VERSION 5.8 ;
BUSBITCHARS "[]" ;
DIVIDERCHAR "/" ;
UNITS
    DATABASE MICRONS 1000 ;
END UNITS

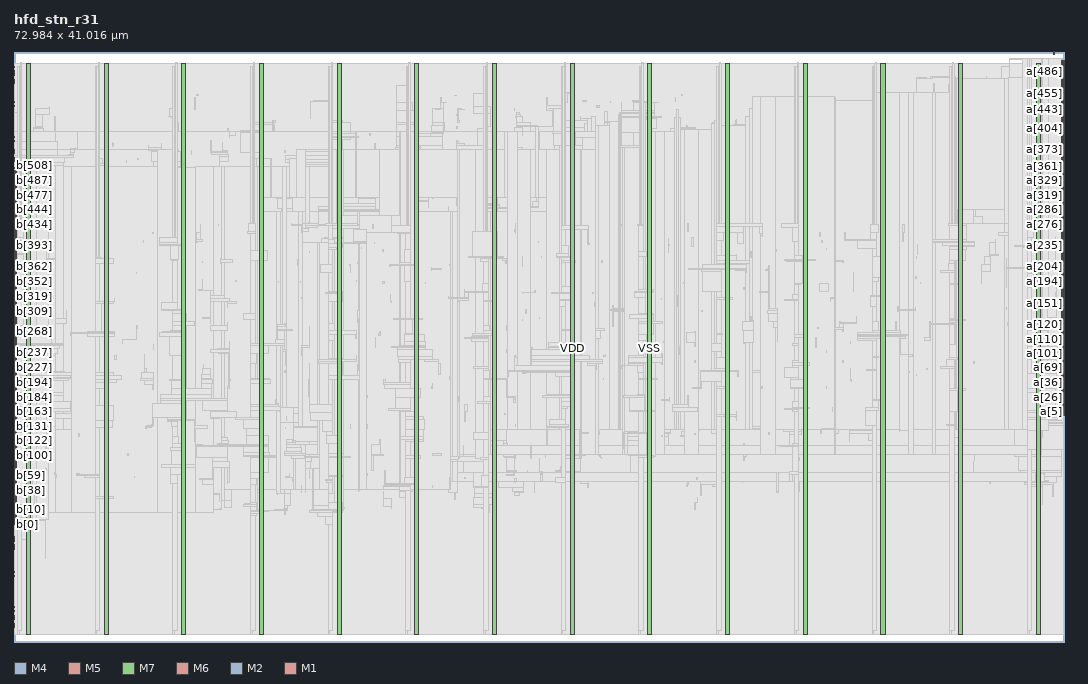
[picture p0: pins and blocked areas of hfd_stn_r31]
MACRO hfd_stn_r31
  FOREIGN hfd_stn_r31 0 0 ;
  CLASS BLOCK ;
  SIZE 72.984 BY 41.016 ;
  PIN a[0]
    DIRECTION INPUT ;
    USE SIGNAL ;
    PORT
      LAYER M4 ;
        RECT  72.792 15.744 72.984 15.768 ;
    END
  END a[0]
  PIN a[100]
    DIRECTION INPUT ;
    USE SIGNAL ;
    PORT
      LAYER M4 ;
        RECT  72.792 20.544 72.984 20.568 ;
    END
  END a[100]
  PIN a[101]
    DIRECTION INPUT ;
    USE SIGNAL ;
    PORT
      LAYER M4 ;
        RECT  72.792 20.592 72.984 20.616 ;
    END
  END a[101]
  PIN a[102]
    DIRECTION INPUT ;
    USE SIGNAL ;
    PORT
      LAYER M4 ;
        RECT  72.792 20.64 72.984 20.664 ;
    END
  END a[102]
  PIN a[103]
    DIRECTION INPUT ;
    USE SIGNAL ;
    PORT
      LAYER M4 ;
        RECT  72.792 20.688 72.984 20.712 ;
    END
  END a[103]
  PIN a[104]
    DIRECTION INPUT ;
    USE SIGNAL ;
    PORT
      LAYER M4 ;
        RECT  72.792 20.736 72.984 20.76 ;
    END
  END a[104]
  PIN a[105]
    DIRECTION INPUT ;
    USE SIGNAL ;
    PORT
      LAYER M4 ;
        RECT  72.792 20.784 72.984 20.808 ;
    END
  END a[105]
  PIN a[106]
    DIRECTION INPUT ;
    USE SIGNAL ;
    PORT
      LAYER M4 ;
        RECT  72.792 20.832 72.984 20.856 ;
    END
  END a[106]
  PIN a[107]
    DIRECTION INPUT ;
    USE SIGNAL ;
    PORT
      LAYER M4 ;
        RECT  72.792 20.88 72.984 20.904 ;
    END
  END a[107]
  PIN a[108]
    DIRECTION INPUT ;
    USE SIGNAL ;
    PORT
      LAYER M4 ;
        RECT  72.792 20.928 72.984 20.952 ;
    END
  END a[108]
  PIN a[109]
    DIRECTION INPUT ;
    USE SIGNAL ;
    PORT
      LAYER M4 ;
        RECT  72.792 20.976 72.984 21 ;
    END
  END a[109]
  PIN a[10]
    DIRECTION INPUT ;
    USE SIGNAL ;
    PORT
      LAYER M4 ;
        RECT  72.792 16.224 72.984 16.248 ;
    END
  END a[10]
  PIN a[110]
    DIRECTION INPUT ;
    USE SIGNAL ;
    PORT
      LAYER M4 ;
        RECT  72.792 21.024 72.984 21.048 ;
    END
  END a[110]
  PIN a[111]
    DIRECTION INPUT ;
    USE SIGNAL ;
    PORT
      LAYER M4 ;
        RECT  72.792 21.072 72.984 21.096 ;
    END
  END a[111]
  PIN a[112]
    DIRECTION INPUT ;
    USE SIGNAL ;
    PORT
      LAYER M4 ;
        RECT  72.792 21.12 72.984 21.144 ;
    END
  END a[112]
  PIN a[113]
    DIRECTION INPUT ;
    USE SIGNAL ;
    PORT
      LAYER M4 ;
        RECT  72.792 21.168 72.984 21.192 ;
    END
  END a[113]
  PIN a[114]
    DIRECTION INPUT ;
    USE SIGNAL ;
    PORT
      LAYER M4 ;
        RECT  72.792 21.216 72.984 21.24 ;
    END
  END a[114]
  PIN a[115]
    DIRECTION INPUT ;
    USE SIGNAL ;
    PORT
      LAYER M4 ;
        RECT  72.792 21.264 72.984 21.288 ;
    END
  END a[115]
  PIN a[116]
    DIRECTION INPUT ;
    USE SIGNAL ;
    PORT
      LAYER M4 ;
        RECT  72.792 21.312 72.984 21.336 ;
    END
  END a[116]
  PIN a[117]
    DIRECTION INPUT ;
    USE SIGNAL ;
    PORT
      LAYER M4 ;
        RECT  72.792 21.36 72.984 21.384 ;
    END
  END a[117]
  PIN a[118]
    DIRECTION INPUT ;
    USE SIGNAL ;
    PORT
      LAYER M4 ;
        RECT  72.792 21.408 72.984 21.432 ;
    END
  END a[118]
  PIN a[119]
    DIRECTION INPUT ;
    USE SIGNAL ;
    PORT
      LAYER M4 ;
        RECT  72.792 21.456 72.984 21.48 ;
    END
  END a[119]
  PIN a[11]
    DIRECTION INPUT ;
    USE SIGNAL ;
    PORT
      LAYER M4 ;
        RECT  72.792 16.272 72.984 16.296 ;
    END
  END a[11]
  PIN a[120]
    DIRECTION INPUT ;
    USE SIGNAL ;
    PORT
      LAYER M4 ;
        RECT  72.792 21.504 72.984 21.528 ;
    END
  END a[120]
  PIN a[121]
    DIRECTION INPUT ;
    USE SIGNAL ;
    PORT
      LAYER M4 ;
        RECT  72.792 21.552 72.984 21.576 ;
    END
  END a[121]
  PIN a[122]
    DIRECTION INPUT ;
    USE SIGNAL ;
    PORT
      LAYER M4 ;
        RECT  72.792 21.6 72.984 21.624 ;
    END
  END a[122]
  PIN a[123]
    DIRECTION INPUT ;
    USE SIGNAL ;
    PORT
      LAYER M4 ;
        RECT  72.792 21.648 72.984 21.672 ;
    END
  END a[123]
  PIN a[124]
    DIRECTION INPUT ;
    USE SIGNAL ;
    PORT
      LAYER M4 ;
        RECT  72.792 21.696 72.984 21.72 ;
    END
  END a[124]
  PIN a[125]
    DIRECTION INPUT ;
    USE SIGNAL ;
    PORT
      LAYER M4 ;
        RECT  72.792 21.744 72.984 21.768 ;
    END
  END a[125]
  PIN a[126]
    DIRECTION INPUT ;
    USE SIGNAL ;
    PORT
      LAYER M4 ;
        RECT  72.792 21.792 72.984 21.816 ;
    END
  END a[126]
  PIN a[127]
    DIRECTION INPUT ;
    USE SIGNAL ;
    PORT
      LAYER M4 ;
        RECT  72.792 21.84 72.984 21.864 ;
    END
  END a[127]
  PIN a[128]
    DIRECTION INPUT ;
    USE SIGNAL ;
    PORT
      LAYER M4 ;
        RECT  72.792 21.888 72.984 21.912 ;
    END
  END a[128]
  PIN a[129]
    DIRECTION INPUT ;
    USE SIGNAL ;
    PORT
      LAYER M4 ;
        RECT  72.792 21.936 72.984 21.96 ;
    END
  END a[129]
  PIN a[12]
    DIRECTION INPUT ;
    USE SIGNAL ;
    PORT
      LAYER M4 ;
        RECT  72.792 16.32 72.984 16.344 ;
    END
  END a[12]
  PIN a[130]
    DIRECTION INPUT ;
    USE SIGNAL ;
    PORT
      LAYER M4 ;
        RECT  72.792 21.984 72.984 22.008 ;
    END
  END a[130]
  PIN a[131]
    DIRECTION INPUT ;
    USE SIGNAL ;
    PORT
      LAYER M4 ;
        RECT  72.792 22.032 72.984 22.056 ;
    END
  END a[131]
  PIN a[132]
    DIRECTION INPUT ;
    USE SIGNAL ;
    PORT
      LAYER M4 ;
        RECT  72.792 22.08 72.984 22.104 ;
    END
  END a[132]
  PIN a[133]
    DIRECTION INPUT ;
    USE SIGNAL ;
    PORT
      LAYER M4 ;
        RECT  72.792 22.128 72.984 22.152 ;
    END
  END a[133]
  PIN a[134]
    DIRECTION INPUT ;
    USE SIGNAL ;
    PORT
      LAYER M4 ;
        RECT  72.792 22.176 72.984 22.2 ;
    END
  END a[134]
  PIN a[135]
    DIRECTION INPUT ;
    USE SIGNAL ;
    PORT
      LAYER M4 ;
        RECT  72.792 22.224 72.984 22.248 ;
    END
  END a[135]
  PIN a[136]
    DIRECTION INPUT ;
    USE SIGNAL ;
    PORT
      LAYER M4 ;
        RECT  72.792 22.272 72.984 22.296 ;
    END
  END a[136]
  PIN a[137]
    DIRECTION INPUT ;
    USE SIGNAL ;
    PORT
      LAYER M4 ;
        RECT  72.792 22.32 72.984 22.344 ;
    END
  END a[137]
  PIN a[138]
    DIRECTION INPUT ;
    USE SIGNAL ;
    PORT
      LAYER M4 ;
        RECT  72.792 22.368 72.984 22.392 ;
    END
  END a[138]
  PIN a[139]
    DIRECTION INPUT ;
    USE SIGNAL ;
    PORT
      LAYER M4 ;
        RECT  72.792 22.416 72.984 22.44 ;
    END
  END a[139]
  PIN a[13]
    DIRECTION INPUT ;
    USE SIGNAL ;
    PORT
      LAYER M4 ;
        RECT  72.792 16.368 72.984 16.392 ;
    END
  END a[13]
  PIN a[140]
    DIRECTION INPUT ;
    USE SIGNAL ;
    PORT
      LAYER M4 ;
        RECT  72.792 22.464 72.984 22.488 ;
    END
  END a[140]
  PIN a[141]
    DIRECTION INPUT ;
    USE SIGNAL ;
    PORT
      LAYER M4 ;
        RECT  72.792 22.512 72.984 22.536 ;
    END
  END a[141]
  PIN a[142]
    DIRECTION INPUT ;
    USE SIGNAL ;
    PORT
      LAYER M4 ;
        RECT  72.792 22.56 72.984 22.584 ;
    END
  END a[142]
  PIN a[143]
    DIRECTION INPUT ;
    USE SIGNAL ;
    PORT
      LAYER M4 ;
        RECT  72.792 22.608 72.984 22.632 ;
    END
  END a[143]
  PIN a[144]
    DIRECTION INPUT ;
    USE SIGNAL ;
    PORT
      LAYER M4 ;
        RECT  72.792 22.656 72.984 22.68 ;
    END
  END a[144]
  PIN a[145]
    DIRECTION INPUT ;
    USE SIGNAL ;
    PORT
      LAYER M4 ;
        RECT  72.792 22.704 72.984 22.728 ;
    END
  END a[145]
  PIN a[146]
    DIRECTION INPUT ;
    USE SIGNAL ;
    PORT
      LAYER M4 ;
        RECT  72.792 22.752 72.984 22.776 ;
    END
  END a[146]
  PIN a[147]
    DIRECTION INPUT ;
    USE SIGNAL ;
    PORT
      LAYER M4 ;
        RECT  72.792 22.8 72.984 22.824 ;
    END
  END a[147]
  PIN a[148]
    DIRECTION INPUT ;
    USE SIGNAL ;
    PORT
      LAYER M4 ;
        RECT  72.792 22.848 72.984 22.872 ;
    END
  END a[148]
  PIN a[149]
    DIRECTION INPUT ;
    USE SIGNAL ;
    PORT
      LAYER M4 ;
        RECT  72.792 22.896 72.984 22.92 ;
    END
  END a[149]
  PIN a[14]
    DIRECTION INPUT ;
    USE SIGNAL ;
    PORT
      LAYER M4 ;
        RECT  72.792 16.416 72.984 16.44 ;
    END
  END a[14]
  PIN a[150]
    DIRECTION INPUT ;
    USE SIGNAL ;
    PORT
      LAYER M4 ;
        RECT  72.792 22.944 72.984 22.968 ;
    END
  END a[150]
  PIN a[151]
    DIRECTION INPUT ;
    USE SIGNAL ;
    PORT
      LAYER M4 ;
        RECT  72.792 22.992 72.984 23.016 ;
    END
  END a[151]
  PIN a[152]
    DIRECTION INPUT ;
    USE SIGNAL ;
    PORT
      LAYER M4 ;
        RECT  72.792 23.04 72.984 23.064 ;
    END
  END a[152]
  PIN a[153]
    DIRECTION INPUT ;
    USE SIGNAL ;
    PORT
      LAYER M4 ;
        RECT  72.792 23.088 72.984 23.112 ;
    END
  END a[153]
  PIN a[154]
    DIRECTION INPUT ;
    USE SIGNAL ;
    PORT
      LAYER M4 ;
        RECT  72.792 23.136 72.984 23.16 ;
    END
  END a[154]
  PIN a[155]
    DIRECTION INPUT ;
    USE SIGNAL ;
    PORT
      LAYER M4 ;
        RECT  72.792 23.184 72.984 23.208 ;
    END
  END a[155]
  PIN a[156]
    DIRECTION INPUT ;
    USE SIGNAL ;
    PORT
      LAYER M4 ;
        RECT  72.792 23.232 72.984 23.256 ;
    END
  END a[156]
  PIN a[157]
    DIRECTION INPUT ;
    USE SIGNAL ;
    PORT
      LAYER M4 ;
        RECT  72.792 23.28 72.984 23.304 ;
    END
  END a[157]
  PIN a[158]
    DIRECTION INPUT ;
    USE SIGNAL ;
    PORT
      LAYER M4 ;
        RECT  72.792 23.328 72.984 23.352 ;
    END
  END a[158]
  PIN a[159]
    DIRECTION INPUT ;
    USE SIGNAL ;
    PORT
      LAYER M4 ;
        RECT  72.792 23.376 72.984 23.4 ;
    END
  END a[159]
  PIN a[15]
    DIRECTION INPUT ;
    USE SIGNAL ;
    PORT
      LAYER M4 ;
        RECT  72.792 16.464 72.984 16.488 ;
    END
  END a[15]
  PIN a[160]
    DIRECTION INPUT ;
    USE SIGNAL ;
    PORT
      LAYER M4 ;
        RECT  72.792 23.424 72.984 23.448 ;
    END
  END a[160]
  PIN a[161]
    DIRECTION INPUT ;
    USE SIGNAL ;
    PORT
      LAYER M4 ;
        RECT  72.792 23.472 72.984 23.496 ;
    END
  END a[161]
  PIN a[162]
    DIRECTION INPUT ;
    USE SIGNAL ;
    PORT
      LAYER M4 ;
        RECT  72.792 23.52 72.984 23.544 ;
    END
  END a[162]
  PIN a[163]
    DIRECTION INPUT ;
    USE SIGNAL ;
    PORT
      LAYER M4 ;
        RECT  72.792 23.568 72.984 23.592 ;
    END
  END a[163]
  PIN a[164]
    DIRECTION INPUT ;
    USE SIGNAL ;
    PORT
      LAYER M4 ;
        RECT  72.792 23.616 72.984 23.64 ;
    END
  END a[164]
  PIN a[165]
    DIRECTION INPUT ;
    USE SIGNAL ;
    PORT
      LAYER M4 ;
        RECT  72.792 23.664 72.984 23.688 ;
    END
  END a[165]
  PIN a[166]
    DIRECTION INPUT ;
    USE SIGNAL ;
    PORT
      LAYER M4 ;
        RECT  72.792 23.712 72.984 23.736 ;
    END
  END a[166]
  PIN a[167]
    DIRECTION INPUT ;
    USE SIGNAL ;
    PORT
      LAYER M4 ;
        RECT  72.792 23.76 72.984 23.784 ;
    END
  END a[167]
  PIN a[168]
    DIRECTION INPUT ;
    USE SIGNAL ;
    PORT
      LAYER M4 ;
        RECT  72.792 23.808 72.984 23.832 ;
    END
  END a[168]
  PIN a[169]
    DIRECTION INPUT ;
    USE SIGNAL ;
    PORT
      LAYER M4 ;
        RECT  72.792 23.856 72.984 23.88 ;
    END
  END a[169]
  PIN a[16]
    DIRECTION INPUT ;
    USE SIGNAL ;
    PORT
      LAYER M4 ;
        RECT  72.792 16.512 72.984 16.536 ;
    END
  END a[16]
  PIN a[170]
    DIRECTION INPUT ;
    USE SIGNAL ;
    PORT
      LAYER M4 ;
        RECT  72.792 23.904 72.984 23.928 ;
    END
  END a[170]
  PIN a[171]
    DIRECTION INPUT ;
    USE SIGNAL ;
    PORT
      LAYER M4 ;
        RECT  72.792 23.952 72.984 23.976 ;
    END
  END a[171]
  PIN a[172]
    DIRECTION INPUT ;
    USE SIGNAL ;
    PORT
      LAYER M4 ;
        RECT  72.792 24 72.984 24.024 ;
    END
  END a[172]
  PIN a[173]
    DIRECTION INPUT ;
    USE SIGNAL ;
    PORT
      LAYER M4 ;
        RECT  72.792 24.048 72.984 24.072 ;
    END
  END a[173]
  PIN a[174]
    DIRECTION INPUT ;
    USE SIGNAL ;
    PORT
      LAYER M4 ;
        RECT  72.792 24.096 72.984 24.12 ;
    END
  END a[174]
  PIN a[175]
    DIRECTION INPUT ;
    USE SIGNAL ;
    PORT
      LAYER M4 ;
        RECT  72.792 24.144 72.984 24.168 ;
    END
  END a[175]
  PIN a[176]
    DIRECTION INPUT ;
    USE SIGNAL ;
    PORT
      LAYER M4 ;
        RECT  72.792 24.192 72.984 24.216 ;
    END
  END a[176]
  PIN a[177]
    DIRECTION INPUT ;
    USE SIGNAL ;
    PORT
      LAYER M4 ;
        RECT  72.792 24.24 72.984 24.264 ;
    END
  END a[177]
  PIN a[178]
    DIRECTION INPUT ;
    USE SIGNAL ;
    PORT
      LAYER M4 ;
        RECT  72.792 24.288 72.984 24.312 ;
    END
  END a[178]
  PIN a[179]
    DIRECTION INPUT ;
    USE SIGNAL ;
    PORT
      LAYER M4 ;
        RECT  72.792 24.336 72.984 24.36 ;
    END
  END a[179]
  PIN a[17]
    DIRECTION INPUT ;
    USE SIGNAL ;
    PORT
      LAYER M4 ;
        RECT  72.792 16.56 72.984 16.584 ;
    END
  END a[17]
  PIN a[180]
    DIRECTION INPUT ;
    USE SIGNAL ;
    PORT
      LAYER M4 ;
        RECT  72.792 24.384 72.984 24.408 ;
    END
  END a[180]
  PIN a[181]
    DIRECTION INPUT ;
    USE SIGNAL ;
    PORT
      LAYER M4 ;
        RECT  72.792 24.432 72.984 24.456 ;
    END
  END a[181]
  PIN a[182]
    DIRECTION INPUT ;
    USE SIGNAL ;
    PORT
      LAYER M4 ;
        RECT  72.792 24.48 72.984 24.504 ;
    END
  END a[182]
  PIN a[183]
    DIRECTION INPUT ;
    USE SIGNAL ;
    PORT
      LAYER M4 ;
        RECT  72.792 24.528 72.984 24.552 ;
    END
  END a[183]
  PIN a[184]
    DIRECTION INPUT ;
    USE SIGNAL ;
    PORT
      LAYER M4 ;
        RECT  72.792 24.576 72.984 24.6 ;
    END
  END a[184]
  PIN a[185]
    DIRECTION INPUT ;
    USE SIGNAL ;
    PORT
      LAYER M4 ;
        RECT  72.792 24.624 72.984 24.648 ;
    END
  END a[185]
  PIN a[186]
    DIRECTION INPUT ;
    USE SIGNAL ;
    PORT
      LAYER M4 ;
        RECT  72.792 24.672 72.984 24.696 ;
    END
  END a[186]
  PIN a[187]
    DIRECTION INPUT ;
    USE SIGNAL ;
    PORT
      LAYER M4 ;
        RECT  72.792 24.72 72.984 24.744 ;
    END
  END a[187]
  PIN a[188]
    DIRECTION INPUT ;
    USE SIGNAL ;
    PORT
      LAYER M4 ;
        RECT  72.792 24.768 72.984 24.792 ;
    END
  END a[188]
  PIN a[189]
    DIRECTION INPUT ;
    USE SIGNAL ;
    PORT
      LAYER M4 ;
        RECT  72.792 24.816 72.984 24.84 ;
    END
  END a[189]
  PIN a[18]
    DIRECTION INPUT ;
    USE SIGNAL ;
    PORT
      LAYER M4 ;
        RECT  72.792 16.608 72.984 16.632 ;
    END
  END a[18]
  PIN a[190]
    DIRECTION INPUT ;
    USE SIGNAL ;
    PORT
      LAYER M4 ;
        RECT  72.792 24.864 72.984 24.888 ;
    END
  END a[190]
  PIN a[191]
    DIRECTION INPUT ;
    USE SIGNAL ;
    PORT
      LAYER M4 ;
        RECT  72.792 24.912 72.984 24.936 ;
    END
  END a[191]
  PIN a[192]
    DIRECTION INPUT ;
    USE SIGNAL ;
    PORT
      LAYER M4 ;
        RECT  72.792 24.96 72.984 24.984 ;
    END
  END a[192]
  PIN a[193]
    DIRECTION INPUT ;
    USE SIGNAL ;
    PORT
      LAYER M4 ;
        RECT  72.792 25.008 72.984 25.032 ;
    END
  END a[193]
  PIN a[194]
    DIRECTION INPUT ;
    USE SIGNAL ;
    PORT
      LAYER M4 ;
        RECT  72.792 25.056 72.984 25.08 ;
    END
  END a[194]
  PIN a[195]
    DIRECTION INPUT ;
    USE SIGNAL ;
    PORT
      LAYER M4 ;
        RECT  72.792 25.104 72.984 25.128 ;
    END
  END a[195]
  PIN a[196]
    DIRECTION INPUT ;
    USE SIGNAL ;
    PORT
      LAYER M4 ;
        RECT  72.792 25.152 72.984 25.176 ;
    END
  END a[196]
  PIN a[197]
    DIRECTION INPUT ;
    USE SIGNAL ;
    PORT
      LAYER M4 ;
        RECT  72.792 25.2 72.984 25.224 ;
    END
  END a[197]
  PIN a[198]
    DIRECTION INPUT ;
    USE SIGNAL ;
    PORT
      LAYER M4 ;
        RECT  72.792 25.248 72.984 25.272 ;
    END
  END a[198]
  PIN a[199]
    DIRECTION INPUT ;
    USE SIGNAL ;
    PORT
      LAYER M4 ;
        RECT  72.792 25.296 72.984 25.32 ;
    END
  END a[199]
  PIN a[19]
    DIRECTION INPUT ;
    USE SIGNAL ;
    PORT
      LAYER M4 ;
        RECT  72.792 16.656 72.984 16.68 ;
    END
  END a[19]
  PIN a[1]
    DIRECTION INPUT ;
    USE SIGNAL ;
    PORT
      LAYER M4 ;
        RECT  72.792 15.792 72.984 15.816 ;
    END
  END a[1]
  PIN a[200]
    DIRECTION INPUT ;
    USE SIGNAL ;
    PORT
      LAYER M4 ;
        RECT  72.792 25.344 72.984 25.368 ;
    END
  END a[200]
  PIN a[201]
    DIRECTION INPUT ;
    USE SIGNAL ;
    PORT
      LAYER M4 ;
        RECT  72.792 25.392 72.984 25.416 ;
    END
  END a[201]
  PIN a[202]
    DIRECTION INPUT ;
    USE SIGNAL ;
    PORT
      LAYER M4 ;
        RECT  72.792 25.44 72.984 25.464 ;
    END
  END a[202]
  PIN a[203]
    DIRECTION INPUT ;
    USE SIGNAL ;
    PORT
      LAYER M4 ;
        RECT  72.792 25.488 72.984 25.512 ;
    END
  END a[203]
  PIN a[204]
    DIRECTION INPUT ;
    USE SIGNAL ;
    PORT
      LAYER M4 ;
        RECT  72.792 25.536 72.984 25.56 ;
    END
  END a[204]
  PIN a[205]
    DIRECTION INPUT ;
    USE SIGNAL ;
    PORT
      LAYER M4 ;
        RECT  72.792 25.584 72.984 25.608 ;
    END
  END a[205]
  PIN a[206]
    DIRECTION INPUT ;
    USE SIGNAL ;
    PORT
      LAYER M4 ;
        RECT  72.792 25.632 72.984 25.656 ;
    END
  END a[206]
  PIN a[207]
    DIRECTION INPUT ;
    USE SIGNAL ;
    PORT
      LAYER M4 ;
        RECT  72.792 25.68 72.984 25.704 ;
    END
  END a[207]
  PIN a[208]
    DIRECTION INPUT ;
    USE SIGNAL ;
    PORT
      LAYER M4 ;
        RECT  72.792 25.728 72.984 25.752 ;
    END
  END a[208]
  PIN a[209]
    DIRECTION INPUT ;
    USE SIGNAL ;
    PORT
      LAYER M4 ;
        RECT  72.792 25.776 72.984 25.8 ;
    END
  END a[209]
  PIN a[20]
    DIRECTION INPUT ;
    USE SIGNAL ;
    PORT
      LAYER M4 ;
        RECT  72.792 16.704 72.984 16.728 ;
    END
  END a[20]
  PIN a[210]
    DIRECTION INPUT ;
    USE SIGNAL ;
    PORT
      LAYER M4 ;
        RECT  72.792 25.824 72.984 25.848 ;
    END
  END a[210]
  PIN a[211]
    DIRECTION INPUT ;
    USE SIGNAL ;
    PORT
      LAYER M4 ;
        RECT  72.792 25.872 72.984 25.896 ;
    END
  END a[211]
  PIN a[212]
    DIRECTION INPUT ;
    USE SIGNAL ;
    PORT
      LAYER M4 ;
        RECT  72.792 25.92 72.984 25.944 ;
    END
  END a[212]
  PIN a[213]
    DIRECTION INPUT ;
    USE SIGNAL ;
    PORT
      LAYER M4 ;
        RECT  72.792 25.968 72.984 25.992 ;
    END
  END a[213]
  PIN a[214]
    DIRECTION INPUT ;
    USE SIGNAL ;
    PORT
      LAYER M4 ;
        RECT  72.792 26.016 72.984 26.04 ;
    END
  END a[214]
  PIN a[215]
    DIRECTION INPUT ;
    USE SIGNAL ;
    PORT
      LAYER M4 ;
        RECT  72.792 26.064 72.984 26.088 ;
    END
  END a[215]
  PIN a[216]
    DIRECTION INPUT ;
    USE SIGNAL ;
    PORT
      LAYER M4 ;
        RECT  72.792 26.112 72.984 26.136 ;
    END
  END a[216]
  PIN a[217]
    DIRECTION INPUT ;
    USE SIGNAL ;
    PORT
      LAYER M4 ;
        RECT  72.792 26.16 72.984 26.184 ;
    END
  END a[217]
  PIN a[218]
    DIRECTION INPUT ;
    USE SIGNAL ;
    PORT
      LAYER M4 ;
        RECT  72.792 26.208 72.984 26.232 ;
    END
  END a[218]
  PIN a[219]
    DIRECTION INPUT ;
    USE SIGNAL ;
    PORT
      LAYER M4 ;
        RECT  72.792 26.256 72.984 26.28 ;
    END
  END a[219]
  PIN a[21]
    DIRECTION INPUT ;
    USE SIGNAL ;
    PORT
      LAYER M4 ;
        RECT  72.792 16.752 72.984 16.776 ;
    END
  END a[21]
  PIN a[220]
    DIRECTION INPUT ;
    USE SIGNAL ;
    PORT
      LAYER M4 ;
        RECT  72.792 26.304 72.984 26.328 ;
    END
  END a[220]
  PIN a[221]
    DIRECTION INPUT ;
    USE SIGNAL ;
    PORT
      LAYER M4 ;
        RECT  72.792 26.352 72.984 26.376 ;
    END
  END a[221]
  PIN a[222]
    DIRECTION INPUT ;
    USE SIGNAL ;
    PORT
      LAYER M4 ;
        RECT  72.792 26.4 72.984 26.424 ;
    END
  END a[222]
  PIN a[223]
    DIRECTION INPUT ;
    USE SIGNAL ;
    PORT
      LAYER M4 ;
        RECT  72.792 26.448 72.984 26.472 ;
    END
  END a[223]
  PIN a[224]
    DIRECTION INPUT ;
    USE SIGNAL ;
    PORT
      LAYER M4 ;
        RECT  72.792 26.496 72.984 26.52 ;
    END
  END a[224]
  PIN a[225]
    DIRECTION INPUT ;
    USE SIGNAL ;
    PORT
      LAYER M4 ;
        RECT  72.792 26.544 72.984 26.568 ;
    END
  END a[225]
  PIN a[226]
    DIRECTION INPUT ;
    USE SIGNAL ;
    PORT
      LAYER M4 ;
        RECT  72.792 26.592 72.984 26.616 ;
    END
  END a[226]
  PIN a[227]
    DIRECTION INPUT ;
    USE SIGNAL ;
    PORT
      LAYER M4 ;
        RECT  72.792 26.64 72.984 26.664 ;
    END
  END a[227]
  PIN a[228]
    DIRECTION INPUT ;
    USE SIGNAL ;
    PORT
      LAYER M4 ;
        RECT  72.792 26.688 72.984 26.712 ;
    END
  END a[228]
  PIN a[229]
    DIRECTION INPUT ;
    USE SIGNAL ;
    PORT
      LAYER M4 ;
        RECT  72.792 26.736 72.984 26.76 ;
    END
  END a[229]
  PIN a[22]
    DIRECTION INPUT ;
    USE SIGNAL ;
    PORT
      LAYER M4 ;
        RECT  72.792 16.8 72.984 16.824 ;
    END
  END a[22]
  PIN a[230]
    DIRECTION INPUT ;
    USE SIGNAL ;
    PORT
      LAYER M4 ;
        RECT  72.792 26.784 72.984 26.808 ;
    END
  END a[230]
  PIN a[231]
    DIRECTION INPUT ;
    USE SIGNAL ;
    PORT
      LAYER M4 ;
        RECT  72.792 26.832 72.984 26.856 ;
    END
  END a[231]
  PIN a[232]
    DIRECTION INPUT ;
    USE SIGNAL ;
    PORT
      LAYER M4 ;
        RECT  72.792 26.88 72.984 26.904 ;
    END
  END a[232]
  PIN a[233]
    DIRECTION INPUT ;
    USE SIGNAL ;
    PORT
      LAYER M4 ;
        RECT  72.792 26.928 72.984 26.952 ;
    END
  END a[233]
  PIN a[234]
    DIRECTION INPUT ;
    USE SIGNAL ;
    PORT
      LAYER M4 ;
        RECT  72.792 26.976 72.984 27 ;
    END
  END a[234]
  PIN a[235]
    DIRECTION INPUT ;
    USE SIGNAL ;
    PORT
      LAYER M4 ;
        RECT  72.792 27.024 72.984 27.048 ;
    END
  END a[235]
  PIN a[236]
    DIRECTION INPUT ;
    USE SIGNAL ;
    PORT
      LAYER M4 ;
        RECT  72.792 27.072 72.984 27.096 ;
    END
  END a[236]
  PIN a[237]
    DIRECTION INPUT ;
    USE SIGNAL ;
    PORT
      LAYER M4 ;
        RECT  72.792 27.12 72.984 27.144 ;
    END
  END a[237]
  PIN a[238]
    DIRECTION INPUT ;
    USE SIGNAL ;
    PORT
      LAYER M4 ;
        RECT  72.792 27.168 72.984 27.192 ;
    END
  END a[238]
  PIN a[239]
    DIRECTION INPUT ;
    USE SIGNAL ;
    PORT
      LAYER M4 ;
        RECT  72.792 27.216 72.984 27.24 ;
    END
  END a[239]
  PIN a[23]
    DIRECTION INPUT ;
    USE SIGNAL ;
    PORT
      LAYER M4 ;
        RECT  72.792 16.848 72.984 16.872 ;
    END
  END a[23]
  PIN a[240]
    DIRECTION INPUT ;
    USE SIGNAL ;
    PORT
      LAYER M4 ;
        RECT  72.792 27.264 72.984 27.288 ;
    END
  END a[240]
  PIN a[241]
    DIRECTION INPUT ;
    USE SIGNAL ;
    PORT
      LAYER M4 ;
        RECT  72.792 27.312 72.984 27.336 ;
    END
  END a[241]
  PIN a[242]
    DIRECTION INPUT ;
    USE SIGNAL ;
    PORT
      LAYER M4 ;
        RECT  72.792 27.36 72.984 27.384 ;
    END
  END a[242]
  PIN a[243]
    DIRECTION INPUT ;
    USE SIGNAL ;
    PORT
      LAYER M4 ;
        RECT  72.792 27.408 72.984 27.432 ;
    END
  END a[243]
  PIN a[244]
    DIRECTION INPUT ;
    USE SIGNAL ;
    PORT
      LAYER M4 ;
        RECT  72.792 27.456 72.984 27.48 ;
    END
  END a[244]
  PIN a[245]
    DIRECTION INPUT ;
    USE SIGNAL ;
    PORT
      LAYER M4 ;
        RECT  72.792 27.504 72.984 27.528 ;
    END
  END a[245]
  PIN a[246]
    DIRECTION INPUT ;
    USE SIGNAL ;
    PORT
      LAYER M4 ;
        RECT  72.792 27.552 72.984 27.576 ;
    END
  END a[246]
  PIN a[247]
    DIRECTION INPUT ;
    USE SIGNAL ;
    PORT
      LAYER M4 ;
        RECT  72.792 27.6 72.984 27.624 ;
    END
  END a[247]
  PIN a[248]
    DIRECTION INPUT ;
    USE SIGNAL ;
    PORT
      LAYER M4 ;
        RECT  72.792 27.648 72.984 27.672 ;
    END
  END a[248]
  PIN a[249]
    DIRECTION INPUT ;
    USE SIGNAL ;
    PORT
      LAYER M4 ;
        RECT  72.792 27.696 72.984 27.72 ;
    END
  END a[249]
  PIN a[24]
    DIRECTION INPUT ;
    USE SIGNAL ;
    PORT
      LAYER M4 ;
        RECT  72.792 16.896 72.984 16.92 ;
    END
  END a[24]
  PIN a[250]
    DIRECTION INPUT ;
    USE SIGNAL ;
    PORT
      LAYER M4 ;
        RECT  72.792 27.744 72.984 27.768 ;
    END
  END a[250]
  PIN a[251]
    DIRECTION INPUT ;
    USE SIGNAL ;
    PORT
      LAYER M4 ;
        RECT  72.792 27.792 72.984 27.816 ;
    END
  END a[251]
  PIN a[252]
    DIRECTION INPUT ;
    USE SIGNAL ;
    PORT
      LAYER M4 ;
        RECT  72.792 27.84 72.984 27.864 ;
    END
  END a[252]
  PIN a[253]
    DIRECTION INPUT ;
    USE SIGNAL ;
    PORT
      LAYER M4 ;
        RECT  72.792 27.888 72.984 27.912 ;
    END
  END a[253]
  PIN a[254]
    DIRECTION INPUT ;
    USE SIGNAL ;
    PORT
      LAYER M4 ;
        RECT  72.792 27.936 72.984 27.96 ;
    END
  END a[254]
  PIN a[255]
    DIRECTION INPUT ;
    USE SIGNAL ;
    PORT
      LAYER M4 ;
        RECT  72.792 27.984 72.984 28.008 ;
    END
  END a[255]
  PIN a[256]
    DIRECTION OUTPUT ;
    USE SIGNAL ;
    PORT
      LAYER M4 ;
        RECT  72.792 28.032 72.984 28.056 ;
    END
  END a[256]
  PIN a[257]
    DIRECTION OUTPUT ;
    USE SIGNAL ;
    PORT
      LAYER M4 ;
        RECT  72.792 28.08 72.984 28.104 ;
    END
  END a[257]
  PIN a[258]
    DIRECTION OUTPUT ;
    USE SIGNAL ;
    PORT
      LAYER M4 ;
        RECT  72.792 28.128 72.984 28.152 ;
    END
  END a[258]
  PIN a[259]
    DIRECTION OUTPUT ;
    USE SIGNAL ;
    PORT
      LAYER M4 ;
        RECT  72.792 28.176 72.984 28.2 ;
    END
  END a[259]
  PIN a[25]
    DIRECTION INPUT ;
    USE SIGNAL ;
    PORT
      LAYER M4 ;
        RECT  72.792 16.944 72.984 16.968 ;
    END
  END a[25]
  PIN a[260]
    DIRECTION OUTPUT ;
    USE SIGNAL ;
    PORT
      LAYER M4 ;
        RECT  72.792 28.224 72.984 28.248 ;
    END
  END a[260]
  PIN a[261]
    DIRECTION OUTPUT ;
    USE SIGNAL ;
    PORT
      LAYER M4 ;
        RECT  72.792 28.272 72.984 28.296 ;
    END
  END a[261]
  PIN a[262]
    DIRECTION OUTPUT ;
    USE SIGNAL ;
    PORT
      LAYER M4 ;
        RECT  72.792 28.32 72.984 28.344 ;
    END
  END a[262]
  PIN a[263]
    DIRECTION OUTPUT ;
    USE SIGNAL ;
    PORT
      LAYER M4 ;
        RECT  72.792 28.368 72.984 28.392 ;
    END
  END a[263]
  PIN a[264]
    DIRECTION OUTPUT ;
    USE SIGNAL ;
    PORT
      LAYER M4 ;
        RECT  72.792 28.416 72.984 28.44 ;
    END
  END a[264]
  PIN a[265]
    DIRECTION OUTPUT ;
    USE SIGNAL ;
    PORT
      LAYER M4 ;
        RECT  72.792 28.464 72.984 28.488 ;
    END
  END a[265]
  PIN a[266]
    DIRECTION OUTPUT ;
    USE SIGNAL ;
    PORT
      LAYER M4 ;
        RECT  72.792 28.512 72.984 28.536 ;
    END
  END a[266]
  PIN a[267]
    DIRECTION OUTPUT ;
    USE SIGNAL ;
    PORT
      LAYER M4 ;
        RECT  72.792 28.56 72.984 28.584 ;
    END
  END a[267]
  PIN a[268]
    DIRECTION OUTPUT ;
    USE SIGNAL ;
    PORT
      LAYER M4 ;
        RECT  72.792 28.608 72.984 28.632 ;
    END
  END a[268]
  PIN a[269]
    DIRECTION OUTPUT ;
    USE SIGNAL ;
    PORT
      LAYER M4 ;
        RECT  72.792 28.656 72.984 28.68 ;
    END
  END a[269]
  PIN a[26]
    DIRECTION INPUT ;
    USE SIGNAL ;
    PORT
      LAYER M4 ;
        RECT  72.792 16.992 72.984 17.016 ;
    END
  END a[26]
  PIN a[270]
    DIRECTION OUTPUT ;
    USE SIGNAL ;
    PORT
      LAYER M4 ;
        RECT  72.792 28.704 72.984 28.728 ;
    END
  END a[270]
  PIN a[271]
    DIRECTION OUTPUT ;
    USE SIGNAL ;
    PORT
      LAYER M4 ;
        RECT  72.792 28.752 72.984 28.776 ;
    END
  END a[271]
  PIN a[272]
    DIRECTION OUTPUT ;
    USE SIGNAL ;
    PORT
      LAYER M4 ;
        RECT  72.792 28.8 72.984 28.824 ;
    END
  END a[272]
  PIN a[273]
    DIRECTION OUTPUT ;
    USE SIGNAL ;
    PORT
      LAYER M4 ;
        RECT  72.792 28.848 72.984 28.872 ;
    END
  END a[273]
  PIN a[274]
    DIRECTION OUTPUT ;
    USE SIGNAL ;
    PORT
      LAYER M4 ;
        RECT  72.792 28.896 72.984 28.92 ;
    END
  END a[274]
  PIN a[275]
    DIRECTION OUTPUT ;
    USE SIGNAL ;
    PORT
      LAYER M4 ;
        RECT  72.792 28.944 72.984 28.968 ;
    END
  END a[275]
  PIN a[276]
    DIRECTION OUTPUT ;
    USE SIGNAL ;
    PORT
      LAYER M4 ;
        RECT  72.792 28.992 72.984 29.016 ;
    END
  END a[276]
  PIN a[277]
    DIRECTION OUTPUT ;
    USE SIGNAL ;
    PORT
      LAYER M4 ;
        RECT  72.792 29.04 72.984 29.064 ;
    END
  END a[277]
  PIN a[278]
    DIRECTION OUTPUT ;
    USE SIGNAL ;
    PORT
      LAYER M4 ;
        RECT  72.792 29.088 72.984 29.112 ;
    END
  END a[278]
  PIN a[279]
    DIRECTION OUTPUT ;
    USE SIGNAL ;
    PORT
      LAYER M4 ;
        RECT  72.792 29.136 72.984 29.16 ;
    END
  END a[279]
  PIN a[27]
    DIRECTION INPUT ;
    USE SIGNAL ;
    PORT
      LAYER M4 ;
        RECT  72.792 17.04 72.984 17.064 ;
    END
  END a[27]
  PIN a[280]
    DIRECTION OUTPUT ;
    USE SIGNAL ;
    PORT
      LAYER M4 ;
        RECT  72.792 29.184 72.984 29.208 ;
    END
  END a[280]
  PIN a[281]
    DIRECTION OUTPUT ;
    USE SIGNAL ;
    PORT
      LAYER M4 ;
        RECT  72.792 29.232 72.984 29.256 ;
    END
  END a[281]
  PIN a[282]
    DIRECTION OUTPUT ;
    USE SIGNAL ;
    PORT
      LAYER M4 ;
        RECT  72.792 29.28 72.984 29.304 ;
    END
  END a[282]
  PIN a[283]
    DIRECTION OUTPUT ;
    USE SIGNAL ;
    PORT
      LAYER M4 ;
        RECT  72.792 29.328 72.984 29.352 ;
    END
  END a[283]
  PIN a[284]
    DIRECTION OUTPUT ;
    USE SIGNAL ;
    PORT
      LAYER M4 ;
        RECT  72.792 29.376 72.984 29.4 ;
    END
  END a[284]
  PIN a[285]
    DIRECTION OUTPUT ;
    USE SIGNAL ;
    PORT
      LAYER M4 ;
        RECT  72.792 29.424 72.984 29.448 ;
    END
  END a[285]
  PIN a[286]
    DIRECTION OUTPUT ;
    USE SIGNAL ;
    PORT
      LAYER M4 ;
        RECT  72.792 29.472 72.984 29.496 ;
    END
  END a[286]
  PIN a[287]
    DIRECTION OUTPUT ;
    USE SIGNAL ;
    PORT
      LAYER M4 ;
        RECT  72.792 29.52 72.984 29.544 ;
    END
  END a[287]
  PIN a[288]
    DIRECTION OUTPUT ;
    USE SIGNAL ;
    PORT
      LAYER M4 ;
        RECT  72.792 29.568 72.984 29.592 ;
    END
  END a[288]
  PIN a[289]
    DIRECTION OUTPUT ;
    USE SIGNAL ;
    PORT
      LAYER M4 ;
        RECT  72.792 29.616 72.984 29.64 ;
    END
  END a[289]
  PIN a[28]
    DIRECTION INPUT ;
    USE SIGNAL ;
    PORT
      LAYER M4 ;
        RECT  72.792 17.088 72.984 17.112 ;
    END
  END a[28]
  PIN a[290]
    DIRECTION OUTPUT ;
    USE SIGNAL ;
    PORT
      LAYER M4 ;
        RECT  72.792 29.664 72.984 29.688 ;
    END
  END a[290]
  PIN a[291]
    DIRECTION OUTPUT ;
    USE SIGNAL ;
    PORT
      LAYER M4 ;
        RECT  72.792 29.712 72.984 29.736 ;
    END
  END a[291]
  PIN a[292]
    DIRECTION OUTPUT ;
    USE SIGNAL ;
    PORT
      LAYER M4 ;
        RECT  72.792 29.76 72.984 29.784 ;
    END
  END a[292]
  PIN a[293]
    DIRECTION OUTPUT ;
    USE SIGNAL ;
    PORT
      LAYER M4 ;
        RECT  72.792 29.808 72.984 29.832 ;
    END
  END a[293]
  PIN a[294]
    DIRECTION OUTPUT ;
    USE SIGNAL ;
    PORT
      LAYER M4 ;
        RECT  72.792 29.856 72.984 29.88 ;
    END
  END a[294]
  PIN a[295]
    DIRECTION OUTPUT ;
    USE SIGNAL ;
    PORT
      LAYER M4 ;
        RECT  72.792 29.904 72.984 29.928 ;
    END
  END a[295]
  PIN a[296]
    DIRECTION OUTPUT ;
    USE SIGNAL ;
    PORT
      LAYER M4 ;
        RECT  72.792 29.952 72.984 29.976 ;
    END
  END a[296]
  PIN a[297]
    DIRECTION OUTPUT ;
    USE SIGNAL ;
    PORT
      LAYER M4 ;
        RECT  72.792 30 72.984 30.024 ;
    END
  END a[297]
  PIN a[298]
    DIRECTION OUTPUT ;
    USE SIGNAL ;
    PORT
      LAYER M4 ;
        RECT  72.792 30.048 72.984 30.072 ;
    END
  END a[298]
  PIN a[299]
    DIRECTION OUTPUT ;
    USE SIGNAL ;
    PORT
      LAYER M4 ;
        RECT  72.792 30.096 72.984 30.12 ;
    END
  END a[299]
  PIN a[29]
    DIRECTION INPUT ;
    USE SIGNAL ;
    PORT
      LAYER M4 ;
        RECT  72.792 17.136 72.984 17.16 ;
    END
  END a[29]
  PIN a[2]
    DIRECTION INPUT ;
    USE SIGNAL ;
    PORT
      LAYER M4 ;
        RECT  72.792 15.84 72.984 15.864 ;
    END
  END a[2]
  PIN a[300]
    DIRECTION OUTPUT ;
    USE SIGNAL ;
    PORT
      LAYER M4 ;
        RECT  72.792 30.144 72.984 30.168 ;
    END
  END a[300]
  PIN a[301]
    DIRECTION OUTPUT ;
    USE SIGNAL ;
    PORT
      LAYER M4 ;
        RECT  72.792 30.192 72.984 30.216 ;
    END
  END a[301]
  PIN a[302]
    DIRECTION OUTPUT ;
    USE SIGNAL ;
    PORT
      LAYER M4 ;
        RECT  72.792 30.24 72.984 30.264 ;
    END
  END a[302]
  PIN a[303]
    DIRECTION OUTPUT ;
    USE SIGNAL ;
    PORT
      LAYER M4 ;
        RECT  72.792 30.288 72.984 30.312 ;
    END
  END a[303]
  PIN a[304]
    DIRECTION OUTPUT ;
    USE SIGNAL ;
    PORT
      LAYER M4 ;
        RECT  72.792 30.336 72.984 30.36 ;
    END
  END a[304]
  PIN a[305]
    DIRECTION OUTPUT ;
    USE SIGNAL ;
    PORT
      LAYER M4 ;
        RECT  72.792 30.384 72.984 30.408 ;
    END
  END a[305]
  PIN a[306]
    DIRECTION OUTPUT ;
    USE SIGNAL ;
    PORT
      LAYER M4 ;
        RECT  72.792 30.432 72.984 30.456 ;
    END
  END a[306]
  PIN a[307]
    DIRECTION OUTPUT ;
    USE SIGNAL ;
    PORT
      LAYER M4 ;
        RECT  72.792 30.48 72.984 30.504 ;
    END
  END a[307]
  PIN a[308]
    DIRECTION OUTPUT ;
    USE SIGNAL ;
    PORT
      LAYER M4 ;
        RECT  72.792 30.528 72.984 30.552 ;
    END
  END a[308]
  PIN a[309]
    DIRECTION OUTPUT ;
    USE SIGNAL ;
    PORT
      LAYER M4 ;
        RECT  72.792 30.576 72.984 30.6 ;
    END
  END a[309]
  PIN a[30]
    DIRECTION INPUT ;
    USE SIGNAL ;
    PORT
      LAYER M4 ;
        RECT  72.792 17.184 72.984 17.208 ;
    END
  END a[30]
  PIN a[310]
    DIRECTION OUTPUT ;
    USE SIGNAL ;
    PORT
      LAYER M4 ;
        RECT  72.792 30.624 72.984 30.648 ;
    END
  END a[310]
  PIN a[311]
    DIRECTION OUTPUT ;
    USE SIGNAL ;
    PORT
      LAYER M4 ;
        RECT  72.792 30.672 72.984 30.696 ;
    END
  END a[311]
  PIN a[312]
    DIRECTION OUTPUT ;
    USE SIGNAL ;
    PORT
      LAYER M4 ;
        RECT  72.792 30.72 72.984 30.744 ;
    END
  END a[312]
  PIN a[313]
    DIRECTION OUTPUT ;
    USE SIGNAL ;
    PORT
      LAYER M4 ;
        RECT  72.792 30.768 72.984 30.792 ;
    END
  END a[313]
  PIN a[314]
    DIRECTION OUTPUT ;
    USE SIGNAL ;
    PORT
      LAYER M4 ;
        RECT  72.792 30.816 72.984 30.84 ;
    END
  END a[314]
  PIN a[315]
    DIRECTION OUTPUT ;
    USE SIGNAL ;
    PORT
      LAYER M4 ;
        RECT  72.792 30.864 72.984 30.888 ;
    END
  END a[315]
  PIN a[316]
    DIRECTION OUTPUT ;
    USE SIGNAL ;
    PORT
      LAYER M4 ;
        RECT  72.792 30.912 72.984 30.936 ;
    END
  END a[316]
  PIN a[317]
    DIRECTION OUTPUT ;
    USE SIGNAL ;
    PORT
      LAYER M4 ;
        RECT  72.792 30.96 72.984 30.984 ;
    END
  END a[317]
  PIN a[318]
    DIRECTION OUTPUT ;
    USE SIGNAL ;
    PORT
      LAYER M4 ;
        RECT  72.792 31.008 72.984 31.032 ;
    END
  END a[318]
  PIN a[319]
    DIRECTION OUTPUT ;
    USE SIGNAL ;
    PORT
      LAYER M4 ;
        RECT  72.792 31.056 72.984 31.08 ;
    END
  END a[319]
  PIN a[31]
    DIRECTION INPUT ;
    USE SIGNAL ;
    PORT
      LAYER M4 ;
        RECT  72.792 17.232 72.984 17.256 ;
    END
  END a[31]
  PIN a[320]
    DIRECTION OUTPUT ;
    USE SIGNAL ;
    PORT
      LAYER M4 ;
        RECT  72.792 31.104 72.984 31.128 ;
    END
  END a[320]
  PIN a[321]
    DIRECTION OUTPUT ;
    USE SIGNAL ;
    PORT
      LAYER M4 ;
        RECT  72.792 31.152 72.984 31.176 ;
    END
  END a[321]
  PIN a[322]
    DIRECTION OUTPUT ;
    USE SIGNAL ;
    PORT
      LAYER M4 ;
        RECT  72.792 31.2 72.984 31.224 ;
    END
  END a[322]
  PIN a[323]
    DIRECTION OUTPUT ;
    USE SIGNAL ;
    PORT
      LAYER M4 ;
        RECT  72.792 31.248 72.984 31.272 ;
    END
  END a[323]
  PIN a[324]
    DIRECTION OUTPUT ;
    USE SIGNAL ;
    PORT
      LAYER M4 ;
        RECT  72.792 31.296 72.984 31.32 ;
    END
  END a[324]
  PIN a[325]
    DIRECTION OUTPUT ;
    USE SIGNAL ;
    PORT
      LAYER M4 ;
        RECT  72.792 31.344 72.984 31.368 ;
    END
  END a[325]
  PIN a[326]
    DIRECTION OUTPUT ;
    USE SIGNAL ;
    PORT
      LAYER M4 ;
        RECT  72.792 31.392 72.984 31.416 ;
    END
  END a[326]
  PIN a[327]
    DIRECTION OUTPUT ;
    USE SIGNAL ;
    PORT
      LAYER M4 ;
        RECT  72.792 31.44 72.984 31.464 ;
    END
  END a[327]
  PIN a[328]
    DIRECTION OUTPUT ;
    USE SIGNAL ;
    PORT
      LAYER M4 ;
        RECT  72.792 31.488 72.984 31.512 ;
    END
  END a[328]
  PIN a[329]
    DIRECTION OUTPUT ;
    USE SIGNAL ;
    PORT
      LAYER M4 ;
        RECT  72.792 31.536 72.984 31.56 ;
    END
  END a[329]
  PIN a[32]
    DIRECTION INPUT ;
    USE SIGNAL ;
    PORT
      LAYER M4 ;
        RECT  72.792 17.28 72.984 17.304 ;
    END
  END a[32]
  PIN a[330]
    DIRECTION OUTPUT ;
    USE SIGNAL ;
    PORT
      LAYER M4 ;
        RECT  72.792 31.584 72.984 31.608 ;
    END
  END a[330]
  PIN a[331]
    DIRECTION OUTPUT ;
    USE SIGNAL ;
    PORT
      LAYER M4 ;
        RECT  72.792 31.632 72.984 31.656 ;
    END
  END a[331]
  PIN a[332]
    DIRECTION OUTPUT ;
    USE SIGNAL ;
    PORT
      LAYER M4 ;
        RECT  72.792 31.68 72.984 31.704 ;
    END
  END a[332]
  PIN a[333]
    DIRECTION OUTPUT ;
    USE SIGNAL ;
    PORT
      LAYER M4 ;
        RECT  72.792 31.728 72.984 31.752 ;
    END
  END a[333]
  PIN a[334]
    DIRECTION OUTPUT ;
    USE SIGNAL ;
    PORT
      LAYER M4 ;
        RECT  72.792 31.776 72.984 31.8 ;
    END
  END a[334]
  PIN a[335]
    DIRECTION OUTPUT ;
    USE SIGNAL ;
    PORT
      LAYER M4 ;
        RECT  72.792 31.824 72.984 31.848 ;
    END
  END a[335]
  PIN a[336]
    DIRECTION OUTPUT ;
    USE SIGNAL ;
    PORT
      LAYER M4 ;
        RECT  72.792 31.872 72.984 31.896 ;
    END
  END a[336]
  PIN a[337]
    DIRECTION OUTPUT ;
    USE SIGNAL ;
    PORT
      LAYER M4 ;
        RECT  72.792 31.92 72.984 31.944 ;
    END
  END a[337]
  PIN a[338]
    DIRECTION OUTPUT ;
    USE SIGNAL ;
    PORT
      LAYER M4 ;
        RECT  72.792 31.968 72.984 31.992 ;
    END
  END a[338]
  PIN a[339]
    DIRECTION OUTPUT ;
    USE SIGNAL ;
    PORT
      LAYER M4 ;
        RECT  72.792 32.016 72.984 32.04 ;
    END
  END a[339]
  PIN a[33]
    DIRECTION INPUT ;
    USE SIGNAL ;
    PORT
      LAYER M4 ;
        RECT  72.792 17.328 72.984 17.352 ;
    END
  END a[33]
  PIN a[340]
    DIRECTION OUTPUT ;
    USE SIGNAL ;
    PORT
      LAYER M4 ;
        RECT  72.792 32.064 72.984 32.088 ;
    END
  END a[340]
  PIN a[341]
    DIRECTION OUTPUT ;
    USE SIGNAL ;
    PORT
      LAYER M4 ;
        RECT  72.792 32.112 72.984 32.136 ;
    END
  END a[341]
  PIN a[342]
    DIRECTION OUTPUT ;
    USE SIGNAL ;
    PORT
      LAYER M4 ;
        RECT  72.792 32.16 72.984 32.184 ;
    END
  END a[342]
  PIN a[343]
    DIRECTION OUTPUT ;
    USE SIGNAL ;
    PORT
      LAYER M4 ;
        RECT  72.792 32.208 72.984 32.232 ;
    END
  END a[343]
  PIN a[344]
    DIRECTION OUTPUT ;
    USE SIGNAL ;
    PORT
      LAYER M4 ;
        RECT  72.792 32.256 72.984 32.28 ;
    END
  END a[344]
  PIN a[345]
    DIRECTION OUTPUT ;
    USE SIGNAL ;
    PORT
      LAYER M4 ;
        RECT  72.792 32.304 72.984 32.328 ;
    END
  END a[345]
  PIN a[346]
    DIRECTION OUTPUT ;
    USE SIGNAL ;
    PORT
      LAYER M4 ;
        RECT  72.792 32.352 72.984 32.376 ;
    END
  END a[346]
  PIN a[347]
    DIRECTION OUTPUT ;
    USE SIGNAL ;
    PORT
      LAYER M4 ;
        RECT  72.792 32.4 72.984 32.424 ;
    END
  END a[347]
  PIN a[348]
    DIRECTION OUTPUT ;
    USE SIGNAL ;
    PORT
      LAYER M4 ;
        RECT  72.792 32.448 72.984 32.472 ;
    END
  END a[348]
  PIN a[349]
    DIRECTION OUTPUT ;
    USE SIGNAL ;
    PORT
      LAYER M4 ;
        RECT  72.792 32.496 72.984 32.52 ;
    END
  END a[349]
  PIN a[34]
    DIRECTION INPUT ;
    USE SIGNAL ;
    PORT
      LAYER M4 ;
        RECT  72.792 17.376 72.984 17.4 ;
    END
  END a[34]
  PIN a[350]
    DIRECTION OUTPUT ;
    USE SIGNAL ;
    PORT
      LAYER M4 ;
        RECT  72.792 32.544 72.984 32.568 ;
    END
  END a[350]
  PIN a[351]
    DIRECTION OUTPUT ;
    USE SIGNAL ;
    PORT
      LAYER M4 ;
        RECT  72.792 32.592 72.984 32.616 ;
    END
  END a[351]
  PIN a[352]
    DIRECTION OUTPUT ;
    USE SIGNAL ;
    PORT
      LAYER M4 ;
        RECT  72.792 32.64 72.984 32.664 ;
    END
  END a[352]
  PIN a[353]
    DIRECTION OUTPUT ;
    USE SIGNAL ;
    PORT
      LAYER M4 ;
        RECT  72.792 32.688 72.984 32.712 ;
    END
  END a[353]
  PIN a[354]
    DIRECTION OUTPUT ;
    USE SIGNAL ;
    PORT
      LAYER M4 ;
        RECT  72.792 32.736 72.984 32.76 ;
    END
  END a[354]
  PIN a[355]
    DIRECTION OUTPUT ;
    USE SIGNAL ;
    PORT
      LAYER M4 ;
        RECT  72.792 32.784 72.984 32.808 ;
    END
  END a[355]
  PIN a[356]
    DIRECTION OUTPUT ;
    USE SIGNAL ;
    PORT
      LAYER M4 ;
        RECT  72.792 32.832 72.984 32.856 ;
    END
  END a[356]
  PIN a[357]
    DIRECTION OUTPUT ;
    USE SIGNAL ;
    PORT
      LAYER M4 ;
        RECT  72.792 32.88 72.984 32.904 ;
    END
  END a[357]
  PIN a[358]
    DIRECTION OUTPUT ;
    USE SIGNAL ;
    PORT
      LAYER M4 ;
        RECT  72.792 32.928 72.984 32.952 ;
    END
  END a[358]
  PIN a[359]
    DIRECTION OUTPUT ;
    USE SIGNAL ;
    PORT
      LAYER M4 ;
        RECT  72.792 32.976 72.984 33 ;
    END
  END a[359]
  PIN a[35]
    DIRECTION INPUT ;
    USE SIGNAL ;
    PORT
      LAYER M4 ;
        RECT  72.792 17.424 72.984 17.448 ;
    END
  END a[35]
  PIN a[360]
    DIRECTION OUTPUT ;
    USE SIGNAL ;
    PORT
      LAYER M4 ;
        RECT  72.792 33.024 72.984 33.048 ;
    END
  END a[360]
  PIN a[361]
    DIRECTION OUTPUT ;
    USE SIGNAL ;
    PORT
      LAYER M4 ;
        RECT  72.792 33.072 72.984 33.096 ;
    END
  END a[361]
  PIN a[362]
    DIRECTION OUTPUT ;
    USE SIGNAL ;
    PORT
      LAYER M4 ;
        RECT  72.792 33.12 72.984 33.144 ;
    END
  END a[362]
  PIN a[363]
    DIRECTION OUTPUT ;
    USE SIGNAL ;
    PORT
      LAYER M4 ;
        RECT  72.792 33.168 72.984 33.192 ;
    END
  END a[363]
  PIN a[364]
    DIRECTION OUTPUT ;
    USE SIGNAL ;
    PORT
      LAYER M4 ;
        RECT  72.792 33.216 72.984 33.24 ;
    END
  END a[364]
  PIN a[365]
    DIRECTION OUTPUT ;
    USE SIGNAL ;
    PORT
      LAYER M4 ;
        RECT  72.792 33.264 72.984 33.288 ;
    END
  END a[365]
  PIN a[366]
    DIRECTION OUTPUT ;
    USE SIGNAL ;
    PORT
      LAYER M4 ;
        RECT  72.792 33.312 72.984 33.336 ;
    END
  END a[366]
  PIN a[367]
    DIRECTION OUTPUT ;
    USE SIGNAL ;
    PORT
      LAYER M4 ;
        RECT  72.792 33.36 72.984 33.384 ;
    END
  END a[367]
  PIN a[368]
    DIRECTION OUTPUT ;
    USE SIGNAL ;
    PORT
      LAYER M4 ;
        RECT  72.792 33.408 72.984 33.432 ;
    END
  END a[368]
  PIN a[369]
    DIRECTION OUTPUT ;
    USE SIGNAL ;
    PORT
      LAYER M4 ;
        RECT  72.792 33.456 72.984 33.48 ;
    END
  END a[369]
  PIN a[36]
    DIRECTION INPUT ;
    USE SIGNAL ;
    PORT
      LAYER M4 ;
        RECT  72.792 17.472 72.984 17.496 ;
    END
  END a[36]
  PIN a[370]
    DIRECTION OUTPUT ;
    USE SIGNAL ;
    PORT
      LAYER M4 ;
        RECT  72.792 33.504 72.984 33.528 ;
    END
  END a[370]
  PIN a[371]
    DIRECTION OUTPUT ;
    USE SIGNAL ;
    PORT
      LAYER M4 ;
        RECT  72.792 33.552 72.984 33.576 ;
    END
  END a[371]
  PIN a[372]
    DIRECTION OUTPUT ;
    USE SIGNAL ;
    PORT
      LAYER M4 ;
        RECT  72.792 33.6 72.984 33.624 ;
    END
  END a[372]
  PIN a[373]
    DIRECTION OUTPUT ;
    USE SIGNAL ;
    PORT
      LAYER M4 ;
        RECT  72.792 33.648 72.984 33.672 ;
    END
  END a[373]
  PIN a[374]
    DIRECTION OUTPUT ;
    USE SIGNAL ;
    PORT
      LAYER M4 ;
        RECT  72.792 33.696 72.984 33.72 ;
    END
  END a[374]
  PIN a[375]
    DIRECTION OUTPUT ;
    USE SIGNAL ;
    PORT
      LAYER M4 ;
        RECT  72.792 33.744 72.984 33.768 ;
    END
  END a[375]
  PIN a[376]
    DIRECTION OUTPUT ;
    USE SIGNAL ;
    PORT
      LAYER M4 ;
        RECT  72.792 33.792 72.984 33.816 ;
    END
  END a[376]
  PIN a[377]
    DIRECTION OUTPUT ;
    USE SIGNAL ;
    PORT
      LAYER M4 ;
        RECT  72.792 33.84 72.984 33.864 ;
    END
  END a[377]
  PIN a[378]
    DIRECTION OUTPUT ;
    USE SIGNAL ;
    PORT
      LAYER M4 ;
        RECT  72.792 33.888 72.984 33.912 ;
    END
  END a[378]
  PIN a[379]
    DIRECTION OUTPUT ;
    USE SIGNAL ;
    PORT
      LAYER M4 ;
        RECT  72.792 33.936 72.984 33.96 ;
    END
  END a[379]
  PIN a[37]
    DIRECTION INPUT ;
    USE SIGNAL ;
    PORT
      LAYER M4 ;
        RECT  72.792 17.52 72.984 17.544 ;
    END
  END a[37]
  PIN a[380]
    DIRECTION OUTPUT ;
    USE SIGNAL ;
    PORT
      LAYER M4 ;
        RECT  72.792 33.984 72.984 34.008 ;
    END
  END a[380]
  PIN a[381]
    DIRECTION OUTPUT ;
    USE SIGNAL ;
    PORT
      LAYER M4 ;
        RECT  72.792 34.032 72.984 34.056 ;
    END
  END a[381]
  PIN a[382]
    DIRECTION OUTPUT ;
    USE SIGNAL ;
    PORT
      LAYER M4 ;
        RECT  72.792 34.08 72.984 34.104 ;
    END
  END a[382]
  PIN a[383]
    DIRECTION OUTPUT ;
    USE SIGNAL ;
    PORT
      LAYER M4 ;
        RECT  72.792 34.128 72.984 34.152 ;
    END
  END a[383]
  PIN a[384]
    DIRECTION OUTPUT ;
    USE SIGNAL ;
    PORT
      LAYER M4 ;
        RECT  72.792 34.176 72.984 34.2 ;
    END
  END a[384]
  PIN a[385]
    DIRECTION OUTPUT ;
    USE SIGNAL ;
    PORT
      LAYER M4 ;
        RECT  72.792 34.224 72.984 34.248 ;
    END
  END a[385]
  PIN a[386]
    DIRECTION OUTPUT ;
    USE SIGNAL ;
    PORT
      LAYER M4 ;
        RECT  72.792 34.272 72.984 34.296 ;
    END
  END a[386]
  PIN a[387]
    DIRECTION OUTPUT ;
    USE SIGNAL ;
    PORT
      LAYER M4 ;
        RECT  72.792 34.32 72.984 34.344 ;
    END
  END a[387]
  PIN a[388]
    DIRECTION OUTPUT ;
    USE SIGNAL ;
    PORT
      LAYER M4 ;
        RECT  72.792 34.368 72.984 34.392 ;
    END
  END a[388]
  PIN a[389]
    DIRECTION OUTPUT ;
    USE SIGNAL ;
    PORT
      LAYER M4 ;
        RECT  72.792 34.416 72.984 34.44 ;
    END
  END a[389]
  PIN a[38]
    DIRECTION INPUT ;
    USE SIGNAL ;
    PORT
      LAYER M4 ;
        RECT  72.792 17.568 72.984 17.592 ;
    END
  END a[38]
  PIN a[390]
    DIRECTION OUTPUT ;
    USE SIGNAL ;
    PORT
      LAYER M4 ;
        RECT  72.792 34.464 72.984 34.488 ;
    END
  END a[390]
  PIN a[391]
    DIRECTION OUTPUT ;
    USE SIGNAL ;
    PORT
      LAYER M4 ;
        RECT  72.792 34.512 72.984 34.536 ;
    END
  END a[391]
  PIN a[392]
    DIRECTION OUTPUT ;
    USE SIGNAL ;
    PORT
      LAYER M4 ;
        RECT  72.792 34.56 72.984 34.584 ;
    END
  END a[392]
  PIN a[393]
    DIRECTION OUTPUT ;
    USE SIGNAL ;
    PORT
      LAYER M4 ;
        RECT  72.792 34.608 72.984 34.632 ;
    END
  END a[393]
  PIN a[394]
    DIRECTION OUTPUT ;
    USE SIGNAL ;
    PORT
      LAYER M4 ;
        RECT  72.792 34.656 72.984 34.68 ;
    END
  END a[394]
  PIN a[395]
    DIRECTION OUTPUT ;
    USE SIGNAL ;
    PORT
      LAYER M4 ;
        RECT  72.792 34.704 72.984 34.728 ;
    END
  END a[395]
  PIN a[396]
    DIRECTION OUTPUT ;
    USE SIGNAL ;
    PORT
      LAYER M4 ;
        RECT  72.792 34.752 72.984 34.776 ;
    END
  END a[396]
  PIN a[397]
    DIRECTION OUTPUT ;
    USE SIGNAL ;
    PORT
      LAYER M4 ;
        RECT  72.792 34.8 72.984 34.824 ;
    END
  END a[397]
  PIN a[398]
    DIRECTION OUTPUT ;
    USE SIGNAL ;
    PORT
      LAYER M4 ;
        RECT  72.792 34.848 72.984 34.872 ;
    END
  END a[398]
  PIN a[399]
    DIRECTION OUTPUT ;
    USE SIGNAL ;
    PORT
      LAYER M4 ;
        RECT  72.792 34.896 72.984 34.92 ;
    END
  END a[399]
  PIN a[39]
    DIRECTION INPUT ;
    USE SIGNAL ;
    PORT
      LAYER M4 ;
        RECT  72.792 17.616 72.984 17.64 ;
    END
  END a[39]
  PIN a[3]
    DIRECTION INPUT ;
    USE SIGNAL ;
    PORT
      LAYER M4 ;
        RECT  72.792 15.888 72.984 15.912 ;
    END
  END a[3]
  PIN a[400]
    DIRECTION OUTPUT ;
    USE SIGNAL ;
    PORT
      LAYER M4 ;
        RECT  72.792 34.944 72.984 34.968 ;
    END
  END a[400]
  PIN a[401]
    DIRECTION OUTPUT ;
    USE SIGNAL ;
    PORT
      LAYER M4 ;
        RECT  72.792 34.992 72.984 35.016 ;
    END
  END a[401]
  PIN a[402]
    DIRECTION OUTPUT ;
    USE SIGNAL ;
    PORT
      LAYER M4 ;
        RECT  72.792 35.04 72.984 35.064 ;
    END
  END a[402]
  PIN a[403]
    DIRECTION OUTPUT ;
    USE SIGNAL ;
    PORT
      LAYER M4 ;
        RECT  72.792 35.088 72.984 35.112 ;
    END
  END a[403]
  PIN a[404]
    DIRECTION OUTPUT ;
    USE SIGNAL ;
    PORT
      LAYER M4 ;
        RECT  72.792 35.136 72.984 35.16 ;
    END
  END a[404]
  PIN a[405]
    DIRECTION OUTPUT ;
    USE SIGNAL ;
    PORT
      LAYER M4 ;
        RECT  72.792 35.184 72.984 35.208 ;
    END
  END a[405]
  PIN a[406]
    DIRECTION OUTPUT ;
    USE SIGNAL ;
    PORT
      LAYER M4 ;
        RECT  72.792 35.232 72.984 35.256 ;
    END
  END a[406]
  PIN a[407]
    DIRECTION OUTPUT ;
    USE SIGNAL ;
    PORT
      LAYER M4 ;
        RECT  72.792 35.28 72.984 35.304 ;
    END
  END a[407]
  PIN a[408]
    DIRECTION OUTPUT ;
    USE SIGNAL ;
    PORT
      LAYER M4 ;
        RECT  72.792 35.328 72.984 35.352 ;
    END
  END a[408]
  PIN a[409]
    DIRECTION OUTPUT ;
    USE SIGNAL ;
    PORT
      LAYER M4 ;
        RECT  72.792 35.376 72.984 35.4 ;
    END
  END a[409]
  PIN a[40]
    DIRECTION INPUT ;
    USE SIGNAL ;
    PORT
      LAYER M4 ;
        RECT  72.792 17.664 72.984 17.688 ;
    END
  END a[40]
  PIN a[410]
    DIRECTION OUTPUT ;
    USE SIGNAL ;
    PORT
      LAYER M4 ;
        RECT  72.792 35.424 72.984 35.448 ;
    END
  END a[410]
  PIN a[411]
    DIRECTION OUTPUT ;
    USE SIGNAL ;
    PORT
      LAYER M4 ;
        RECT  72.792 35.472 72.984 35.496 ;
    END
  END a[411]
  PIN a[412]
    DIRECTION OUTPUT ;
    USE SIGNAL ;
    PORT
      LAYER M4 ;
        RECT  72.792 35.52 72.984 35.544 ;
    END
  END a[412]
  PIN a[413]
    DIRECTION OUTPUT ;
    USE SIGNAL ;
    PORT
      LAYER M4 ;
        RECT  72.792 35.568 72.984 35.592 ;
    END
  END a[413]
  PIN a[414]
    DIRECTION OUTPUT ;
    USE SIGNAL ;
    PORT
      LAYER M4 ;
        RECT  72.792 35.616 72.984 35.64 ;
    END
  END a[414]
  PIN a[415]
    DIRECTION OUTPUT ;
    USE SIGNAL ;
    PORT
      LAYER M4 ;
        RECT  72.792 35.664 72.984 35.688 ;
    END
  END a[415]
  PIN a[416]
    DIRECTION OUTPUT ;
    USE SIGNAL ;
    PORT
      LAYER M4 ;
        RECT  72.792 35.712 72.984 35.736 ;
    END
  END a[416]
  PIN a[417]
    DIRECTION OUTPUT ;
    USE SIGNAL ;
    PORT
      LAYER M4 ;
        RECT  72.792 35.76 72.984 35.784 ;
    END
  END a[417]
  PIN a[418]
    DIRECTION OUTPUT ;
    USE SIGNAL ;
    PORT
      LAYER M4 ;
        RECT  72.792 35.808 72.984 35.832 ;
    END
  END a[418]
  PIN a[419]
    DIRECTION OUTPUT ;
    USE SIGNAL ;
    PORT
      LAYER M4 ;
        RECT  72.792 35.856 72.984 35.88 ;
    END
  END a[419]
  PIN a[41]
    DIRECTION INPUT ;
    USE SIGNAL ;
    PORT
      LAYER M4 ;
        RECT  72.792 17.712 72.984 17.736 ;
    END
  END a[41]
  PIN a[420]
    DIRECTION OUTPUT ;
    USE SIGNAL ;
    PORT
      LAYER M4 ;
        RECT  72.792 35.904 72.984 35.928 ;
    END
  END a[420]
  PIN a[421]
    DIRECTION OUTPUT ;
    USE SIGNAL ;
    PORT
      LAYER M4 ;
        RECT  72.792 35.952 72.984 35.976 ;
    END
  END a[421]
  PIN a[422]
    DIRECTION OUTPUT ;
    USE SIGNAL ;
    PORT
      LAYER M4 ;
        RECT  72.792 36 72.984 36.024 ;
    END
  END a[422]
  PIN a[423]
    DIRECTION OUTPUT ;
    USE SIGNAL ;
    PORT
      LAYER M4 ;
        RECT  72.792 36.048 72.984 36.072 ;
    END
  END a[423]
  PIN a[424]
    DIRECTION OUTPUT ;
    USE SIGNAL ;
    PORT
      LAYER M4 ;
        RECT  72.792 36.096 72.984 36.12 ;
    END
  END a[424]
  PIN a[425]
    DIRECTION OUTPUT ;
    USE SIGNAL ;
    PORT
      LAYER M4 ;
        RECT  72.792 36.144 72.984 36.168 ;
    END
  END a[425]
  PIN a[426]
    DIRECTION OUTPUT ;
    USE SIGNAL ;
    PORT
      LAYER M4 ;
        RECT  72.792 36.192 72.984 36.216 ;
    END
  END a[426]
  PIN a[427]
    DIRECTION OUTPUT ;
    USE SIGNAL ;
    PORT
      LAYER M4 ;
        RECT  72.792 36.24 72.984 36.264 ;
    END
  END a[427]
  PIN a[428]
    DIRECTION OUTPUT ;
    USE SIGNAL ;
    PORT
      LAYER M4 ;
        RECT  72.792 36.288 72.984 36.312 ;
    END
  END a[428]
  PIN a[429]
    DIRECTION OUTPUT ;
    USE SIGNAL ;
    PORT
      LAYER M4 ;
        RECT  72.792 36.336 72.984 36.36 ;
    END
  END a[429]
  PIN a[42]
    DIRECTION INPUT ;
    USE SIGNAL ;
    PORT
      LAYER M4 ;
        RECT  72.792 17.76 72.984 17.784 ;
    END
  END a[42]
  PIN a[430]
    DIRECTION OUTPUT ;
    USE SIGNAL ;
    PORT
      LAYER M4 ;
        RECT  72.792 36.384 72.984 36.408 ;
    END
  END a[430]
  PIN a[431]
    DIRECTION OUTPUT ;
    USE SIGNAL ;
    PORT
      LAYER M4 ;
        RECT  72.792 36.432 72.984 36.456 ;
    END
  END a[431]
  PIN a[432]
    DIRECTION OUTPUT ;
    USE SIGNAL ;
    PORT
      LAYER M4 ;
        RECT  72.792 36.48 72.984 36.504 ;
    END
  END a[432]
  PIN a[433]
    DIRECTION OUTPUT ;
    USE SIGNAL ;
    PORT
      LAYER M4 ;
        RECT  72.792 36.528 72.984 36.552 ;
    END
  END a[433]
  PIN a[434]
    DIRECTION OUTPUT ;
    USE SIGNAL ;
    PORT
      LAYER M4 ;
        RECT  72.792 36.576 72.984 36.6 ;
    END
  END a[434]
  PIN a[435]
    DIRECTION OUTPUT ;
    USE SIGNAL ;
    PORT
      LAYER M4 ;
        RECT  72.792 36.624 72.984 36.648 ;
    END
  END a[435]
  PIN a[436]
    DIRECTION OUTPUT ;
    USE SIGNAL ;
    PORT
      LAYER M4 ;
        RECT  72.792 36.672 72.984 36.696 ;
    END
  END a[436]
  PIN a[437]
    DIRECTION OUTPUT ;
    USE SIGNAL ;
    PORT
      LAYER M4 ;
        RECT  72.792 36.72 72.984 36.744 ;
    END
  END a[437]
  PIN a[438]
    DIRECTION OUTPUT ;
    USE SIGNAL ;
    PORT
      LAYER M4 ;
        RECT  72.792 36.768 72.984 36.792 ;
    END
  END a[438]
  PIN a[439]
    DIRECTION OUTPUT ;
    USE SIGNAL ;
    PORT
      LAYER M4 ;
        RECT  72.792 36.816 72.984 36.84 ;
    END
  END a[439]
  PIN a[43]
    DIRECTION INPUT ;
    USE SIGNAL ;
    PORT
      LAYER M4 ;
        RECT  72.792 17.808 72.984 17.832 ;
    END
  END a[43]
  PIN a[440]
    DIRECTION OUTPUT ;
    USE SIGNAL ;
    PORT
      LAYER M4 ;
        RECT  72.792 36.864 72.984 36.888 ;
    END
  END a[440]
  PIN a[441]
    DIRECTION OUTPUT ;
    USE SIGNAL ;
    PORT
      LAYER M4 ;
        RECT  72.792 36.912 72.984 36.936 ;
    END
  END a[441]
  PIN a[442]
    DIRECTION OUTPUT ;
    USE SIGNAL ;
    PORT
      LAYER M4 ;
        RECT  72.792 36.96 72.984 36.984 ;
    END
  END a[442]
  PIN a[443]
    DIRECTION OUTPUT ;
    USE SIGNAL ;
    PORT
      LAYER M4 ;
        RECT  72.792 37.008 72.984 37.032 ;
    END
  END a[443]
  PIN a[444]
    DIRECTION OUTPUT ;
    USE SIGNAL ;
    PORT
      LAYER M4 ;
        RECT  72.792 37.056 72.984 37.08 ;
    END
  END a[444]
  PIN a[445]
    DIRECTION OUTPUT ;
    USE SIGNAL ;
    PORT
      LAYER M4 ;
        RECT  72.792 37.104 72.984 37.128 ;
    END
  END a[445]
  PIN a[446]
    DIRECTION OUTPUT ;
    USE SIGNAL ;
    PORT
      LAYER M4 ;
        RECT  72.792 37.152 72.984 37.176 ;
    END
  END a[446]
  PIN a[447]
    DIRECTION OUTPUT ;
    USE SIGNAL ;
    PORT
      LAYER M4 ;
        RECT  72.792 37.2 72.984 37.224 ;
    END
  END a[447]
  PIN a[448]
    DIRECTION OUTPUT ;
    USE SIGNAL ;
    PORT
      LAYER M4 ;
        RECT  72.792 37.248 72.984 37.272 ;
    END
  END a[448]
  PIN a[449]
    DIRECTION OUTPUT ;
    USE SIGNAL ;
    PORT
      LAYER M4 ;
        RECT  72.792 37.296 72.984 37.32 ;
    END
  END a[449]
  PIN a[44]
    DIRECTION INPUT ;
    USE SIGNAL ;
    PORT
      LAYER M4 ;
        RECT  72.792 17.856 72.984 17.88 ;
    END
  END a[44]
  PIN a[450]
    DIRECTION OUTPUT ;
    USE SIGNAL ;
    PORT
      LAYER M4 ;
        RECT  72.792 37.344 72.984 37.368 ;
    END
  END a[450]
  PIN a[451]
    DIRECTION OUTPUT ;
    USE SIGNAL ;
    PORT
      LAYER M4 ;
        RECT  72.792 37.392 72.984 37.416 ;
    END
  END a[451]
  PIN a[452]
    DIRECTION OUTPUT ;
    USE SIGNAL ;
    PORT
      LAYER M4 ;
        RECT  72.792 37.44 72.984 37.464 ;
    END
  END a[452]
  PIN a[453]
    DIRECTION OUTPUT ;
    USE SIGNAL ;
    PORT
      LAYER M4 ;
        RECT  72.792 37.488 72.984 37.512 ;
    END
  END a[453]
  PIN a[454]
    DIRECTION OUTPUT ;
    USE SIGNAL ;
    PORT
      LAYER M4 ;
        RECT  72.792 37.536 72.984 37.56 ;
    END
  END a[454]
  PIN a[455]
    DIRECTION OUTPUT ;
    USE SIGNAL ;
    PORT
      LAYER M4 ;
        RECT  72.792 37.584 72.984 37.608 ;
    END
  END a[455]
  PIN a[456]
    DIRECTION OUTPUT ;
    USE SIGNAL ;
    PORT
      LAYER M4 ;
        RECT  72.792 37.632 72.984 37.656 ;
    END
  END a[456]
  PIN a[457]
    DIRECTION OUTPUT ;
    USE SIGNAL ;
    PORT
      LAYER M4 ;
        RECT  72.792 37.68 72.984 37.704 ;
    END
  END a[457]
  PIN a[458]
    DIRECTION OUTPUT ;
    USE SIGNAL ;
    PORT
      LAYER M4 ;
        RECT  72.792 37.728 72.984 37.752 ;
    END
  END a[458]
  PIN a[459]
    DIRECTION OUTPUT ;
    USE SIGNAL ;
    PORT
      LAYER M4 ;
        RECT  72.792 37.776 72.984 37.8 ;
    END
  END a[459]
  PIN a[45]
    DIRECTION INPUT ;
    USE SIGNAL ;
    PORT
      LAYER M4 ;
        RECT  72.792 17.904 72.984 17.928 ;
    END
  END a[45]
  PIN a[460]
    DIRECTION OUTPUT ;
    USE SIGNAL ;
    PORT
      LAYER M4 ;
        RECT  72.792 37.824 72.984 37.848 ;
    END
  END a[460]
  PIN a[461]
    DIRECTION OUTPUT ;
    USE SIGNAL ;
    PORT
      LAYER M4 ;
        RECT  72.792 37.872 72.984 37.896 ;
    END
  END a[461]
  PIN a[462]
    DIRECTION OUTPUT ;
    USE SIGNAL ;
    PORT
      LAYER M4 ;
        RECT  72.792 37.92 72.984 37.944 ;
    END
  END a[462]
  PIN a[463]
    DIRECTION OUTPUT ;
    USE SIGNAL ;
    PORT
      LAYER M4 ;
        RECT  72.792 37.968 72.984 37.992 ;
    END
  END a[463]
  PIN a[464]
    DIRECTION OUTPUT ;
    USE SIGNAL ;
    PORT
      LAYER M4 ;
        RECT  72.792 38.016 72.984 38.04 ;
    END
  END a[464]
  PIN a[465]
    DIRECTION OUTPUT ;
    USE SIGNAL ;
    PORT
      LAYER M4 ;
        RECT  72.792 38.064 72.984 38.088 ;
    END
  END a[465]
  PIN a[466]
    DIRECTION OUTPUT ;
    USE SIGNAL ;
    PORT
      LAYER M4 ;
        RECT  72.792 38.112 72.984 38.136 ;
    END
  END a[466]
  PIN a[467]
    DIRECTION OUTPUT ;
    USE SIGNAL ;
    PORT
      LAYER M4 ;
        RECT  72.792 38.16 72.984 38.184 ;
    END
  END a[467]
  PIN a[468]
    DIRECTION OUTPUT ;
    USE SIGNAL ;
    PORT
      LAYER M4 ;
        RECT  72.792 38.208 72.984 38.232 ;
    END
  END a[468]
  PIN a[469]
    DIRECTION OUTPUT ;
    USE SIGNAL ;
    PORT
      LAYER M4 ;
        RECT  72.792 38.256 72.984 38.28 ;
    END
  END a[469]
  PIN a[46]
    DIRECTION INPUT ;
    USE SIGNAL ;
    PORT
      LAYER M4 ;
        RECT  72.792 17.952 72.984 17.976 ;
    END
  END a[46]
  PIN a[470]
    DIRECTION OUTPUT ;
    USE SIGNAL ;
    PORT
      LAYER M4 ;
        RECT  72.792 38.304 72.984 38.328 ;
    END
  END a[470]
  PIN a[471]
    DIRECTION OUTPUT ;
    USE SIGNAL ;
    PORT
      LAYER M4 ;
        RECT  72.792 38.352 72.984 38.376 ;
    END
  END a[471]
  PIN a[472]
    DIRECTION OUTPUT ;
    USE SIGNAL ;
    PORT
      LAYER M4 ;
        RECT  72.792 38.4 72.984 38.424 ;
    END
  END a[472]
  PIN a[473]
    DIRECTION OUTPUT ;
    USE SIGNAL ;
    PORT
      LAYER M4 ;
        RECT  72.792 38.448 72.984 38.472 ;
    END
  END a[473]
  PIN a[474]
    DIRECTION OUTPUT ;
    USE SIGNAL ;
    PORT
      LAYER M4 ;
        RECT  72.792 38.496 72.984 38.52 ;
    END
  END a[474]
  PIN a[475]
    DIRECTION OUTPUT ;
    USE SIGNAL ;
    PORT
      LAYER M4 ;
        RECT  72.792 38.544 72.984 38.568 ;
    END
  END a[475]
  PIN a[476]
    DIRECTION OUTPUT ;
    USE SIGNAL ;
    PORT
      LAYER M4 ;
        RECT  72.792 38.592 72.984 38.616 ;
    END
  END a[476]
  PIN a[477]
    DIRECTION OUTPUT ;
    USE SIGNAL ;
    PORT
      LAYER M4 ;
        RECT  72.792 38.64 72.984 38.664 ;
    END
  END a[477]
  PIN a[478]
    DIRECTION OUTPUT ;
    USE SIGNAL ;
    PORT
      LAYER M4 ;
        RECT  72.792 38.688 72.984 38.712 ;
    END
  END a[478]
  PIN a[479]
    DIRECTION OUTPUT ;
    USE SIGNAL ;
    PORT
      LAYER M4 ;
        RECT  72.792 38.736 72.984 38.76 ;
    END
  END a[479]
  PIN a[47]
    DIRECTION INPUT ;
    USE SIGNAL ;
    PORT
      LAYER M4 ;
        RECT  72.792 18 72.984 18.024 ;
    END
  END a[47]
  PIN a[480]
    DIRECTION OUTPUT ;
    USE SIGNAL ;
    PORT
      LAYER M4 ;
        RECT  72.792 38.784 72.984 38.808 ;
    END
  END a[480]
  PIN a[481]
    DIRECTION OUTPUT ;
    USE SIGNAL ;
    PORT
      LAYER M4 ;
        RECT  72.792 38.832 72.984 38.856 ;
    END
  END a[481]
  PIN a[482]
    DIRECTION OUTPUT ;
    USE SIGNAL ;
    PORT
      LAYER M4 ;
        RECT  72.792 38.88 72.984 38.904 ;
    END
  END a[482]
  PIN a[483]
    DIRECTION OUTPUT ;
    USE SIGNAL ;
    PORT
      LAYER M4 ;
        RECT  72.792 38.928 72.984 38.952 ;
    END
  END a[483]
  PIN a[484]
    DIRECTION OUTPUT ;
    USE SIGNAL ;
    PORT
      LAYER M4 ;
        RECT  72.792 38.976 72.984 39 ;
    END
  END a[484]
  PIN a[485]
    DIRECTION OUTPUT ;
    USE SIGNAL ;
    PORT
      LAYER M4 ;
        RECT  72.792 39.024 72.984 39.048 ;
    END
  END a[485]
  PIN a[486]
    DIRECTION OUTPUT ;
    USE SIGNAL ;
    PORT
      LAYER M4 ;
        RECT  72.792 39.072 72.984 39.096 ;
    END
  END a[486]
  PIN a[487]
    DIRECTION OUTPUT ;
    USE SIGNAL ;
    PORT
      LAYER M4 ;
        RECT  72.792 39.12 72.984 39.144 ;
    END
  END a[487]
  PIN a[488]
    DIRECTION OUTPUT ;
    USE SIGNAL ;
    PORT
      LAYER M4 ;
        RECT  72.792 39.168 72.984 39.192 ;
    END
  END a[488]
  PIN a[489]
    DIRECTION OUTPUT ;
    USE SIGNAL ;
    PORT
      LAYER M4 ;
        RECT  72.792 39.216 72.984 39.24 ;
    END
  END a[489]
  PIN a[48]
    DIRECTION INPUT ;
    USE SIGNAL ;
    PORT
      LAYER M4 ;
        RECT  72.792 18.048 72.984 18.072 ;
    END
  END a[48]
  PIN a[490]
    DIRECTION OUTPUT ;
    USE SIGNAL ;
    PORT
      LAYER M4 ;
        RECT  72.792 39.264 72.984 39.288 ;
    END
  END a[490]
  PIN a[491]
    DIRECTION OUTPUT ;
    USE SIGNAL ;
    PORT
      LAYER M4 ;
        RECT  72.792 39.312 72.984 39.336 ;
    END
  END a[491]
  PIN a[492]
    DIRECTION OUTPUT ;
    USE SIGNAL ;
    PORT
      LAYER M4 ;
        RECT  72.792 39.36 72.984 39.384 ;
    END
  END a[492]
  PIN a[493]
    DIRECTION OUTPUT ;
    USE SIGNAL ;
    PORT
      LAYER M4 ;
        RECT  72.792 39.408 72.984 39.432 ;
    END
  END a[493]
  PIN a[494]
    DIRECTION OUTPUT ;
    USE SIGNAL ;
    PORT
      LAYER M4 ;
        RECT  72.792 39.456 72.984 39.48 ;
    END
  END a[494]
  PIN a[495]
    DIRECTION OUTPUT ;
    USE SIGNAL ;
    PORT
      LAYER M4 ;
        RECT  72.792 39.504 72.984 39.528 ;
    END
  END a[495]
  PIN a[496]
    DIRECTION OUTPUT ;
    USE SIGNAL ;
    PORT
      LAYER M4 ;
        RECT  72.792 39.552 72.984 39.576 ;
    END
  END a[496]
  PIN a[497]
    DIRECTION OUTPUT ;
    USE SIGNAL ;
    PORT
      LAYER M4 ;
        RECT  72.792 39.6 72.984 39.624 ;
    END
  END a[497]
  PIN a[498]
    DIRECTION OUTPUT ;
    USE SIGNAL ;
    PORT
      LAYER M4 ;
        RECT  72.792 39.648 72.984 39.672 ;
    END
  END a[498]
  PIN a[499]
    DIRECTION OUTPUT ;
    USE SIGNAL ;
    PORT
      LAYER M4 ;
        RECT  72.792 39.696 72.984 39.72 ;
    END
  END a[499]
  PIN a[49]
    DIRECTION INPUT ;
    USE SIGNAL ;
    PORT
      LAYER M4 ;
        RECT  72.792 18.096 72.984 18.12 ;
    END
  END a[49]
  PIN a[4]
    DIRECTION INPUT ;
    USE SIGNAL ;
    PORT
      LAYER M4 ;
        RECT  72.792 15.936 72.984 15.96 ;
    END
  END a[4]
  PIN a[500]
    DIRECTION OUTPUT ;
    USE SIGNAL ;
    PORT
      LAYER M4 ;
        RECT  72.792 39.744 72.984 39.768 ;
    END
  END a[500]
  PIN a[501]
    DIRECTION OUTPUT ;
    USE SIGNAL ;
    PORT
      LAYER M4 ;
        RECT  72.792 39.792 72.984 39.816 ;
    END
  END a[501]
  PIN a[502]
    DIRECTION OUTPUT ;
    USE SIGNAL ;
    PORT
      LAYER M4 ;
        RECT  72.792 39.84 72.984 39.864 ;
    END
  END a[502]
  PIN a[503]
    DIRECTION OUTPUT ;
    USE SIGNAL ;
    PORT
      LAYER M4 ;
        RECT  72.792 39.888 72.984 39.912 ;
    END
  END a[503]
  PIN a[504]
    DIRECTION OUTPUT ;
    USE SIGNAL ;
    PORT
      LAYER M4 ;
        RECT  72.792 39.936 72.984 39.96 ;
    END
  END a[504]
  PIN a[505]
    DIRECTION OUTPUT ;
    USE SIGNAL ;
    PORT
      LAYER M4 ;
        RECT  72.792 39.984 72.984 40.008 ;
    END
  END a[505]
  PIN a[506]
    DIRECTION OUTPUT ;
    USE SIGNAL ;
    PORT
      LAYER M4 ;
        RECT  72.792 40.032 72.984 40.056 ;
    END
  END a[506]
  PIN a[507]
    DIRECTION OUTPUT ;
    USE SIGNAL ;
    PORT
      LAYER M4 ;
        RECT  72.792 40.08 72.984 40.104 ;
    END
  END a[507]
  PIN a[508]
    DIRECTION OUTPUT ;
    USE SIGNAL ;
    PORT
      LAYER M4 ;
        RECT  72.792 40.128 72.984 40.152 ;
    END
  END a[508]
  PIN a[509]
    DIRECTION OUTPUT ;
    USE SIGNAL ;
    PORT
      LAYER M4 ;
        RECT  72.792 40.176 72.984 40.2 ;
    END
  END a[509]
  PIN a[50]
    DIRECTION INPUT ;
    USE SIGNAL ;
    PORT
      LAYER M4 ;
        RECT  72.792 18.144 72.984 18.168 ;
    END
  END a[50]
  PIN a[510]
    DIRECTION OUTPUT ;
    USE SIGNAL ;
    PORT
      LAYER M4 ;
        RECT  72.792 40.224 72.984 40.248 ;
    END
  END a[510]
  PIN a[511]
    DIRECTION OUTPUT ;
    USE SIGNAL ;
    PORT
      LAYER M4 ;
        RECT  72.792 40.272 72.984 40.296 ;
    END
  END a[511]
  PIN a[512]
    DIRECTION INPUT ;
    USE SIGNAL ;
    PORT
      LAYER M4 ;
        RECT  72.792 40.32 72.984 40.344 ;
    END
  END a[512]
  PIN a[513]
    DIRECTION OUTPUT ;
    USE SIGNAL ;
    PORT
      LAYER M4 ;
        RECT  72.792 40.368 72.984 40.392 ;
    END
  END a[513]
  PIN a[51]
    DIRECTION INPUT ;
    USE SIGNAL ;
    PORT
      LAYER M4 ;
        RECT  72.792 18.192 72.984 18.216 ;
    END
  END a[51]
  PIN a[52]
    DIRECTION INPUT ;
    USE SIGNAL ;
    PORT
      LAYER M4 ;
        RECT  72.792 18.24 72.984 18.264 ;
    END
  END a[52]
  PIN a[53]
    DIRECTION INPUT ;
    USE SIGNAL ;
    PORT
      LAYER M4 ;
        RECT  72.792 18.288 72.984 18.312 ;
    END
  END a[53]
  PIN a[54]
    DIRECTION INPUT ;
    USE SIGNAL ;
    PORT
      LAYER M4 ;
        RECT  72.792 18.336 72.984 18.36 ;
    END
  END a[54]
  PIN a[55]
    DIRECTION INPUT ;
    USE SIGNAL ;
    PORT
      LAYER M4 ;
        RECT  72.792 18.384 72.984 18.408 ;
    END
  END a[55]
  PIN a[56]
    DIRECTION INPUT ;
    USE SIGNAL ;
    PORT
      LAYER M4 ;
        RECT  72.792 18.432 72.984 18.456 ;
    END
  END a[56]
  PIN a[57]
    DIRECTION INPUT ;
    USE SIGNAL ;
    PORT
      LAYER M4 ;
        RECT  72.792 18.48 72.984 18.504 ;
    END
  END a[57]
  PIN a[58]
    DIRECTION INPUT ;
    USE SIGNAL ;
    PORT
      LAYER M4 ;
        RECT  72.792 18.528 72.984 18.552 ;
    END
  END a[58]
  PIN a[59]
    DIRECTION INPUT ;
    USE SIGNAL ;
    PORT
      LAYER M4 ;
        RECT  72.792 18.576 72.984 18.6 ;
    END
  END a[59]
  PIN a[5]
    DIRECTION INPUT ;
    USE SIGNAL ;
    PORT
      LAYER M4 ;
        RECT  72.792 15.984 72.984 16.008 ;
    END
  END a[5]
  PIN a[60]
    DIRECTION INPUT ;
    USE SIGNAL ;
    PORT
      LAYER M4 ;
        RECT  72.792 18.624 72.984 18.648 ;
    END
  END a[60]
  PIN a[61]
    DIRECTION INPUT ;
    USE SIGNAL ;
    PORT
      LAYER M4 ;
        RECT  72.792 18.672 72.984 18.696 ;
    END
  END a[61]
  PIN a[62]
    DIRECTION INPUT ;
    USE SIGNAL ;
    PORT
      LAYER M4 ;
        RECT  72.792 18.72 72.984 18.744 ;
    END
  END a[62]
  PIN a[63]
    DIRECTION INPUT ;
    USE SIGNAL ;
    PORT
      LAYER M4 ;
        RECT  72.792 18.768 72.984 18.792 ;
    END
  END a[63]
  PIN a[64]
    DIRECTION INPUT ;
    USE SIGNAL ;
    PORT
      LAYER M4 ;
        RECT  72.792 18.816 72.984 18.84 ;
    END
  END a[64]
  PIN a[65]
    DIRECTION INPUT ;
    USE SIGNAL ;
    PORT
      LAYER M4 ;
        RECT  72.792 18.864 72.984 18.888 ;
    END
  END a[65]
  PIN a[66]
    DIRECTION INPUT ;
    USE SIGNAL ;
    PORT
      LAYER M4 ;
        RECT  72.792 18.912 72.984 18.936 ;
    END
  END a[66]
  PIN a[67]
    DIRECTION INPUT ;
    USE SIGNAL ;
    PORT
      LAYER M4 ;
        RECT  72.792 18.96 72.984 18.984 ;
    END
  END a[67]
  PIN a[68]
    DIRECTION INPUT ;
    USE SIGNAL ;
    PORT
      LAYER M4 ;
        RECT  72.792 19.008 72.984 19.032 ;
    END
  END a[68]
  PIN a[69]
    DIRECTION INPUT ;
    USE SIGNAL ;
    PORT
      LAYER M4 ;
        RECT  72.792 19.056 72.984 19.08 ;
    END
  END a[69]
  PIN a[6]
    DIRECTION INPUT ;
    USE SIGNAL ;
    PORT
      LAYER M4 ;
        RECT  72.792 16.032 72.984 16.056 ;
    END
  END a[6]
  PIN a[70]
    DIRECTION INPUT ;
    USE SIGNAL ;
    PORT
      LAYER M4 ;
        RECT  72.792 19.104 72.984 19.128 ;
    END
  END a[70]
  PIN a[71]
    DIRECTION INPUT ;
    USE SIGNAL ;
    PORT
      LAYER M4 ;
        RECT  72.792 19.152 72.984 19.176 ;
    END
  END a[71]
  PIN a[72]
    DIRECTION INPUT ;
    USE SIGNAL ;
    PORT
      LAYER M4 ;
        RECT  72.792 19.2 72.984 19.224 ;
    END
  END a[72]
  PIN a[73]
    DIRECTION INPUT ;
    USE SIGNAL ;
    PORT
      LAYER M4 ;
        RECT  72.792 19.248 72.984 19.272 ;
    END
  END a[73]
  PIN a[74]
    DIRECTION INPUT ;
    USE SIGNAL ;
    PORT
      LAYER M4 ;
        RECT  72.792 19.296 72.984 19.32 ;
    END
  END a[74]
  PIN a[75]
    DIRECTION INPUT ;
    USE SIGNAL ;
    PORT
      LAYER M4 ;
        RECT  72.792 19.344 72.984 19.368 ;
    END
  END a[75]
  PIN a[76]
    DIRECTION INPUT ;
    USE SIGNAL ;
    PORT
      LAYER M4 ;
        RECT  72.792 19.392 72.984 19.416 ;
    END
  END a[76]
  PIN a[77]
    DIRECTION INPUT ;
    USE SIGNAL ;
    PORT
      LAYER M4 ;
        RECT  72.792 19.44 72.984 19.464 ;
    END
  END a[77]
  PIN a[78]
    DIRECTION INPUT ;
    USE SIGNAL ;
    PORT
      LAYER M4 ;
        RECT  72.792 19.488 72.984 19.512 ;
    END
  END a[78]
  PIN a[79]
    DIRECTION INPUT ;
    USE SIGNAL ;
    PORT
      LAYER M4 ;
        RECT  72.792 19.536 72.984 19.56 ;
    END
  END a[79]
  PIN a[7]
    DIRECTION INPUT ;
    USE SIGNAL ;
    PORT
      LAYER M4 ;
        RECT  72.792 16.08 72.984 16.104 ;
    END
  END a[7]
  PIN a[80]
    DIRECTION INPUT ;
    USE SIGNAL ;
    PORT
      LAYER M4 ;
        RECT  72.792 19.584 72.984 19.608 ;
    END
  END a[80]
  PIN a[81]
    DIRECTION INPUT ;
    USE SIGNAL ;
    PORT
      LAYER M4 ;
        RECT  72.792 19.632 72.984 19.656 ;
    END
  END a[81]
  PIN a[82]
    DIRECTION INPUT ;
    USE SIGNAL ;
    PORT
      LAYER M4 ;
        RECT  72.792 19.68 72.984 19.704 ;
    END
  END a[82]
  PIN a[83]
    DIRECTION INPUT ;
    USE SIGNAL ;
    PORT
      LAYER M4 ;
        RECT  72.792 19.728 72.984 19.752 ;
    END
  END a[83]
  PIN a[84]
    DIRECTION INPUT ;
    USE SIGNAL ;
    PORT
      LAYER M4 ;
        RECT  72.792 19.776 72.984 19.8 ;
    END
  END a[84]
  PIN a[85]
    DIRECTION INPUT ;
    USE SIGNAL ;
    PORT
      LAYER M4 ;
        RECT  72.792 19.824 72.984 19.848 ;
    END
  END a[85]
  PIN a[86]
    DIRECTION INPUT ;
    USE SIGNAL ;
    PORT
      LAYER M4 ;
        RECT  72.792 19.872 72.984 19.896 ;
    END
  END a[86]
  PIN a[87]
    DIRECTION INPUT ;
    USE SIGNAL ;
    PORT
      LAYER M4 ;
        RECT  72.792 19.92 72.984 19.944 ;
    END
  END a[87]
  PIN a[88]
    DIRECTION INPUT ;
    USE SIGNAL ;
    PORT
      LAYER M4 ;
        RECT  72.792 19.968 72.984 19.992 ;
    END
  END a[88]
  PIN a[89]
    DIRECTION INPUT ;
    USE SIGNAL ;
    PORT
      LAYER M4 ;
        RECT  72.792 20.016 72.984 20.04 ;
    END
  END a[89]
  PIN a[8]
    DIRECTION INPUT ;
    USE SIGNAL ;
    PORT
      LAYER M4 ;
        RECT  72.792 16.128 72.984 16.152 ;
    END
  END a[8]
  PIN a[90]
    DIRECTION INPUT ;
    USE SIGNAL ;
    PORT
      LAYER M4 ;
        RECT  72.792 20.064 72.984 20.088 ;
    END
  END a[90]
  PIN a[91]
    DIRECTION INPUT ;
    USE SIGNAL ;
    PORT
      LAYER M4 ;
        RECT  72.792 20.112 72.984 20.136 ;
    END
  END a[91]
  PIN a[92]
    DIRECTION INPUT ;
    USE SIGNAL ;
    PORT
      LAYER M4 ;
        RECT  72.792 20.16 72.984 20.184 ;
    END
  END a[92]
  PIN a[93]
    DIRECTION INPUT ;
    USE SIGNAL ;
    PORT
      LAYER M4 ;
        RECT  72.792 20.208 72.984 20.232 ;
    END
  END a[93]
  PIN a[94]
    DIRECTION INPUT ;
    USE SIGNAL ;
    PORT
      LAYER M4 ;
        RECT  72.792 20.256 72.984 20.28 ;
    END
  END a[94]
  PIN a[95]
    DIRECTION INPUT ;
    USE SIGNAL ;
    PORT
      LAYER M4 ;
        RECT  72.792 20.304 72.984 20.328 ;
    END
  END a[95]
  PIN a[96]
    DIRECTION INPUT ;
    USE SIGNAL ;
    PORT
      LAYER M4 ;
        RECT  72.792 20.352 72.984 20.376 ;
    END
  END a[96]
  PIN a[97]
    DIRECTION INPUT ;
    USE SIGNAL ;
    PORT
      LAYER M4 ;
        RECT  72.792 20.4 72.984 20.424 ;
    END
  END a[97]
  PIN a[98]
    DIRECTION INPUT ;
    USE SIGNAL ;
    PORT
      LAYER M4 ;
        RECT  72.792 20.448 72.984 20.472 ;
    END
  END a[98]
  PIN a[99]
    DIRECTION INPUT ;
    USE SIGNAL ;
    PORT
      LAYER M4 ;
        RECT  72.792 20.496 72.984 20.52 ;
    END
  END a[99]
  PIN a[9]
    DIRECTION INPUT ;
    USE SIGNAL ;
    PORT
      LAYER M4 ;
        RECT  72.792 16.176 72.984 16.2 ;
    END
  END a[9]
  PIN b[0]
    DIRECTION OUTPUT ;
    USE SIGNAL ;
    PORT
      LAYER M4 ;
        RECT  0 8.16 0.192 8.184 ;
    END
  END b[0]
  PIN b[100]
    DIRECTION OUTPUT ;
    USE SIGNAL ;
    PORT
      LAYER M4 ;
        RECT  0 12.96 0.192 12.984 ;
    END
  END b[100]
  PIN b[101]
    DIRECTION OUTPUT ;
    USE SIGNAL ;
    PORT
      LAYER M4 ;
        RECT  0 13.008 0.192 13.032 ;
    END
  END b[101]
  PIN b[102]
    DIRECTION OUTPUT ;
    USE SIGNAL ;
    PORT
      LAYER M4 ;
        RECT  0 13.056 0.192 13.08 ;
    END
  END b[102]
  PIN b[103]
    DIRECTION OUTPUT ;
    USE SIGNAL ;
    PORT
      LAYER M4 ;
        RECT  0 13.104 0.192 13.128 ;
    END
  END b[103]
  PIN b[104]
    DIRECTION OUTPUT ;
    USE SIGNAL ;
    PORT
      LAYER M4 ;
        RECT  0 13.152 0.192 13.176 ;
    END
  END b[104]
  PIN b[105]
    DIRECTION OUTPUT ;
    USE SIGNAL ;
    PORT
      LAYER M4 ;
        RECT  0 13.2 0.192 13.224 ;
    END
  END b[105]
  PIN b[106]
    DIRECTION OUTPUT ;
    USE SIGNAL ;
    PORT
      LAYER M4 ;
        RECT  0 13.248 0.192 13.272 ;
    END
  END b[106]
  PIN b[107]
    DIRECTION OUTPUT ;
    USE SIGNAL ;
    PORT
      LAYER M4 ;
        RECT  0 13.296 0.192 13.32 ;
    END
  END b[107]
  PIN b[108]
    DIRECTION OUTPUT ;
    USE SIGNAL ;
    PORT
      LAYER M4 ;
        RECT  0 13.344 0.192 13.368 ;
    END
  END b[108]
  PIN b[109]
    DIRECTION OUTPUT ;
    USE SIGNAL ;
    PORT
      LAYER M4 ;
        RECT  0 13.392 0.192 13.416 ;
    END
  END b[109]
  PIN b[10]
    DIRECTION OUTPUT ;
    USE SIGNAL ;
    PORT
      LAYER M4 ;
        RECT  0 8.64 0.192 8.664 ;
    END
  END b[10]
  PIN b[110]
    DIRECTION OUTPUT ;
    USE SIGNAL ;
    PORT
      LAYER M4 ;
        RECT  0 13.44 0.192 13.464 ;
    END
  END b[110]
  PIN b[111]
    DIRECTION OUTPUT ;
    USE SIGNAL ;
    PORT
      LAYER M4 ;
        RECT  0 13.488 0.192 13.512 ;
    END
  END b[111]
  PIN b[112]
    DIRECTION OUTPUT ;
    USE SIGNAL ;
    PORT
      LAYER M4 ;
        RECT  0 13.536 0.192 13.56 ;
    END
  END b[112]
  PIN b[113]
    DIRECTION OUTPUT ;
    USE SIGNAL ;
    PORT
      LAYER M4 ;
        RECT  0 13.584 0.192 13.608 ;
    END
  END b[113]
  PIN b[114]
    DIRECTION OUTPUT ;
    USE SIGNAL ;
    PORT
      LAYER M4 ;
        RECT  0 13.632 0.192 13.656 ;
    END
  END b[114]
  PIN b[115]
    DIRECTION OUTPUT ;
    USE SIGNAL ;
    PORT
      LAYER M4 ;
        RECT  0 13.68 0.192 13.704 ;
    END
  END b[115]
  PIN b[116]
    DIRECTION OUTPUT ;
    USE SIGNAL ;
    PORT
      LAYER M4 ;
        RECT  0 13.728 0.192 13.752 ;
    END
  END b[116]
  PIN b[117]
    DIRECTION OUTPUT ;
    USE SIGNAL ;
    PORT
      LAYER M4 ;
        RECT  0 13.776 0.192 13.8 ;
    END
  END b[117]
  PIN b[118]
    DIRECTION OUTPUT ;
    USE SIGNAL ;
    PORT
      LAYER M4 ;
        RECT  0 13.824 0.192 13.848 ;
    END
  END b[118]
  PIN b[119]
    DIRECTION OUTPUT ;
    USE SIGNAL ;
    PORT
      LAYER M4 ;
        RECT  0 13.872 0.192 13.896 ;
    END
  END b[119]
  PIN b[11]
    DIRECTION OUTPUT ;
    USE SIGNAL ;
    PORT
      LAYER M4 ;
        RECT  0 8.688 0.192 8.712 ;
    END
  END b[11]
  PIN b[120]
    DIRECTION OUTPUT ;
    USE SIGNAL ;
    PORT
      LAYER M4 ;
        RECT  0 13.92 0.192 13.944 ;
    END
  END b[120]
  PIN b[121]
    DIRECTION OUTPUT ;
    USE SIGNAL ;
    PORT
      LAYER M4 ;
        RECT  0 13.968 0.192 13.992 ;
    END
  END b[121]
  PIN b[122]
    DIRECTION OUTPUT ;
    USE SIGNAL ;
    PORT
      LAYER M4 ;
        RECT  0 14.016 0.192 14.04 ;
    END
  END b[122]
  PIN b[123]
    DIRECTION OUTPUT ;
    USE SIGNAL ;
    PORT
      LAYER M4 ;
        RECT  0 14.064 0.192 14.088 ;
    END
  END b[123]
  PIN b[124]
    DIRECTION OUTPUT ;
    USE SIGNAL ;
    PORT
      LAYER M4 ;
        RECT  0 14.112 0.192 14.136 ;
    END
  END b[124]
  PIN b[125]
    DIRECTION OUTPUT ;
    USE SIGNAL ;
    PORT
      LAYER M4 ;
        RECT  0 14.16 0.192 14.184 ;
    END
  END b[125]
  PIN b[126]
    DIRECTION OUTPUT ;
    USE SIGNAL ;
    PORT
      LAYER M4 ;
        RECT  0 14.208 0.192 14.232 ;
    END
  END b[126]
  PIN b[127]
    DIRECTION OUTPUT ;
    USE SIGNAL ;
    PORT
      LAYER M4 ;
        RECT  0 14.256 0.192 14.28 ;
    END
  END b[127]
  PIN b[128]
    DIRECTION OUTPUT ;
    USE SIGNAL ;
    PORT
      LAYER M4 ;
        RECT  0 14.304 0.192 14.328 ;
    END
  END b[128]
  PIN b[129]
    DIRECTION OUTPUT ;
    USE SIGNAL ;
    PORT
      LAYER M4 ;
        RECT  0 14.352 0.192 14.376 ;
    END
  END b[129]
  PIN b[12]
    DIRECTION OUTPUT ;
    USE SIGNAL ;
    PORT
      LAYER M4 ;
        RECT  0 8.736 0.192 8.76 ;
    END
  END b[12]
  PIN b[130]
    DIRECTION OUTPUT ;
    USE SIGNAL ;
    PORT
      LAYER M4 ;
        RECT  0 14.4 0.192 14.424 ;
    END
  END b[130]
  PIN b[131]
    DIRECTION OUTPUT ;
    USE SIGNAL ;
    PORT
      LAYER M4 ;
        RECT  0 14.448 0.192 14.472 ;
    END
  END b[131]
  PIN b[132]
    DIRECTION OUTPUT ;
    USE SIGNAL ;
    PORT
      LAYER M4 ;
        RECT  0 14.496 0.192 14.52 ;
    END
  END b[132]
  PIN b[133]
    DIRECTION OUTPUT ;
    USE SIGNAL ;
    PORT
      LAYER M4 ;
        RECT  0 14.544 0.192 14.568 ;
    END
  END b[133]
  PIN b[134]
    DIRECTION OUTPUT ;
    USE SIGNAL ;
    PORT
      LAYER M4 ;
        RECT  0 14.592 0.192 14.616 ;
    END
  END b[134]
  PIN b[135]
    DIRECTION OUTPUT ;
    USE SIGNAL ;
    PORT
      LAYER M4 ;
        RECT  0 14.64 0.192 14.664 ;
    END
  END b[135]
  PIN b[136]
    DIRECTION OUTPUT ;
    USE SIGNAL ;
    PORT
      LAYER M4 ;
        RECT  0 14.688 0.192 14.712 ;
    END
  END b[136]
  PIN b[137]
    DIRECTION OUTPUT ;
    USE SIGNAL ;
    PORT
      LAYER M4 ;
        RECT  0 14.736 0.192 14.76 ;
    END
  END b[137]
  PIN b[138]
    DIRECTION OUTPUT ;
    USE SIGNAL ;
    PORT
      LAYER M4 ;
        RECT  0 14.784 0.192 14.808 ;
    END
  END b[138]
  PIN b[139]
    DIRECTION OUTPUT ;
    USE SIGNAL ;
    PORT
      LAYER M4 ;
        RECT  0 14.832 0.192 14.856 ;
    END
  END b[139]
  PIN b[13]
    DIRECTION OUTPUT ;
    USE SIGNAL ;
    PORT
      LAYER M4 ;
        RECT  0 8.784 0.192 8.808 ;
    END
  END b[13]
  PIN b[140]
    DIRECTION OUTPUT ;
    USE SIGNAL ;
    PORT
      LAYER M4 ;
        RECT  0 14.88 0.192 14.904 ;
    END
  END b[140]
  PIN b[141]
    DIRECTION OUTPUT ;
    USE SIGNAL ;
    PORT
      LAYER M4 ;
        RECT  0 14.928 0.192 14.952 ;
    END
  END b[141]
  PIN b[142]
    DIRECTION OUTPUT ;
    USE SIGNAL ;
    PORT
      LAYER M4 ;
        RECT  0 14.976 0.192 15 ;
    END
  END b[142]
  PIN b[143]
    DIRECTION OUTPUT ;
    USE SIGNAL ;
    PORT
      LAYER M4 ;
        RECT  0 15.024 0.192 15.048 ;
    END
  END b[143]
  PIN b[144]
    DIRECTION OUTPUT ;
    USE SIGNAL ;
    PORT
      LAYER M4 ;
        RECT  0 15.072 0.192 15.096 ;
    END
  END b[144]
  PIN b[145]
    DIRECTION OUTPUT ;
    USE SIGNAL ;
    PORT
      LAYER M4 ;
        RECT  0 15.12 0.192 15.144 ;
    END
  END b[145]
  PIN b[146]
    DIRECTION OUTPUT ;
    USE SIGNAL ;
    PORT
      LAYER M4 ;
        RECT  0 15.168 0.192 15.192 ;
    END
  END b[146]
  PIN b[147]
    DIRECTION OUTPUT ;
    USE SIGNAL ;
    PORT
      LAYER M4 ;
        RECT  0 15.216 0.192 15.24 ;
    END
  END b[147]
  PIN b[148]
    DIRECTION OUTPUT ;
    USE SIGNAL ;
    PORT
      LAYER M4 ;
        RECT  0 15.264 0.192 15.288 ;
    END
  END b[148]
  PIN b[149]
    DIRECTION OUTPUT ;
    USE SIGNAL ;
    PORT
      LAYER M4 ;
        RECT  0 15.312 0.192 15.336 ;
    END
  END b[149]
  PIN b[14]
    DIRECTION OUTPUT ;
    USE SIGNAL ;
    PORT
      LAYER M4 ;
        RECT  0 8.832 0.192 8.856 ;
    END
  END b[14]
  PIN b[150]
    DIRECTION OUTPUT ;
    USE SIGNAL ;
    PORT
      LAYER M4 ;
        RECT  0 15.36 0.192 15.384 ;
    END
  END b[150]
  PIN b[151]
    DIRECTION OUTPUT ;
    USE SIGNAL ;
    PORT
      LAYER M4 ;
        RECT  0 15.408 0.192 15.432 ;
    END
  END b[151]
  PIN b[152]
    DIRECTION OUTPUT ;
    USE SIGNAL ;
    PORT
      LAYER M4 ;
        RECT  0 15.456 0.192 15.48 ;
    END
  END b[152]
  PIN b[153]
    DIRECTION OUTPUT ;
    USE SIGNAL ;
    PORT
      LAYER M4 ;
        RECT  0 15.504 0.192 15.528 ;
    END
  END b[153]
  PIN b[154]
    DIRECTION OUTPUT ;
    USE SIGNAL ;
    PORT
      LAYER M4 ;
        RECT  0 15.552 0.192 15.576 ;
    END
  END b[154]
  PIN b[155]
    DIRECTION OUTPUT ;
    USE SIGNAL ;
    PORT
      LAYER M4 ;
        RECT  0 15.6 0.192 15.624 ;
    END
  END b[155]
  PIN b[156]
    DIRECTION OUTPUT ;
    USE SIGNAL ;
    PORT
      LAYER M4 ;
        RECT  0 15.648 0.192 15.672 ;
    END
  END b[156]
  PIN b[157]
    DIRECTION OUTPUT ;
    USE SIGNAL ;
    PORT
      LAYER M4 ;
        RECT  0 15.696 0.192 15.72 ;
    END
  END b[157]
  PIN b[158]
    DIRECTION OUTPUT ;
    USE SIGNAL ;
    PORT
      LAYER M4 ;
        RECT  0 15.744 0.192 15.768 ;
    END
  END b[158]
  PIN b[159]
    DIRECTION OUTPUT ;
    USE SIGNAL ;
    PORT
      LAYER M4 ;
        RECT  0 15.792 0.192 15.816 ;
    END
  END b[159]
  PIN b[15]
    DIRECTION OUTPUT ;
    USE SIGNAL ;
    PORT
      LAYER M4 ;
        RECT  0 8.88 0.192 8.904 ;
    END
  END b[15]
  PIN b[160]
    DIRECTION OUTPUT ;
    USE SIGNAL ;
    PORT
      LAYER M4 ;
        RECT  0 15.84 0.192 15.864 ;
    END
  END b[160]
  PIN b[161]
    DIRECTION OUTPUT ;
    USE SIGNAL ;
    PORT
      LAYER M4 ;
        RECT  0 15.888 0.192 15.912 ;
    END
  END b[161]
  PIN b[162]
    DIRECTION OUTPUT ;
    USE SIGNAL ;
    PORT
      LAYER M4 ;
        RECT  0 15.936 0.192 15.96 ;
    END
  END b[162]
  PIN b[163]
    DIRECTION OUTPUT ;
    USE SIGNAL ;
    PORT
      LAYER M4 ;
        RECT  0 15.984 0.192 16.008 ;
    END
  END b[163]
  PIN b[164]
    DIRECTION OUTPUT ;
    USE SIGNAL ;
    PORT
      LAYER M4 ;
        RECT  0 16.032 0.192 16.056 ;
    END
  END b[164]
  PIN b[165]
    DIRECTION OUTPUT ;
    USE SIGNAL ;
    PORT
      LAYER M4 ;
        RECT  0 16.08 0.192 16.104 ;
    END
  END b[165]
  PIN b[166]
    DIRECTION OUTPUT ;
    USE SIGNAL ;
    PORT
      LAYER M4 ;
        RECT  0 16.128 0.192 16.152 ;
    END
  END b[166]
  PIN b[167]
    DIRECTION OUTPUT ;
    USE SIGNAL ;
    PORT
      LAYER M4 ;
        RECT  0 16.176 0.192 16.2 ;
    END
  END b[167]
  PIN b[168]
    DIRECTION OUTPUT ;
    USE SIGNAL ;
    PORT
      LAYER M4 ;
        RECT  0 16.224 0.192 16.248 ;
    END
  END b[168]
  PIN b[169]
    DIRECTION OUTPUT ;
    USE SIGNAL ;
    PORT
      LAYER M4 ;
        RECT  0 16.272 0.192 16.296 ;
    END
  END b[169]
  PIN b[16]
    DIRECTION OUTPUT ;
    USE SIGNAL ;
    PORT
      LAYER M4 ;
        RECT  0 8.928 0.192 8.952 ;
    END
  END b[16]
  PIN b[170]
    DIRECTION OUTPUT ;
    USE SIGNAL ;
    PORT
      LAYER M4 ;
        RECT  0 16.32 0.192 16.344 ;
    END
  END b[170]
  PIN b[171]
    DIRECTION OUTPUT ;
    USE SIGNAL ;
    PORT
      LAYER M4 ;
        RECT  0 16.368 0.192 16.392 ;
    END
  END b[171]
  PIN b[172]
    DIRECTION OUTPUT ;
    USE SIGNAL ;
    PORT
      LAYER M4 ;
        RECT  0 16.416 0.192 16.44 ;
    END
  END b[172]
  PIN b[173]
    DIRECTION OUTPUT ;
    USE SIGNAL ;
    PORT
      LAYER M4 ;
        RECT  0 16.464 0.192 16.488 ;
    END
  END b[173]
  PIN b[174]
    DIRECTION OUTPUT ;
    USE SIGNAL ;
    PORT
      LAYER M4 ;
        RECT  0 16.512 0.192 16.536 ;
    END
  END b[174]
  PIN b[175]
    DIRECTION OUTPUT ;
    USE SIGNAL ;
    PORT
      LAYER M4 ;
        RECT  0 16.56 0.192 16.584 ;
    END
  END b[175]
  PIN b[176]
    DIRECTION OUTPUT ;
    USE SIGNAL ;
    PORT
      LAYER M4 ;
        RECT  0 16.608 0.192 16.632 ;
    END
  END b[176]
  PIN b[177]
    DIRECTION OUTPUT ;
    USE SIGNAL ;
    PORT
      LAYER M4 ;
        RECT  0 16.656 0.192 16.68 ;
    END
  END b[177]
  PIN b[178]
    DIRECTION OUTPUT ;
    USE SIGNAL ;
    PORT
      LAYER M4 ;
        RECT  0 16.704 0.192 16.728 ;
    END
  END b[178]
  PIN b[179]
    DIRECTION OUTPUT ;
    USE SIGNAL ;
    PORT
      LAYER M4 ;
        RECT  0 16.752 0.192 16.776 ;
    END
  END b[179]
  PIN b[17]
    DIRECTION OUTPUT ;
    USE SIGNAL ;
    PORT
      LAYER M4 ;
        RECT  0 8.976 0.192 9 ;
    END
  END b[17]
  PIN b[180]
    DIRECTION OUTPUT ;
    USE SIGNAL ;
    PORT
      LAYER M4 ;
        RECT  0 16.8 0.192 16.824 ;
    END
  END b[180]
  PIN b[181]
    DIRECTION OUTPUT ;
    USE SIGNAL ;
    PORT
      LAYER M4 ;
        RECT  0 16.848 0.192 16.872 ;
    END
  END b[181]
  PIN b[182]
    DIRECTION OUTPUT ;
    USE SIGNAL ;
    PORT
      LAYER M4 ;
        RECT  0 16.896 0.192 16.92 ;
    END
  END b[182]
  PIN b[183]
    DIRECTION OUTPUT ;
    USE SIGNAL ;
    PORT
      LAYER M4 ;
        RECT  0 16.944 0.192 16.968 ;
    END
  END b[183]
  PIN b[184]
    DIRECTION OUTPUT ;
    USE SIGNAL ;
    PORT
      LAYER M4 ;
        RECT  0 16.992 0.192 17.016 ;
    END
  END b[184]
  PIN b[185]
    DIRECTION OUTPUT ;
    USE SIGNAL ;
    PORT
      LAYER M4 ;
        RECT  0 17.04 0.192 17.064 ;
    END
  END b[185]
  PIN b[186]
    DIRECTION OUTPUT ;
    USE SIGNAL ;
    PORT
      LAYER M4 ;
        RECT  0 17.088 0.192 17.112 ;
    END
  END b[186]
  PIN b[187]
    DIRECTION OUTPUT ;
    USE SIGNAL ;
    PORT
      LAYER M4 ;
        RECT  0 17.136 0.192 17.16 ;
    END
  END b[187]
  PIN b[188]
    DIRECTION OUTPUT ;
    USE SIGNAL ;
    PORT
      LAYER M4 ;
        RECT  0 17.184 0.192 17.208 ;
    END
  END b[188]
  PIN b[189]
    DIRECTION OUTPUT ;
    USE SIGNAL ;
    PORT
      LAYER M4 ;
        RECT  0 17.232 0.192 17.256 ;
    END
  END b[189]
  PIN b[18]
    DIRECTION OUTPUT ;
    USE SIGNAL ;
    PORT
      LAYER M4 ;
        RECT  0 9.024 0.192 9.048 ;
    END
  END b[18]
  PIN b[190]
    DIRECTION OUTPUT ;
    USE SIGNAL ;
    PORT
      LAYER M4 ;
        RECT  0 17.28 0.192 17.304 ;
    END
  END b[190]
  PIN b[191]
    DIRECTION OUTPUT ;
    USE SIGNAL ;
    PORT
      LAYER M4 ;
        RECT  0 17.328 0.192 17.352 ;
    END
  END b[191]
  PIN b[192]
    DIRECTION OUTPUT ;
    USE SIGNAL ;
    PORT
      LAYER M4 ;
        RECT  0 17.376 0.192 17.4 ;
    END
  END b[192]
  PIN b[193]
    DIRECTION OUTPUT ;
    USE SIGNAL ;
    PORT
      LAYER M4 ;
        RECT  0 17.424 0.192 17.448 ;
    END
  END b[193]
  PIN b[194]
    DIRECTION OUTPUT ;
    USE SIGNAL ;
    PORT
      LAYER M4 ;
        RECT  0 17.472 0.192 17.496 ;
    END
  END b[194]
  PIN b[195]
    DIRECTION OUTPUT ;
    USE SIGNAL ;
    PORT
      LAYER M4 ;
        RECT  0 17.52 0.192 17.544 ;
    END
  END b[195]
  PIN b[196]
    DIRECTION OUTPUT ;
    USE SIGNAL ;
    PORT
      LAYER M4 ;
        RECT  0 17.568 0.192 17.592 ;
    END
  END b[196]
  PIN b[197]
    DIRECTION OUTPUT ;
    USE SIGNAL ;
    PORT
      LAYER M4 ;
        RECT  0 17.616 0.192 17.64 ;
    END
  END b[197]
  PIN b[198]
    DIRECTION OUTPUT ;
    USE SIGNAL ;
    PORT
      LAYER M4 ;
        RECT  0 17.664 0.192 17.688 ;
    END
  END b[198]
  PIN b[199]
    DIRECTION OUTPUT ;
    USE SIGNAL ;
    PORT
      LAYER M4 ;
        RECT  0 17.712 0.192 17.736 ;
    END
  END b[199]
  PIN b[19]
    DIRECTION OUTPUT ;
    USE SIGNAL ;
    PORT
      LAYER M4 ;
        RECT  0 9.072 0.192 9.096 ;
    END
  END b[19]
  PIN b[1]
    DIRECTION OUTPUT ;
    USE SIGNAL ;
    PORT
      LAYER M4 ;
        RECT  0 8.208 0.192 8.232 ;
    END
  END b[1]
  PIN b[200]
    DIRECTION OUTPUT ;
    USE SIGNAL ;
    PORT
      LAYER M4 ;
        RECT  0 17.76 0.192 17.784 ;
    END
  END b[200]
  PIN b[201]
    DIRECTION OUTPUT ;
    USE SIGNAL ;
    PORT
      LAYER M4 ;
        RECT  0 17.808 0.192 17.832 ;
    END
  END b[201]
  PIN b[202]
    DIRECTION OUTPUT ;
    USE SIGNAL ;
    PORT
      LAYER M4 ;
        RECT  0 17.856 0.192 17.88 ;
    END
  END b[202]
  PIN b[203]
    DIRECTION OUTPUT ;
    USE SIGNAL ;
    PORT
      LAYER M4 ;
        RECT  0 17.904 0.192 17.928 ;
    END
  END b[203]
  PIN b[204]
    DIRECTION OUTPUT ;
    USE SIGNAL ;
    PORT
      LAYER M4 ;
        RECT  0 17.952 0.192 17.976 ;
    END
  END b[204]
  PIN b[205]
    DIRECTION OUTPUT ;
    USE SIGNAL ;
    PORT
      LAYER M4 ;
        RECT  0 18 0.192 18.024 ;
    END
  END b[205]
  PIN b[206]
    DIRECTION OUTPUT ;
    USE SIGNAL ;
    PORT
      LAYER M4 ;
        RECT  0 18.048 0.192 18.072 ;
    END
  END b[206]
  PIN b[207]
    DIRECTION OUTPUT ;
    USE SIGNAL ;
    PORT
      LAYER M4 ;
        RECT  0 18.096 0.192 18.12 ;
    END
  END b[207]
  PIN b[208]
    DIRECTION OUTPUT ;
    USE SIGNAL ;
    PORT
      LAYER M4 ;
        RECT  0 18.144 0.192 18.168 ;
    END
  END b[208]
  PIN b[209]
    DIRECTION OUTPUT ;
    USE SIGNAL ;
    PORT
      LAYER M4 ;
        RECT  0 18.192 0.192 18.216 ;
    END
  END b[209]
  PIN b[20]
    DIRECTION OUTPUT ;
    USE SIGNAL ;
    PORT
      LAYER M4 ;
        RECT  0 9.12 0.192 9.144 ;
    END
  END b[20]
  PIN b[210]
    DIRECTION OUTPUT ;
    USE SIGNAL ;
    PORT
      LAYER M4 ;
        RECT  0 18.24 0.192 18.264 ;
    END
  END b[210]
  PIN b[211]
    DIRECTION OUTPUT ;
    USE SIGNAL ;
    PORT
      LAYER M4 ;
        RECT  0 18.288 0.192 18.312 ;
    END
  END b[211]
  PIN b[212]
    DIRECTION OUTPUT ;
    USE SIGNAL ;
    PORT
      LAYER M4 ;
        RECT  0 18.336 0.192 18.36 ;
    END
  END b[212]
  PIN b[213]
    DIRECTION OUTPUT ;
    USE SIGNAL ;
    PORT
      LAYER M4 ;
        RECT  0 18.384 0.192 18.408 ;
    END
  END b[213]
  PIN b[214]
    DIRECTION OUTPUT ;
    USE SIGNAL ;
    PORT
      LAYER M4 ;
        RECT  0 18.432 0.192 18.456 ;
    END
  END b[214]
  PIN b[215]
    DIRECTION OUTPUT ;
    USE SIGNAL ;
    PORT
      LAYER M4 ;
        RECT  0 18.48 0.192 18.504 ;
    END
  END b[215]
  PIN b[216]
    DIRECTION OUTPUT ;
    USE SIGNAL ;
    PORT
      LAYER M4 ;
        RECT  0 18.528 0.192 18.552 ;
    END
  END b[216]
  PIN b[217]
    DIRECTION OUTPUT ;
    USE SIGNAL ;
    PORT
      LAYER M4 ;
        RECT  0 18.576 0.192 18.6 ;
    END
  END b[217]
  PIN b[218]
    DIRECTION OUTPUT ;
    USE SIGNAL ;
    PORT
      LAYER M4 ;
        RECT  0 18.624 0.192 18.648 ;
    END
  END b[218]
  PIN b[219]
    DIRECTION OUTPUT ;
    USE SIGNAL ;
    PORT
      LAYER M4 ;
        RECT  0 18.672 0.192 18.696 ;
    END
  END b[219]
  PIN b[21]
    DIRECTION OUTPUT ;
    USE SIGNAL ;
    PORT
      LAYER M4 ;
        RECT  0 9.168 0.192 9.192 ;
    END
  END b[21]
  PIN b[220]
    DIRECTION OUTPUT ;
    USE SIGNAL ;
    PORT
      LAYER M4 ;
        RECT  0 18.72 0.192 18.744 ;
    END
  END b[220]
  PIN b[221]
    DIRECTION OUTPUT ;
    USE SIGNAL ;
    PORT
      LAYER M4 ;
        RECT  0 18.768 0.192 18.792 ;
    END
  END b[221]
  PIN b[222]
    DIRECTION OUTPUT ;
    USE SIGNAL ;
    PORT
      LAYER M4 ;
        RECT  0 18.816 0.192 18.84 ;
    END
  END b[222]
  PIN b[223]
    DIRECTION OUTPUT ;
    USE SIGNAL ;
    PORT
      LAYER M4 ;
        RECT  0 18.864 0.192 18.888 ;
    END
  END b[223]
  PIN b[224]
    DIRECTION OUTPUT ;
    USE SIGNAL ;
    PORT
      LAYER M4 ;
        RECT  0 18.912 0.192 18.936 ;
    END
  END b[224]
  PIN b[225]
    DIRECTION OUTPUT ;
    USE SIGNAL ;
    PORT
      LAYER M4 ;
        RECT  0 18.96 0.192 18.984 ;
    END
  END b[225]
  PIN b[226]
    DIRECTION OUTPUT ;
    USE SIGNAL ;
    PORT
      LAYER M4 ;
        RECT  0 19.008 0.192 19.032 ;
    END
  END b[226]
  PIN b[227]
    DIRECTION OUTPUT ;
    USE SIGNAL ;
    PORT
      LAYER M4 ;
        RECT  0 19.056 0.192 19.08 ;
    END
  END b[227]
  PIN b[228]
    DIRECTION OUTPUT ;
    USE SIGNAL ;
    PORT
      LAYER M4 ;
        RECT  0 19.104 0.192 19.128 ;
    END
  END b[228]
  PIN b[229]
    DIRECTION OUTPUT ;
    USE SIGNAL ;
    PORT
      LAYER M4 ;
        RECT  0 19.152 0.192 19.176 ;
    END
  END b[229]
  PIN b[22]
    DIRECTION OUTPUT ;
    USE SIGNAL ;
    PORT
      LAYER M4 ;
        RECT  0 9.216 0.192 9.24 ;
    END
  END b[22]
  PIN b[230]
    DIRECTION OUTPUT ;
    USE SIGNAL ;
    PORT
      LAYER M4 ;
        RECT  0 19.2 0.192 19.224 ;
    END
  END b[230]
  PIN b[231]
    DIRECTION OUTPUT ;
    USE SIGNAL ;
    PORT
      LAYER M4 ;
        RECT  0 19.248 0.192 19.272 ;
    END
  END b[231]
  PIN b[232]
    DIRECTION OUTPUT ;
    USE SIGNAL ;
    PORT
      LAYER M4 ;
        RECT  0 19.296 0.192 19.32 ;
    END
  END b[232]
  PIN b[233]
    DIRECTION OUTPUT ;
    USE SIGNAL ;
    PORT
      LAYER M4 ;
        RECT  0 19.344 0.192 19.368 ;
    END
  END b[233]
  PIN b[234]
    DIRECTION OUTPUT ;
    USE SIGNAL ;
    PORT
      LAYER M4 ;
        RECT  0 19.392 0.192 19.416 ;
    END
  END b[234]
  PIN b[235]
    DIRECTION OUTPUT ;
    USE SIGNAL ;
    PORT
      LAYER M4 ;
        RECT  0 19.44 0.192 19.464 ;
    END
  END b[235]
  PIN b[236]
    DIRECTION OUTPUT ;
    USE SIGNAL ;
    PORT
      LAYER M4 ;
        RECT  0 19.488 0.192 19.512 ;
    END
  END b[236]
  PIN b[237]
    DIRECTION OUTPUT ;
    USE SIGNAL ;
    PORT
      LAYER M4 ;
        RECT  0 19.536 0.192 19.56 ;
    END
  END b[237]
  PIN b[238]
    DIRECTION OUTPUT ;
    USE SIGNAL ;
    PORT
      LAYER M4 ;
        RECT  0 19.584 0.192 19.608 ;
    END
  END b[238]
  PIN b[239]
    DIRECTION OUTPUT ;
    USE SIGNAL ;
    PORT
      LAYER M4 ;
        RECT  0 19.632 0.192 19.656 ;
    END
  END b[239]
  PIN b[23]
    DIRECTION OUTPUT ;
    USE SIGNAL ;
    PORT
      LAYER M4 ;
        RECT  0 9.264 0.192 9.288 ;
    END
  END b[23]
  PIN b[240]
    DIRECTION OUTPUT ;
    USE SIGNAL ;
    PORT
      LAYER M4 ;
        RECT  0 19.68 0.192 19.704 ;
    END
  END b[240]
  PIN b[241]
    DIRECTION OUTPUT ;
    USE SIGNAL ;
    PORT
      LAYER M4 ;
        RECT  0 19.728 0.192 19.752 ;
    END
  END b[241]
  PIN b[242]
    DIRECTION OUTPUT ;
    USE SIGNAL ;
    PORT
      LAYER M4 ;
        RECT  0 19.776 0.192 19.8 ;
    END
  END b[242]
  PIN b[243]
    DIRECTION OUTPUT ;
    USE SIGNAL ;
    PORT
      LAYER M4 ;
        RECT  0 19.824 0.192 19.848 ;
    END
  END b[243]
  PIN b[244]
    DIRECTION OUTPUT ;
    USE SIGNAL ;
    PORT
      LAYER M4 ;
        RECT  0 19.872 0.192 19.896 ;
    END
  END b[244]
  PIN b[245]
    DIRECTION OUTPUT ;
    USE SIGNAL ;
    PORT
      LAYER M4 ;
        RECT  0 19.92 0.192 19.944 ;
    END
  END b[245]
  PIN b[246]
    DIRECTION OUTPUT ;
    USE SIGNAL ;
    PORT
      LAYER M4 ;
        RECT  0 19.968 0.192 19.992 ;
    END
  END b[246]
  PIN b[247]
    DIRECTION OUTPUT ;
    USE SIGNAL ;
    PORT
      LAYER M4 ;
        RECT  0 20.016 0.192 20.04 ;
    END
  END b[247]
  PIN b[248]
    DIRECTION OUTPUT ;
    USE SIGNAL ;
    PORT
      LAYER M4 ;
        RECT  0 20.064 0.192 20.088 ;
    END
  END b[248]
  PIN b[249]
    DIRECTION OUTPUT ;
    USE SIGNAL ;
    PORT
      LAYER M4 ;
        RECT  0 20.112 0.192 20.136 ;
    END
  END b[249]
  PIN b[24]
    DIRECTION OUTPUT ;
    USE SIGNAL ;
    PORT
      LAYER M4 ;
        RECT  0 9.312 0.192 9.336 ;
    END
  END b[24]
  PIN b[250]
    DIRECTION OUTPUT ;
    USE SIGNAL ;
    PORT
      LAYER M4 ;
        RECT  0 20.16 0.192 20.184 ;
    END
  END b[250]
  PIN b[251]
    DIRECTION OUTPUT ;
    USE SIGNAL ;
    PORT
      LAYER M4 ;
        RECT  0 20.208 0.192 20.232 ;
    END
  END b[251]
  PIN b[252]
    DIRECTION OUTPUT ;
    USE SIGNAL ;
    PORT
      LAYER M4 ;
        RECT  0 20.256 0.192 20.28 ;
    END
  END b[252]
  PIN b[253]
    DIRECTION OUTPUT ;
    USE SIGNAL ;
    PORT
      LAYER M4 ;
        RECT  0 20.304 0.192 20.328 ;
    END
  END b[253]
  PIN b[254]
    DIRECTION OUTPUT ;
    USE SIGNAL ;
    PORT
      LAYER M4 ;
        RECT  0 20.352 0.192 20.376 ;
    END
  END b[254]
  PIN b[255]
    DIRECTION OUTPUT ;
    USE SIGNAL ;
    PORT
      LAYER M4 ;
        RECT  0 20.4 0.192 20.424 ;
    END
  END b[255]
  PIN b[256]
    DIRECTION INPUT ;
    USE SIGNAL ;
    PORT
      LAYER M4 ;
        RECT  0 20.448 0.192 20.472 ;
    END
  END b[256]
  PIN b[257]
    DIRECTION INPUT ;
    USE SIGNAL ;
    PORT
      LAYER M4 ;
        RECT  0 20.496 0.192 20.52 ;
    END
  END b[257]
  PIN b[258]
    DIRECTION INPUT ;
    USE SIGNAL ;
    PORT
      LAYER M4 ;
        RECT  0 20.544 0.192 20.568 ;
    END
  END b[258]
  PIN b[259]
    DIRECTION INPUT ;
    USE SIGNAL ;
    PORT
      LAYER M4 ;
        RECT  0 20.592 0.192 20.616 ;
    END
  END b[259]
  PIN b[25]
    DIRECTION OUTPUT ;
    USE SIGNAL ;
    PORT
      LAYER M4 ;
        RECT  0 9.36 0.192 9.384 ;
    END
  END b[25]
  PIN b[260]
    DIRECTION INPUT ;
    USE SIGNAL ;
    PORT
      LAYER M4 ;
        RECT  0 20.64 0.192 20.664 ;
    END
  END b[260]
  PIN b[261]
    DIRECTION INPUT ;
    USE SIGNAL ;
    PORT
      LAYER M4 ;
        RECT  0 20.688 0.192 20.712 ;
    END
  END b[261]
  PIN b[262]
    DIRECTION INPUT ;
    USE SIGNAL ;
    PORT
      LAYER M4 ;
        RECT  0 20.736 0.192 20.76 ;
    END
  END b[262]
  PIN b[263]
    DIRECTION INPUT ;
    USE SIGNAL ;
    PORT
      LAYER M4 ;
        RECT  0 20.784 0.192 20.808 ;
    END
  END b[263]
  PIN b[264]
    DIRECTION INPUT ;
    USE SIGNAL ;
    PORT
      LAYER M4 ;
        RECT  0 20.832 0.192 20.856 ;
    END
  END b[264]
  PIN b[265]
    DIRECTION INPUT ;
    USE SIGNAL ;
    PORT
      LAYER M4 ;
        RECT  0 20.88 0.192 20.904 ;
    END
  END b[265]
  PIN b[266]
    DIRECTION INPUT ;
    USE SIGNAL ;
    PORT
      LAYER M4 ;
        RECT  0 20.928 0.192 20.952 ;
    END
  END b[266]
  PIN b[267]
    DIRECTION INPUT ;
    USE SIGNAL ;
    PORT
      LAYER M4 ;
        RECT  0 20.976 0.192 21 ;
    END
  END b[267]
  PIN b[268]
    DIRECTION INPUT ;
    USE SIGNAL ;
    PORT
      LAYER M4 ;
        RECT  0 21.024 0.192 21.048 ;
    END
  END b[268]
  PIN b[269]
    DIRECTION INPUT ;
    USE SIGNAL ;
    PORT
      LAYER M4 ;
        RECT  0 21.072 0.192 21.096 ;
    END
  END b[269]
  PIN b[26]
    DIRECTION OUTPUT ;
    USE SIGNAL ;
    PORT
      LAYER M4 ;
        RECT  0 9.408 0.192 9.432 ;
    END
  END b[26]
  PIN b[270]
    DIRECTION INPUT ;
    USE SIGNAL ;
    PORT
      LAYER M4 ;
        RECT  0 21.12 0.192 21.144 ;
    END
  END b[270]
  PIN b[271]
    DIRECTION INPUT ;
    USE SIGNAL ;
    PORT
      LAYER M4 ;
        RECT  0 21.168 0.192 21.192 ;
    END
  END b[271]
  PIN b[272]
    DIRECTION INPUT ;
    USE SIGNAL ;
    PORT
      LAYER M4 ;
        RECT  0 21.216 0.192 21.24 ;
    END
  END b[272]
  PIN b[273]
    DIRECTION INPUT ;
    USE SIGNAL ;
    PORT
      LAYER M4 ;
        RECT  0 21.264 0.192 21.288 ;
    END
  END b[273]
  PIN b[274]
    DIRECTION INPUT ;
    USE SIGNAL ;
    PORT
      LAYER M4 ;
        RECT  0 21.312 0.192 21.336 ;
    END
  END b[274]
  PIN b[275]
    DIRECTION INPUT ;
    USE SIGNAL ;
    PORT
      LAYER M4 ;
        RECT  0 21.36 0.192 21.384 ;
    END
  END b[275]
  PIN b[276]
    DIRECTION INPUT ;
    USE SIGNAL ;
    PORT
      LAYER M4 ;
        RECT  0 21.408 0.192 21.432 ;
    END
  END b[276]
  PIN b[277]
    DIRECTION INPUT ;
    USE SIGNAL ;
    PORT
      LAYER M4 ;
        RECT  0 21.456 0.192 21.48 ;
    END
  END b[277]
  PIN b[278]
    DIRECTION INPUT ;
    USE SIGNAL ;
    PORT
      LAYER M4 ;
        RECT  0 21.504 0.192 21.528 ;
    END
  END b[278]
  PIN b[279]
    DIRECTION INPUT ;
    USE SIGNAL ;
    PORT
      LAYER M4 ;
        RECT  0 21.552 0.192 21.576 ;
    END
  END b[279]
  PIN b[27]
    DIRECTION OUTPUT ;
    USE SIGNAL ;
    PORT
      LAYER M4 ;
        RECT  0 9.456 0.192 9.48 ;
    END
  END b[27]
  PIN b[280]
    DIRECTION INPUT ;
    USE SIGNAL ;
    PORT
      LAYER M4 ;
        RECT  0 21.6 0.192 21.624 ;
    END
  END b[280]
  PIN b[281]
    DIRECTION INPUT ;
    USE SIGNAL ;
    PORT
      LAYER M4 ;
        RECT  0 21.648 0.192 21.672 ;
    END
  END b[281]
  PIN b[282]
    DIRECTION INPUT ;
    USE SIGNAL ;
    PORT
      LAYER M4 ;
        RECT  0 21.696 0.192 21.72 ;
    END
  END b[282]
  PIN b[283]
    DIRECTION INPUT ;
    USE SIGNAL ;
    PORT
      LAYER M4 ;
        RECT  0 21.744 0.192 21.768 ;
    END
  END b[283]
  PIN b[284]
    DIRECTION INPUT ;
    USE SIGNAL ;
    PORT
      LAYER M4 ;
        RECT  0 21.792 0.192 21.816 ;
    END
  END b[284]
  PIN b[285]
    DIRECTION INPUT ;
    USE SIGNAL ;
    PORT
      LAYER M4 ;
        RECT  0 21.84 0.192 21.864 ;
    END
  END b[285]
  PIN b[286]
    DIRECTION INPUT ;
    USE SIGNAL ;
    PORT
      LAYER M4 ;
        RECT  0 21.888 0.192 21.912 ;
    END
  END b[286]
  PIN b[287]
    DIRECTION INPUT ;
    USE SIGNAL ;
    PORT
      LAYER M4 ;
        RECT  0 21.936 0.192 21.96 ;
    END
  END b[287]
  PIN b[288]
    DIRECTION INPUT ;
    USE SIGNAL ;
    PORT
      LAYER M4 ;
        RECT  0 21.984 0.192 22.008 ;
    END
  END b[288]
  PIN b[289]
    DIRECTION INPUT ;
    USE SIGNAL ;
    PORT
      LAYER M4 ;
        RECT  0 22.032 0.192 22.056 ;
    END
  END b[289]
  PIN b[28]
    DIRECTION OUTPUT ;
    USE SIGNAL ;
    PORT
      LAYER M4 ;
        RECT  0 9.504 0.192 9.528 ;
    END
  END b[28]
  PIN b[290]
    DIRECTION INPUT ;
    USE SIGNAL ;
    PORT
      LAYER M4 ;
        RECT  0 22.08 0.192 22.104 ;
    END
  END b[290]
  PIN b[291]
    DIRECTION INPUT ;
    USE SIGNAL ;
    PORT
      LAYER M4 ;
        RECT  0 22.128 0.192 22.152 ;
    END
  END b[291]
  PIN b[292]
    DIRECTION INPUT ;
    USE SIGNAL ;
    PORT
      LAYER M4 ;
        RECT  0 22.176 0.192 22.2 ;
    END
  END b[292]
  PIN b[293]
    DIRECTION INPUT ;
    USE SIGNAL ;
    PORT
      LAYER M4 ;
        RECT  0 22.224 0.192 22.248 ;
    END
  END b[293]
  PIN b[294]
    DIRECTION INPUT ;
    USE SIGNAL ;
    PORT
      LAYER M4 ;
        RECT  0 22.272 0.192 22.296 ;
    END
  END b[294]
  PIN b[295]
    DIRECTION INPUT ;
    USE SIGNAL ;
    PORT
      LAYER M4 ;
        RECT  0 22.32 0.192 22.344 ;
    END
  END b[295]
  PIN b[296]
    DIRECTION INPUT ;
    USE SIGNAL ;
    PORT
      LAYER M4 ;
        RECT  0 22.368 0.192 22.392 ;
    END
  END b[296]
  PIN b[297]
    DIRECTION INPUT ;
    USE SIGNAL ;
    PORT
      LAYER M4 ;
        RECT  0 22.416 0.192 22.44 ;
    END
  END b[297]
  PIN b[298]
    DIRECTION INPUT ;
    USE SIGNAL ;
    PORT
      LAYER M4 ;
        RECT  0 22.464 0.192 22.488 ;
    END
  END b[298]
  PIN b[299]
    DIRECTION INPUT ;
    USE SIGNAL ;
    PORT
      LAYER M4 ;
        RECT  0 22.512 0.192 22.536 ;
    END
  END b[299]
  PIN b[29]
    DIRECTION OUTPUT ;
    USE SIGNAL ;
    PORT
      LAYER M4 ;
        RECT  0 9.552 0.192 9.576 ;
    END
  END b[29]
  PIN b[2]
    DIRECTION OUTPUT ;
    USE SIGNAL ;
    PORT
      LAYER M4 ;
        RECT  0 8.256 0.192 8.28 ;
    END
  END b[2]
  PIN b[300]
    DIRECTION INPUT ;
    USE SIGNAL ;
    PORT
      LAYER M4 ;
        RECT  0 22.56 0.192 22.584 ;
    END
  END b[300]
  PIN b[301]
    DIRECTION INPUT ;
    USE SIGNAL ;
    PORT
      LAYER M4 ;
        RECT  0 22.608 0.192 22.632 ;
    END
  END b[301]
  PIN b[302]
    DIRECTION INPUT ;
    USE SIGNAL ;
    PORT
      LAYER M4 ;
        RECT  0 22.656 0.192 22.68 ;
    END
  END b[302]
  PIN b[303]
    DIRECTION INPUT ;
    USE SIGNAL ;
    PORT
      LAYER M4 ;
        RECT  0 22.704 0.192 22.728 ;
    END
  END b[303]
  PIN b[304]
    DIRECTION INPUT ;
    USE SIGNAL ;
    PORT
      LAYER M4 ;
        RECT  0 22.752 0.192 22.776 ;
    END
  END b[304]
  PIN b[305]
    DIRECTION INPUT ;
    USE SIGNAL ;
    PORT
      LAYER M4 ;
        RECT  0 22.8 0.192 22.824 ;
    END
  END b[305]
  PIN b[306]
    DIRECTION INPUT ;
    USE SIGNAL ;
    PORT
      LAYER M4 ;
        RECT  0 22.848 0.192 22.872 ;
    END
  END b[306]
  PIN b[307]
    DIRECTION INPUT ;
    USE SIGNAL ;
    PORT
      LAYER M4 ;
        RECT  0 22.896 0.192 22.92 ;
    END
  END b[307]
  PIN b[308]
    DIRECTION INPUT ;
    USE SIGNAL ;
    PORT
      LAYER M4 ;
        RECT  0 22.944 0.192 22.968 ;
    END
  END b[308]
  PIN b[309]
    DIRECTION INPUT ;
    USE SIGNAL ;
    PORT
      LAYER M4 ;
        RECT  0 22.992 0.192 23.016 ;
    END
  END b[309]
  PIN b[30]
    DIRECTION OUTPUT ;
    USE SIGNAL ;
    PORT
      LAYER M4 ;
        RECT  0 9.6 0.192 9.624 ;
    END
  END b[30]
  PIN b[310]
    DIRECTION INPUT ;
    USE SIGNAL ;
    PORT
      LAYER M4 ;
        RECT  0 23.04 0.192 23.064 ;
    END
  END b[310]
  PIN b[311]
    DIRECTION INPUT ;
    USE SIGNAL ;
    PORT
      LAYER M4 ;
        RECT  0 23.088 0.192 23.112 ;
    END
  END b[311]
  PIN b[312]
    DIRECTION INPUT ;
    USE SIGNAL ;
    PORT
      LAYER M4 ;
        RECT  0 23.136 0.192 23.16 ;
    END
  END b[312]
  PIN b[313]
    DIRECTION INPUT ;
    USE SIGNAL ;
    PORT
      LAYER M4 ;
        RECT  0 23.184 0.192 23.208 ;
    END
  END b[313]
  PIN b[314]
    DIRECTION INPUT ;
    USE SIGNAL ;
    PORT
      LAYER M4 ;
        RECT  0 23.232 0.192 23.256 ;
    END
  END b[314]
  PIN b[315]
    DIRECTION INPUT ;
    USE SIGNAL ;
    PORT
      LAYER M4 ;
        RECT  0 23.28 0.192 23.304 ;
    END
  END b[315]
  PIN b[316]
    DIRECTION INPUT ;
    USE SIGNAL ;
    PORT
      LAYER M4 ;
        RECT  0 23.328 0.192 23.352 ;
    END
  END b[316]
  PIN b[317]
    DIRECTION INPUT ;
    USE SIGNAL ;
    PORT
      LAYER M4 ;
        RECT  0 23.376 0.192 23.4 ;
    END
  END b[317]
  PIN b[318]
    DIRECTION INPUT ;
    USE SIGNAL ;
    PORT
      LAYER M4 ;
        RECT  0 23.424 0.192 23.448 ;
    END
  END b[318]
  PIN b[319]
    DIRECTION INPUT ;
    USE SIGNAL ;
    PORT
      LAYER M4 ;
        RECT  0 23.472 0.192 23.496 ;
    END
  END b[319]
  PIN b[31]
    DIRECTION OUTPUT ;
    USE SIGNAL ;
    PORT
      LAYER M4 ;
        RECT  0 9.648 0.192 9.672 ;
    END
  END b[31]
  PIN b[320]
    DIRECTION INPUT ;
    USE SIGNAL ;
    PORT
      LAYER M4 ;
        RECT  0 23.52 0.192 23.544 ;
    END
  END b[320]
  PIN b[321]
    DIRECTION INPUT ;
    USE SIGNAL ;
    PORT
      LAYER M4 ;
        RECT  0 23.568 0.192 23.592 ;
    END
  END b[321]
  PIN b[322]
    DIRECTION INPUT ;
    USE SIGNAL ;
    PORT
      LAYER M4 ;
        RECT  0 23.616 0.192 23.64 ;
    END
  END b[322]
  PIN b[323]
    DIRECTION INPUT ;
    USE SIGNAL ;
    PORT
      LAYER M4 ;
        RECT  0 23.664 0.192 23.688 ;
    END
  END b[323]
  PIN b[324]
    DIRECTION INPUT ;
    USE SIGNAL ;
    PORT
      LAYER M4 ;
        RECT  0 23.712 0.192 23.736 ;
    END
  END b[324]
  PIN b[325]
    DIRECTION INPUT ;
    USE SIGNAL ;
    PORT
      LAYER M4 ;
        RECT  0 23.76 0.192 23.784 ;
    END
  END b[325]
  PIN b[326]
    DIRECTION INPUT ;
    USE SIGNAL ;
    PORT
      LAYER M4 ;
        RECT  0 23.808 0.192 23.832 ;
    END
  END b[326]
  PIN b[327]
    DIRECTION INPUT ;
    USE SIGNAL ;
    PORT
      LAYER M4 ;
        RECT  0 23.856 0.192 23.88 ;
    END
  END b[327]
  PIN b[328]
    DIRECTION INPUT ;
    USE SIGNAL ;
    PORT
      LAYER M4 ;
        RECT  0 23.904 0.192 23.928 ;
    END
  END b[328]
  PIN b[329]
    DIRECTION INPUT ;
    USE SIGNAL ;
    PORT
      LAYER M4 ;
        RECT  0 23.952 0.192 23.976 ;
    END
  END b[329]
  PIN b[32]
    DIRECTION OUTPUT ;
    USE SIGNAL ;
    PORT
      LAYER M4 ;
        RECT  0 9.696 0.192 9.72 ;
    END
  END b[32]
  PIN b[330]
    DIRECTION INPUT ;
    USE SIGNAL ;
    PORT
      LAYER M4 ;
        RECT  0 24 0.192 24.024 ;
    END
  END b[330]
  PIN b[331]
    DIRECTION INPUT ;
    USE SIGNAL ;
    PORT
      LAYER M4 ;
        RECT  0 24.048 0.192 24.072 ;
    END
  END b[331]
  PIN b[332]
    DIRECTION INPUT ;
    USE SIGNAL ;
    PORT
      LAYER M4 ;
        RECT  0 24.096 0.192 24.12 ;
    END
  END b[332]
  PIN b[333]
    DIRECTION INPUT ;
    USE SIGNAL ;
    PORT
      LAYER M4 ;
        RECT  0 24.144 0.192 24.168 ;
    END
  END b[333]
  PIN b[334]
    DIRECTION INPUT ;
    USE SIGNAL ;
    PORT
      LAYER M4 ;
        RECT  0 24.192 0.192 24.216 ;
    END
  END b[334]
  PIN b[335]
    DIRECTION INPUT ;
    USE SIGNAL ;
    PORT
      LAYER M4 ;
        RECT  0 24.24 0.192 24.264 ;
    END
  END b[335]
  PIN b[336]
    DIRECTION INPUT ;
    USE SIGNAL ;
    PORT
      LAYER M4 ;
        RECT  0 24.288 0.192 24.312 ;
    END
  END b[336]
  PIN b[337]
    DIRECTION INPUT ;
    USE SIGNAL ;
    PORT
      LAYER M4 ;
        RECT  0 24.336 0.192 24.36 ;
    END
  END b[337]
  PIN b[338]
    DIRECTION INPUT ;
    USE SIGNAL ;
    PORT
      LAYER M4 ;
        RECT  0 24.384 0.192 24.408 ;
    END
  END b[338]
  PIN b[339]
    DIRECTION INPUT ;
    USE SIGNAL ;
    PORT
      LAYER M4 ;
        RECT  0 24.432 0.192 24.456 ;
    END
  END b[339]
  PIN b[33]
    DIRECTION OUTPUT ;
    USE SIGNAL ;
    PORT
      LAYER M4 ;
        RECT  0 9.744 0.192 9.768 ;
    END
  END b[33]
  PIN b[340]
    DIRECTION INPUT ;
    USE SIGNAL ;
    PORT
      LAYER M4 ;
        RECT  0 24.48 0.192 24.504 ;
    END
  END b[340]
  PIN b[341]
    DIRECTION INPUT ;
    USE SIGNAL ;
    PORT
      LAYER M4 ;
        RECT  0 24.528 0.192 24.552 ;
    END
  END b[341]
  PIN b[342]
    DIRECTION INPUT ;
    USE SIGNAL ;
    PORT
      LAYER M4 ;
        RECT  0 24.576 0.192 24.6 ;
    END
  END b[342]
  PIN b[343]
    DIRECTION INPUT ;
    USE SIGNAL ;
    PORT
      LAYER M4 ;
        RECT  0 24.624 0.192 24.648 ;
    END
  END b[343]
  PIN b[344]
    DIRECTION INPUT ;
    USE SIGNAL ;
    PORT
      LAYER M4 ;
        RECT  0 24.672 0.192 24.696 ;
    END
  END b[344]
  PIN b[345]
    DIRECTION INPUT ;
    USE SIGNAL ;
    PORT
      LAYER M4 ;
        RECT  0 24.72 0.192 24.744 ;
    END
  END b[345]
  PIN b[346]
    DIRECTION INPUT ;
    USE SIGNAL ;
    PORT
      LAYER M4 ;
        RECT  0 24.768 0.192 24.792 ;
    END
  END b[346]
  PIN b[347]
    DIRECTION INPUT ;
    USE SIGNAL ;
    PORT
      LAYER M4 ;
        RECT  0 24.816 0.192 24.84 ;
    END
  END b[347]
  PIN b[348]
    DIRECTION INPUT ;
    USE SIGNAL ;
    PORT
      LAYER M4 ;
        RECT  0 24.864 0.192 24.888 ;
    END
  END b[348]
  PIN b[349]
    DIRECTION INPUT ;
    USE SIGNAL ;
    PORT
      LAYER M4 ;
        RECT  0 24.912 0.192 24.936 ;
    END
  END b[349]
  PIN b[34]
    DIRECTION OUTPUT ;
    USE SIGNAL ;
    PORT
      LAYER M4 ;
        RECT  0 9.792 0.192 9.816 ;
    END
  END b[34]
  PIN b[350]
    DIRECTION INPUT ;
    USE SIGNAL ;
    PORT
      LAYER M4 ;
        RECT  0 24.96 0.192 24.984 ;
    END
  END b[350]
  PIN b[351]
    DIRECTION INPUT ;
    USE SIGNAL ;
    PORT
      LAYER M4 ;
        RECT  0 25.008 0.192 25.032 ;
    END
  END b[351]
  PIN b[352]
    DIRECTION INPUT ;
    USE SIGNAL ;
    PORT
      LAYER M4 ;
        RECT  0 25.056 0.192 25.08 ;
    END
  END b[352]
  PIN b[353]
    DIRECTION INPUT ;
    USE SIGNAL ;
    PORT
      LAYER M4 ;
        RECT  0 25.104 0.192 25.128 ;
    END
  END b[353]
  PIN b[354]
    DIRECTION INPUT ;
    USE SIGNAL ;
    PORT
      LAYER M4 ;
        RECT  0 25.152 0.192 25.176 ;
    END
  END b[354]
  PIN b[355]
    DIRECTION INPUT ;
    USE SIGNAL ;
    PORT
      LAYER M4 ;
        RECT  0 25.2 0.192 25.224 ;
    END
  END b[355]
  PIN b[356]
    DIRECTION INPUT ;
    USE SIGNAL ;
    PORT
      LAYER M4 ;
        RECT  0 25.248 0.192 25.272 ;
    END
  END b[356]
  PIN b[357]
    DIRECTION INPUT ;
    USE SIGNAL ;
    PORT
      LAYER M4 ;
        RECT  0 25.296 0.192 25.32 ;
    END
  END b[357]
  PIN b[358]
    DIRECTION INPUT ;
    USE SIGNAL ;
    PORT
      LAYER M4 ;
        RECT  0 25.344 0.192 25.368 ;
    END
  END b[358]
  PIN b[359]
    DIRECTION INPUT ;
    USE SIGNAL ;
    PORT
      LAYER M4 ;
        RECT  0 25.392 0.192 25.416 ;
    END
  END b[359]
  PIN b[35]
    DIRECTION OUTPUT ;
    USE SIGNAL ;
    PORT
      LAYER M4 ;
        RECT  0 9.84 0.192 9.864 ;
    END
  END b[35]
  PIN b[360]
    DIRECTION INPUT ;
    USE SIGNAL ;
    PORT
      LAYER M4 ;
        RECT  0 25.44 0.192 25.464 ;
    END
  END b[360]
  PIN b[361]
    DIRECTION INPUT ;
    USE SIGNAL ;
    PORT
      LAYER M4 ;
        RECT  0 25.488 0.192 25.512 ;
    END
  END b[361]
  PIN b[362]
    DIRECTION INPUT ;
    USE SIGNAL ;
    PORT
      LAYER M4 ;
        RECT  0 25.536 0.192 25.56 ;
    END
  END b[362]
  PIN b[363]
    DIRECTION INPUT ;
    USE SIGNAL ;
    PORT
      LAYER M4 ;
        RECT  0 25.584 0.192 25.608 ;
    END
  END b[363]
  PIN b[364]
    DIRECTION INPUT ;
    USE SIGNAL ;
    PORT
      LAYER M4 ;
        RECT  0 25.632 0.192 25.656 ;
    END
  END b[364]
  PIN b[365]
    DIRECTION INPUT ;
    USE SIGNAL ;
    PORT
      LAYER M4 ;
        RECT  0 25.68 0.192 25.704 ;
    END
  END b[365]
  PIN b[366]
    DIRECTION INPUT ;
    USE SIGNAL ;
    PORT
      LAYER M4 ;
        RECT  0 25.728 0.192 25.752 ;
    END
  END b[366]
  PIN b[367]
    DIRECTION INPUT ;
    USE SIGNAL ;
    PORT
      LAYER M4 ;
        RECT  0 25.776 0.192 25.8 ;
    END
  END b[367]
  PIN b[368]
    DIRECTION INPUT ;
    USE SIGNAL ;
    PORT
      LAYER M4 ;
        RECT  0 25.824 0.192 25.848 ;
    END
  END b[368]
  PIN b[369]
    DIRECTION INPUT ;
    USE SIGNAL ;
    PORT
      LAYER M4 ;
        RECT  0 25.872 0.192 25.896 ;
    END
  END b[369]
  PIN b[36]
    DIRECTION OUTPUT ;
    USE SIGNAL ;
    PORT
      LAYER M4 ;
        RECT  0 9.888 0.192 9.912 ;
    END
  END b[36]
  PIN b[370]
    DIRECTION INPUT ;
    USE SIGNAL ;
    PORT
      LAYER M4 ;
        RECT  0 25.92 0.192 25.944 ;
    END
  END b[370]
  PIN b[371]
    DIRECTION INPUT ;
    USE SIGNAL ;
    PORT
      LAYER M4 ;
        RECT  0 25.968 0.192 25.992 ;
    END
  END b[371]
  PIN b[372]
    DIRECTION INPUT ;
    USE SIGNAL ;
    PORT
      LAYER M4 ;
        RECT  0 26.016 0.192 26.04 ;
    END
  END b[372]
  PIN b[373]
    DIRECTION INPUT ;
    USE SIGNAL ;
    PORT
      LAYER M4 ;
        RECT  0 26.064 0.192 26.088 ;
    END
  END b[373]
  PIN b[374]
    DIRECTION INPUT ;
    USE SIGNAL ;
    PORT
      LAYER M4 ;
        RECT  0 26.112 0.192 26.136 ;
    END
  END b[374]
  PIN b[375]
    DIRECTION INPUT ;
    USE SIGNAL ;
    PORT
      LAYER M4 ;
        RECT  0 26.16 0.192 26.184 ;
    END
  END b[375]
  PIN b[376]
    DIRECTION INPUT ;
    USE SIGNAL ;
    PORT
      LAYER M4 ;
        RECT  0 26.208 0.192 26.232 ;
    END
  END b[376]
  PIN b[377]
    DIRECTION INPUT ;
    USE SIGNAL ;
    PORT
      LAYER M4 ;
        RECT  0 26.256 0.192 26.28 ;
    END
  END b[377]
  PIN b[378]
    DIRECTION INPUT ;
    USE SIGNAL ;
    PORT
      LAYER M4 ;
        RECT  0 26.304 0.192 26.328 ;
    END
  END b[378]
  PIN b[379]
    DIRECTION INPUT ;
    USE SIGNAL ;
    PORT
      LAYER M4 ;
        RECT  0 26.352 0.192 26.376 ;
    END
  END b[379]
  PIN b[37]
    DIRECTION OUTPUT ;
    USE SIGNAL ;
    PORT
      LAYER M4 ;
        RECT  0 9.936 0.192 9.96 ;
    END
  END b[37]
  PIN b[380]
    DIRECTION INPUT ;
    USE SIGNAL ;
    PORT
      LAYER M4 ;
        RECT  0 26.4 0.192 26.424 ;
    END
  END b[380]
  PIN b[381]
    DIRECTION INPUT ;
    USE SIGNAL ;
    PORT
      LAYER M4 ;
        RECT  0 26.448 0.192 26.472 ;
    END
  END b[381]
  PIN b[382]
    DIRECTION INPUT ;
    USE SIGNAL ;
    PORT
      LAYER M4 ;
        RECT  0 26.496 0.192 26.52 ;
    END
  END b[382]
  PIN b[383]
    DIRECTION INPUT ;
    USE SIGNAL ;
    PORT
      LAYER M4 ;
        RECT  0 26.544 0.192 26.568 ;
    END
  END b[383]
  PIN b[384]
    DIRECTION INPUT ;
    USE SIGNAL ;
    PORT
      LAYER M4 ;
        RECT  0 26.592 0.192 26.616 ;
    END
  END b[384]
  PIN b[385]
    DIRECTION INPUT ;
    USE SIGNAL ;
    PORT
      LAYER M4 ;
        RECT  0 26.64 0.192 26.664 ;
    END
  END b[385]
  PIN b[386]
    DIRECTION INPUT ;
    USE SIGNAL ;
    PORT
      LAYER M4 ;
        RECT  0 26.688 0.192 26.712 ;
    END
  END b[386]
  PIN b[387]
    DIRECTION INPUT ;
    USE SIGNAL ;
    PORT
      LAYER M4 ;
        RECT  0 26.736 0.192 26.76 ;
    END
  END b[387]
  PIN b[388]
    DIRECTION INPUT ;
    USE SIGNAL ;
    PORT
      LAYER M4 ;
        RECT  0 26.784 0.192 26.808 ;
    END
  END b[388]
  PIN b[389]
    DIRECTION INPUT ;
    USE SIGNAL ;
    PORT
      LAYER M4 ;
        RECT  0 26.832 0.192 26.856 ;
    END
  END b[389]
  PIN b[38]
    DIRECTION OUTPUT ;
    USE SIGNAL ;
    PORT
      LAYER M4 ;
        RECT  0 9.984 0.192 10.008 ;
    END
  END b[38]
  PIN b[390]
    DIRECTION INPUT ;
    USE SIGNAL ;
    PORT
      LAYER M4 ;
        RECT  0 26.88 0.192 26.904 ;
    END
  END b[390]
  PIN b[391]
    DIRECTION INPUT ;
    USE SIGNAL ;
    PORT
      LAYER M4 ;
        RECT  0 26.928 0.192 26.952 ;
    END
  END b[391]
  PIN b[392]
    DIRECTION INPUT ;
    USE SIGNAL ;
    PORT
      LAYER M4 ;
        RECT  0 26.976 0.192 27 ;
    END
  END b[392]
  PIN b[393]
    DIRECTION INPUT ;
    USE SIGNAL ;
    PORT
      LAYER M4 ;
        RECT  0 27.024 0.192 27.048 ;
    END
  END b[393]
  PIN b[394]
    DIRECTION INPUT ;
    USE SIGNAL ;
    PORT
      LAYER M4 ;
        RECT  0 27.072 0.192 27.096 ;
    END
  END b[394]
  PIN b[395]
    DIRECTION INPUT ;
    USE SIGNAL ;
    PORT
      LAYER M4 ;
        RECT  0 27.12 0.192 27.144 ;
    END
  END b[395]
  PIN b[396]
    DIRECTION INPUT ;
    USE SIGNAL ;
    PORT
      LAYER M4 ;
        RECT  0 27.168 0.192 27.192 ;
    END
  END b[396]
  PIN b[397]
    DIRECTION INPUT ;
    USE SIGNAL ;
    PORT
      LAYER M4 ;
        RECT  0 27.216 0.192 27.24 ;
    END
  END b[397]
  PIN b[398]
    DIRECTION INPUT ;
    USE SIGNAL ;
    PORT
      LAYER M4 ;
        RECT  0 27.264 0.192 27.288 ;
    END
  END b[398]
  PIN b[399]
    DIRECTION INPUT ;
    USE SIGNAL ;
    PORT
      LAYER M4 ;
        RECT  0 27.312 0.192 27.336 ;
    END
  END b[399]
  PIN b[39]
    DIRECTION OUTPUT ;
    USE SIGNAL ;
    PORT
      LAYER M4 ;
        RECT  0 10.032 0.192 10.056 ;
    END
  END b[39]
  PIN b[3]
    DIRECTION OUTPUT ;
    USE SIGNAL ;
    PORT
      LAYER M4 ;
        RECT  0 8.304 0.192 8.328 ;
    END
  END b[3]
  PIN b[400]
    DIRECTION INPUT ;
    USE SIGNAL ;
    PORT
      LAYER M4 ;
        RECT  0 27.36 0.192 27.384 ;
    END
  END b[400]
  PIN b[401]
    DIRECTION INPUT ;
    USE SIGNAL ;
    PORT
      LAYER M4 ;
        RECT  0 27.408 0.192 27.432 ;
    END
  END b[401]
  PIN b[402]
    DIRECTION INPUT ;
    USE SIGNAL ;
    PORT
      LAYER M4 ;
        RECT  0 27.456 0.192 27.48 ;
    END
  END b[402]
  PIN b[403]
    DIRECTION INPUT ;
    USE SIGNAL ;
    PORT
      LAYER M4 ;
        RECT  0 27.504 0.192 27.528 ;
    END
  END b[403]
  PIN b[404]
    DIRECTION INPUT ;
    USE SIGNAL ;
    PORT
      LAYER M4 ;
        RECT  0 27.552 0.192 27.576 ;
    END
  END b[404]
  PIN b[405]
    DIRECTION INPUT ;
    USE SIGNAL ;
    PORT
      LAYER M4 ;
        RECT  0 27.6 0.192 27.624 ;
    END
  END b[405]
  PIN b[406]
    DIRECTION INPUT ;
    USE SIGNAL ;
    PORT
      LAYER M4 ;
        RECT  0 27.648 0.192 27.672 ;
    END
  END b[406]
  PIN b[407]
    DIRECTION INPUT ;
    USE SIGNAL ;
    PORT
      LAYER M4 ;
        RECT  0 27.696 0.192 27.72 ;
    END
  END b[407]
  PIN b[408]
    DIRECTION INPUT ;
    USE SIGNAL ;
    PORT
      LAYER M4 ;
        RECT  0 27.744 0.192 27.768 ;
    END
  END b[408]
  PIN b[409]
    DIRECTION INPUT ;
    USE SIGNAL ;
    PORT
      LAYER M4 ;
        RECT  0 27.792 0.192 27.816 ;
    END
  END b[409]
  PIN b[40]
    DIRECTION OUTPUT ;
    USE SIGNAL ;
    PORT
      LAYER M4 ;
        RECT  0 10.08 0.192 10.104 ;
    END
  END b[40]
  PIN b[410]
    DIRECTION INPUT ;
    USE SIGNAL ;
    PORT
      LAYER M4 ;
        RECT  0 27.84 0.192 27.864 ;
    END
  END b[410]
  PIN b[411]
    DIRECTION INPUT ;
    USE SIGNAL ;
    PORT
      LAYER M4 ;
        RECT  0 27.888 0.192 27.912 ;
    END
  END b[411]
  PIN b[412]
    DIRECTION INPUT ;
    USE SIGNAL ;
    PORT
      LAYER M4 ;
        RECT  0 27.936 0.192 27.96 ;
    END
  END b[412]
  PIN b[413]
    DIRECTION INPUT ;
    USE SIGNAL ;
    PORT
      LAYER M4 ;
        RECT  0 27.984 0.192 28.008 ;
    END
  END b[413]
  PIN b[414]
    DIRECTION INPUT ;
    USE SIGNAL ;
    PORT
      LAYER M4 ;
        RECT  0 28.032 0.192 28.056 ;
    END
  END b[414]
  PIN b[415]
    DIRECTION INPUT ;
    USE SIGNAL ;
    PORT
      LAYER M4 ;
        RECT  0 28.08 0.192 28.104 ;
    END
  END b[415]
  PIN b[416]
    DIRECTION INPUT ;
    USE SIGNAL ;
    PORT
      LAYER M4 ;
        RECT  0 28.128 0.192 28.152 ;
    END
  END b[416]
  PIN b[417]
    DIRECTION INPUT ;
    USE SIGNAL ;
    PORT
      LAYER M4 ;
        RECT  0 28.176 0.192 28.2 ;
    END
  END b[417]
  PIN b[418]
    DIRECTION INPUT ;
    USE SIGNAL ;
    PORT
      LAYER M4 ;
        RECT  0 28.224 0.192 28.248 ;
    END
  END b[418]
  PIN b[419]
    DIRECTION INPUT ;
    USE SIGNAL ;
    PORT
      LAYER M4 ;
        RECT  0 28.272 0.192 28.296 ;
    END
  END b[419]
  PIN b[41]
    DIRECTION OUTPUT ;
    USE SIGNAL ;
    PORT
      LAYER M4 ;
        RECT  0 10.128 0.192 10.152 ;
    END
  END b[41]
  PIN b[420]
    DIRECTION INPUT ;
    USE SIGNAL ;
    PORT
      LAYER M4 ;
        RECT  0 28.32 0.192 28.344 ;
    END
  END b[420]
  PIN b[421]
    DIRECTION INPUT ;
    USE SIGNAL ;
    PORT
      LAYER M4 ;
        RECT  0 28.368 0.192 28.392 ;
    END
  END b[421]
  PIN b[422]
    DIRECTION INPUT ;
    USE SIGNAL ;
    PORT
      LAYER M4 ;
        RECT  0 28.416 0.192 28.44 ;
    END
  END b[422]
  PIN b[423]
    DIRECTION INPUT ;
    USE SIGNAL ;
    PORT
      LAYER M4 ;
        RECT  0 28.464 0.192 28.488 ;
    END
  END b[423]
  PIN b[424]
    DIRECTION INPUT ;
    USE SIGNAL ;
    PORT
      LAYER M4 ;
        RECT  0 28.512 0.192 28.536 ;
    END
  END b[424]
  PIN b[425]
    DIRECTION INPUT ;
    USE SIGNAL ;
    PORT
      LAYER M4 ;
        RECT  0 28.56 0.192 28.584 ;
    END
  END b[425]
  PIN b[426]
    DIRECTION INPUT ;
    USE SIGNAL ;
    PORT
      LAYER M4 ;
        RECT  0 28.608 0.192 28.632 ;
    END
  END b[426]
  PIN b[427]
    DIRECTION INPUT ;
    USE SIGNAL ;
    PORT
      LAYER M4 ;
        RECT  0 28.656 0.192 28.68 ;
    END
  END b[427]
  PIN b[428]
    DIRECTION INPUT ;
    USE SIGNAL ;
    PORT
      LAYER M4 ;
        RECT  0 28.704 0.192 28.728 ;
    END
  END b[428]
  PIN b[429]
    DIRECTION INPUT ;
    USE SIGNAL ;
    PORT
      LAYER M4 ;
        RECT  0 28.752 0.192 28.776 ;
    END
  END b[429]
  PIN b[42]
    DIRECTION OUTPUT ;
    USE SIGNAL ;
    PORT
      LAYER M4 ;
        RECT  0 10.176 0.192 10.2 ;
    END
  END b[42]
  PIN b[430]
    DIRECTION INPUT ;
    USE SIGNAL ;
    PORT
      LAYER M4 ;
        RECT  0 28.8 0.192 28.824 ;
    END
  END b[430]
  PIN b[431]
    DIRECTION INPUT ;
    USE SIGNAL ;
    PORT
      LAYER M4 ;
        RECT  0 28.848 0.192 28.872 ;
    END
  END b[431]
  PIN b[432]
    DIRECTION INPUT ;
    USE SIGNAL ;
    PORT
      LAYER M4 ;
        RECT  0 28.896 0.192 28.92 ;
    END
  END b[432]
  PIN b[433]
    DIRECTION INPUT ;
    USE SIGNAL ;
    PORT
      LAYER M4 ;
        RECT  0 28.944 0.192 28.968 ;
    END
  END b[433]
  PIN b[434]
    DIRECTION INPUT ;
    USE SIGNAL ;
    PORT
      LAYER M4 ;
        RECT  0 28.992 0.192 29.016 ;
    END
  END b[434]
  PIN b[435]
    DIRECTION INPUT ;
    USE SIGNAL ;
    PORT
      LAYER M4 ;
        RECT  0 29.04 0.192 29.064 ;
    END
  END b[435]
  PIN b[436]
    DIRECTION INPUT ;
    USE SIGNAL ;
    PORT
      LAYER M4 ;
        RECT  0 29.088 0.192 29.112 ;
    END
  END b[436]
  PIN b[437]
    DIRECTION INPUT ;
    USE SIGNAL ;
    PORT
      LAYER M4 ;
        RECT  0 29.136 0.192 29.16 ;
    END
  END b[437]
  PIN b[438]
    DIRECTION INPUT ;
    USE SIGNAL ;
    PORT
      LAYER M4 ;
        RECT  0 29.184 0.192 29.208 ;
    END
  END b[438]
  PIN b[439]
    DIRECTION INPUT ;
    USE SIGNAL ;
    PORT
      LAYER M4 ;
        RECT  0 29.232 0.192 29.256 ;
    END
  END b[439]
  PIN b[43]
    DIRECTION OUTPUT ;
    USE SIGNAL ;
    PORT
      LAYER M4 ;
        RECT  0 10.224 0.192 10.248 ;
    END
  END b[43]
  PIN b[440]
    DIRECTION INPUT ;
    USE SIGNAL ;
    PORT
      LAYER M4 ;
        RECT  0 29.28 0.192 29.304 ;
    END
  END b[440]
  PIN b[441]
    DIRECTION INPUT ;
    USE SIGNAL ;
    PORT
      LAYER M4 ;
        RECT  0 29.328 0.192 29.352 ;
    END
  END b[441]
  PIN b[442]
    DIRECTION INPUT ;
    USE SIGNAL ;
    PORT
      LAYER M4 ;
        RECT  0 29.376 0.192 29.4 ;
    END
  END b[442]
  PIN b[443]
    DIRECTION INPUT ;
    USE SIGNAL ;
    PORT
      LAYER M4 ;
        RECT  0 29.424 0.192 29.448 ;
    END
  END b[443]
  PIN b[444]
    DIRECTION INPUT ;
    USE SIGNAL ;
    PORT
      LAYER M4 ;
        RECT  0 29.472 0.192 29.496 ;
    END
  END b[444]
  PIN b[445]
    DIRECTION INPUT ;
    USE SIGNAL ;
    PORT
      LAYER M4 ;
        RECT  0 29.52 0.192 29.544 ;
    END
  END b[445]
  PIN b[446]
    DIRECTION INPUT ;
    USE SIGNAL ;
    PORT
      LAYER M4 ;
        RECT  0 29.568 0.192 29.592 ;
    END
  END b[446]
  PIN b[447]
    DIRECTION INPUT ;
    USE SIGNAL ;
    PORT
      LAYER M4 ;
        RECT  0 29.616 0.192 29.64 ;
    END
  END b[447]
  PIN b[448]
    DIRECTION INPUT ;
    USE SIGNAL ;
    PORT
      LAYER M4 ;
        RECT  0 29.664 0.192 29.688 ;
    END
  END b[448]
  PIN b[449]
    DIRECTION INPUT ;
    USE SIGNAL ;
    PORT
      LAYER M4 ;
        RECT  0 29.712 0.192 29.736 ;
    END
  END b[449]
  PIN b[44]
    DIRECTION OUTPUT ;
    USE SIGNAL ;
    PORT
      LAYER M4 ;
        RECT  0 10.272 0.192 10.296 ;
    END
  END b[44]
  PIN b[450]
    DIRECTION INPUT ;
    USE SIGNAL ;
    PORT
      LAYER M4 ;
        RECT  0 29.76 0.192 29.784 ;
    END
  END b[450]
  PIN b[451]
    DIRECTION INPUT ;
    USE SIGNAL ;
    PORT
      LAYER M4 ;
        RECT  0 29.808 0.192 29.832 ;
    END
  END b[451]
  PIN b[452]
    DIRECTION INPUT ;
    USE SIGNAL ;
    PORT
      LAYER M4 ;
        RECT  0 29.856 0.192 29.88 ;
    END
  END b[452]
  PIN b[453]
    DIRECTION INPUT ;
    USE SIGNAL ;
    PORT
      LAYER M4 ;
        RECT  0 29.904 0.192 29.928 ;
    END
  END b[453]
  PIN b[454]
    DIRECTION INPUT ;
    USE SIGNAL ;
    PORT
      LAYER M4 ;
        RECT  0 29.952 0.192 29.976 ;
    END
  END b[454]
  PIN b[455]
    DIRECTION INPUT ;
    USE SIGNAL ;
    PORT
      LAYER M4 ;
        RECT  0 30 0.192 30.024 ;
    END
  END b[455]
  PIN b[456]
    DIRECTION INPUT ;
    USE SIGNAL ;
    PORT
      LAYER M4 ;
        RECT  0 30.048 0.192 30.072 ;
    END
  END b[456]
  PIN b[457]
    DIRECTION INPUT ;
    USE SIGNAL ;
    PORT
      LAYER M4 ;
        RECT  0 30.096 0.192 30.12 ;
    END
  END b[457]
  PIN b[458]
    DIRECTION INPUT ;
    USE SIGNAL ;
    PORT
      LAYER M4 ;
        RECT  0 30.144 0.192 30.168 ;
    END
  END b[458]
  PIN b[459]
    DIRECTION INPUT ;
    USE SIGNAL ;
    PORT
      LAYER M4 ;
        RECT  0 30.192 0.192 30.216 ;
    END
  END b[459]
  PIN b[45]
    DIRECTION OUTPUT ;
    USE SIGNAL ;
    PORT
      LAYER M4 ;
        RECT  0 10.32 0.192 10.344 ;
    END
  END b[45]
  PIN b[460]
    DIRECTION INPUT ;
    USE SIGNAL ;
    PORT
      LAYER M4 ;
        RECT  0 30.24 0.192 30.264 ;
    END
  END b[460]
  PIN b[461]
    DIRECTION INPUT ;
    USE SIGNAL ;
    PORT
      LAYER M4 ;
        RECT  0 30.288 0.192 30.312 ;
    END
  END b[461]
  PIN b[462]
    DIRECTION INPUT ;
    USE SIGNAL ;
    PORT
      LAYER M4 ;
        RECT  0 30.336 0.192 30.36 ;
    END
  END b[462]
  PIN b[463]
    DIRECTION INPUT ;
    USE SIGNAL ;
    PORT
      LAYER M4 ;
        RECT  0 30.384 0.192 30.408 ;
    END
  END b[463]
  PIN b[464]
    DIRECTION INPUT ;
    USE SIGNAL ;
    PORT
      LAYER M4 ;
        RECT  0 30.432 0.192 30.456 ;
    END
  END b[464]
  PIN b[465]
    DIRECTION INPUT ;
    USE SIGNAL ;
    PORT
      LAYER M4 ;
        RECT  0 30.48 0.192 30.504 ;
    END
  END b[465]
  PIN b[466]
    DIRECTION INPUT ;
    USE SIGNAL ;
    PORT
      LAYER M4 ;
        RECT  0 30.528 0.192 30.552 ;
    END
  END b[466]
  PIN b[467]
    DIRECTION INPUT ;
    USE SIGNAL ;
    PORT
      LAYER M4 ;
        RECT  0 30.576 0.192 30.6 ;
    END
  END b[467]
  PIN b[468]
    DIRECTION INPUT ;
    USE SIGNAL ;
    PORT
      LAYER M4 ;
        RECT  0 30.624 0.192 30.648 ;
    END
  END b[468]
  PIN b[469]
    DIRECTION INPUT ;
    USE SIGNAL ;
    PORT
      LAYER M4 ;
        RECT  0 30.672 0.192 30.696 ;
    END
  END b[469]
  PIN b[46]
    DIRECTION OUTPUT ;
    USE SIGNAL ;
    PORT
      LAYER M4 ;
        RECT  0 10.368 0.192 10.392 ;
    END
  END b[46]
  PIN b[470]
    DIRECTION INPUT ;
    USE SIGNAL ;
    PORT
      LAYER M4 ;
        RECT  0 30.72 0.192 30.744 ;
    END
  END b[470]
  PIN b[471]
    DIRECTION INPUT ;
    USE SIGNAL ;
    PORT
      LAYER M4 ;
        RECT  0 30.768 0.192 30.792 ;
    END
  END b[471]
  PIN b[472]
    DIRECTION INPUT ;
    USE SIGNAL ;
    PORT
      LAYER M4 ;
        RECT  0 30.816 0.192 30.84 ;
    END
  END b[472]
  PIN b[473]
    DIRECTION INPUT ;
    USE SIGNAL ;
    PORT
      LAYER M4 ;
        RECT  0 30.864 0.192 30.888 ;
    END
  END b[473]
  PIN b[474]
    DIRECTION INPUT ;
    USE SIGNAL ;
    PORT
      LAYER M4 ;
        RECT  0 30.912 0.192 30.936 ;
    END
  END b[474]
  PIN b[475]
    DIRECTION INPUT ;
    USE SIGNAL ;
    PORT
      LAYER M4 ;
        RECT  0 30.96 0.192 30.984 ;
    END
  END b[475]
  PIN b[476]
    DIRECTION INPUT ;
    USE SIGNAL ;
    PORT
      LAYER M4 ;
        RECT  0 31.008 0.192 31.032 ;
    END
  END b[476]
  PIN b[477]
    DIRECTION INPUT ;
    USE SIGNAL ;
    PORT
      LAYER M4 ;
        RECT  0 31.056 0.192 31.08 ;
    END
  END b[477]
  PIN b[478]
    DIRECTION INPUT ;
    USE SIGNAL ;
    PORT
      LAYER M4 ;
        RECT  0 31.104 0.192 31.128 ;
    END
  END b[478]
  PIN b[479]
    DIRECTION INPUT ;
    USE SIGNAL ;
    PORT
      LAYER M4 ;
        RECT  0 31.152 0.192 31.176 ;
    END
  END b[479]
  PIN b[47]
    DIRECTION OUTPUT ;
    USE SIGNAL ;
    PORT
      LAYER M4 ;
        RECT  0 10.416 0.192 10.44 ;
    END
  END b[47]
  PIN b[480]
    DIRECTION INPUT ;
    USE SIGNAL ;
    PORT
      LAYER M4 ;
        RECT  0 31.2 0.192 31.224 ;
    END
  END b[480]
  PIN b[481]
    DIRECTION INPUT ;
    USE SIGNAL ;
    PORT
      LAYER M4 ;
        RECT  0 31.248 0.192 31.272 ;
    END
  END b[481]
  PIN b[482]
    DIRECTION INPUT ;
    USE SIGNAL ;
    PORT
      LAYER M4 ;
        RECT  0 31.296 0.192 31.32 ;
    END
  END b[482]
  PIN b[483]
    DIRECTION INPUT ;
    USE SIGNAL ;
    PORT
      LAYER M4 ;
        RECT  0 31.344 0.192 31.368 ;
    END
  END b[483]
  PIN b[484]
    DIRECTION INPUT ;
    USE SIGNAL ;
    PORT
      LAYER M4 ;
        RECT  0 31.392 0.192 31.416 ;
    END
  END b[484]
  PIN b[485]
    DIRECTION INPUT ;
    USE SIGNAL ;
    PORT
      LAYER M4 ;
        RECT  0 31.44 0.192 31.464 ;
    END
  END b[485]
  PIN b[486]
    DIRECTION INPUT ;
    USE SIGNAL ;
    PORT
      LAYER M4 ;
        RECT  0 31.488 0.192 31.512 ;
    END
  END b[486]
  PIN b[487]
    DIRECTION INPUT ;
    USE SIGNAL ;
    PORT
      LAYER M4 ;
        RECT  0 31.536 0.192 31.56 ;
    END
  END b[487]
  PIN b[488]
    DIRECTION INPUT ;
    USE SIGNAL ;
    PORT
      LAYER M4 ;
        RECT  0 31.584 0.192 31.608 ;
    END
  END b[488]
  PIN b[489]
    DIRECTION INPUT ;
    USE SIGNAL ;
    PORT
      LAYER M4 ;
        RECT  0 31.632 0.192 31.656 ;
    END
  END b[489]
  PIN b[48]
    DIRECTION OUTPUT ;
    USE SIGNAL ;
    PORT
      LAYER M4 ;
        RECT  0 10.464 0.192 10.488 ;
    END
  END b[48]
  PIN b[490]
    DIRECTION INPUT ;
    USE SIGNAL ;
    PORT
      LAYER M4 ;
        RECT  0 31.68 0.192 31.704 ;
    END
  END b[490]
  PIN b[491]
    DIRECTION INPUT ;
    USE SIGNAL ;
    PORT
      LAYER M4 ;
        RECT  0 31.728 0.192 31.752 ;
    END
  END b[491]
  PIN b[492]
    DIRECTION INPUT ;
    USE SIGNAL ;
    PORT
      LAYER M4 ;
        RECT  0 31.776 0.192 31.8 ;
    END
  END b[492]
  PIN b[493]
    DIRECTION INPUT ;
    USE SIGNAL ;
    PORT
      LAYER M4 ;
        RECT  0 31.824 0.192 31.848 ;
    END
  END b[493]
  PIN b[494]
    DIRECTION INPUT ;
    USE SIGNAL ;
    PORT
      LAYER M4 ;
        RECT  0 31.872 0.192 31.896 ;
    END
  END b[494]
  PIN b[495]
    DIRECTION INPUT ;
    USE SIGNAL ;
    PORT
      LAYER M4 ;
        RECT  0 31.92 0.192 31.944 ;
    END
  END b[495]
  PIN b[496]
    DIRECTION INPUT ;
    USE SIGNAL ;
    PORT
      LAYER M4 ;
        RECT  0 31.968 0.192 31.992 ;
    END
  END b[496]
  PIN b[497]
    DIRECTION INPUT ;
    USE SIGNAL ;
    PORT
      LAYER M4 ;
        RECT  0 32.016 0.192 32.04 ;
    END
  END b[497]
  PIN b[498]
    DIRECTION INPUT ;
    USE SIGNAL ;
    PORT
      LAYER M4 ;
        RECT  0 32.064 0.192 32.088 ;
    END
  END b[498]
  PIN b[499]
    DIRECTION INPUT ;
    USE SIGNAL ;
    PORT
      LAYER M4 ;
        RECT  0 32.112 0.192 32.136 ;
    END
  END b[499]
  PIN b[49]
    DIRECTION OUTPUT ;
    USE SIGNAL ;
    PORT
      LAYER M4 ;
        RECT  0 10.512 0.192 10.536 ;
    END
  END b[49]
  PIN b[4]
    DIRECTION OUTPUT ;
    USE SIGNAL ;
    PORT
      LAYER M4 ;
        RECT  0 8.352 0.192 8.376 ;
    END
  END b[4]
  PIN b[500]
    DIRECTION INPUT ;
    USE SIGNAL ;
    PORT
      LAYER M4 ;
        RECT  0 32.16 0.192 32.184 ;
    END
  END b[500]
  PIN b[501]
    DIRECTION INPUT ;
    USE SIGNAL ;
    PORT
      LAYER M4 ;
        RECT  0 32.208 0.192 32.232 ;
    END
  END b[501]
  PIN b[502]
    DIRECTION INPUT ;
    USE SIGNAL ;
    PORT
      LAYER M4 ;
        RECT  0 32.256 0.192 32.28 ;
    END
  END b[502]
  PIN b[503]
    DIRECTION INPUT ;
    USE SIGNAL ;
    PORT
      LAYER M4 ;
        RECT  0 32.304 0.192 32.328 ;
    END
  END b[503]
  PIN b[504]
    DIRECTION INPUT ;
    USE SIGNAL ;
    PORT
      LAYER M4 ;
        RECT  0 32.352 0.192 32.376 ;
    END
  END b[504]
  PIN b[505]
    DIRECTION INPUT ;
    USE SIGNAL ;
    PORT
      LAYER M4 ;
        RECT  0 32.4 0.192 32.424 ;
    END
  END b[505]
  PIN b[506]
    DIRECTION INPUT ;
    USE SIGNAL ;
    PORT
      LAYER M4 ;
        RECT  0 32.448 0.192 32.472 ;
    END
  END b[506]
  PIN b[507]
    DIRECTION INPUT ;
    USE SIGNAL ;
    PORT
      LAYER M4 ;
        RECT  0 32.496 0.192 32.52 ;
    END
  END b[507]
  PIN b[508]
    DIRECTION INPUT ;
    USE SIGNAL ;
    PORT
      LAYER M4 ;
        RECT  0 32.544 0.192 32.568 ;
    END
  END b[508]
  PIN b[509]
    DIRECTION INPUT ;
    USE SIGNAL ;
    PORT
      LAYER M4 ;
        RECT  0 32.592 0.192 32.616 ;
    END
  END b[509]
  PIN b[50]
    DIRECTION OUTPUT ;
    USE SIGNAL ;
    PORT
      LAYER M4 ;
        RECT  0 10.56 0.192 10.584 ;
    END
  END b[50]
  PIN b[510]
    DIRECTION INPUT ;
    USE SIGNAL ;
    PORT
      LAYER M4 ;
        RECT  0 32.64 0.192 32.664 ;
    END
  END b[510]
  PIN b[511]
    DIRECTION INPUT ;
    USE SIGNAL ;
    PORT
      LAYER M4 ;
        RECT  0 32.688 0.192 32.712 ;
    END
  END b[511]
  PIN b[512]
    DIRECTION OUTPUT ;
    USE SIGNAL ;
    PORT
      LAYER M4 ;
        RECT  0 32.736 0.192 32.76 ;
    END
  END b[512]
  PIN b[513]
    DIRECTION INPUT ;
    USE SIGNAL ;
    PORT
      LAYER M4 ;
        RECT  0 32.784 0.192 32.808 ;
    END
  END b[513]
  PIN b[51]
    DIRECTION OUTPUT ;
    USE SIGNAL ;
    PORT
      LAYER M4 ;
        RECT  0 10.608 0.192 10.632 ;
    END
  END b[51]
  PIN b[52]
    DIRECTION OUTPUT ;
    USE SIGNAL ;
    PORT
      LAYER M4 ;
        RECT  0 10.656 0.192 10.68 ;
    END
  END b[52]
  PIN b[53]
    DIRECTION OUTPUT ;
    USE SIGNAL ;
    PORT
      LAYER M4 ;
        RECT  0 10.704 0.192 10.728 ;
    END
  END b[53]
  PIN b[54]
    DIRECTION OUTPUT ;
    USE SIGNAL ;
    PORT
      LAYER M4 ;
        RECT  0 10.752 0.192 10.776 ;
    END
  END b[54]
  PIN b[55]
    DIRECTION OUTPUT ;
    USE SIGNAL ;
    PORT
      LAYER M4 ;
        RECT  0 10.8 0.192 10.824 ;
    END
  END b[55]
  PIN b[56]
    DIRECTION OUTPUT ;
    USE SIGNAL ;
    PORT
      LAYER M4 ;
        RECT  0 10.848 0.192 10.872 ;
    END
  END b[56]
  PIN b[57]
    DIRECTION OUTPUT ;
    USE SIGNAL ;
    PORT
      LAYER M4 ;
        RECT  0 10.896 0.192 10.92 ;
    END
  END b[57]
  PIN b[58]
    DIRECTION OUTPUT ;
    USE SIGNAL ;
    PORT
      LAYER M4 ;
        RECT  0 10.944 0.192 10.968 ;
    END
  END b[58]
  PIN b[59]
    DIRECTION OUTPUT ;
    USE SIGNAL ;
    PORT
      LAYER M4 ;
        RECT  0 10.992 0.192 11.016 ;
    END
  END b[59]
  PIN b[5]
    DIRECTION OUTPUT ;
    USE SIGNAL ;
    PORT
      LAYER M4 ;
        RECT  0 8.4 0.192 8.424 ;
    END
  END b[5]
  PIN b[60]
    DIRECTION OUTPUT ;
    USE SIGNAL ;
    PORT
      LAYER M4 ;
        RECT  0 11.04 0.192 11.064 ;
    END
  END b[60]
  PIN b[61]
    DIRECTION OUTPUT ;
    USE SIGNAL ;
    PORT
      LAYER M4 ;
        RECT  0 11.088 0.192 11.112 ;
    END
  END b[61]
  PIN b[62]
    DIRECTION OUTPUT ;
    USE SIGNAL ;
    PORT
      LAYER M4 ;
        RECT  0 11.136 0.192 11.16 ;
    END
  END b[62]
  PIN b[63]
    DIRECTION OUTPUT ;
    USE SIGNAL ;
    PORT
      LAYER M4 ;
        RECT  0 11.184 0.192 11.208 ;
    END
  END b[63]
  PIN b[64]
    DIRECTION OUTPUT ;
    USE SIGNAL ;
    PORT
      LAYER M4 ;
        RECT  0 11.232 0.192 11.256 ;
    END
  END b[64]
  PIN b[65]
    DIRECTION OUTPUT ;
    USE SIGNAL ;
    PORT
      LAYER M4 ;
        RECT  0 11.28 0.192 11.304 ;
    END
  END b[65]
  PIN b[66]
    DIRECTION OUTPUT ;
    USE SIGNAL ;
    PORT
      LAYER M4 ;
        RECT  0 11.328 0.192 11.352 ;
    END
  END b[66]
  PIN b[67]
    DIRECTION OUTPUT ;
    USE SIGNAL ;
    PORT
      LAYER M4 ;
        RECT  0 11.376 0.192 11.4 ;
    END
  END b[67]
  PIN b[68]
    DIRECTION OUTPUT ;
    USE SIGNAL ;
    PORT
      LAYER M4 ;
        RECT  0 11.424 0.192 11.448 ;
    END
  END b[68]
  PIN b[69]
    DIRECTION OUTPUT ;
    USE SIGNAL ;
    PORT
      LAYER M4 ;
        RECT  0 11.472 0.192 11.496 ;
    END
  END b[69]
  PIN b[6]
    DIRECTION OUTPUT ;
    USE SIGNAL ;
    PORT
      LAYER M4 ;
        RECT  0 8.448 0.192 8.472 ;
    END
  END b[6]
  PIN b[70]
    DIRECTION OUTPUT ;
    USE SIGNAL ;
    PORT
      LAYER M4 ;
        RECT  0 11.52 0.192 11.544 ;
    END
  END b[70]
  PIN b[71]
    DIRECTION OUTPUT ;
    USE SIGNAL ;
    PORT
      LAYER M4 ;
        RECT  0 11.568 0.192 11.592 ;
    END
  END b[71]
  PIN b[72]
    DIRECTION OUTPUT ;
    USE SIGNAL ;
    PORT
      LAYER M4 ;
        RECT  0 11.616 0.192 11.64 ;
    END
  END b[72]
  PIN b[73]
    DIRECTION OUTPUT ;
    USE SIGNAL ;
    PORT
      LAYER M4 ;
        RECT  0 11.664 0.192 11.688 ;
    END
  END b[73]
  PIN b[74]
    DIRECTION OUTPUT ;
    USE SIGNAL ;
    PORT
      LAYER M4 ;
        RECT  0 11.712 0.192 11.736 ;
    END
  END b[74]
  PIN b[75]
    DIRECTION OUTPUT ;
    USE SIGNAL ;
    PORT
      LAYER M4 ;
        RECT  0 11.76 0.192 11.784 ;
    END
  END b[75]
  PIN b[76]
    DIRECTION OUTPUT ;
    USE SIGNAL ;
    PORT
      LAYER M4 ;
        RECT  0 11.808 0.192 11.832 ;
    END
  END b[76]
  PIN b[77]
    DIRECTION OUTPUT ;
    USE SIGNAL ;
    PORT
      LAYER M4 ;
        RECT  0 11.856 0.192 11.88 ;
    END
  END b[77]
  PIN b[78]
    DIRECTION OUTPUT ;
    USE SIGNAL ;
    PORT
      LAYER M4 ;
        RECT  0 11.904 0.192 11.928 ;
    END
  END b[78]
  PIN b[79]
    DIRECTION OUTPUT ;
    USE SIGNAL ;
    PORT
      LAYER M4 ;
        RECT  0 11.952 0.192 11.976 ;
    END
  END b[79]
  PIN b[7]
    DIRECTION OUTPUT ;
    USE SIGNAL ;
    PORT
      LAYER M4 ;
        RECT  0 8.496 0.192 8.52 ;
    END
  END b[7]
  PIN b[80]
    DIRECTION OUTPUT ;
    USE SIGNAL ;
    PORT
      LAYER M4 ;
        RECT  0 12 0.192 12.024 ;
    END
  END b[80]
  PIN b[81]
    DIRECTION OUTPUT ;
    USE SIGNAL ;
    PORT
      LAYER M4 ;
        RECT  0 12.048 0.192 12.072 ;
    END
  END b[81]
  PIN b[82]
    DIRECTION OUTPUT ;
    USE SIGNAL ;
    PORT
      LAYER M4 ;
        RECT  0 12.096 0.192 12.12 ;
    END
  END b[82]
  PIN b[83]
    DIRECTION OUTPUT ;
    USE SIGNAL ;
    PORT
      LAYER M4 ;
        RECT  0 12.144 0.192 12.168 ;
    END
  END b[83]
  PIN b[84]
    DIRECTION OUTPUT ;
    USE SIGNAL ;
    PORT
      LAYER M4 ;
        RECT  0 12.192 0.192 12.216 ;
    END
  END b[84]
  PIN b[85]
    DIRECTION OUTPUT ;
    USE SIGNAL ;
    PORT
      LAYER M4 ;
        RECT  0 12.24 0.192 12.264 ;
    END
  END b[85]
  PIN b[86]
    DIRECTION OUTPUT ;
    USE SIGNAL ;
    PORT
      LAYER M4 ;
        RECT  0 12.288 0.192 12.312 ;
    END
  END b[86]
  PIN b[87]
    DIRECTION OUTPUT ;
    USE SIGNAL ;
    PORT
      LAYER M4 ;
        RECT  0 12.336 0.192 12.36 ;
    END
  END b[87]
  PIN b[88]
    DIRECTION OUTPUT ;
    USE SIGNAL ;
    PORT
      LAYER M4 ;
        RECT  0 12.384 0.192 12.408 ;
    END
  END b[88]
  PIN b[89]
    DIRECTION OUTPUT ;
    USE SIGNAL ;
    PORT
      LAYER M4 ;
        RECT  0 12.432 0.192 12.456 ;
    END
  END b[89]
  PIN b[8]
    DIRECTION OUTPUT ;
    USE SIGNAL ;
    PORT
      LAYER M4 ;
        RECT  0 8.544 0.192 8.568 ;
    END
  END b[8]
  PIN b[90]
    DIRECTION OUTPUT ;
    USE SIGNAL ;
    PORT
      LAYER M4 ;
        RECT  0 12.48 0.192 12.504 ;
    END
  END b[90]
  PIN b[91]
    DIRECTION OUTPUT ;
    USE SIGNAL ;
    PORT
      LAYER M4 ;
        RECT  0 12.528 0.192 12.552 ;
    END
  END b[91]
  PIN b[92]
    DIRECTION OUTPUT ;
    USE SIGNAL ;
    PORT
      LAYER M4 ;
        RECT  0 12.576 0.192 12.6 ;
    END
  END b[92]
  PIN b[93]
    DIRECTION OUTPUT ;
    USE SIGNAL ;
    PORT
      LAYER M4 ;
        RECT  0 12.624 0.192 12.648 ;
    END
  END b[93]
  PIN b[94]
    DIRECTION OUTPUT ;
    USE SIGNAL ;
    PORT
      LAYER M4 ;
        RECT  0 12.672 0.192 12.696 ;
    END
  END b[94]
  PIN b[95]
    DIRECTION OUTPUT ;
    USE SIGNAL ;
    PORT
      LAYER M4 ;
        RECT  0 12.72 0.192 12.744 ;
    END
  END b[95]
  PIN b[96]
    DIRECTION OUTPUT ;
    USE SIGNAL ;
    PORT
      LAYER M4 ;
        RECT  0 12.768 0.192 12.792 ;
    END
  END b[96]
  PIN b[97]
    DIRECTION OUTPUT ;
    USE SIGNAL ;
    PORT
      LAYER M4 ;
        RECT  0 12.816 0.192 12.84 ;
    END
  END b[97]
  PIN b[98]
    DIRECTION OUTPUT ;
    USE SIGNAL ;
    PORT
      LAYER M4 ;
        RECT  0 12.864 0.192 12.888 ;
    END
  END b[98]
  PIN b[99]
    DIRECTION OUTPUT ;
    USE SIGNAL ;
    PORT
      LAYER M4 ;
        RECT  0 12.912 0.192 12.936 ;
    END
  END b[99]
  PIN b[9]
    DIRECTION OUTPUT ;
    USE SIGNAL ;
    PORT
      LAYER M4 ;
        RECT  0 8.592 0.192 8.616 ;
    END
  END b[9]
  PIN rst[0]
    DIRECTION INPUT ;
    USE SIGNAL ;
    PORT
      LAYER M5 ;
        RECT  72.288 40.824 72.312 41.016 ;
    END
  END rst[0]
  PIN VDD
    DIRECTION INOUT ;
    USE POWER ;
    PORT
      LAYER M7 ;
        RECT  71.056 0.531 71.344 40.239 ;
        RECT  60.256 0.531 60.544 40.239 ;
        RECT  49.456 0.531 49.744 40.239 ;
        RECT  38.656 0.531 38.944 40.239 ;
        RECT  27.856 0.531 28.144 40.239 ;
        RECT  17.056 0.531 17.344 40.239 ;
        RECT  6.256 0.531 6.544 40.239 ;
      LAYER M6 ;
        RECT  0 39.372 0.032 39.66 ;
        RECT  0 33.972 0.032 34.26 ;
        RECT  0 28.572 0.032 28.86 ;
        RECT  0 23.172 0.032 23.46 ;
        RECT  0 17.772 0.032 18.06 ;
        RECT  0 12.372 0.032 12.66 ;
        RECT  0 6.972 0.032 7.26 ;
        RECT  0 1.572 0.032 1.86 ;
      LAYER M2 ;
        RECT  0 40.221 0.018 40.239 ;
        RECT  0 39.681 0.018 39.699 ;
        RECT  0 39.141 0.018 39.159 ;
        RECT  0 38.601 0.018 38.619 ;
        RECT  0 38.061 0.018 38.079 ;
        RECT  0 37.521 0.018 37.539 ;
        RECT  0 36.981 0.018 36.999 ;
        RECT  0 36.441 0.018 36.459 ;
        RECT  0 35.901 0.018 35.919 ;
        RECT  0 35.361 0.018 35.379 ;
        RECT  0 34.821 0.018 34.839 ;
        RECT  0 34.281 0.018 34.299 ;
        RECT  0 33.741 0.018 33.759 ;
        RECT  0 33.201 0.018 33.219 ;
        RECT  0 32.661 0.018 32.679 ;
        RECT  0 32.121 0.018 32.139 ;
        RECT  0 31.581 0.018 31.599 ;
        RECT  0 31.041 0.018 31.059 ;
        RECT  0 30.501 0.018 30.519 ;
        RECT  0 29.961 0.018 29.979 ;
        RECT  0 29.421 0.018 29.439 ;
        RECT  0 28.881 0.018 28.899 ;
        RECT  0 28.341 0.018 28.359 ;
        RECT  0 27.801 0.018 27.819 ;
        RECT  0 27.261 0.018 27.279 ;
        RECT  0 26.721 0.018 26.739 ;
        RECT  0 26.181 0.018 26.199 ;
        RECT  0 25.641 0.018 25.659 ;
        RECT  0 25.101 0.018 25.119 ;
        RECT  0 24.561 0.018 24.579 ;
        RECT  0 24.021 0.018 24.039 ;
        RECT  0 23.481 0.018 23.499 ;
        RECT  0 22.941 0.018 22.959 ;
        RECT  0 22.401 0.018 22.419 ;
        RECT  0 21.861 0.018 21.879 ;
        RECT  0 21.321 0.018 21.339 ;
        RECT  0 20.781 0.018 20.799 ;
        RECT  0 20.241 0.018 20.259 ;
        RECT  0 19.701 0.018 19.719 ;
        RECT  0 19.161 0.018 19.179 ;
        RECT  0 18.621 0.018 18.639 ;
        RECT  0 18.081 0.018 18.099 ;
        RECT  0 17.541 0.018 17.559 ;
        RECT  0 17.001 0.018 17.019 ;
        RECT  0 16.461 0.018 16.479 ;
        RECT  0 15.921 0.018 15.939 ;
        RECT  0 15.381 0.018 15.399 ;
        RECT  0 14.841 0.018 14.859 ;
        RECT  0 14.301 0.018 14.319 ;
        RECT  0 13.761 0.018 13.779 ;
        RECT  0 13.221 0.018 13.239 ;
        RECT  0 12.681 0.018 12.699 ;
        RECT  0 12.141 0.018 12.159 ;
        RECT  0 11.601 0.018 11.619 ;
        RECT  0 11.061 0.018 11.079 ;
        RECT  0 10.521 0.018 10.539 ;
        RECT  0 9.981 0.018 9.999 ;
        RECT  0 9.441 0.018 9.459 ;
        RECT  0 8.901 0.018 8.919 ;
        RECT  0 8.361 0.018 8.379 ;
        RECT  0 7.821 0.018 7.839 ;
        RECT  0 7.281 0.018 7.299 ;
        RECT  0 6.741 0.018 6.759 ;
        RECT  0 6.201 0.018 6.219 ;
        RECT  0 5.661 0.018 5.679 ;
        RECT  0 5.121 0.018 5.139 ;
        RECT  0 4.581 0.018 4.599 ;
        RECT  0 4.041 0.018 4.059 ;
        RECT  0 3.501 0.018 3.519 ;
        RECT  0 2.961 0.018 2.979 ;
        RECT  0 2.421 0.018 2.439 ;
        RECT  0 1.881 0.018 1.899 ;
        RECT  0 1.341 0.018 1.359 ;
        RECT  0 0.801 0.018 0.819 ;
      LAYER M1 ;
        RECT  0 40.221 0.018 40.239 ;
        RECT  0 39.681 0.018 39.699 ;
        RECT  0 39.141 0.018 39.159 ;
        RECT  0 38.601 0.018 38.619 ;
        RECT  0 38.061 0.018 38.079 ;
        RECT  0 37.521 0.018 37.539 ;
        RECT  0 36.981 0.018 36.999 ;
        RECT  0 36.441 0.018 36.459 ;
        RECT  0 35.901 0.018 35.919 ;
        RECT  0 35.361 0.018 35.379 ;
        RECT  0 34.821 0.018 34.839 ;
        RECT  0 34.281 0.018 34.299 ;
        RECT  0 33.741 0.018 33.759 ;
        RECT  0 33.201 0.018 33.219 ;
        RECT  0 32.661 0.018 32.679 ;
        RECT  0 32.121 0.018 32.139 ;
        RECT  0 31.581 0.018 31.599 ;
        RECT  0 31.041 0.018 31.059 ;
        RECT  0 30.501 0.018 30.519 ;
        RECT  0 29.961 0.018 29.979 ;
        RECT  0 29.421 0.018 29.439 ;
        RECT  0 28.881 0.018 28.899 ;
        RECT  0 28.341 0.018 28.359 ;
        RECT  0 27.801 0.018 27.819 ;
        RECT  0 27.261 0.018 27.279 ;
        RECT  0 26.721 0.018 26.739 ;
        RECT  0 26.181 0.018 26.199 ;
        RECT  0 25.641 0.018 25.659 ;
        RECT  0 25.101 0.018 25.119 ;
        RECT  0 24.561 0.018 24.579 ;
        RECT  0 24.021 0.018 24.039 ;
        RECT  0 23.481 0.018 23.499 ;
        RECT  0 22.941 0.018 22.959 ;
        RECT  0 22.401 0.018 22.419 ;
        RECT  0 21.861 0.018 21.879 ;
        RECT  0 21.321 0.018 21.339 ;
        RECT  0 20.781 0.018 20.799 ;
        RECT  0 20.241 0.018 20.259 ;
        RECT  0 19.701 0.018 19.719 ;
        RECT  0 19.161 0.018 19.179 ;
        RECT  0 18.621 0.018 18.639 ;
        RECT  0 18.081 0.018 18.099 ;
        RECT  0 17.541 0.018 17.559 ;
        RECT  0 17.001 0.018 17.019 ;
        RECT  0 16.461 0.018 16.479 ;
        RECT  0 15.921 0.018 15.939 ;
        RECT  0 15.381 0.018 15.399 ;
        RECT  0 14.841 0.018 14.859 ;
        RECT  0 14.301 0.018 14.319 ;
        RECT  0 13.761 0.018 13.779 ;
        RECT  0 13.221 0.018 13.239 ;
        RECT  0 12.681 0.018 12.699 ;
        RECT  0 12.141 0.018 12.159 ;
        RECT  0 11.601 0.018 11.619 ;
        RECT  0 11.061 0.018 11.079 ;
        RECT  0 10.521 0.018 10.539 ;
        RECT  0 9.981 0.018 9.999 ;
        RECT  0 9.441 0.018 9.459 ;
        RECT  0 8.901 0.018 8.919 ;
        RECT  0 8.361 0.018 8.379 ;
        RECT  0 7.821 0.018 7.839 ;
        RECT  0 7.281 0.018 7.299 ;
        RECT  0 6.741 0.018 6.759 ;
        RECT  0 6.201 0.018 6.219 ;
        RECT  0 5.661 0.018 5.679 ;
        RECT  0 5.121 0.018 5.139 ;
        RECT  0 4.581 0.018 4.599 ;
        RECT  0 4.041 0.018 4.059 ;
        RECT  0 3.501 0.018 3.519 ;
        RECT  0 2.961 0.018 2.979 ;
        RECT  0 2.421 0.018 2.439 ;
        RECT  0 1.881 0.018 1.899 ;
        RECT  0 1.341 0.018 1.359 ;
        RECT  0 0.801 0.018 0.819 ;
    END
  END VDD
  PIN VSS
    DIRECTION INOUT ;
    USE GROUND ;
    PORT
      LAYER M7 ;
        RECT  65.656 0.531 65.944 40.239 ;
        RECT  54.856 0.531 55.144 40.239 ;
        RECT  44.056 0.531 44.344 40.239 ;
        RECT  33.256 0.531 33.544 40.239 ;
        RECT  22.456 0.531 22.744 40.239 ;
        RECT  11.656 0.531 11.944 40.239 ;
        RECT  0.856 0.531 1.144 40.239 ;
      LAYER M6 ;
        RECT  0 38.796 0.032 39.084 ;
        RECT  0 33.396 0.032 33.684 ;
        RECT  0 27.996 0.032 28.284 ;
        RECT  0 22.596 0.032 22.884 ;
        RECT  0 17.196 0.032 17.484 ;
        RECT  0 11.796 0.032 12.084 ;
        RECT  0 6.396 0.032 6.684 ;
        RECT  0 0.996 0.032 1.284 ;
      LAYER M2 ;
        RECT  0 39.951 0.018 39.969 ;
        RECT  0 39.411 0.018 39.429 ;
        RECT  0 38.871 0.018 38.889 ;
        RECT  0 38.331 0.018 38.349 ;
        RECT  0 37.791 0.018 37.809 ;
        RECT  0 37.251 0.018 37.269 ;
        RECT  0 36.711 0.018 36.729 ;
        RECT  0 36.171 0.018 36.189 ;
        RECT  0 35.631 0.018 35.649 ;
        RECT  0 35.091 0.018 35.109 ;
        RECT  0 34.551 0.018 34.569 ;
        RECT  0 34.011 0.018 34.029 ;
        RECT  0 33.471 0.018 33.489 ;
        RECT  0 32.931 0.018 32.949 ;
        RECT  0 32.391 0.018 32.409 ;
        RECT  0 31.851 0.018 31.869 ;
        RECT  0 31.311 0.018 31.329 ;
        RECT  0 30.771 0.018 30.789 ;
        RECT  0 30.231 0.018 30.249 ;
        RECT  0 29.691 0.018 29.709 ;
        RECT  0 29.151 0.018 29.169 ;
        RECT  0 28.611 0.018 28.629 ;
        RECT  0 28.071 0.018 28.089 ;
        RECT  0 27.531 0.018 27.549 ;
        RECT  0 26.991 0.018 27.009 ;
        RECT  0 26.451 0.018 26.469 ;
        RECT  0 25.911 0.018 25.929 ;
        RECT  0 25.371 0.018 25.389 ;
        RECT  0 24.831 0.018 24.849 ;
        RECT  0 24.291 0.018 24.309 ;
        RECT  0 23.751 0.018 23.769 ;
        RECT  0 23.211 0.018 23.229 ;
        RECT  0 22.671 0.018 22.689 ;
        RECT  0 22.131 0.018 22.149 ;
        RECT  0 21.591 0.018 21.609 ;
        RECT  0 21.051 0.018 21.069 ;
        RECT  0 20.511 0.018 20.529 ;
        RECT  0 19.971 0.018 19.989 ;
        RECT  0 19.431 0.018 19.449 ;
        RECT  0 18.891 0.018 18.909 ;
        RECT  0 18.351 0.018 18.369 ;
        RECT  0 17.811 0.018 17.829 ;
        RECT  0 17.271 0.018 17.289 ;
        RECT  0 16.731 0.018 16.749 ;
        RECT  0 16.191 0.018 16.209 ;
        RECT  0 15.651 0.018 15.669 ;
        RECT  0 15.111 0.018 15.129 ;
        RECT  0 14.571 0.018 14.589 ;
        RECT  0 14.031 0.018 14.049 ;
        RECT  0 13.491 0.018 13.509 ;
        RECT  0 12.951 0.018 12.969 ;
        RECT  0 12.411 0.018 12.429 ;
        RECT  0 11.871 0.018 11.889 ;
        RECT  0 11.331 0.018 11.349 ;
        RECT  0 10.791 0.018 10.809 ;
        RECT  0 10.251 0.018 10.269 ;
        RECT  0 9.711 0.018 9.729 ;
        RECT  0 9.171 0.018 9.189 ;
        RECT  0 8.631 0.018 8.649 ;
        RECT  0 8.091 0.018 8.109 ;
        RECT  0 7.551 0.018 7.569 ;
        RECT  0 7.011 0.018 7.029 ;
        RECT  0 6.471 0.018 6.489 ;
        RECT  0 5.931 0.018 5.949 ;
        RECT  0 5.391 0.018 5.409 ;
        RECT  0 4.851 0.018 4.869 ;
        RECT  0 4.311 0.018 4.329 ;
        RECT  0 3.771 0.018 3.789 ;
        RECT  0 3.231 0.018 3.249 ;
        RECT  0 2.691 0.018 2.709 ;
        RECT  0 2.151 0.018 2.169 ;
        RECT  0 1.611 0.018 1.629 ;
        RECT  0 1.071 0.018 1.089 ;
        RECT  0 0.531 0.018 0.549 ;
      LAYER M1 ;
        RECT  0 39.951 0.018 39.969 ;
        RECT  0 39.411 0.018 39.429 ;
        RECT  0 38.871 0.018 38.889 ;
        RECT  0 38.331 0.018 38.349 ;
        RECT  0 37.791 0.018 37.809 ;
        RECT  0 37.251 0.018 37.269 ;
        RECT  0 36.711 0.018 36.729 ;
        RECT  0 36.171 0.018 36.189 ;
        RECT  0 35.631 0.018 35.649 ;
        RECT  0 35.091 0.018 35.109 ;
        RECT  0 34.551 0.018 34.569 ;
        RECT  0 34.011 0.018 34.029 ;
        RECT  0 33.471 0.018 33.489 ;
        RECT  0 32.931 0.018 32.949 ;
        RECT  0 32.391 0.018 32.409 ;
        RECT  0 31.851 0.018 31.869 ;
        RECT  0 31.311 0.018 31.329 ;
        RECT  0 30.771 0.018 30.789 ;
        RECT  0 30.231 0.018 30.249 ;
        RECT  0 29.691 0.018 29.709 ;
        RECT  0 29.151 0.018 29.169 ;
        RECT  0 28.611 0.018 28.629 ;
        RECT  0 28.071 0.018 28.089 ;
        RECT  0 27.531 0.018 27.549 ;
        RECT  0 26.991 0.018 27.009 ;
        RECT  0 26.451 0.018 26.469 ;
        RECT  0 25.911 0.018 25.929 ;
        RECT  0 25.371 0.018 25.389 ;
        RECT  0 24.831 0.018 24.849 ;
        RECT  0 24.291 0.018 24.309 ;
        RECT  0 23.751 0.018 23.769 ;
        RECT  0 23.211 0.018 23.229 ;
        RECT  0 22.671 0.018 22.689 ;
        RECT  0 22.131 0.018 22.149 ;
        RECT  0 21.591 0.018 21.609 ;
        RECT  0 21.051 0.018 21.069 ;
        RECT  0 20.511 0.018 20.529 ;
        RECT  0 19.971 0.018 19.989 ;
        RECT  0 19.431 0.018 19.449 ;
        RECT  0 18.891 0.018 18.909 ;
        RECT  0 18.351 0.018 18.369 ;
        RECT  0 17.811 0.018 17.829 ;
        RECT  0 17.271 0.018 17.289 ;
        RECT  0 16.731 0.018 16.749 ;
        RECT  0 16.191 0.018 16.209 ;
        RECT  0 15.651 0.018 15.669 ;
        RECT  0 15.111 0.018 15.129 ;
        RECT  0 14.571 0.018 14.589 ;
        RECT  0 14.031 0.018 14.049 ;
        RECT  0 13.491 0.018 13.509 ;
        RECT  0 12.951 0.018 12.969 ;
        RECT  0 12.411 0.018 12.429 ;
        RECT  0 11.871 0.018 11.889 ;
        RECT  0 11.331 0.018 11.349 ;
        RECT  0 10.791 0.018 10.809 ;
        RECT  0 10.251 0.018 10.269 ;
        RECT  0 9.711 0.018 9.729 ;
        RECT  0 9.171 0.018 9.189 ;
        RECT  0 8.631 0.018 8.649 ;
        RECT  0 8.091 0.018 8.109 ;
        RECT  0 7.551 0.018 7.569 ;
        RECT  0 7.011 0.018 7.029 ;
        RECT  0 6.471 0.018 6.489 ;
        RECT  0 5.931 0.018 5.949 ;
        RECT  0 5.391 0.018 5.409 ;
        RECT  0 4.851 0.018 4.869 ;
        RECT  0 4.311 0.018 4.329 ;
        RECT  0 3.771 0.018 3.789 ;
        RECT  0 3.231 0.018 3.249 ;
        RECT  0 2.691 0.018 2.709 ;
        RECT  0 2.151 0.018 2.169 ;
        RECT  0 1.611 0.018 1.629 ;
        RECT  0 1.071 0.018 1.089 ;
        RECT  0 0.531 0.018 0.549 ;
    END
  END VSS
  OBS
    LAYER RVTN ;
     RECT  0 0.54 72.954 0.675 ;
     RECT  0 0.945 72.954 1.215 ;
     RECT  0 1.485 72.954 1.755 ;
     RECT  0 2.025 72.954 2.295 ;
     RECT  0 2.565 72.954 2.835 ;
     RECT  0 3.105 72.954 3.375 ;
     RECT  0 3.645 72.954 3.915 ;
     RECT  0 4.185 72.954 4.455 ;
     RECT  0 4.725 72.954 4.995 ;
     RECT  0 5.265 72.954 5.535 ;
     RECT  0 5.805 72.954 6.075 ;
     RECT  0 6.345 72.954 6.615 ;
     RECT  0 6.885 72.954 7.155 ;
     RECT  0 7.425 72.954 7.695 ;
     RECT  0 7.965 72.954 8.235 ;
     RECT  0 8.505 72.954 8.775 ;
     RECT  0 9.045 72.954 9.315 ;
     RECT  0 9.585 72.954 9.855 ;
     RECT  0 10.125 72.954 10.395 ;
     RECT  0 10.665 72.954 10.935 ;
     RECT  0 11.205 72.954 11.475 ;
     RECT  0 11.745 72.954 12.015 ;
     RECT  0 12.285 72.954 12.555 ;
     RECT  0 12.825 72.954 13.095 ;
     RECT  0 13.365 72.954 13.635 ;
     RECT  0 13.905 72.954 14.175 ;
     RECT  0 14.445 72.954 14.715 ;
     RECT  0 14.985 72.954 15.255 ;
     RECT  0 15.525 72.954 15.795 ;
     RECT  0 16.065 72.954 16.335 ;
     RECT  0 16.605 72.954 16.875 ;
     RECT  0 17.145 72.954 17.415 ;
     RECT  0 17.685 72.954 17.955 ;
     RECT  0 18.225 72.954 18.495 ;
     RECT  0 18.765 72.954 19.035 ;
     RECT  0 19.305 72.954 19.575 ;
     RECT  0 19.845 72.954 20.115 ;
     RECT  0 20.385 72.954 20.655 ;
     RECT  0 20.925 72.954 21.195 ;
     RECT  0 21.465 72.954 21.735 ;
     RECT  0 22.005 72.954 22.275 ;
     RECT  0 22.545 72.954 22.815 ;
     RECT  0 23.085 72.954 23.355 ;
     RECT  0 23.625 72.954 23.895 ;
     RECT  0 24.165 72.954 24.435 ;
     RECT  0 24.705 72.954 24.975 ;
     RECT  0 25.245 72.954 25.515 ;
     RECT  0 25.785 72.954 26.055 ;
     RECT  0 26.325 72.954 26.595 ;
     RECT  0 26.865 72.954 27.135 ;
     RECT  0 27.405 72.954 27.675 ;
     RECT  0 27.945 72.954 28.215 ;
     RECT  0 28.485 72.954 28.755 ;
     RECT  0 29.025 72.954 29.295 ;
     RECT  0 29.565 72.954 29.835 ;
     RECT  0 30.105 72.954 30.375 ;
     RECT  0 30.645 72.954 30.915 ;
     RECT  0 31.185 72.954 31.455 ;
     RECT  0 31.725 72.954 31.995 ;
     RECT  0 32.265 72.954 32.535 ;
     RECT  0 32.805 72.954 33.075 ;
     RECT  0 33.345 72.954 33.615 ;
     RECT  0 33.885 72.954 34.155 ;
     RECT  0 34.425 72.954 34.695 ;
     RECT  0 34.965 72.954 35.235 ;
     RECT  0 35.505 72.954 35.775 ;
     RECT  0 36.045 72.954 36.315 ;
     RECT  0 36.585 72.954 36.855 ;
     RECT  0 37.125 72.954 37.395 ;
     RECT  0 37.665 72.954 37.935 ;
     RECT  0 38.205 72.954 38.475 ;
     RECT  0 38.745 72.954 39.015 ;
     RECT  0 39.285 72.954 39.555 ;
     RECT  0 39.825 72.954 40.095 ;
    LAYER RVTP ;
     RECT  0 0.675 72.954 0.945 ;
     RECT  0 1.215 72.954 1.485 ;
     RECT  0 1.755 72.954 2.025 ;
     RECT  0 2.295 72.954 2.565 ;
     RECT  0 2.835 72.954 3.105 ;
     RECT  0 3.375 72.954 3.645 ;
     RECT  0 3.915 72.954 4.185 ;
     RECT  0 4.455 72.954 4.725 ;
     RECT  0 4.995 72.954 5.265 ;
     RECT  0 5.535 72.954 5.805 ;
     RECT  0 6.075 72.954 6.345 ;
     RECT  0 6.615 72.954 6.885 ;
     RECT  0 7.155 72.954 7.425 ;
     RECT  0 7.695 72.954 7.965 ;
     RECT  0 8.235 72.954 8.505 ;
     RECT  0 8.775 72.954 9.045 ;
     RECT  0 9.315 72.954 9.585 ;
     RECT  0 9.855 72.954 10.125 ;
     RECT  0 10.395 72.954 10.665 ;
     RECT  0 10.935 72.954 11.205 ;
     RECT  0 11.475 72.954 11.745 ;
     RECT  0 12.015 72.954 12.285 ;
     RECT  0 12.555 72.954 12.825 ;
     RECT  0 13.095 72.954 13.365 ;
     RECT  0 13.635 72.954 13.905 ;
     RECT  0 14.175 72.954 14.445 ;
     RECT  0 14.715 72.954 14.985 ;
     RECT  0 15.255 72.954 15.525 ;
     RECT  0 15.795 72.954 16.065 ;
     RECT  0 16.335 72.954 16.605 ;
     RECT  0 16.875 72.954 17.145 ;
     RECT  0 17.415 72.954 17.685 ;
     RECT  0 17.955 72.954 18.225 ;
     RECT  0 18.495 72.954 18.765 ;
     RECT  0 19.035 72.954 19.305 ;
     RECT  0 19.575 72.954 19.845 ;
     RECT  0 20.115 72.954 20.385 ;
     RECT  0 20.655 72.954 20.925 ;
     RECT  0 21.195 72.954 21.465 ;
     RECT  0 21.735 72.954 22.005 ;
     RECT  0 22.275 72.954 22.545 ;
     RECT  0 22.815 72.954 23.085 ;
     RECT  0 23.355 72.954 23.625 ;
     RECT  0 23.895 72.954 24.165 ;
     RECT  0 24.435 72.954 24.705 ;
     RECT  0 24.975 72.954 25.245 ;
     RECT  0 25.515 72.954 25.785 ;
     RECT  0 26.055 72.954 26.325 ;
     RECT  0 26.595 72.954 26.865 ;
     RECT  0 27.135 72.954 27.405 ;
     RECT  0 27.675 72.954 27.945 ;
     RECT  0 28.215 72.954 28.485 ;
     RECT  0 28.755 72.954 29.025 ;
     RECT  0 29.295 72.954 29.565 ;
     RECT  0 29.835 72.954 30.105 ;
     RECT  0 30.375 72.954 30.645 ;
     RECT  0 30.915 72.954 31.185 ;
     RECT  0 31.455 72.954 31.725 ;
     RECT  0 31.995 72.954 32.265 ;
     RECT  0 32.535 72.954 32.805 ;
     RECT  0 33.075 72.954 33.345 ;
     RECT  0 33.615 72.954 33.885 ;
     RECT  0 34.155 72.954 34.425 ;
     RECT  0 34.695 72.954 34.965 ;
     RECT  0 35.235 72.954 35.505 ;
     RECT  0 35.775 72.954 36.045 ;
     RECT  0 36.315 72.954 36.585 ;
     RECT  0 36.855 72.954 37.125 ;
     RECT  0 37.395 72.954 37.665 ;
     RECT  0 37.935 72.954 38.205 ;
     RECT  0 38.475 72.954 38.745 ;
     RECT  0 39.015 72.954 39.285 ;
     RECT  0 39.555 72.954 39.825 ;
     RECT  0 40.095 72.954 40.23 ;
    LAYER M1 ;
     RECT  0 0.531 72.954 40.239 ;
    LAYER M2 ;
     RECT  0 0.531 72.954 40.239 ;
     RECT  72.954 13.41 72.959 13.428 ;
     RECT  72.954 15.84 72.959 16.128 ;
     RECT  72.954 18.738 72.959 18.756 ;
     RECT  72.954 22.518 72.959 22.536 ;
     RECT  72.954 26.226 72.959 26.244 ;
    LAYER M3 ;
     RECT  0.255 0.523 0.345 0.793 ;
     RECT  5.655 0.523 5.745 0.793 ;
     RECT  11.055 0.523 11.145 0.793 ;
     RECT  16.455 0.523 16.545 0.793 ;
     RECT  21.855 0.523 21.945 0.793 ;
     RECT  27.255 0.523 27.345 0.793 ;
     RECT  32.655 0.523 32.745 0.793 ;
     RECT  38.055 0.523 38.145 0.793 ;
     RECT  43.455 0.523 43.545 0.793 ;
     RECT  48.855 0.523 48.945 0.793 ;
     RECT  54.255 0.523 54.345 0.793 ;
     RECT  59.655 0.523 59.745 0.793 ;
     RECT  65.055 0.523 65.145 0.793 ;
     RECT  70.455 0.523 70.545 0.793 ;
     RECT  0.255 0.793 0.537 5.881 ;
     RECT  0.216 5.881 0.537 7.159 ;
     RECT  0.216 7.159 1.17 8.311 ;
     RECT  0.216 8.311 1.422 8.443 ;
     RECT  2.16 5.809 2.178 8.443 ;
     RECT  0.216 8.443 2.178 8.473 ;
     RECT  0.036 8.473 2.178 8.491 ;
     RECT  21.855 0.793 22.137 8.977 ;
     RECT  32.655 0.793 32.937 8.977 ;
     RECT  21.855 8.977 22.842 9.077 ;
     RECT  16.455 0.793 16.737 9.115 ;
     RECT  21.855 9.077 22.137 9.115 ;
     RECT  13.824 8.971 13.842 9.211 ;
     RECT  18.108 9.115 18.126 9.211 ;
     RECT  18.972 9.115 18.99 9.211 ;
     RECT  16.455 9.115 17.118 9.239 ;
     RECT  18.108 9.211 18.99 9.239 ;
     RECT  20.7 9.115 22.137 9.239 ;
     RECT  5.655 0.793 5.937 9.247 ;
     RECT  22.86 9.163 22.878 9.247 ;
     RECT  32.655 8.977 33.03 9.247 ;
     RECT  13.824 9.211 14.418 9.248 ;
     RECT  18.756 9.239 18.99 9.248 ;
     RECT  0.036 8.491 2.394 9.319 ;
     RECT  22.86 9.247 22.95 9.347 ;
     RECT  32.508 9.247 33.03 9.355 ;
     RECT  26.244 9.283 26.262 9.391 ;
     RECT  27.255 0.793 27.537 9.391 ;
     RECT  16.455 9.239 16.866 9.451 ;
     RECT  0.036 9.319 2.718 9.481 ;
     RECT  13.824 9.248 13.842 9.509 ;
     RECT  15.984 9.451 16.866 9.509 ;
     RECT  20.772 9.239 22.137 9.509 ;
     RECT  5.04 9.247 5.937 9.517 ;
     RECT  18.792 9.248 18.99 9.517 ;
     RECT  31.932 9.355 33.03 9.589 ;
     RECT  16.056 9.509 16.866 9.617 ;
     RECT  20.772 9.509 20.79 9.689 ;
     RECT  14.616 9.355 15.102 9.869 ;
     RECT  25.668 9.391 26.262 9.959 ;
     RECT  11.055 0.793 11.337 10.021 ;
     RECT  22.86 9.347 22.878 10.049 ;
     RECT  31.932 9.589 33.498 10.049 ;
     RECT  47.484 9.691 47.502 10.049 ;
     RECT  4.572 9.517 5.937 10.057 ;
     RECT  21.855 9.509 22.137 10.057 ;
     RECT  27.216 9.391 27.537 10.057 ;
     RECT  6.912 10.021 6.93 10.061 ;
     RECT  10.8 10.021 11.337 10.123 ;
     RECT  10.8 10.123 11.79 10.157 ;
     RECT  0.036 9.481 2.934 10.165 ;
     RECT  34.776 10.165 34.794 10.201 ;
     RECT  4.572 10.057 6.174 10.291 ;
     RECT  14.328 10.267 14.346 10.291 ;
     RECT  18.792 9.517 19.206 10.291 ;
     RECT  4.572 10.291 6.858 10.319 ;
     RECT  32.004 10.049 33.498 10.319 ;
     RECT  18.504 10.291 19.206 10.349 ;
     RECT  16.416 9.617 16.866 10.399 ;
     RECT  30.636 9.931 30.654 10.399 ;
     RECT  34.776 10.201 35.118 10.399 ;
     RECT  13.932 10.291 14.346 10.411 ;
     RECT  6.804 10.319 6.858 10.427 ;
     RECT  25.668 9.959 25.686 10.427 ;
     RECT  53.1 10.399 53.118 10.445 ;
     RECT  8.604 10.075 8.622 10.471 ;
     RECT  9.36 10.399 9.378 10.471 ;
     RECT  11.055 10.157 11.79 10.471 ;
     RECT  26.784 10.057 27.537 10.471 ;
     RECT  34.776 10.399 35.406 10.471 ;
     RECT  54.255 0.793 54.537 10.471 ;
     RECT  8.604 10.471 9.378 10.499 ;
     RECT  11.055 10.471 12.186 10.589 ;
     RECT  13.68 10.411 14.346 10.589 ;
     RECT  26.784 10.471 27.666 10.589 ;
     RECT  15.084 9.869 15.102 10.597 ;
     RECT  27.144 10.589 27.666 10.597 ;
     RECT  20.232 10.363 20.25 10.633 ;
     RECT  14.868 10.597 15.102 10.733 ;
     RECT  29.232 10.705 29.25 10.741 ;
     RECT  34.632 10.471 35.406 10.741 ;
     RECT  7.848 10.201 7.866 10.769 ;
     RECT  29.232 10.741 29.466 10.781 ;
     RECT  32.004 10.319 32.937 10.781 ;
     RECT  48.855 0.793 49.137 10.831 ;
     RECT  70.455 0.793 70.737 10.831 ;
     RECT  71.46 9.553 71.478 10.831 ;
     RECT  8.604 10.499 9.306 10.843 ;
     RECT  11.055 10.589 11.79 10.859 ;
     RECT  15.084 10.733 15.102 10.859 ;
     RECT  21.855 10.057 22.77 10.867 ;
     RECT  20.232 10.633 20.538 10.903 ;
     RECT  21.855 10.867 22.842 10.903 ;
     RECT  27.144 10.597 28.062 10.903 ;
     RECT  23.94 10.507 23.958 10.939 ;
     RECT  46.764 10.831 46.782 10.939 ;
     RECT  47.736 10.201 47.754 10.939 ;
     RECT  48.528 10.831 49.137 10.939 ;
     RECT  70.455 10.831 71.478 10.939 ;
     RECT  29.448 10.781 29.466 10.967 ;
     RECT  46.764 10.939 46.854 10.967 ;
     RECT  70.236 10.939 71.478 10.975 ;
     RECT  72.216 10.129 72.234 10.975 ;
     RECT  13.68 10.589 13.698 10.987 ;
     RECT  20.16 10.903 22.878 11.011 ;
     RECT  39.888 10.741 39.906 11.011 ;
     RECT  70.236 10.975 72.234 11.101 ;
     RECT  13.104 10.987 13.698 11.129 ;
     RECT  39.384 11.011 39.906 11.129 ;
     RECT  36.18 10.363 36.198 11.137 ;
     RECT  38.055 0.793 38.337 11.137 ;
     RECT  39.384 11.129 39.474 11.137 ;
     RECT  30.204 10.399 30.798 11.173 ;
     RECT  20.088 11.011 22.914 11.201 ;
     RECT  0.036 10.165 3.114 11.245 ;
     RECT  4.572 10.319 5.937 11.245 ;
     RECT  6.804 10.427 6.822 11.245 ;
     RECT  16.416 10.399 17.118 11.245 ;
     RECT  46.8 10.967 46.854 11.245 ;
     RECT  47.736 10.939 49.137 11.245 ;
     RECT  33.696 10.741 35.406 11.273 ;
     RECT  13.104 11.129 13.59 11.281 ;
     RECT  16.416 11.245 17.586 11.281 ;
     RECT  18.828 10.349 19.206 11.281 ;
     RECT  30.096 11.173 30.798 11.281 ;
     RECT  34.164 11.273 35.406 11.309 ;
     RECT  46.8 11.245 49.137 11.309 ;
     RECT  12.888 11.281 13.59 11.357 ;
     RECT  30.096 11.281 31.23 11.357 ;
     RECT  46.8 11.309 47.466 11.357 ;
     RECT  6.804 11.245 7.434 11.399 ;
     RECT  8.352 10.843 9.306 11.399 ;
     RECT  16.344 11.281 19.206 11.399 ;
     RECT  38.055 11.137 39.474 11.399 ;
     RECT  46.8 11.357 46.818 11.399 ;
     RECT  48.42 11.309 49.137 11.399 ;
     RECT  50.652 11.101 50.67 11.399 ;
     RECT  38.055 11.399 39.402 11.407 ;
     RECT  18.72 11.399 19.206 11.419 ;
     RECT  20.088 11.201 22.842 11.419 ;
     RECT  31.212 11.357 31.23 11.419 ;
     RECT  18.72 11.419 22.842 11.453 ;
     RECT  11.055 10.859 11.61 11.467 ;
     RECT  25.92 10.831 26.37 11.479 ;
     RECT  27.144 10.903 28.314 11.479 ;
     RECT  37.692 11.407 39.402 11.479 ;
     RECT  30.096 11.357 30.474 11.507 ;
     RECT  34.2 11.309 35.406 11.515 ;
     RECT  36.18 11.137 36.27 11.515 ;
     RECT  70.236 11.101 72.45 11.515 ;
     RECT  34.2 11.515 36.27 11.543 ;
     RECT  10.872 11.467 11.61 11.551 ;
     RECT  37.656 11.479 39.402 11.551 ;
     RECT  67.824 11.011 67.842 11.551 ;
     RECT  8.352 11.399 9.162 11.579 ;
     RECT  25.92 11.479 28.602 11.579 ;
     RECT  23.94 10.939 24.03 11.611 ;
     RECT  25.092 10.741 25.11 11.611 ;
     RECT  6.804 11.399 7.362 11.669 ;
     RECT  21.492 11.453 22.842 11.669 ;
     RECT  23.94 11.611 25.11 11.669 ;
     RECT  35.676 11.543 36.27 11.669 ;
     RECT  37.584 11.551 39.402 11.669 ;
     RECT  67.824 11.551 67.878 11.669 ;
     RECT  54.255 10.471 54.594 11.677 ;
     RECT  4.464 11.245 5.937 11.693 ;
     RECT  67.86 11.669 67.878 11.705 ;
     RECT  27.255 11.579 28.602 11.713 ;
     RECT  31.212 11.419 31.374 11.713 ;
     RECT  32.22 10.781 32.937 11.713 ;
     RECT  24.768 11.669 25.11 11.749 ;
     RECT  25.92 11.579 26.262 11.749 ;
     RECT  43.455 0.793 43.737 11.749 ;
     RECT  70.164 11.515 72.81 11.749 ;
     RECT  0.036 11.245 3.438 11.785 ;
     RECT  54.255 11.677 54.954 11.785 ;
     RECT  53.928 11.785 54.954 11.813 ;
     RECT  5.655 11.693 5.937 11.821 ;
     RECT  8.352 11.579 8.694 11.821 ;
     RECT  10.8 11.551 11.61 11.821 ;
     RECT  27.255 11.713 29.286 11.821 ;
     RECT  30.096 11.507 30.402 11.821 ;
     RECT  36.504 11.785 36.666 11.837 ;
     RECT  53.928 11.813 54.537 11.837 ;
     RECT  34.2 11.543 34.938 11.849 ;
     RECT  37.62 11.669 39.402 11.849 ;
     RECT  5.655 11.821 6.066 11.911 ;
     RECT  10.728 11.821 11.61 11.911 ;
     RECT  4.464 11.693 4.914 11.939 ;
     RECT  18.72 11.453 20.61 11.939 ;
     RECT  21.564 11.669 22.842 11.939 ;
     RECT  27.255 11.821 30.402 11.939 ;
     RECT  34.236 11.849 34.938 11.939 ;
     RECT  35.676 11.669 35.694 11.939 ;
     RECT  37.62 11.849 38.337 11.939 ;
     RECT  69.984 11.749 72.81 11.947 ;
     RECT  37.908 11.939 38.337 11.975 ;
     RECT  24.768 11.749 26.262 11.981 ;
     RECT  13.572 11.357 13.59 11.983 ;
     RECT  21.6 11.939 22.842 12.055 ;
     RECT  13.572 11.983 14.814 12.091 ;
     RECT  18.72 11.939 19.386 12.119 ;
     RECT  6.84 11.669 7.362 12.209 ;
     RECT  37.98 11.975 38.337 12.209 ;
     RECT  16.455 11.399 17.586 12.217 ;
     RECT  10.728 11.911 12.474 12.235 ;
     RECT  13.392 12.091 14.814 12.235 ;
     RECT  8.208 11.821 8.694 12.281 ;
     RECT  18.72 12.119 18.99 12.283 ;
     RECT  6.84 12.209 6.858 12.317 ;
     RECT  16.455 12.217 17.73 12.331 ;
     RECT  18.576 12.283 18.99 12.331 ;
     RECT  10.728 12.235 14.814 12.361 ;
     RECT  8.208 12.281 8.586 12.389 ;
     RECT  16.455 12.331 18.99 12.389 ;
     RECT  21.6 12.055 23.022 12.389 ;
     RECT  21.6 12.389 22.842 12.479 ;
     RECT  28.512 11.939 29.286 12.479 ;
     RECT  0.036 11.785 3.546 12.487 ;
     RECT  4.464 11.939 4.626 12.487 ;
     RECT  30.204 11.939 30.402 12.517 ;
     RECT  31.212 11.713 32.937 12.517 ;
     RECT  10.728 12.361 14.886 12.523 ;
     RECT  16.455 12.389 18.954 12.551 ;
     RECT  66.708 11.677 66.726 12.551 ;
     RECT  20.16 11.939 20.61 12.559 ;
     RECT  10.728 12.523 15.354 12.571 ;
     RECT  54.255 11.837 54.537 12.631 ;
     RECT  25.344 11.981 26.262 12.659 ;
     RECT  36.504 11.837 36.522 12.749 ;
     RECT  38.055 12.209 38.337 12.757 ;
     RECT  39.348 11.849 39.402 12.757 ;
     RECT  27.255 11.939 27.63 12.793 ;
     RECT  50.724 12.631 50.742 12.793 ;
     RECT  20.16 12.559 20.682 12.811 ;
     RECT  10.296 12.571 15.354 12.829 ;
     RECT  16.455 12.551 18.882 12.829 ;
     RECT  34.236 11.939 34.758 12.829 ;
     RECT  40.824 12.757 40.842 12.829 ;
     RECT  19.872 12.811 20.682 12.856 ;
     RECT  21.6 12.479 22.77 12.856 ;
     RECT  35.928 12.811 35.946 12.857 ;
     RECT  40.752 12.829 40.842 12.857 ;
     RECT  54.255 12.631 54.594 12.857 ;
     RECT  5.655 11.911 6.102 12.859 ;
     RECT  50.724 12.793 50.814 12.865 ;
     RECT  69.84 11.947 72.81 12.865 ;
     RECT  19.872 12.856 22.77 12.893 ;
     RECT  30.204 12.517 32.937 12.893 ;
     RECT  34.128 12.829 34.794 12.901 ;
     RECT  40.752 12.857 40.77 12.901 ;
     RECT  54.255 12.857 54.537 12.901 ;
     RECT  40.68 12.901 40.77 12.929 ;
     RECT  66.744 12.631 66.762 12.929 ;
     RECT  26.784 12.793 27.63 12.955 ;
     RECT  28.512 12.479 29.25 12.955 ;
     RECT  8.208 12.389 8.226 12.991 ;
     RECT  25.344 12.659 25.686 12.991 ;
     RECT  38.055 12.757 39.402 12.991 ;
     RECT  40.68 12.929 40.698 12.991 ;
     RECT  42.84 11.749 43.737 12.991 ;
     RECT  8.136 12.991 8.226 13.019 ;
     RECT  10.296 12.829 18.882 13.019 ;
     RECT  25.236 12.991 25.686 13.019 ;
     RECT  26.784 12.955 29.25 13.019 ;
     RECT  34.056 12.901 34.794 13.019 ;
     RECT  36.936 12.829 36.954 13.019 ;
     RECT  40.608 12.991 40.698 13.019 ;
     RECT  44.568 12.907 44.586 13.019 ;
     RECT  50.724 12.865 50.886 13.019 ;
     RECT  8.136 13.019 8.154 13.027 ;
     RECT  25.236 13.019 25.29 13.037 ;
     RECT  7.92 13.027 8.154 13.051 ;
     RECT  31.248 12.893 32.937 13.055 ;
     RECT  42.696 12.991 43.737 13.063 ;
     RECT  7.272 13.051 8.154 13.085 ;
     RECT  26.784 13.019 28.35 13.085 ;
     RECT  29.088 13.019 29.25 13.085 ;
     RECT  12.78 13.019 12.798 13.091 ;
     RECT  40.608 13.019 40.626 13.091 ;
     RECT  42.696 13.063 44.55 13.163 ;
     RECT  0.036 12.487 4.626 13.289 ;
     RECT  16.416 13.019 18.882 13.289 ;
     RECT  18.756 13.289 18.882 13.387 ;
     RECT  21.348 12.893 22.77 13.387 ;
     RECT  69.552 12.865 72.81 13.405 ;
     RECT  21.348 13.387 22.842 13.441 ;
     RECT  38.055 12.991 39.69 13.469 ;
     RECT  9.144 13.369 9.234 13.531 ;
     RECT  10.296 13.019 11.97 13.531 ;
     RECT  54.216 12.901 54.537 13.531 ;
     RECT  65.055 0.793 65.337 13.531 ;
     RECT  16.416 13.289 17.874 13.559 ;
     RECT  30.204 12.893 30.222 13.559 ;
     RECT  66.708 13.387 66.726 13.565 ;
     RECT  53.892 13.531 54.537 13.567 ;
     RECT  64.944 13.531 65.337 13.568 ;
     RECT  5.655 12.859 6.282 13.579 ;
     RECT  7.272 13.085 7.614 13.579 ;
     RECT  53.28 13.567 54.537 13.613 ;
     RECT  26.784 13.085 28.314 13.627 ;
     RECT  18.756 13.387 19.098 13.639 ;
     RECT  19.872 12.893 20.538 13.639 ;
     RECT  42.696 13.163 44.478 13.639 ;
     RECT  13.68 13.019 15.498 13.661 ;
     RECT  21.348 13.441 22.878 13.661 ;
     RECT  31.248 13.055 31.266 13.675 ;
     RECT  30.78 13.675 31.266 13.703 ;
     RECT  18.756 13.639 20.538 13.739 ;
     RECT  13.68 13.661 15.282 13.801 ;
     RECT  30.78 13.703 31.086 13.829 ;
     RECT  34.056 13.019 34.29 13.829 ;
     RECT  50.724 13.019 50.742 13.829 ;
     RECT  32.004 13.055 32.937 13.873 ;
     RECT  23.94 11.669 23.958 13.901 ;
     RECT  16.416 13.559 17.838 13.909 ;
     RECT  22.896 13.711 23.058 13.91 ;
     RECT  22.896 13.91 23.022 13.937 ;
     RECT  19.152 13.739 20.538 13.945 ;
     RECT  21.348 13.661 22.137 13.945 ;
     RECT  25.272 13.037 25.29 13.945 ;
     RECT  26.388 13.627 28.314 13.945 ;
     RECT  9.144 13.531 11.97 13.981 ;
     RECT  25.272 13.945 25.47 13.981 ;
     RECT  31.968 13.873 32.937 13.981 ;
     RECT  34.056 13.829 34.218 13.981 ;
     RECT  42.624 13.639 44.478 13.981 ;
     RECT  59.655 0.793 59.937 13.981 ;
     RECT  23.004 13.937 23.022 14.009 ;
     RECT  26.388 13.945 28.386 14.071 ;
     RECT  64.008 14.059 64.026 14.099 ;
     RECT  25.2 13.981 25.47 14.143 ;
     RECT  26.352 14.071 28.386 14.143 ;
     RECT  8.892 13.981 11.97 14.171 ;
     RECT  13.356 13.801 15.282 14.171 ;
     RECT  14.436 14.171 15.282 14.207 ;
     RECT  5.655 13.579 7.614 14.215 ;
     RECT  65.055 13.568 65.337 14.215 ;
     RECT  13.356 14.171 13.662 14.243 ;
     RECT  16.02 13.909 17.838 14.243 ;
     RECT  26.352 14.143 28.458 14.243 ;
     RECT  17.82 14.243 17.838 14.299 ;
     RECT  42.624 13.981 44.514 14.299 ;
     RECT  45.468 13.297 45.486 14.299 ;
     RECT  46.332 14.251 46.422 14.299 ;
     RECT  46.332 14.299 46.602 14.369 ;
     RECT  57.024 14.341 57.042 14.381 ;
     RECT  5.655 14.215 8.01 14.395 ;
     RECT  47.52 14.341 47.538 14.429 ;
     RECT  53.892 13.613 54.537 14.449 ;
     RECT  17.82 14.299 17.946 14.485 ;
     RECT  42.624 14.299 45.486 14.485 ;
     RECT  0.036 13.289 3.978 14.513 ;
     RECT  42.372 14.485 45.486 14.521 ;
     RECT  48.855 11.399 49.137 14.521 ;
     RECT  57.06 14.449 57.078 14.521 ;
     RECT  58.068 13.909 58.086 14.521 ;
     RECT  59.4 13.981 59.937 14.521 ;
     RECT  42.372 14.521 45.63 14.525 ;
     RECT  40.68 14.449 40.698 14.539 ;
     RECT  42.624 14.525 45.63 14.549 ;
     RECT  52.884 14.491 52.902 14.549 ;
     RECT  62.532 14.521 62.55 14.587 ;
     RECT  17.82 14.485 18.018 14.611 ;
     RECT  40.608 14.539 40.698 14.611 ;
     RECT  53.892 14.449 54.738 14.611 ;
     RECT  0.036 14.513 3.51 14.639 ;
     RECT  14.58 14.207 15.282 14.639 ;
     RECT  27.255 14.243 28.458 14.639 ;
     RECT  29.232 13.085 29.25 14.639 ;
     RECT  40.536 14.611 40.698 14.639 ;
     RECT  46.404 14.369 46.602 14.639 ;
     RECT  51.948 14.521 52.146 14.639 ;
     RECT  62.496 14.587 62.55 14.639 ;
     RECT  39.312 13.469 39.69 14.675 ;
     RECT  47.556 14.449 47.574 14.683 ;
     RECT  40.536 14.639 40.554 14.711 ;
     RECT  47.556 14.683 47.646 14.711 ;
     RECT  58.068 14.521 59.937 14.711 ;
     RECT  62.532 14.639 62.55 14.711 ;
     RECT  61.56 14.647 61.578 14.717 ;
     RECT  13.14 14.413 13.194 14.731 ;
     RECT  16.02 14.243 17.046 14.755 ;
     RECT  28.476 14.683 28.494 14.765 ;
     RECT  47.628 14.711 47.646 14.783 ;
     RECT  31.068 13.829 31.086 14.791 ;
     RECT  31.968 13.981 34.218 14.791 ;
     RECT  56.088 14.485 56.106 14.813 ;
     RECT  42.804 14.549 45.63 14.819 ;
     RECT  51.948 14.639 52.038 14.872 ;
     RECT  9.576 14.171 11.97 14.881 ;
     RECT  12.888 14.731 13.194 14.881 ;
     RECT  19.152 13.945 22.137 14.881 ;
     RECT  25.056 14.143 25.47 14.881 ;
     RECT  4.896 14.791 4.914 14.909 ;
     RECT  58.896 14.711 59.937 14.909 ;
     RECT  37.044 13.063 37.062 14.923 ;
     RECT  38.055 13.469 38.337 14.923 ;
     RECT  51.732 14.872 52.038 14.923 ;
     RECT  23.724 14.875 23.742 14.945 ;
     RECT  19.152 14.881 22.842 14.989 ;
     RECT  23.58 14.953 23.598 14.989 ;
     RECT  25.056 14.881 25.938 14.989 ;
     RECT  27.255 14.639 27.537 14.989 ;
     RECT  46.764 14.923 46.782 14.989 ;
     RECT  57.06 14.521 57.294 14.989 ;
     RECT  58.068 14.711 58.086 14.989 ;
     RECT  65.055 14.215 65.754 14.989 ;
     RECT  15.624 14.755 17.046 15.016 ;
     RECT  17.82 14.611 18.162 15.016 ;
     RECT  31.068 14.791 34.218 15.025 ;
     RECT  37.044 14.923 38.337 15.025 ;
     RECT  39.312 14.675 39.366 15.025 ;
     RECT  69.552 13.405 72.954 15.025 ;
     RECT  50.724 14.923 52.038 15.053 ;
     RECT  66.744 14.953 66.762 15.053 ;
     RECT  9.576 14.881 13.194 15.061 ;
     RECT  14.58 14.639 14.85 15.061 ;
     RECT  24.588 14.989 25.938 15.061 ;
     RECT  31.032 15.025 34.218 15.061 ;
     RECT  58.896 14.909 58.914 15.101 ;
     RECT  64.764 14.989 65.754 15.101 ;
     RECT  9.576 15.061 14.85 15.115 ;
     RECT  24.552 15.061 25.974 15.151 ;
     RECT  26.784 14.989 27.537 15.151 ;
     RECT  31.032 15.061 34.902 15.179 ;
     RECT  37.044 15.025 39.366 15.179 ;
     RECT  50.724 15.053 50.814 15.179 ;
     RECT  51.768 15.053 52.038 15.179 ;
     RECT  53.46 14.611 54.738 15.179 ;
     RECT  62.712 14.989 62.73 15.179 ;
     RECT  69.516 15.025 72.954 15.179 ;
     RECT  15.624 15.016 18.162 15.187 ;
     RECT  19.152 14.989 23.598 15.187 ;
     RECT  15.624 15.187 23.598 15.215 ;
     RECT  54.255 15.179 54.738 15.223 ;
     RECT  65.055 15.101 65.754 15.223 ;
     RECT  4.428 14.989 4.626 15.251 ;
     RECT  69.552 15.179 72.954 15.251 ;
     RECT  15.624 15.215 23.382 15.287 ;
     RECT  24.408 15.151 27.537 15.287 ;
     RECT  37.044 15.179 37.242 15.323 ;
     RECT  40.248 15.061 40.338 15.323 ;
     RECT  5.655 14.395 8.55 15.421 ;
     RECT  9.468 15.115 14.85 15.421 ;
     RECT  42.804 14.819 43.737 15.421 ;
     RECT  46.764 14.989 46.818 15.421 ;
     RECT  50.724 15.179 50.742 15.421 ;
     RECT  37.044 15.323 37.206 15.449 ;
     RECT  31.032 15.179 31.662 15.493 ;
     RECT  32.616 15.179 34.902 15.493 ;
     RECT  38.055 15.179 39.366 15.493 ;
     RECT  46.548 15.421 46.818 15.529 ;
     RECT  5.655 15.421 14.85 15.557 ;
     RECT  0.036 14.639 3.438 15.565 ;
     RECT  15.624 15.287 18.342 15.581 ;
     RECT  29.664 15.451 29.682 15.601 ;
     RECT  30.816 15.493 31.662 15.601 ;
     RECT  46.476 15.529 46.818 15.601 ;
     RECT  50.508 15.421 50.742 15.601 ;
     RECT  5.655 15.557 8.622 15.629 ;
     RECT  24.768 15.287 27.537 15.629 ;
     RECT  29.592 15.601 29.682 15.629 ;
     RECT  42.768 15.421 43.737 15.629 ;
     RECT  50.436 15.601 50.742 15.643 ;
     RECT  9.432 15.557 14.85 15.719 ;
     RECT  37.044 15.449 37.098 15.719 ;
     RECT  48.456 14.521 49.137 15.719 ;
     RECT  50.4 15.643 50.742 15.719 ;
     RECT  53.46 15.179 53.478 15.719 ;
     RECT  48.855 15.719 49.137 15.727 ;
     RECT  37.08 15.719 37.098 15.755 ;
     RECT  48.855 15.727 49.482 15.763 ;
     RECT  50.436 15.719 50.742 15.791 ;
     RECT  38.055 15.493 40.014 15.827 ;
     RECT  19.404 15.287 23.382 15.863 ;
     RECT  32.616 15.493 35.154 15.899 ;
     RECT  46.476 15.601 46.854 15.961 ;
     RECT  50.616 15.791 50.742 15.961 ;
     RECT  51.768 15.179 51.966 15.961 ;
     RECT  54.255 15.223 54.81 15.961 ;
     RECT  59.655 14.909 59.937 15.961 ;
     RECT  44.46 14.819 45.63 15.979 ;
     RECT  57.06 14.989 58.086 15.979 ;
     RECT  59.655 15.961 60.318 15.979 ;
     RECT  24.768 15.629 26.478 15.989 ;
     RECT  46.476 15.961 47.43 15.997 ;
     RECT  54.255 15.961 55.134 15.997 ;
     RECT  65.055 15.223 66.15 15.997 ;
     RECT  50.616 15.961 51.966 16.013 ;
     RECT  44.46 15.979 45.738 16.033 ;
     RECT  46.476 15.997 47.502 16.033 ;
     RECT  54.255 15.997 55.638 16.033 ;
     RECT  65.055 15.997 66.186 16.033 ;
     RECT  68.544 14.989 68.562 16.069 ;
     RECT  44.46 16.033 47.502 16.075 ;
     RECT  24.768 15.989 25.11 16.105 ;
     RECT  28.512 15.403 28.53 16.105 ;
     RECT  29.592 15.629 29.61 16.105 ;
     RECT  30.78 15.601 31.662 16.105 ;
     RECT  32.616 15.899 33.354 16.105 ;
     RECT  54.255 16.033 55.71 16.105 ;
     RECT  5.655 15.629 7.686 16.133 ;
     RECT  42.804 15.629 43.737 16.141 ;
     RECT  44.46 16.075 47.538 16.141 ;
     RECT  50.724 16.013 51.966 16.141 ;
     RECT  69.624 15.251 72.954 16.141 ;
     RECT  54.255 16.105 55.746 16.219 ;
     RECT  59.655 15.979 60.426 16.231 ;
     RECT  68.472 16.069 68.562 16.231 ;
     RECT  19.404 15.863 19.422 16.259 ;
     RECT  20.376 15.863 23.382 16.259 ;
     RECT  28.512 16.105 29.61 16.259 ;
     RECT  41.292 14.881 41.31 16.259 ;
     RECT  42.804 16.141 47.538 16.259 ;
     RECT  56.7 15.979 58.086 16.259 ;
     RECT  59.256 16.231 60.426 16.261 ;
     RECT  59.184 16.261 60.426 16.295 ;
     RECT  56.7 16.259 56.862 16.301 ;
     RECT  59.184 16.295 59.994 16.301 ;
     RECT  38.055 15.827 39.978 16.303 ;
     RECT  9.504 15.719 14.85 16.315 ;
     RECT  15.624 15.581 15.642 16.315 ;
     RECT  44.568 16.259 47.538 16.331 ;
     RECT  59.256 16.301 59.994 16.331 ;
     RECT  68.364 16.231 68.562 16.331 ;
     RECT  53.748 16.219 55.746 16.339 ;
     RECT  16.455 15.581 18.342 16.363 ;
     RECT  29.448 16.259 29.61 16.363 ;
     RECT  50.724 16.141 52.326 16.375 ;
     RECT  20.376 16.259 20.718 16.403 ;
     RECT  56.7 16.301 56.718 16.403 ;
     RECT  25.848 15.989 26.478 16.411 ;
     RECT  27.255 15.629 27.537 16.411 ;
     RECT  59.256 16.331 59.937 16.439 ;
     RECT  16.455 16.363 18.846 16.493 ;
     RECT  68.4 16.331 68.562 16.501 ;
     RECT  21.564 16.259 23.382 16.529 ;
     RECT  24.552 16.105 25.11 16.529 ;
     RECT  29.448 16.363 29.898 16.529 ;
     RECT  44.748 16.331 47.538 16.529 ;
     RECT  46.26 16.529 47.538 16.537 ;
     RECT  53.748 16.339 55.782 16.537 ;
     RECT  65.055 16.033 66.762 16.537 ;
     RECT  5.655 16.133 6.03 16.541 ;
     RECT  9.504 16.315 15.642 16.541 ;
     RECT  50.724 16.375 53.01 16.541 ;
     RECT  29.664 16.529 29.898 16.573 ;
     RECT  30.78 16.105 33.354 16.573 ;
     RECT  65.055 16.537 66.798 16.573 ;
     RECT  37.404 16.303 39.978 16.6 ;
     RECT  8.424 15.629 8.622 16.609 ;
     RECT  9.504 16.541 14.85 16.609 ;
     RECT  42.804 16.259 43.737 16.609 ;
     RECT  53.748 16.537 55.854 16.609 ;
     RECT  6.84 16.133 7.686 16.651 ;
     RECT  8.424 16.609 14.85 16.651 ;
     RECT  34.416 15.899 34.578 16.681 ;
     RECT  34.416 16.681 34.866 16.699 ;
     RECT  46.26 16.537 48.042 16.709 ;
     RECT  62.748 16.681 62.766 16.747 ;
     RECT  29.664 16.573 33.354 16.771 ;
     RECT  34.416 16.699 34.974 16.771 ;
     RECT  6.84 16.651 14.85 16.799 ;
     RECT  16.455 16.493 18.342 16.799 ;
     RECT  29.664 16.771 34.974 16.807 ;
     RECT  60.84 16.681 61.002 16.829 ;
     RECT  6.84 16.799 7.506 16.835 ;
     RECT  24.912 16.529 25.11 16.835 ;
     RECT  29.664 16.807 35.37 16.835 ;
     RECT  68.4 16.501 68.706 16.843 ;
     RECT  69.552 16.141 72.954 16.843 ;
     RECT  53.352 16.609 55.854 16.877 ;
     RECT  65.055 16.573 66.87 16.877 ;
     RECT  66.096 16.877 66.87 16.879 ;
     RECT  16.455 16.799 18.234 16.88 ;
     RECT  46.26 16.709 46.782 16.907 ;
     RECT  15.624 16.541 15.642 16.915 ;
     RECT  16.455 16.88 18.198 16.915 ;
     RECT  31.788 16.835 35.37 16.915 ;
     RECT  44.748 16.529 45.522 16.925 ;
     RECT  31.788 16.915 35.406 16.943 ;
     RECT  33.876 16.943 35.406 16.951 ;
     RECT  37.332 16.6 39.978 16.951 ;
     RECT  53.532 16.877 55.854 16.973 ;
     RECT  57.852 16.259 57.87 16.973 ;
     RECT  8.568 16.799 14.85 16.979 ;
     RECT  36.936 16.951 39.978 16.979 ;
     RECT  53.604 16.973 55.854 16.979 ;
     RECT  25.848 16.411 27.537 17.021 ;
     RECT  42.768 16.609 43.737 17.035 ;
     RECT  6.84 16.835 7.47 17.069 ;
     RECT  8.568 16.979 11.79 17.069 ;
     RECT  31.788 16.943 33.138 17.069 ;
     RECT  36.936 16.979 39.906 17.069 ;
     RECT  44.748 16.925 44.766 17.069 ;
     RECT  0.036 15.565 3.978 17.083 ;
     RECT  42.768 17.035 43.83 17.083 ;
     RECT  62.172 16.747 62.766 17.083 ;
     RECT  25.848 17.021 26.082 17.105 ;
     RECT  33.876 16.951 35.658 17.105 ;
     RECT  36.936 17.069 39.798 17.105 ;
     RECT  50.724 16.541 52.614 17.105 ;
     RECT  42.552 17.083 43.83 17.113 ;
     RECT  62.1 17.083 62.766 17.113 ;
     RECT  45.504 16.925 45.522 17.117 ;
     RECT  66.096 16.879 67.158 17.131 ;
     RECT  47.88 16.709 48.042 17.149 ;
     RECT  48.855 15.763 49.662 17.149 ;
     RECT  66.096 17.131 67.194 17.177 ;
     RECT  0.036 17.083 4.59 17.179 ;
     RECT  5.655 16.541 5.937 17.179 ;
     RECT  42.552 17.113 43.902 17.185 ;
     RECT  62.1 17.113 62.802 17.221 ;
     RECT  0.036 17.179 5.937 17.249 ;
     RECT  21.6 16.529 23.382 17.249 ;
     RECT  24.912 16.835 25.002 17.249 ;
     RECT  58.716 17.149 58.806 17.249 ;
     RECT  15.624 16.915 18.198 17.339 ;
     RECT  21.6 17.249 22.137 17.339 ;
     RECT  24.912 17.249 24.93 17.339 ;
     RECT  36.936 17.105 38.862 17.339 ;
     RECT  58.716 17.249 58.734 17.339 ;
     RECT  66.132 17.177 67.194 17.339 ;
     RECT  38.055 17.339 38.862 17.348 ;
     RECT  18.108 17.339 18.198 17.375 ;
     RECT  62.1 17.221 62.91 17.375 ;
     RECT  12.564 16.979 14.85 17.383 ;
     RECT  29.664 16.835 30.978 17.383 ;
     RECT  41.832 17.185 44.55 17.411 ;
     RECT  20.376 16.403 20.682 17.419 ;
     RECT  57.096 17.083 57.114 17.419 ;
     RECT  57.024 17.419 57.114 17.455 ;
     RECT  23.292 17.249 23.382 17.491 ;
     RECT  46.584 16.907 46.782 17.491 ;
     RECT  50.724 17.105 52.506 17.491 ;
     RECT  20.376 17.419 20.898 17.519 ;
     RECT  67.104 17.339 67.194 17.519 ;
     RECT  12.564 17.383 14.886 17.609 ;
     RECT  18.18 17.375 18.198 17.609 ;
     RECT  23.292 17.491 23.994 17.609 ;
     RECT  34.38 17.105 35.658 17.609 ;
     RECT  41.832 17.411 44.478 17.609 ;
     RECT  62.1 17.375 62.838 17.609 ;
     RECT  8.568 17.069 11.337 17.645 ;
     RECT  59.58 16.439 59.937 17.645 ;
     RECT  60.984 16.829 61.002 17.653 ;
     RECT  62.1 17.609 62.766 17.653 ;
     RECT  41.832 17.609 41.922 17.659 ;
     RECT  60.984 17.653 62.766 17.681 ;
     RECT  31.788 17.069 31.806 17.689 ;
     RECT  12.564 17.609 14.85 17.693 ;
     RECT  42.732 17.609 44.478 17.693 ;
     RECT  28.512 16.259 28.674 17.707 ;
     RECT  29.556 17.383 30.978 17.707 ;
     RECT  47.88 17.149 49.662 17.707 ;
     RECT  56.988 17.455 57.114 17.707 ;
     RECT  31.752 17.689 31.806 17.725 ;
     RECT  26.064 17.105 26.082 17.753 ;
     RECT  46.584 17.491 46.818 17.761 ;
     RECT  50.58 17.491 52.506 17.761 ;
     RECT  4.572 17.249 5.937 17.789 ;
     RECT  18.828 17.659 18.846 17.837 ;
     RECT  26.856 17.021 27.537 17.851 ;
     RECT  56.7 17.707 57.114 17.851 ;
     RECT  38.055 17.348 38.826 17.879 ;
     RECT  67.284 17.653 67.302 17.879 ;
     RECT  8.568 17.645 9.306 17.887 ;
     RECT  46.584 17.761 46.926 17.887 ;
     RECT  47.88 17.707 49.806 17.887 ;
     RECT  56.7 17.851 57.762 17.887 ;
     RECT  58.536 17.689 58.59 17.887 ;
     RECT  21.744 17.339 22.137 17.888 ;
     RECT  28.512 17.707 30.978 17.947 ;
     RECT  42.804 17.693 44.478 17.951 ;
     RECT  31.716 17.725 31.806 17.959 ;
     RECT  46.584 17.887 49.806 17.959 ;
     RECT  50.544 17.761 52.506 17.959 ;
     RECT  28.368 17.947 30.978 17.987 ;
     RECT  5.148 17.789 5.937 17.995 ;
     RECT  6.912 17.069 7.47 17.995 ;
     RECT  6.84 17.995 7.47 18.031 ;
     RECT  31.716 17.959 31.878 18.031 ;
     RECT  32.655 17.069 32.937 18.031 ;
     RECT  41.616 17.659 41.922 18.031 ;
     RECT  28.368 17.987 30.402 18.059 ;
     RECT  46.584 17.959 52.506 18.059 ;
     RECT  38.055 17.879 38.337 18.091 ;
     RECT  5.148 17.995 6.03 18.121 ;
     RECT  6.84 18.031 7.506 18.121 ;
     RECT  31.5 18.031 31.878 18.121 ;
     RECT  32.655 18.031 33.282 18.121 ;
     RECT  47.232 18.059 52.506 18.121 ;
     RECT  12.564 17.693 12.906 18.149 ;
     RECT  31.5 18.121 33.282 18.149 ;
     RECT  36.936 17.339 37.134 18.149 ;
     RECT  37.872 18.091 38.337 18.149 ;
     RECT  41.184 18.031 41.922 18.149 ;
     RECT  23.364 17.609 23.994 18.157 ;
     RECT  31.608 18.149 33.282 18.185 ;
     RECT  53.604 16.979 55.782 18.185 ;
     RECT  56.628 17.887 58.59 18.185 ;
     RECT  0.036 17.249 3.546 18.187 ;
     RECT  20.376 17.519 20.538 18.193 ;
     RECT  55.764 18.185 55.782 18.193 ;
     RECT  56.628 18.185 58.158 18.193 ;
     RECT  5.148 18.121 7.506 18.221 ;
     RECT  10.404 17.645 11.337 18.221 ;
     RECT  31.788 18.185 33.282 18.221 ;
     RECT  47.232 18.121 52.83 18.221 ;
     RECT  68.4 16.843 72.954 18.229 ;
     RECT  7.416 18.221 7.506 18.265 ;
     RECT  41.184 18.149 41.634 18.265 ;
     RECT  66.132 17.339 66.366 18.265 ;
     RECT  15.624 17.339 17.226 18.283 ;
     RECT  43.455 17.951 44.478 18.283 ;
     RECT  40.968 18.265 41.634 18.293 ;
     RECT  68.148 18.229 72.954 18.293 ;
     RECT  40.968 18.293 40.986 18.317 ;
     RECT  8.532 17.887 9.306 18.391 ;
     RECT  55.764 18.193 58.158 18.419 ;
     RECT  32.508 18.221 33.282 18.461 ;
     RECT  34.38 17.609 35.406 18.461 ;
     RECT  68.148 18.293 69.066 18.463 ;
     RECT  8.424 18.391 9.306 18.499 ;
     RECT  21.855 17.888 22.137 18.499 ;
     RECT  29.088 18.059 30.402 18.509 ;
     RECT  20.268 18.193 20.538 18.527 ;
     RECT  66.132 18.265 66.798 18.527 ;
     RECT  60.984 17.681 62.262 18.535 ;
     RECT  10.836 18.221 11.337 18.565 ;
     RECT  34.884 18.461 35.406 18.571 ;
     RECT  29.088 18.509 29.79 18.599 ;
     RECT  34.884 18.571 36.09 18.599 ;
     RECT  10.836 18.565 11.718 18.605 ;
     RECT  29.088 18.599 29.466 18.605 ;
     RECT  38.055 18.149 38.337 18.619 ;
     RECT  0.036 18.187 3.762 18.661 ;
     RECT  21.855 18.499 22.23 18.661 ;
     RECT  23.364 18.157 24.102 18.661 ;
     RECT  15.624 18.283 17.73 18.689 ;
     RECT  43.455 18.283 44.694 18.689 ;
     RECT  7.416 18.265 7.578 18.697 ;
     RECT  8.424 18.499 9.594 18.697 ;
     RECT  0.036 18.661 3.798 18.701 ;
     RECT  47.232 18.221 49.194 18.701 ;
     RECT  38.055 18.619 38.79 18.749 ;
     RECT  69.804 18.293 72.954 18.761 ;
     RECT  13.68 17.693 14.85 18.769 ;
     RECT  5.148 18.221 6.03 18.797 ;
     RECT  50.292 18.221 52.83 18.797 ;
     RECT  60.984 18.535 62.406 18.797 ;
     RECT  46.188 18.193 46.206 18.805 ;
     RECT  47.232 18.701 47.43 18.805 ;
     RECT  16.164 18.689 17.73 18.811 ;
     RECT  12.636 18.149 12.906 18.841 ;
     RECT  13.68 18.769 15.318 18.841 ;
     RECT  20.268 18.527 20.358 18.841 ;
     RECT  21.855 18.661 24.102 18.841 ;
     RECT  59.655 17.645 59.937 18.841 ;
     RECT  35.424 18.599 36.09 18.907 ;
     RECT  59.472 18.841 59.937 18.907 ;
     RECT  52.812 18.797 52.83 18.931 ;
     RECT  53.604 18.185 54.81 18.931 ;
     RECT  59.4 18.907 59.937 18.931 ;
     RECT  65.055 16.877 65.337 18.931 ;
     RECT  43.455 18.689 44.478 18.955 ;
     RECT  55.872 18.419 58.158 18.955 ;
     RECT  58.968 18.931 59.937 18.955 ;
     RECT  63.144 18.571 63.162 18.955 ;
     RECT  0.036 18.701 3.33 18.959 ;
     RECT  32.655 18.461 33.282 18.959 ;
     RECT  34.128 18.571 34.146 18.959 ;
     RECT  7.416 18.697 9.594 18.967 ;
     RECT  63.144 18.955 63.45 18.967 ;
     RECT  48.384 18.701 49.194 18.989 ;
     RECT  62.712 18.967 63.45 18.995 ;
     RECT  21.855 18.841 24.354 19.031 ;
     RECT  68.076 18.463 69.066 19.031 ;
     RECT  6.876 18.967 9.594 19.039 ;
     RECT  43.272 18.955 44.478 19.051 ;
     RECT  69.804 18.761 72.918 19.075 ;
     RECT  12.636 18.841 15.318 19.111 ;
     RECT  16.164 18.811 18.162 19.111 ;
     RECT  26.784 17.851 27.537 19.111 ;
     RECT  45.216 18.811 45.234 19.111 ;
     RECT  12.168 19.111 15.318 19.139 ;
     RECT  33.984 19.003 34.074 19.139 ;
     RECT  52.812 18.931 54.81 19.139 ;
     RECT  60.984 18.797 61.578 19.139 ;
     RECT  16.164 19.111 18.846 19.195 ;
     RECT  19.584 18.841 20.358 19.195 ;
     RECT  42.768 19.051 44.478 19.195 ;
     RECT  26.64 19.111 27.537 19.201 ;
     RECT  16.164 19.195 20.358 19.229 ;
     RECT  24.912 19.051 24.93 19.229 ;
     RECT  35.424 18.907 36.45 19.229 ;
     RECT  45.216 19.111 45.27 19.229 ;
     RECT  42.336 19.195 44.478 19.235 ;
     RECT  52.992 19.139 54.81 19.237 ;
     RECT  55.872 18.955 59.937 19.265 ;
     RECT  66.708 18.527 66.798 19.273 ;
     RECT  55.872 19.265 57.798 19.277 ;
     RECT  5.655 18.797 6.03 19.291 ;
     RECT  6.876 19.039 9.702 19.291 ;
     RECT  68.076 19.031 68.418 19.309 ;
     RECT  16.164 19.229 19.494 19.325 ;
     RECT  29.088 18.605 29.106 19.336 ;
     RECT  16.164 19.325 19.458 19.337 ;
     RECT  20.34 19.229 20.358 19.337 ;
     RECT  45.252 19.229 45.27 19.337 ;
     RECT  36.144 19.229 36.45 19.345 ;
     RECT  40.356 19.201 40.374 19.345 ;
     RECT  19.368 19.337 19.458 19.373 ;
     RECT  26.46 19.201 27.537 19.373 ;
     RECT  34.056 19.139 34.074 19.373 ;
     RECT  55.872 19.277 56.466 19.373 ;
     RECT  66.708 19.273 67.086 19.373 ;
     RECT  55.872 19.373 55.89 19.381 ;
     RECT  55.764 19.381 55.89 19.387 ;
     RECT  13.14 19.139 15.318 19.409 ;
     RECT  16.164 19.337 18.414 19.409 ;
     RECT  46.188 18.805 47.43 19.409 ;
     RECT  40.356 19.345 40.446 19.421 ;
     RECT  21.855 19.031 24.102 19.435 ;
     RECT  40.356 19.421 40.41 19.435 ;
     RECT  29.088 19.336 29.25 19.471 ;
     RECT  66.708 19.373 67.014 19.471 ;
     RECT  5.655 19.291 9.702 19.499 ;
     RECT  21.744 19.435 24.102 19.499 ;
     RECT  31.536 19.435 31.554 19.499 ;
     RECT  42.768 19.235 44.478 19.499 ;
     RECT  55.728 19.387 55.89 19.499 ;
     RECT  52.992 19.237 54.846 19.507 ;
     RECT  58.644 19.265 59.937 19.507 ;
     RECT  28.62 19.471 29.25 19.517 ;
     RECT  30.6 19.483 30.618 19.535 ;
     RECT  46.764 19.409 47.43 19.535 ;
     RECT  52.992 19.507 54.882 19.535 ;
     RECT  26.496 19.373 27.537 19.543 ;
     RECT  13.14 19.409 14.022 19.565 ;
     RECT  53.352 19.535 54.882 19.565 ;
     RECT  14.832 19.409 15.318 19.571 ;
     RECT  50.616 18.797 51.606 19.571 ;
     RECT  55.764 19.499 55.89 19.571 ;
     RECT  66.528 19.471 67.014 19.571 ;
     RECT  29.088 19.517 29.25 19.579 ;
     RECT  64.332 18.931 65.337 19.579 ;
     RECT  66.528 19.571 66.798 19.579 ;
     RECT  16.164 19.409 16.794 19.615 ;
     RECT  39.924 19.435 40.41 19.627 ;
     RECT  14.832 19.571 15.066 19.643 ;
     RECT  58.644 19.507 60.246 19.643 ;
     RECT  31.572 19.543 31.59 19.651 ;
     RECT  32.655 18.959 33.102 19.651 ;
     RECT  38.055 18.749 38.43 19.651 ;
     RECT  43.344 19.499 44.478 19.651 ;
     RECT  29.088 19.579 29.574 19.679 ;
     RECT  39.492 19.627 40.41 19.679 ;
     RECT  57.528 19.277 57.798 19.679 ;
     RECT  58.644 19.643 60.174 19.679 ;
     RECT  62.712 18.995 62.838 19.679 ;
     RECT  14.832 19.643 14.994 19.709 ;
     RECT  37.944 19.651 38.574 19.741 ;
     RECT  39.492 19.679 40.338 19.741 ;
     RECT  53.388 19.565 54.882 19.741 ;
     RECT  26.496 19.543 27.594 19.768 ;
     RECT  5.655 19.499 8.586 19.769 ;
     RECT  14.832 19.709 14.85 19.769 ;
     RECT  31.572 19.651 33.102 19.769 ;
     RECT  36.144 19.345 36.522 19.769 ;
     RECT  43.344 19.651 44.514 19.769 ;
     RECT  46.764 19.535 46.854 19.769 ;
     RECT  51.408 19.571 51.606 19.769 ;
     RECT  57.6 19.679 57.798 19.769 ;
     RECT  5.655 19.769 7.506 19.805 ;
     RECT  53.388 19.741 54.954 19.805 ;
     RECT  58.644 19.679 60.138 19.805 ;
     RECT  57.6 19.769 57.726 19.841 ;
     RECT  67.824 19.309 68.418 19.849 ;
     RECT  37.944 19.741 40.338 19.853 ;
     RECT  51.444 19.769 51.606 19.877 ;
     RECT  58.644 19.805 60.102 19.877 ;
     RECT  10.836 18.605 11.337 19.912 ;
     RECT  36.36 19.769 36.522 19.913 ;
     RECT  50.616 19.571 50.634 19.913 ;
     RECT  53.388 19.805 54.882 19.913 ;
     RECT  10.728 19.912 11.337 19.915 ;
     RECT  12.168 19.139 12.186 19.915 ;
     RECT  9.468 19.499 9.702 19.921 ;
     RECT  10.728 19.915 12.186 19.921 ;
     RECT  26.496 19.768 27.63 19.949 ;
     RECT  37.944 19.853 39.942 19.949 ;
     RECT  67.824 19.849 68.526 19.949 ;
     RECT  61.56 19.139 61.578 19.963 ;
     RECT  62.712 19.679 62.802 19.963 ;
     RECT  37.944 19.949 38.394 20.011 ;
     RECT  61.56 19.963 62.802 20.011 ;
     RECT  61.344 20.011 62.802 20.039 ;
     RECT  37.44 20.011 38.394 20.048 ;
     RECT  61.344 20.039 61.578 20.048 ;
     RECT  36.432 19.913 36.522 20.093 ;
     RECT  19.404 19.373 19.458 20.119 ;
     RECT  0.036 18.959 3.114 20.191 ;
     RECT  17.748 19.409 18.414 20.191 ;
     RECT  25.236 19.345 25.254 20.191 ;
     RECT  41.112 20.155 41.13 20.191 ;
     RECT  17.748 20.191 18.666 20.203 ;
     RECT  37.764 20.048 38.394 20.219 ;
     RECT  48.384 18.989 49.137 20.281 ;
     RECT  0.036 20.191 3.33 20.309 ;
     RECT  9.468 19.921 12.186 20.309 ;
     RECT  17.568 20.203 18.666 20.309 ;
     RECT  36.504 20.093 36.522 20.309 ;
     RECT  56.664 20.203 56.682 20.309 ;
     RECT  69.552 19.075 72.918 20.309 ;
     RECT  64.332 19.579 66.798 20.317 ;
     RECT  13.5 19.565 14.022 20.347 ;
     RECT  13.5 20.347 14.13 20.381 ;
     RECT  67.824 19.949 68.49 20.381 ;
     RECT  15.912 19.615 16.794 20.389 ;
     RECT  17.856 20.309 18.666 20.389 ;
     RECT  19.404 20.119 19.494 20.389 ;
     RECT  4.752 19.615 4.77 20.417 ;
     RECT  0.036 20.309 3.114 20.429 ;
     RECT  55.872 19.571 55.89 20.429 ;
     RECT  21.855 19.499 24.102 20.443 ;
     RECT  8.316 19.769 8.586 20.461 ;
     RECT  9.468 20.309 11.646 20.461 ;
     RECT  28.26 20.389 28.35 20.489 ;
     RECT  55.728 20.461 55.746 20.525 ;
     RECT  46.764 19.769 46.818 20.539 ;
     RECT  47.88 20.281 49.137 20.539 ;
     RECT  53.388 19.913 54.81 20.551 ;
     RECT  62.568 20.039 62.802 20.551 ;
     RECT  13.68 20.381 14.13 20.579 ;
     RECT  64.044 20.317 66.798 20.579 ;
     RECT  8.316 20.461 11.646 20.587 ;
     RECT  53.28 20.551 54.81 20.587 ;
     RECT  66.564 20.579 66.798 20.587 ;
     RECT  14.58 20.587 14.85 20.623 ;
     RECT  43.344 19.769 43.938 20.623 ;
     RECT  5.655 19.805 6.894 20.635 ;
     RECT  7.632 20.587 11.646 20.635 ;
     RECT  14.58 20.623 14.886 20.659 ;
     RECT  34.812 20.623 34.83 20.659 ;
     RECT  43.344 20.623 43.974 20.659 ;
     RECT  32.112 19.769 33.102 20.683 ;
     RECT  53.244 20.587 54.81 20.687 ;
     RECT  38.055 20.219 38.394 20.695 ;
     RECT  39.276 19.949 39.942 20.695 ;
     RECT  46.188 20.539 47.034 20.695 ;
     RECT  47.808 20.539 49.137 20.695 ;
     RECT  14.58 20.659 15.174 20.731 ;
     RECT  15.912 20.389 16.902 20.731 ;
     RECT  41.112 20.191 41.166 20.731 ;
     RECT  46.188 20.695 49.137 20.731 ;
     RECT  51.948 20.539 51.966 20.731 ;
     RECT  62.568 20.551 62.838 20.731 ;
     RECT  20.88 20.587 20.898 20.821 ;
     RECT  21.744 20.443 24.102 20.821 ;
     RECT  43.344 20.659 44.01 20.821 ;
     RECT  51.804 20.731 51.966 20.821 ;
     RECT  58.644 19.877 59.937 20.821 ;
     RECT  67.824 20.381 68.454 20.821 ;
     RECT  45.396 20.821 45.414 20.827 ;
     RECT  51.66 20.821 52.038 20.827 ;
     RECT  14.58 20.731 16.902 20.849 ;
     RECT  37.152 20.779 37.17 20.849 ;
     RECT  46.152 20.731 49.137 20.857 ;
     RECT  58.392 20.821 59.937 20.861 ;
     RECT  46.152 20.857 49.59 20.885 ;
     RECT  4.608 20.587 4.626 20.893 ;
     RECT  50.76 20.551 50.922 20.893 ;
     RECT  57.6 19.841 57.618 20.909 ;
     RECT  5.655 20.635 11.646 20.921 ;
     RECT  51.66 20.827 52.11 20.921 ;
     RECT  26.64 19.949 27.537 20.923 ;
     RECT  34.776 20.659 34.83 20.929 ;
     RECT  62.568 20.731 63.306 20.929 ;
     RECT  64.044 20.579 65.61 20.929 ;
     RECT  46.152 20.885 46.998 20.957 ;
     RECT  45.18 20.827 45.414 20.965 ;
     RECT  66.564 20.587 66.906 20.993 ;
     RECT  38.055 20.695 39.942 21.001 ;
     RECT  40.716 20.731 41.166 21.001 ;
     RECT  53.28 20.687 54.81 21.001 ;
     RECT  55.548 20.731 55.638 21.001 ;
     RECT  58.572 20.861 59.937 21.005 ;
     RECT  17.856 20.389 19.494 21.029 ;
     RECT  4.284 20.893 4.626 21.091 ;
     RECT  26.244 20.923 27.537 21.091 ;
     RECT  28.26 20.489 28.278 21.091 ;
     RECT  34.776 20.929 34.902 21.091 ;
     RECT  38.055 21.001 41.166 21.091 ;
     RECT  42.804 20.821 44.01 21.091 ;
     RECT  44.928 20.965 45.414 21.091 ;
     RECT  69.552 20.309 72.846 21.091 ;
     RECT  10.08 20.921 11.646 21.115 ;
     RECT  61.56 20.048 61.578 21.115 ;
     RECT  62.568 20.929 65.61 21.115 ;
     RECT  29.088 19.679 29.106 21.119 ;
     RECT  47.736 20.885 49.59 21.119 ;
     RECT  51.66 20.921 51.894 21.119 ;
     RECT  61.56 21.115 65.61 21.119 ;
     RECT  30.816 21.091 30.834 21.127 ;
     RECT  32.004 20.683 33.102 21.127 ;
     RECT  38.055 21.091 41.562 21.127 ;
     RECT  42.804 21.091 45.414 21.127 ;
     RECT  50.724 20.893 50.922 21.127 ;
     RECT  10.08 21.115 11.718 21.163 ;
     RECT  12.564 20.587 12.582 21.163 ;
     RECT  14.652 20.849 16.902 21.163 ;
     RECT  18.324 21.029 19.494 21.163 ;
     RECT  29.988 21.091 30.006 21.163 ;
     RECT  30.816 21.127 30.906 21.163 ;
     RECT  32.004 21.127 33.21 21.163 ;
     RECT  34.308 21.091 34.902 21.163 ;
     RECT  67.68 20.821 68.454 21.163 ;
     RECT  29.34 21.163 30.006 21.197 ;
     RECT  61.56 21.119 63.342 21.197 ;
     RECT  5.655 20.921 9.27 21.199 ;
     RECT  38.055 21.127 41.742 21.199 ;
     RECT  47.808 21.119 49.59 21.199 ;
     RECT  50.724 21.127 51.21 21.199 ;
     RECT  20.88 20.821 24.102 21.235 ;
     RECT  24.984 20.191 25.254 21.235 ;
     RECT  26.244 21.091 28.278 21.235 ;
     RECT  37.332 21.199 41.742 21.235 ;
     RECT  61.56 21.197 62.442 21.235 ;
     RECT  69.444 21.091 72.846 21.235 ;
     RECT  61.524 21.235 62.442 21.259 ;
     RECT  34.308 21.163 35.334 21.263 ;
     RECT  4.104 21.091 4.626 21.271 ;
     RECT  5.364 21.199 9.27 21.271 ;
     RECT  31.824 21.163 33.21 21.271 ;
     RECT  53.28 21.001 55.638 21.271 ;
     RECT  66.708 20.993 66.906 21.271 ;
     RECT  67.68 21.163 68.49 21.271 ;
     RECT  69.372 21.235 72.846 21.271 ;
     RECT  29.34 21.197 29.43 21.299 ;
     RECT  20.556 21.235 25.254 21.355 ;
     RECT  58.716 21.005 59.937 21.355 ;
     RECT  20.556 21.355 25.362 21.361 ;
     RECT  31.824 21.271 33.75 21.361 ;
     RECT  34.74 21.263 35.334 21.361 ;
     RECT  3.816 21.271 9.27 21.389 ;
     RECT  18.324 21.163 19.638 21.389 ;
     RECT  37.332 21.235 41.778 21.389 ;
     RECT  63.288 21.197 63.342 21.389 ;
     RECT  37.332 21.389 41.49 21.395 ;
     RECT  34.74 21.361 35.514 21.397 ;
     RECT  66.708 21.271 66.942 21.451 ;
     RECT  67.68 21.271 72.846 21.451 ;
     RECT  20.556 21.361 25.434 21.461 ;
     RECT  26.244 21.235 28.314 21.461 ;
     RECT  66.708 21.451 72.846 21.461 ;
     RECT  20.556 21.461 25.038 21.469 ;
     RECT  53.28 21.271 56.106 21.47 ;
     RECT  5.655 21.389 9.27 21.497 ;
     RECT  10.08 21.163 12.582 21.497 ;
     RECT  10.08 21.497 11.79 21.533 ;
     RECT  47.808 21.199 51.21 21.533 ;
     RECT  10.08 21.533 11.43 21.539 ;
     RECT  20.484 21.469 25.038 21.541 ;
     RECT  58.716 21.355 60.21 21.541 ;
     RECT  61.128 21.259 62.442 21.541 ;
     RECT  10.152 21.539 11.43 21.569 ;
     RECT  42.804 21.127 45.918 21.569 ;
     RECT  46.764 20.957 46.998 21.629 ;
     RECT  13.68 20.579 13.806 21.631 ;
     RECT  14.652 21.163 16.938 21.631 ;
     RECT  26.244 21.461 27.63 21.631 ;
     RECT  56.988 21.001 57.006 21.631 ;
     RECT  53.28 21.47 56.07 21.643 ;
     RECT  56.988 21.631 57.114 21.643 ;
     RECT  53.208 21.643 56.07 21.659 ;
     RECT  34.74 21.397 35.586 21.667 ;
     RECT  34.74 21.667 36.126 21.677 ;
     RECT  13.68 21.631 16.938 21.691 ;
     RECT  42.804 21.569 45.558 21.691 ;
     RECT  56.844 21.643 57.114 21.691 ;
     RECT  57.852 21.595 57.942 21.691 ;
     RECT  56.844 21.691 57.942 21.695 ;
     RECT  47.916 21.533 49.374 21.725 ;
     RECT  57.024 21.695 57.942 21.739 ;
     RECT  58.716 21.541 62.442 21.739 ;
     RECT  20.412 21.541 25.038 21.776 ;
     RECT  3.816 21.389 4.626 21.803 ;
     RECT  31.716 21.361 33.75 21.803 ;
     RECT  35.244 21.677 36.126 21.803 ;
     RECT  67.644 21.461 72.846 21.811 ;
     RECT  50.112 21.533 51.21 21.883 ;
     RECT  53.208 21.659 55.926 21.883 ;
     RECT  42.768 21.691 45.558 21.917 ;
     RECT  30.78 21.163 30.906 21.928 ;
     RECT  31.716 21.803 33.714 21.928 ;
     RECT  3.816 21.803 4.302 21.929 ;
     RECT  6.84 21.497 9.27 21.929 ;
     RECT  12.564 21.497 12.582 21.929 ;
     RECT  47.916 21.725 49.302 21.929 ;
     RECT  52.884 21.883 55.926 21.929 ;
     RECT  57.024 21.739 62.442 21.929 ;
     RECT  18.324 21.389 19.494 21.931 ;
     RECT  29.34 21.299 29.358 21.931 ;
     RECT  37.332 21.395 41.202 21.937 ;
     RECT  59.655 21.929 62.442 21.937 ;
     RECT  0.036 20.429 3.042 21.973 ;
     RECT  64.188 21.119 65.61 21.973 ;
     RECT  13.68 21.691 17.118 22.001 ;
     RECT  59.655 21.937 62.838 22.001 ;
     RECT  66.708 21.461 66.906 22.001 ;
     RECT  64.188 21.973 65.862 22.009 ;
     RECT  64.188 22.009 65.934 22.027 ;
     RECT  66.708 22.001 66.834 22.027 ;
     RECT  57.024 21.929 58.914 22.037 ;
     RECT  10.26 21.569 11.43 22.061 ;
     RECT  12.636 21.979 12.654 22.081 ;
     RECT  13.68 22.001 13.698 22.081 ;
     RECT  6.84 21.929 8.838 22.109 ;
     RECT  57.024 22.037 58.806 22.109 ;
     RECT  50.112 21.883 51.246 22.123 ;
     RECT  18.216 21.931 19.494 22.171 ;
     RECT  20.412 21.776 23.418 22.171 ;
     RECT  64.188 22.027 66.834 22.171 ;
     RECT  6.84 22.109 8.766 22.199 ;
     RECT  10.26 22.061 11.394 22.199 ;
     RECT  36.972 21.937 41.202 22.199 ;
     RECT  50.112 22.123 51.426 22.199 ;
     RECT  12.636 22.081 13.698 22.205 ;
     RECT  14.832 22.001 17.118 22.219 ;
     RECT  18.216 22.171 23.418 22.219 ;
     RECT  14.832 22.219 23.418 22.235 ;
     RECT  50.184 22.199 51.426 22.235 ;
     RECT  59.655 22.001 60.102 22.235 ;
     RECT  60.948 22.001 62.838 22.235 ;
     RECT  63.648 22.171 66.834 22.235 ;
     RECT  26.172 21.631 27.63 22.243 ;
     RECT  29.088 21.931 29.358 22.243 ;
     RECT  30.78 21.928 33.714 22.243 ;
     RECT  50.688 22.235 51.426 22.243 ;
     RECT  61.812 22.235 62.838 22.243 ;
     RECT  29.088 22.243 33.714 22.315 ;
     RECT  50.688 22.243 51.534 22.316 ;
     RECT  67.644 21.811 72.918 22.343 ;
     RECT  5.655 21.497 6.102 22.351 ;
     RECT  6.84 22.199 8.55 22.351 ;
     RECT  10.26 22.199 10.278 22.351 ;
     RECT  67.644 22.343 67.698 22.351 ;
     RECT  67.608 22.351 67.698 22.379 ;
     RECT  52.884 21.929 55.566 22.411 ;
     RECT  36.972 22.199 40.554 22.441 ;
     RECT  46.764 21.629 46.962 22.441 ;
     RECT  26.172 22.243 27.702 22.459 ;
     RECT  28.656 22.315 33.714 22.459 ;
     RECT  26.172 22.459 33.714 22.505 ;
     RECT  36.828 22.441 40.554 22.505 ;
     RECT  57.096 22.109 58.806 22.505 ;
     RECT  60.948 22.235 61.074 22.505 ;
     RECT  24.156 21.776 25.038 22.513 ;
     RECT  26.172 22.505 31.734 22.513 ;
     RECT  68.94 22.343 72.918 22.513 ;
     RECT  24.156 22.513 31.734 22.541 ;
     RECT  58.356 22.505 58.806 22.547 ;
     RECT  35.244 21.803 36.054 22.549 ;
     RECT  52.776 22.411 55.566 22.549 ;
     RECT  58.428 22.547 58.806 22.577 ;
     RECT  5.655 22.351 8.55 22.613 ;
     RECT  52.74 22.549 55.566 22.621 ;
     RECT  34.488 22.045 34.506 22.637 ;
     RECT  5.655 22.613 5.994 22.649 ;
     RECT  20.7 22.235 23.418 22.699 ;
     RECT  24.156 22.541 27.774 22.699 ;
     RECT  6.804 22.613 8.55 22.739 ;
     RECT  14.832 22.235 19.566 22.739 ;
     RECT  20.7 22.699 27.774 22.739 ;
     RECT  37.62 22.505 40.554 22.739 ;
     RECT  42.804 21.917 45.558 22.747 ;
     RECT  12.744 22.205 13.698 22.775 ;
     RECT  20.7 22.739 23.31 22.775 ;
     RECT  28.584 22.541 31.734 22.775 ;
     RECT  37.62 22.739 40.446 22.775 ;
     RECT  63.9 22.235 66.834 22.775 ;
     RECT  9.756 22.351 10.278 22.783 ;
     RECT  35.244 22.549 36.81 22.783 ;
     RECT  11.055 22.199 11.394 22.795 ;
     RECT  32.508 22.505 33.714 22.819 ;
     RECT  42.696 22.747 45.558 22.819 ;
     RECT  47.916 21.929 49.194 22.819 ;
     RECT  52.416 22.621 55.566 22.919 ;
     RECT  5.655 22.649 5.937 22.981 ;
     RECT  11.055 22.795 11.934 22.981 ;
     RECT  12.744 22.775 13.374 22.981 ;
     RECT  46.656 22.441 46.962 22.981 ;
     RECT  47.916 22.819 49.23 22.981 ;
     RECT  58.5 22.577 58.806 22.981 ;
     RECT  59.655 22.235 59.937 22.981 ;
     RECT  0.036 21.973 3.762 23.009 ;
     RECT  32.508 22.819 33.822 23.009 ;
     RECT  37.62 22.775 40.338 23.009 ;
     RECT  42.48 22.819 45.558 23.017 ;
     RECT  54.144 22.919 55.566 23.035 ;
     RECT  29.448 22.775 30.006 23.045 ;
     RECT  37.62 23.009 40.302 23.045 ;
     RECT  41.832 23.017 45.774 23.08 ;
     RECT  46.656 22.981 49.23 23.08 ;
     RECT  0.036 23.009 3.69 23.117 ;
     RECT  29.52 23.045 30.006 23.117 ;
     RECT  50.688 22.316 51.498 23.125 ;
     RECT  52.416 22.919 53.298 23.125 ;
     RECT  58.5 22.981 59.937 23.125 ;
     RECT  60.876 22.819 60.894 23.125 ;
     RECT  0.036 23.117 3.618 23.153 ;
     RECT  50.688 23.125 53.298 23.165 ;
     RECT  0.036 23.153 3.546 23.189 ;
     RECT  54.144 23.035 55.926 23.251 ;
     RECT  58.5 23.125 60.894 23.275 ;
     RECT  61.812 22.243 62.946 23.275 ;
     RECT  11.055 22.981 13.374 23.279 ;
     RECT  20.7 22.775 20.934 23.279 ;
     RECT  41.832 23.08 49.23 23.279 ;
     RECT  50.688 23.165 51.462 23.279 ;
     RECT  58.5 23.275 62.946 23.279 ;
     RECT  63.9 22.775 66.798 23.279 ;
     RECT  20.7 23.279 20.754 23.315 ;
     RECT  60.876 23.279 62.946 23.323 ;
     RECT  42.588 23.279 49.23 23.351 ;
     RECT  50.688 23.279 51.246 23.351 ;
     RECT  41.616 23.287 41.634 23.357 ;
     RECT  46.044 23.351 49.23 23.357 ;
     RECT  32.655 23.009 33.822 23.359 ;
     RECT  57.096 22.505 57.582 23.359 ;
     RECT  58.5 23.279 60.03 23.359 ;
     RECT  35.136 22.783 36.81 23.395 ;
     RECT  37.62 23.045 39.366 23.395 ;
     RECT  5.148 22.981 5.937 23.405 ;
     RECT  11.055 23.279 11.574 23.405 ;
     RECT  57.096 23.359 60.03 23.419 ;
     RECT  63.972 23.279 66.798 23.423 ;
     RECT  9.684 22.783 10.278 23.431 ;
     RECT  11.055 23.405 11.466 23.431 ;
     RECT  9.684 23.431 11.466 23.459 ;
     RECT  21.672 22.775 23.31 23.521 ;
     RECT  14.832 22.739 19.494 23.549 ;
     RECT  42.588 23.351 45.162 23.549 ;
     RECT  64.044 23.423 66.798 23.549 ;
     RECT  10.296 23.459 11.466 23.555 ;
     RECT  56.988 23.419 60.03 23.585 ;
     RECT  64.116 23.549 66.798 23.585 ;
     RECT  5.655 23.405 5.937 23.611 ;
     RECT  64.188 23.585 66.798 23.621 ;
     RECT  54.144 23.251 56.25 23.629 ;
     RECT  56.988 23.585 58.878 23.629 ;
     RECT  10.512 23.555 11.466 23.645 ;
     RECT  35.136 23.395 39.366 23.659 ;
     RECT  10.584 23.645 11.466 23.693 ;
     RECT  66.132 23.621 66.798 23.693 ;
     RECT  17.928 23.549 19.494 23.701 ;
     RECT  20.304 23.593 20.322 23.701 ;
     RECT  24.516 22.739 27.63 23.701 ;
     RECT  28.584 22.775 28.638 23.701 ;
     RECT  50.688 23.351 51.174 23.701 ;
     RECT  66.708 23.693 66.798 23.701 ;
     RECT  21.672 23.521 23.382 23.755 ;
     RECT  24.516 23.701 28.638 23.755 ;
     RECT  52.524 23.165 53.298 23.755 ;
     RECT  54.144 23.629 58.878 23.755 ;
     RECT  21.672 23.755 28.638 23.791 ;
     RECT  10.584 23.693 11.43 23.819 ;
     RECT  17.928 23.701 20.322 23.819 ;
     RECT  29.664 23.117 30.006 23.827 ;
     RECT  30.744 22.775 31.734 23.827 ;
     RECT  67.608 22.379 67.662 23.827 ;
     RECT  21.672 23.791 28.89 23.851 ;
     RECT  29.664 23.827 31.734 23.851 ;
     RECT  46.116 23.357 49.23 23.851 ;
     RECT  5.655 23.611 5.958 23.885 ;
     RECT  17.928 23.819 20.178 23.885 ;
     RECT  52.524 23.755 58.878 23.885 ;
     RECT  46.116 23.851 49.914 23.891 ;
     RECT  50.652 23.701 51.174 23.891 ;
     RECT  34.884 23.659 39.366 23.899 ;
     RECT  32.655 23.359 33.93 23.935 ;
     RECT  34.776 23.899 39.366 23.935 ;
     RECT  40.104 23.045 40.302 23.935 ;
     RECT  21.672 23.851 31.734 23.971 ;
     RECT  32.655 23.935 40.734 23.971 ;
     RECT  6.84 22.739 8.478 23.981 ;
     RECT  14.832 23.549 17.046 24.043 ;
     RECT  59.616 23.585 60.03 24.043 ;
     RECT  60.876 23.323 63.198 24.043 ;
     RECT  67.608 23.827 67.842 24.061 ;
     RECT  68.94 22.513 72.954 24.061 ;
     RECT  7.74 23.981 8.478 24.089 ;
     RECT  12.744 23.279 13.374 24.089 ;
     RECT  21.672 23.971 40.734 24.089 ;
     RECT  46.116 23.891 49.41 24.089 ;
     RECT  59.616 24.043 63.198 24.089 ;
     RECT  21.672 24.089 40.302 24.125 ;
     RECT  14.256 24.043 17.046 24.133 ;
     RECT  46.116 24.089 49.137 24.133 ;
     RECT  0.036 23.189 3.474 24.169 ;
     RECT  14.184 24.133 17.046 24.169 ;
     RECT  9.036 24.097 9.198 24.197 ;
     RECT  14.112 24.169 17.046 24.205 ;
     RECT  7.74 24.089 7.758 24.221 ;
     RECT  34.776 24.125 40.302 24.233 ;
     RECT  50.724 23.891 51.174 24.241 ;
     RECT  6.84 23.981 6.93 24.269 ;
     RECT  9.036 24.197 9.126 24.269 ;
     RECT  34.776 24.233 40.23 24.269 ;
     RECT  21.672 24.125 33.678 24.317 ;
     RECT  34.776 24.269 40.122 24.317 ;
     RECT  50.724 24.241 51.822 24.317 ;
     RECT  13.824 24.205 17.046 24.331 ;
     RECT  17.928 23.885 20.106 24.331 ;
     RECT  42.624 23.549 45.162 24.331 ;
     RECT  10.584 23.819 11.394 24.359 ;
     RECT  36.504 24.317 40.122 24.359 ;
     RECT  13.824 24.331 20.106 24.365 ;
     RECT  0.036 24.169 3.51 24.367 ;
     RECT  21.672 24.317 31.734 24.395 ;
     RECT  36.504 24.359 39.366 24.413 ;
     RECT  42.192 24.331 45.162 24.413 ;
     RECT  52.668 23.885 58.878 24.413 ;
     RECT  43.416 24.413 45.162 24.431 ;
     RECT  12.744 24.089 12.834 24.467 ;
     RECT  25.308 24.395 31.734 24.467 ;
     RECT  34.776 24.317 35.586 24.467 ;
     RECT  12.744 24.467 12.798 24.475 ;
     RECT  43.455 24.431 45.162 24.475 ;
     RECT  45.972 24.133 49.137 24.475 ;
     RECT  0.036 24.367 3.654 24.503 ;
     RECT  6.84 24.269 6.858 24.503 ;
     RECT  64.188 23.621 65.337 24.511 ;
     RECT  66.708 23.701 66.87 24.511 ;
     RECT  67.608 24.061 72.954 24.511 ;
     RECT  43.455 24.475 49.137 24.629 ;
     RECT  21.672 24.395 24.534 24.673 ;
     RECT  37.404 24.413 39.366 24.737 ;
     RECT  64.188 24.511 65.646 24.745 ;
     RECT  50.724 24.317 51.786 24.749 ;
     RECT  50.724 24.749 50.994 24.773 ;
     RECT  20.988 24.673 24.534 24.781 ;
     RECT  47.592 24.629 49.137 24.797 ;
     RECT  56.628 24.413 58.878 24.797 ;
     RECT  36.504 24.413 36.522 24.809 ;
     RECT  63.972 24.745 65.754 24.871 ;
     RECT  20.916 24.781 24.534 24.899 ;
     RECT  32.544 24.317 33.678 24.935 ;
     RECT  52.668 24.413 55.638 24.935 ;
     RECT  63.972 24.871 65.79 24.935 ;
     RECT  26.784 24.467 31.734 24.941 ;
     RECT  37.836 24.737 39.366 24.971 ;
     RECT  54.255 24.935 55.638 25.043 ;
     RECT  0.036 24.503 3.51 25.079 ;
     RECT  60.876 24.089 63.198 25.079 ;
     RECT  13.86 24.365 20.106 25.088 ;
     RECT  13.86 25.088 18.99 25.141 ;
     RECT  32.655 24.935 33.678 25.141 ;
     RECT  34.776 24.467 34.794 25.141 ;
     RECT  13.608 25.141 18.99 25.169 ;
     RECT  62.208 25.079 63.198 25.169 ;
     RECT  65.016 24.935 65.79 25.169 ;
     RECT  59.655 24.089 60.066 25.177 ;
     RECT  60.876 25.079 60.894 25.177 ;
     RECT  62.604 25.169 63.198 25.177 ;
     RECT  13.608 25.169 16.938 25.181 ;
     RECT  43.455 24.629 46.818 25.205 ;
     RECT  19.872 25.088 20.106 25.249 ;
     RECT  20.916 24.899 24.174 25.249 ;
     RECT  25.308 24.467 25.722 25.321 ;
     RECT  26.784 24.941 28.134 25.321 ;
     RECT  43.455 25.205 45.702 25.321 ;
     RECT  48.132 24.797 49.137 25.321 ;
     RECT  14.04 25.181 16.938 25.349 ;
     RECT  32.655 25.141 34.794 25.349 ;
     RECT  62.604 25.177 63.234 25.373 ;
     RECT  29.088 24.941 31.734 25.411 ;
     RECT  46.656 25.205 46.818 25.411 ;
     RECT  17.784 25.169 18.99 25.439 ;
     RECT  19.872 25.249 24.174 25.439 ;
     RECT  20.196 25.439 24.174 25.475 ;
     RECT  25.308 25.321 28.134 25.475 ;
     RECT  25.308 25.475 27.846 25.483 ;
     RECT  59.655 25.177 60.894 25.511 ;
     RECT  29.088 25.411 31.77 25.547 ;
     RECT  14.04 25.349 16.866 25.565 ;
     RECT  12.24 24.475 12.798 25.583 ;
     RECT  59.655 25.511 60.066 25.661 ;
     RECT  21.132 25.475 24.174 25.675 ;
     RECT  25.092 25.483 27.846 25.675 ;
     RECT  52.668 24.935 53.406 25.681 ;
     RECT  54.255 25.043 55.566 25.681 ;
     RECT  62.748 25.373 63.234 25.681 ;
     RECT  63.972 24.935 64.242 25.681 ;
     RECT  8.1 25.672 8.118 25.709 ;
     RECT  9.036 24.269 9.054 25.709 ;
     RECT  52.668 25.681 55.566 25.709 ;
     RECT  42.192 24.413 42.21 25.717 ;
     RECT  48.132 25.321 49.302 25.717 ;
     RECT  6.804 25.717 6.822 25.789 ;
     RECT  36.036 25.411 36.054 25.789 ;
     RECT  37.08 25.141 37.098 25.789 ;
     RECT  41.184 24.097 41.202 25.789 ;
     RECT  48.132 25.717 49.482 25.789 ;
     RECT  8.28 25.771 8.298 25.817 ;
     RECT  42.192 25.717 42.426 25.825 ;
     RECT  43.272 25.321 45.702 25.825 ;
     RECT  36.036 25.789 37.098 25.861 ;
     RECT  48.132 25.789 49.59 25.861 ;
     RECT  57.204 24.797 58.878 25.861 ;
     RECT  59.655 25.661 59.994 25.861 ;
     RECT  51.768 24.749 51.786 25.915 ;
     RECT  52.668 25.709 55.278 25.915 ;
     RECT  62.748 25.681 64.242 25.951 ;
     RECT  29.088 25.547 31.698 25.963 ;
     RECT  9.072 25.789 9.09 25.979 ;
     RECT  21.132 25.675 27.846 25.979 ;
     RECT  51.768 25.915 55.278 25.979 ;
     RECT  34.164 25.349 34.794 25.987 ;
     RECT  35.568 25.861 37.098 25.987 ;
     RECT  29.016 25.963 31.698 26.015 ;
     RECT  6.732 25.789 6.858 26.051 ;
     RECT  21.132 25.979 27.774 26.093 ;
     RECT  47.808 25.861 49.59 26.123 ;
     RECT  62.748 25.951 64.278 26.123 ;
     RECT  32.655 25.349 33.102 26.131 ;
     RECT  47.808 26.123 49.482 26.159 ;
     RECT  51.768 25.979 51.858 26.159 ;
     RECT  26.136 26.093 27.774 26.189 ;
     RECT  17.928 25.439 18.99 26.203 ;
     RECT  20.196 25.475 20.286 26.203 ;
     RECT  57.204 25.861 59.994 26.203 ;
     RECT  64.08 26.123 64.278 26.203 ;
     RECT  65.016 25.169 65.718 26.203 ;
     RECT  42.192 25.825 45.702 26.221 ;
     RECT  32.655 26.131 33.138 26.248 ;
     RECT  14.04 25.565 16.737 26.249 ;
     RECT  17.928 26.203 20.286 26.249 ;
     RECT  29.664 26.015 31.698 26.249 ;
     RECT  34.164 25.987 37.098 26.249 ;
     RECT  66.708 24.511 72.954 26.249 ;
     RECT  0.036 25.079 3.438 26.251 ;
     RECT  4.248 25.681 4.266 26.251 ;
     RECT  17.928 26.249 19.71 26.251 ;
     RECT  50.904 24.773 50.994 26.251 ;
     RECT  10.584 24.359 11.337 26.257 ;
     RECT  37.872 24.971 39.366 26.257 ;
     RECT  57.024 26.203 59.994 26.257 ;
     RECT  21.132 26.093 25.11 26.285 ;
     RECT  32.655 26.248 33.174 26.293 ;
     RECT  42.048 26.221 45.702 26.293 ;
     RECT  21.132 26.285 24.21 26.329 ;
     RECT  30.78 26.249 31.698 26.329 ;
     RECT  32.544 26.293 33.174 26.329 ;
     RECT  50.832 26.251 50.994 26.329 ;
     RECT  51.768 26.159 51.786 26.329 ;
     RECT  28.764 26.203 28.782 26.347 ;
     RECT  29.664 26.249 29.682 26.357 ;
     RECT  12.78 25.583 12.798 26.365 ;
     RECT  37.836 26.257 39.366 26.365 ;
     RECT  28.656 26.347 28.782 26.381 ;
     RECT  12.78 26.365 13.122 26.392 ;
     RECT  17.856 26.251 19.71 26.393 ;
     RECT  34.164 26.249 36.954 26.393 ;
     RECT  40.968 25.789 41.202 26.401 ;
     RECT  41.94 26.293 45.702 26.401 ;
     RECT  62.748 26.123 63.162 26.401 ;
     RECT  12.78 26.392 13.338 26.429 ;
     RECT  30.78 26.329 33.174 26.429 ;
     RECT  5.655 23.885 5.937 26.443 ;
     RECT  37.692 26.365 39.366 26.491 ;
     RECT  40.968 26.401 45.918 26.491 ;
     RECT  66.708 26.249 72.738 26.491 ;
     RECT  17.856 26.393 19.098 26.519 ;
     RECT  34.164 26.393 36.918 26.519 ;
     RECT  40.896 26.491 45.918 26.519 ;
     RECT  46.656 25.411 47.07 26.519 ;
     RECT  50.832 26.329 51.786 26.519 ;
     RECT  52.956 25.979 55.278 26.527 ;
     RECT  37.692 26.491 39.978 26.539 ;
     RECT  40.896 26.519 40.986 26.539 ;
     RECT  33.948 26.527 33.966 26.573 ;
     RECT  37.692 26.539 40.986 26.573 ;
     RECT  6.84 26.051 6.858 26.587 ;
     RECT  10.584 26.257 11.502 26.587 ;
     RECT  28.656 26.381 28.674 26.587 ;
     RECT  14.076 26.249 16.737 26.591 ;
     RECT  32.436 26.429 33.174 26.591 ;
     RECT  41.724 26.519 45.918 26.591 ;
     RECT  41.94 26.591 45.918 26.599 ;
     RECT  46.656 26.519 46.962 26.599 ;
     RECT  28.548 26.587 28.674 26.621 ;
     RECT  16.128 26.591 16.737 26.627 ;
     RECT  18.576 26.519 19.098 26.627 ;
     RECT  41.94 26.599 46.962 26.627 ;
     RECT  56.7 26.257 59.994 26.627 ;
     RECT  16.2 26.627 16.737 26.635 ;
     RECT  52.956 26.527 55.71 26.635 ;
     RECT  56.7 26.627 59.937 26.635 ;
     RECT  62.712 26.401 63.162 26.635 ;
     RECT  18.576 26.627 18.99 26.636 ;
     RECT  40.536 26.573 40.986 26.669 ;
     RECT  47.808 26.159 49.374 26.671 ;
     RECT  18.612 26.636 18.99 26.699 ;
     RECT  52.956 26.635 59.937 26.699 ;
     RECT  10.584 26.587 11.538 26.717 ;
     RECT  14.076 26.591 14.958 26.717 ;
     RECT  5.148 26.443 5.937 26.731 ;
     RECT  60.876 25.511 60.894 26.731 ;
     RECT  10.584 26.717 11.502 26.761 ;
     RECT  40.644 26.669 40.986 26.765 ;
     RECT  9.972 26.761 11.502 26.789 ;
     RECT  16.2 26.635 16.902 26.789 ;
     RECT  30.78 26.429 31.698 26.789 ;
     RECT  34.776 26.519 36.918 26.789 ;
     RECT  37.692 26.573 39.474 26.789 ;
     RECT  42.192 26.627 46.962 26.789 ;
     RECT  47.772 26.671 49.374 26.789 ;
     RECT  60.696 26.731 60.894 26.789 ;
     RECT  64.08 26.203 65.718 26.789 ;
     RECT  66.672 26.491 72.738 26.861 ;
     RECT  64.296 26.789 65.718 26.905 ;
     RECT  34.776 26.789 36.306 26.933 ;
     RECT  47.772 26.789 49.302 26.933 ;
     RECT  26.136 26.189 27.63 26.941 ;
     RECT  28.548 26.621 28.566 26.941 ;
     RECT  42.192 26.789 46.71 26.969 ;
     RECT  62.424 26.635 63.162 26.971 ;
     RECT  5.148 26.731 6.102 27.031 ;
     RECT  6.84 26.587 7.002 27.031 ;
     RECT  26.136 26.941 28.566 27.059 ;
     RECT  31.536 26.789 31.698 27.059 ;
     RECT  34.776 26.933 34.794 27.059 ;
     RECT  52.956 26.699 55.026 27.059 ;
     RECT  62.424 26.971 63.27 27.059 ;
     RECT  20.556 26.329 24.21 27.067 ;
     RECT  25.092 26.285 25.11 27.067 ;
     RECT  5.148 27.031 7.002 27.095 ;
     RECT  14.076 26.717 14.922 27.095 ;
     RECT  31.536 27.059 31.554 27.095 ;
     RECT  9.972 26.789 11.337 27.103 ;
     RECT  16.455 26.789 16.902 27.103 ;
     RECT  17.64 26.527 17.73 27.103 ;
     RECT  62.424 27.059 62.73 27.103 ;
     RECT  5.655 27.095 7.002 27.131 ;
     RECT  55.764 26.699 59.937 27.131 ;
     RECT  51.3 26.519 51.786 27.163 ;
     RECT  6.732 27.131 7.002 27.175 ;
     RECT  16.455 27.103 17.73 27.197 ;
     RECT  62.064 27.103 62.73 27.203 ;
     RECT  20.556 27.067 25.11 27.211 ;
     RECT  51.3 27.163 52.218 27.211 ;
     RECT  52.956 27.059 54.954 27.211 ;
     RECT  64.296 26.905 65.898 27.211 ;
     RECT  66.672 26.861 72.702 27.211 ;
     RECT  20.556 27.211 25.146 27.239 ;
     RECT  26.244 27.059 28.566 27.239 ;
     RECT  27.108 27.239 28.566 27.245 ;
     RECT  21.06 27.239 25.146 27.329 ;
     RECT  32.436 26.591 33.102 27.329 ;
     RECT  51.3 27.211 54.954 27.329 ;
     RECT  64.296 27.211 72.702 27.329 ;
     RECT  55.8 27.131 59.937 27.365 ;
     RECT  18.612 26.699 18.918 27.373 ;
     RECT  37.692 26.789 39.402 27.409 ;
     RECT  32.616 27.329 33.102 27.499 ;
     RECT  18.504 27.373 18.918 27.509 ;
     RECT  21.348 27.329 25.11 27.509 ;
     RECT  9.324 27.103 11.337 27.595 ;
     RECT  18.504 27.509 18.846 27.599 ;
     RECT  56.016 27.365 59.937 27.599 ;
     RECT  6.732 27.175 7.65 27.607 ;
     RECT  37.296 27.409 39.402 27.635 ;
     RECT  37.476 27.635 39.402 27.643 ;
     RECT  9.324 27.595 11.754 27.679 ;
     RECT  37.476 27.643 39.834 27.68 ;
     RECT  42.408 26.969 46.71 27.739 ;
     RECT  6.732 27.607 8.298 27.751 ;
     RECT  9.252 27.679 11.754 27.751 ;
     RECT  12.78 26.429 12.798 27.751 ;
     RECT  21.348 27.509 25.038 27.773 ;
     RECT  0.036 26.251 4.266 27.779 ;
     RECT  56.016 27.599 56.178 27.821 ;
     RECT  6.732 27.751 11.754 27.841 ;
     RECT  12.708 27.751 12.798 27.841 ;
     RECT  27.144 27.245 28.566 27.841 ;
     RECT  29.664 27.139 29.682 27.841 ;
     RECT  23.616 27.773 25.038 27.869 ;
     RECT  37.476 27.68 39.402 27.869 ;
     RECT  57.024 27.599 59.937 27.869 ;
     RECT  32.616 27.499 33.606 27.875 ;
     RECT  67.824 27.329 72.702 27.877 ;
     RECT  27.144 27.841 29.682 27.905 ;
     RECT  6.732 27.841 12.798 27.931 ;
     RECT  42.408 27.739 46.818 27.979 ;
     RECT  47.772 26.933 47.79 27.979 ;
     RECT  16.455 27.197 17.55 27.985 ;
     RECT  62.064 27.203 62.442 27.985 ;
     RECT  21.348 27.773 22.878 28.013 ;
     RECT  26.244 27.239 26.262 28.021 ;
     RECT  64.296 27.329 67.086 28.021 ;
     RECT  14.328 27.095 14.922 28.111 ;
     RECT  42.408 27.979 47.79 28.111 ;
     RECT  48.6 26.933 49.302 28.111 ;
     RECT  62.028 27.985 62.442 28.111 ;
     RECT  63.9 28.021 67.086 28.111 ;
     RECT  21.564 28.013 22.878 28.139 ;
     RECT  63.576 28.111 67.086 28.139 ;
     RECT  65.055 28.139 67.086 28.211 ;
     RECT  16.455 27.985 17.766 28.219 ;
     RECT  66.672 28.211 67.086 28.219 ;
     RECT  67.824 27.877 72.774 28.219 ;
     RECT  51.696 27.329 54.954 28.255 ;
     RECT  51.372 28.255 54.954 28.291 ;
     RECT  56.016 27.821 56.142 28.291 ;
     RECT  62.028 28.111 62.766 28.291 ;
     RECT  25.992 28.021 26.262 28.381 ;
     RECT  27.144 27.905 28.062 28.381 ;
     RECT  62.028 28.291 62.838 28.408 ;
     RECT  63.576 28.139 64.314 28.408 ;
     RECT  0.036 27.779 3.402 28.409 ;
     RECT  42.408 28.111 49.302 28.409 ;
     RECT  0.036 28.409 3.114 28.445 ;
     RECT  6.732 27.931 13.086 28.445 ;
     RECT  25.992 28.381 28.062 28.453 ;
     RECT  62.028 28.408 64.314 28.453 ;
     RECT  46.152 28.409 46.854 28.481 ;
     RECT  61.848 28.453 64.314 28.481 ;
     RECT  66.672 28.219 72.774 28.481 ;
     RECT  5.655 27.131 5.937 28.489 ;
     RECT  6.732 28.445 8.658 28.489 ;
     RECT  10.224 28.445 13.086 28.489 ;
     RECT  19.944 27.913 19.962 28.489 ;
     RECT  32.655 27.875 33.606 28.489 ;
     RECT  34.812 28.459 34.83 28.489 ;
     RECT  35.712 26.933 36.306 28.489 ;
     RECT  25.776 28.453 28.062 28.493 ;
     RECT  14.328 28.111 15.174 28.507 ;
     RECT  16.128 28.219 17.766 28.507 ;
     RECT  30.78 26.789 30.798 28.507 ;
     RECT  61.848 28.481 62.694 28.507 ;
     RECT  18.504 27.599 18.522 28.525 ;
     RECT  32.655 28.489 33.786 28.525 ;
     RECT  30.78 28.507 31.41 28.552 ;
     RECT  68.652 28.481 72.774 28.553 ;
     RECT  19.944 28.489 20.07 28.561 ;
     RECT  40.968 26.765 40.986 28.561 ;
     RECT  29.052 27.905 29.682 28.589 ;
     RECT  65.055 28.211 65.718 28.589 ;
     RECT  47.772 28.409 49.302 28.603 ;
     RECT  50.292 28.507 50.31 28.603 ;
     RECT  14.22 28.507 17.766 28.651 ;
     RECT  18.504 28.525 18.882 28.651 ;
     RECT  30.78 28.552 31.806 28.651 ;
     RECT  32.655 28.525 33.822 28.651 ;
     RECT  23.616 27.869 24.534 28.679 ;
     RECT  29.052 28.589 29.322 28.679 ;
     RECT  47.772 28.603 50.31 28.679 ;
     RECT  63.576 28.481 64.314 28.679 ;
     RECT  40.428 28.561 40.986 28.687 ;
     RECT  14.22 28.651 18.882 28.715 ;
     RECT  21.855 28.139 22.878 28.723 ;
     RECT  23.616 28.679 24.03 28.723 ;
     RECT  19.944 28.561 20.466 28.751 ;
     RECT  66.672 28.481 67.878 28.751 ;
     RECT  16.272 28.715 18.882 28.759 ;
     RECT  24.948 28.723 24.966 28.759 ;
     RECT  30.78 28.651 33.822 28.787 ;
     RECT  68.652 28.553 72.738 28.787 ;
     RECT  20.232 28.751 20.466 28.795 ;
     RECT  63.576 28.679 63.954 28.823 ;
     RECT  16.272 28.759 18.918 28.831 ;
     RECT  30.78 28.787 33.606 28.831 ;
     RECT  34.812 28.489 36.306 28.831 ;
     RECT  38.055 27.869 39.402 28.831 ;
     RECT  40.212 28.687 40.986 28.831 ;
     RECT  24.948 28.759 25.002 28.859 ;
     RECT  30.204 28.831 33.606 28.859 ;
     RECT  51.372 28.291 56.142 28.859 ;
     RECT  20.232 28.795 21.114 28.921 ;
     RECT  21.855 28.723 24.03 28.921 ;
     RECT  38.055 28.831 41.238 28.921 ;
     RECT  10.224 28.489 13.374 28.949 ;
     RECT  20.232 28.921 24.03 28.949 ;
     RECT  31.788 28.859 33.606 28.949 ;
     RECT  61.74 28.507 62.694 28.949 ;
     RECT  16.272 28.831 18.99 28.984 ;
     RECT  63.576 28.823 63.882 28.985 ;
     RECT  60.984 28.291 61.002 28.993 ;
     RECT  16.272 28.984 19.314 29.021 ;
     RECT  24.948 28.859 24.966 29.021 ;
     RECT  31.824 28.949 33.606 29.021 ;
     RECT  66.708 28.751 67.878 29.021 ;
     RECT  10.224 28.949 13.122 29.057 ;
     RECT  14.22 28.715 15.03 29.057 ;
     RECT  30.204 28.859 30.87 29.057 ;
     RECT  34.776 28.831 36.306 29.057 ;
     RECT  38.016 28.921 41.238 29.069 ;
     RECT  65.055 28.589 65.61 29.069 ;
     RECT  68.724 28.787 72.738 29.069 ;
     RECT  65.055 29.069 65.574 29.083 ;
     RECT  31.896 29.021 33.606 29.093 ;
     RECT  42.408 28.409 45.018 29.093 ;
     RECT  20.232 28.949 23.994 29.117 ;
     RECT  32.436 29.093 33.606 29.117 ;
     RECT  51.372 28.859 52.182 29.129 ;
     RECT  5.655 28.489 8.658 29.179 ;
     RECT  10.224 29.057 11.97 29.179 ;
     RECT  60.984 28.993 61.578 29.179 ;
     RECT  51.372 29.129 51.714 29.191 ;
     RECT  16.455 29.021 19.314 29.219 ;
     RECT  29.268 28.679 29.322 29.219 ;
     RECT  47.772 28.679 49.59 29.219 ;
     RECT  52.956 28.859 56.142 29.219 ;
     RECT  69.048 29.069 72.738 29.219 ;
     RECT  0.036 28.445 2.97 29.227 ;
     RECT  37.188 29.065 37.206 29.227 ;
     RECT  38.016 29.069 41.022 29.227 ;
     RECT  35.244 29.057 36.306 29.255 ;
     RECT  16.455 29.219 17.334 29.261 ;
     RECT  48.855 29.219 49.59 29.261 ;
     RECT  14.868 29.057 15.03 29.291 ;
     RECT  18.108 29.219 19.314 29.291 ;
     RECT  48.855 29.261 49.302 29.291 ;
     RECT  0.036 29.227 3.006 29.299 ;
     RECT  10.152 29.179 11.97 29.299 ;
     RECT  50.976 29.191 51.714 29.309 ;
     RECT  62.388 28.949 62.694 29.323 ;
     RECT  5.655 29.179 8.73 29.335 ;
     RECT  37.188 29.227 41.022 29.357 ;
     RECT  30.204 29.057 30.762 29.365 ;
     RECT  9.576 29.299 11.97 29.371 ;
     RECT  57.42 27.869 59.937 29.371 ;
     RECT  60.948 29.179 61.578 29.371 ;
     RECT  29.808 29.365 30.762 29.405 ;
     RECT  5.655 29.335 8.802 29.489 ;
     RECT  62.388 29.323 62.766 29.489 ;
     RECT  9.54 29.371 11.97 29.501 ;
     RECT  51.516 29.309 51.714 29.501 ;
     RECT  46.152 28.481 46.818 29.515 ;
     RECT  16.455 29.261 17.118 29.525 ;
     RECT  63.828 28.985 63.882 29.56 ;
     RECT  45.972 29.515 46.818 29.561 ;
     RECT  47.772 29.219 48.042 29.561 ;
     RECT  18.612 29.291 19.314 29.569 ;
     RECT  9.54 29.501 11.394 29.597 ;
     RECT  66.708 29.021 67.302 29.597 ;
     RECT  52.956 29.219 54.702 29.605 ;
     RECT  63.828 29.56 64.026 29.605 ;
     RECT  64.944 29.083 65.574 29.605 ;
     RECT  5.655 29.489 8.658 29.633 ;
     RECT  4.248 27.779 4.266 29.645 ;
     RECT  55.872 29.219 56.142 29.659 ;
     RECT  62.388 29.489 62.442 29.669 ;
     RECT  42.408 29.093 42.714 29.707 ;
     RECT  63.828 29.605 65.574 29.707 ;
     RECT  20.7 29.117 23.994 29.731 ;
     RECT  26.244 28.493 28.062 29.731 ;
     RECT  26.172 29.731 28.062 29.755 ;
     RECT  46.152 29.561 46.818 29.755 ;
     RECT  55.872 29.659 56.538 29.755 ;
     RECT  57.42 29.371 61.578 29.755 ;
     RECT  42.228 29.707 42.714 29.759 ;
     RECT  46.152 29.755 46.854 29.759 ;
     RECT  55.872 29.755 61.578 29.759 ;
     RECT  63.648 29.707 65.574 29.759 ;
     RECT  20.7 29.731 24.138 29.795 ;
     RECT  51.66 29.501 51.714 29.795 ;
     RECT  55.872 29.759 57.222 29.795 ;
     RECT  21.096 29.795 24.138 29.903 ;
     RECT  21.132 29.903 24.138 29.911 ;
     RECT  42.48 29.759 42.714 29.911 ;
     RECT  43.455 29.093 44.01 29.911 ;
     RECT  46.188 29.759 46.854 29.911 ;
     RECT  52.452 29.605 54.702 29.911 ;
     RECT  59.655 29.759 61.578 29.911 ;
     RECT  62.388 29.669 62.406 29.911 ;
     RECT  21.132 29.911 24.714 29.992 ;
     RECT  25.884 29.755 28.062 29.992 ;
     RECT  13.86 29.227 13.878 30.029 ;
     RECT  35.244 29.255 35.442 30.029 ;
     RECT  37.332 29.357 41.022 30.029 ;
     RECT  59.655 29.911 62.406 30.029 ;
     RECT  21.132 29.992 28.062 30.035 ;
     RECT  51.912 29.911 54.702 30.077 ;
     RECT  15.12 29.731 15.462 30.091 ;
     RECT  14.796 30.091 15.462 30.109 ;
     RECT  16.455 29.525 17.01 30.109 ;
     RECT  18.612 29.569 19.35 30.109 ;
     RECT  13.104 29.057 13.122 30.136 ;
     RECT  14.796 30.109 17.01 30.136 ;
     RECT  32.472 29.117 33.606 30.136 ;
     RECT  32.472 30.136 34.326 30.139 ;
     RECT  13.104 30.136 13.662 30.173 ;
     RECT  32.472 30.139 35.046 30.173 ;
     RECT  34.596 30.173 35.046 30.179 ;
     RECT  51.984 30.077 54.702 30.181 ;
     RECT  55.872 29.795 56.61 30.181 ;
     RECT  37.584 30.029 41.022 30.221 ;
     RECT  36.432 30.181 36.45 30.235 ;
     RECT  7.92 29.633 8.658 30.271 ;
     RECT  10.116 29.597 11.394 30.271 ;
     RECT  31.284 29.875 31.302 30.271 ;
     RECT  21.132 30.035 25.11 30.299 ;
     RECT  30.204 29.405 30.222 30.299 ;
     RECT  35.856 30.235 36.45 30.299 ;
     RECT  42.48 29.911 44.01 30.299 ;
     RECT  51.984 30.181 56.61 30.299 ;
     RECT  66.708 29.597 66.834 30.299 ;
     RECT  31.284 30.271 31.482 30.307 ;
     RECT  32.472 30.173 33.714 30.307 ;
     RECT  46.188 29.911 46.962 30.307 ;
     RECT  47.772 29.561 47.934 30.307 ;
     RECT  13.104 30.173 13.122 30.335 ;
     RECT  51.984 30.299 52.758 30.335 ;
     RECT  7.92 30.271 9.198 30.343 ;
     RECT  20.268 30.331 20.286 30.371 ;
     RECT  38.055 30.221 41.022 30.371 ;
     RECT  5.655 29.633 7.038 30.373 ;
     RECT  7.92 30.343 9.306 30.373 ;
     RECT  40.392 30.371 41.022 30.379 ;
     RECT  48.855 29.291 49.137 30.379 ;
     RECT  32.364 30.307 33.714 30.407 ;
     RECT  40.392 30.379 41.238 30.416 ;
     RECT  14.652 30.136 17.01 30.427 ;
     RECT  30.744 30.307 31.482 30.451 ;
     RECT  32.364 30.407 33.642 30.451 ;
     RECT  45 29.093 45.018 30.451 ;
     RECT  48.855 30.379 49.374 30.451 ;
     RECT  69.048 29.219 72.702 30.451 ;
     RECT  21.855 30.299 25.11 30.479 ;
     RECT  30.744 30.451 33.642 30.509 ;
     RECT  58.14 29.759 58.914 30.541 ;
     RECT  59.655 30.029 61.038 30.541 ;
     RECT  61.848 30.029 62.406 30.541 ;
     RECT  30.744 30.509 31.59 30.569 ;
     RECT  34.596 30.179 34.794 30.569 ;
     RECT  46.188 30.307 47.934 30.569 ;
     RECT  53.676 30.299 56.61 30.569 ;
     RECT  64.656 29.759 65.574 30.569 ;
     RECT  40.392 30.416 41.022 30.605 ;
     RECT  38.055 30.371 39.618 30.611 ;
     RECT  26.28 30.035 28.062 30.613 ;
     RECT  28.8 30.181 28.818 30.613 ;
     RECT  67.608 30.541 67.626 30.613 ;
     RECT  5.655 30.373 9.306 30.641 ;
     RECT  36.036 30.299 36.45 30.641 ;
     RECT  9.288 30.641 9.306 30.677 ;
     RECT  26.28 30.613 28.818 30.713 ;
     RECT  30.744 30.569 31.122 30.713 ;
     RECT  51.984 30.335 52.614 30.713 ;
     RECT  67.608 30.613 68.094 30.713 ;
     RECT  45 30.451 45.054 30.715 ;
     RECT  55.872 30.569 56.61 30.721 ;
     RECT  51.984 30.713 52.47 30.749 ;
     RECT  67.608 30.713 68.022 30.749 ;
     RECT  44.82 30.715 45.774 30.755 ;
     RECT  23.94 30.479 25.11 30.811 ;
     RECT  42.48 30.299 43.902 30.811 ;
     RECT  48.855 30.451 49.662 30.811 ;
     RECT  66.708 30.299 66.798 30.811 ;
     RECT  67.608 30.749 67.986 30.811 ;
     RECT  10.116 30.271 11.826 30.839 ;
     RECT  14.616 30.427 17.01 30.839 ;
     RECT  28.8 30.713 28.818 30.839 ;
     RECT  40.464 30.605 41.022 30.839 ;
     RECT  58.14 30.541 61.038 30.839 ;
     RECT  14.616 30.839 16.83 30.845 ;
     RECT  18.324 30.109 19.35 30.847 ;
     RECT  61.848 30.541 62.658 30.847 ;
     RECT  18.252 30.847 19.35 30.883 ;
     RECT  26.28 30.713 28.062 30.893 ;
     RECT  64.656 30.569 65.337 30.907 ;
     RECT  40.5 30.839 41.022 30.911 ;
     RECT  66.204 30.811 66.798 30.911 ;
     RECT  38.055 30.611 38.97 30.955 ;
     RECT  18.252 30.883 19.782 30.991 ;
     RECT  29.088 30.847 29.178 30.991 ;
     RECT  42.408 30.811 43.902 30.991 ;
     RECT  58.176 30.839 61.038 30.991 ;
     RECT  61.848 30.847 62.73 30.991 ;
     RECT  10.584 30.839 11.826 31.019 ;
     RECT  17.784 30.991 19.782 31.037 ;
     RECT  0.036 29.299 3.078 31.081 ;
     RECT  29.088 30.991 29.574 31.081 ;
     RECT  66.492 30.911 66.798 31.081 ;
     RECT  67.536 30.811 67.986 31.081 ;
     RECT  5.655 30.641 8.514 31.085 ;
     RECT  10.656 31.019 11.826 31.099 ;
     RECT  12.564 30.991 12.582 31.099 ;
     RECT  14.616 30.845 16.737 31.145 ;
     RECT  17.784 31.037 18.954 31.145 ;
     RECT  10.656 31.099 12.582 31.153 ;
     RECT  0.036 31.081 3.402 31.181 ;
     RECT  14.616 31.145 15.426 31.181 ;
     RECT  19.692 31.037 19.782 31.181 ;
     RECT  42.192 30.991 43.902 31.181 ;
     RECT  68.976 30.451 72.702 31.181 ;
     RECT  10.656 31.153 12.618 31.217 ;
     RECT  30.744 30.713 30.798 31.217 ;
     RECT  26.28 30.893 28.026 31.225 ;
     RECT  66.492 31.081 67.986 31.229 ;
     RECT  23.94 30.811 25.146 31.243 ;
     RECT  26.172 31.225 28.026 31.243 ;
     RECT  19.728 31.181 19.782 31.261 ;
     RECT  21.855 30.479 22.914 31.261 ;
     RECT  23.94 31.243 28.026 31.261 ;
     RECT  55.872 30.721 56.718 31.261 ;
     RECT  64.332 30.907 65.337 31.261 ;
     RECT  4.536 31.225 4.554 31.277 ;
     RECT  21.024 31.243 21.042 31.289 ;
     RECT  21.855 31.261 28.026 31.289 ;
     RECT  17.784 31.145 18.702 31.325 ;
     RECT  46.764 30.569 47.934 31.339 ;
     RECT  48.855 30.811 49.914 31.339 ;
     RECT  51.156 31.147 51.174 31.339 ;
     RECT  42.408 31.181 43.902 31.351 ;
     RECT  53.676 30.569 54.738 31.351 ;
     RECT  55.872 31.261 57.222 31.351 ;
     RECT  21.855 31.289 25.146 31.379 ;
     RECT  46.764 31.339 49.914 31.387 ;
     RECT  50.904 31.339 51.174 31.387 ;
     RECT  14.616 31.181 14.814 31.415 ;
     RECT  21.855 31.379 23.922 31.415 ;
     RECT  25.92 31.289 28.026 31.415 ;
     RECT  42.408 31.351 44.298 31.421 ;
     RECT  32.364 30.509 33.642 31.423 ;
     RECT  34.596 30.569 34.614 31.423 ;
     RECT  64.152 31.261 65.337 31.435 ;
     RECT  21.855 31.415 23.382 31.495 ;
     RECT  29.088 31.081 29.61 31.495 ;
     RECT  42.408 31.421 44.226 31.517 ;
     RECT  58.176 30.991 62.73 31.523 ;
     RECT  34.596 31.423 34.758 31.531 ;
     RECT  53.676 31.351 57.222 31.579 ;
     RECT  58.176 31.523 60.138 31.579 ;
     RECT  66.708 31.229 67.986 31.613 ;
     RECT  37.836 30.955 38.97 31.621 ;
     RECT  40.536 30.911 41.022 31.621 ;
     RECT  24.876 31.379 25.146 31.649 ;
     RECT  29.088 31.495 29.682 31.649 ;
     RECT  53.676 31.579 60.138 31.649 ;
     RECT  61.02 31.523 62.73 31.649 ;
     RECT  64.152 31.435 65.754 31.649 ;
     RECT  29.664 31.649 29.682 31.657 ;
     RECT  31.932 31.423 33.642 31.657 ;
     RECT  34.524 31.531 34.758 31.657 ;
     RECT  52.452 30.749 52.47 31.693 ;
     RECT  61.56 31.649 62.73 31.693 ;
     RECT  40.536 31.621 41.382 31.709 ;
     RECT  21.816 31.495 23.382 31.721 ;
     RECT  37.836 31.621 39.762 31.729 ;
     RECT  69.048 31.181 72.702 31.757 ;
     RECT  36.324 30.641 36.45 31.765 ;
     RECT  37.62 31.729 39.762 31.765 ;
     RECT  40.536 31.709 41.274 31.765 ;
     RECT  46.764 31.387 51.174 31.765 ;
     RECT  54.255 31.649 60.138 31.793 ;
     RECT  30.78 31.217 30.798 31.801 ;
     RECT  46.188 31.765 51.174 31.801 ;
     RECT  54.255 31.793 58.338 31.805 ;
     RECT  5.655 31.085 7.074 31.829 ;
     RECT  25.92 31.415 27.954 31.829 ;
     RECT  6.804 31.829 7.074 31.867 ;
     RECT  8.028 31.085 8.514 31.867 ;
     RECT  9.684 31.153 9.702 31.867 ;
     RECT  46.188 31.801 51.282 31.867 ;
     RECT  28.8 31.657 28.818 31.891 ;
     RECT  31.932 31.657 34.758 31.891 ;
     RECT  24.912 31.649 25.146 31.901 ;
     RECT  36.324 31.765 41.274 31.915 ;
     RECT  6.804 31.867 8.514 31.919 ;
     RECT  10.836 31.217 12.618 31.919 ;
     RECT  22.86 31.721 23.382 31.919 ;
     RECT  25.02 31.901 25.146 31.919 ;
     RECT  36.108 31.915 41.274 31.919 ;
     RECT  42.408 31.517 43.866 31.919 ;
     RECT  45.036 30.755 45.054 31.919 ;
     RECT  45.972 31.867 51.282 31.919 ;
     RECT  55.8 31.805 58.338 31.919 ;
     RECT  12.564 31.919 12.618 31.927 ;
     RECT  31.86 31.891 34.758 31.927 ;
     RECT  28.692 31.891 28.818 31.928 ;
     RECT  30.78 31.801 31.086 31.955 ;
     RECT  14.796 31.415 14.814 31.963 ;
     RECT  19.728 31.261 20.07 31.963 ;
     RECT  52.452 31.693 52.902 31.963 ;
     RECT  69.048 31.757 69.066 31.997 ;
     RECT  14.796 31.963 14.85 31.999 ;
     RECT  17.964 31.325 18.702 31.999 ;
     RECT  19.512 31.963 20.07 31.999 ;
     RECT  31.86 31.927 35.082 31.999 ;
     RECT  22.896 31.919 23.382 32.027 ;
     RECT  28.692 31.928 28.782 32.027 ;
     RECT  14.796 31.999 14.886 32.035 ;
     RECT  12.564 31.927 12.726 32.059 ;
     RECT  29.664 31.657 30.006 32.059 ;
     RECT  30.78 31.955 30.87 32.059 ;
     RECT  66.744 31.613 67.986 32.059 ;
     RECT  14.796 32.035 14.958 32.071 ;
     RECT  46.188 31.919 51.282 32.071 ;
     RECT  52.056 31.963 52.902 32.071 ;
     RECT  12.564 32.059 13.014 32.099 ;
     RECT  31.86 31.999 35.334 32.099 ;
     RECT  8.172 31.919 8.514 32.152 ;
     RECT  9.252 31.867 9.702 32.152 ;
     RECT  21.816 31.721 22.137 32.155 ;
     RECT  16.164 31.145 16.737 32.161 ;
     RECT  46.188 32.071 52.902 32.161 ;
     RECT  0.036 31.181 3.114 32.189 ;
     RECT  8.172 32.152 9.702 32.189 ;
     RECT  33.984 32.099 35.334 32.189 ;
     RECT  55.908 31.919 58.338 32.189 ;
     RECT  8.172 32.189 8.262 32.195 ;
     RECT  25.092 31.919 25.146 32.197 ;
     RECT  25.92 31.829 27.846 32.197 ;
     RECT  46.188 32.161 53.37 32.225 ;
     RECT  16.056 32.161 16.737 32.233 ;
     RECT  31.86 32.099 33.03 32.233 ;
     RECT  25.092 32.197 27.846 32.237 ;
     RECT  44.856 32.161 44.874 32.237 ;
     RECT  61.56 31.693 63.09 32.251 ;
     RECT  64.152 31.649 64.206 32.251 ;
     RECT  12.636 32.099 13.014 32.261 ;
     RECT  14.796 32.071 15.03 32.261 ;
     RECT  8.244 32.195 8.262 32.297 ;
     RECT  59.256 31.793 60.138 32.299 ;
     RECT  16.056 32.233 17.154 32.327 ;
     RECT  5.655 31.829 5.937 32.341 ;
     RECT  17.964 31.999 20.07 32.341 ;
     RECT  36.108 31.919 38.79 32.341 ;
     RECT  59.256 32.299 60.246 32.341 ;
     RECT  66.744 32.059 68.562 32.341 ;
     RECT  9.108 32.189 9.702 32.369 ;
     RECT  6.804 31.919 7.182 32.381 ;
     RECT  9.288 32.369 9.702 32.381 ;
     RECT  14.796 32.261 14.994 32.381 ;
     RECT  17.964 32.341 20.61 32.381 ;
     RECT  54.255 31.805 54.882 32.395 ;
     RECT  9.36 32.381 9.702 32.431 ;
     RECT  10.836 31.919 11.826 32.431 ;
     RECT  12.672 32.261 13.014 32.431 ;
     RECT  39.924 31.919 41.274 32.431 ;
     RECT  9.36 32.431 11.826 32.459 ;
     RECT  15.876 32.327 17.154 32.459 ;
     RECT  26.172 32.237 27.846 32.459 ;
     RECT  42.408 31.919 43.737 32.459 ;
     RECT  56.952 32.189 58.338 32.459 ;
     RECT  17.964 32.381 18.486 32.467 ;
     RECT  19.368 32.381 20.61 32.467 ;
     RECT  21.564 32.155 22.137 32.467 ;
     RECT  6.804 32.381 7.11 32.477 ;
     RECT  9.612 32.459 11.826 32.477 ;
     RECT  12.672 32.431 13.41 32.477 ;
     RECT  64.944 31.649 65.754 32.477 ;
     RECT  52.128 32.225 53.37 32.491 ;
     RECT  54.144 32.395 54.882 32.491 ;
     RECT  6.804 32.477 7.038 32.495 ;
     RECT  26.172 32.459 26.514 32.495 ;
     RECT  66.708 32.341 68.562 32.503 ;
     RECT  59.256 32.341 60.318 32.575 ;
     RECT  61.56 32.251 64.206 32.587 ;
     RECT  64.944 32.477 65.337 32.587 ;
     RECT  5.544 32.341 5.937 32.611 ;
     RECT  39.924 32.431 41.382 32.611 ;
     RECT  5.544 32.611 6.39 32.729 ;
     RECT  28.692 32.027 28.71 32.729 ;
     RECT  31.608 32.233 33.03 32.729 ;
     RECT  55.908 32.189 56.07 32.729 ;
     RECT  61.56 32.587 65.337 32.729 ;
     RECT  29.664 32.059 30.87 32.731 ;
     RECT  31.608 32.729 32.994 32.731 ;
     RECT  52.128 32.491 54.882 32.737 ;
     RECT  55.908 32.729 55.926 32.737 ;
     RECT  45 32.728 45.018 32.765 ;
     RECT  61.56 32.729 64.206 32.765 ;
     RECT  29.664 32.731 32.994 32.779 ;
     RECT  46.188 32.225 51.03 32.827 ;
     RECT  66.06 32.503 68.562 32.827 ;
     RECT  17.892 32.467 18.486 32.873 ;
     RECT  29.196 32.779 32.994 32.873 ;
     RECT  19.368 32.467 22.137 32.881 ;
     RECT  23.364 32.027 23.382 32.881 ;
     RECT  25.092 32.237 25.11 32.881 ;
     RECT  59.112 32.575 60.318 32.881 ;
     RECT  52.128 32.737 55.926 32.909 ;
     RECT  5.544 32.729 6.318 32.923 ;
     RECT  5.076 32.923 6.318 32.965 ;
     RECT  27.255 32.459 27.846 32.971 ;
     RECT  70.056 31.757 72.702 32.971 ;
     RECT  9.684 32.477 11.826 32.999 ;
     RECT  29.664 32.873 32.994 32.999 ;
     RECT  62.172 32.765 64.206 32.999 ;
     RECT  4.896 32.965 6.318 33.005 ;
     RECT  29.664 32.999 32.937 33.005 ;
     RECT  12.672 32.477 12.69 33.007 ;
     RECT  5.004 33.005 6.318 33.008 ;
     RECT  9.684 32.999 11.61 33.035 ;
     RECT  33.984 32.189 35.082 33.035 ;
     RECT  39.924 32.611 41.814 33.035 ;
     RECT  62.172 32.999 64.098 33.035 ;
     RECT  52.128 32.909 55.89 33.043 ;
     RECT  59.076 32.881 60.318 33.043 ;
     RECT  61.092 32.881 61.11 33.043 ;
     RECT  12.6 33.007 12.69 33.053 ;
     RECT  40.32 33.035 41.814 33.053 ;
     RECT  12.672 33.053 12.69 33.071 ;
     RECT  29.664 33.005 29.682 33.071 ;
     RECT  34.092 33.035 35.082 33.071 ;
     RECT  64.944 32.729 65.337 33.071 ;
     RECT  24.48 32.881 25.11 33.101 ;
     RECT  0.036 32.189 3.078 33.115 ;
     RECT  45.54 32.827 51.03 33.115 ;
     RECT  62.172 33.035 63.558 33.149 ;
     RECT  0.036 33.115 3.438 33.151 ;
     RECT  57.024 32.459 58.338 33.151 ;
     RECT  59.076 33.043 61.11 33.151 ;
     RECT  19.368 32.881 23.382 33.163 ;
     RECT  66.06 32.827 69.21 33.259 ;
     RECT  70.056 32.971 72.738 33.259 ;
     RECT  5.655 33.008 6.318 33.269 ;
     RECT  35.964 32.341 38.79 33.269 ;
     RECT  45.54 33.115 51.102 33.293 ;
     RECT  0.036 33.151 3.474 33.313 ;
     RECT  19.368 33.163 23.418 33.349 ;
     RECT  47.772 33.293 51.102 33.389 ;
     RECT  9.684 33.035 11.574 33.421 ;
     RECT  14.256 32.701 14.274 33.421 ;
     RECT  27.255 32.971 27.882 33.421 ;
     RECT  7.812 33.349 7.83 33.449 ;
     RECT  57.024 33.151 61.11 33.485 ;
     RECT  17.892 32.873 17.91 33.511 ;
     RECT  34.272 33.071 35.082 33.511 ;
     RECT  17.82 33.511 17.91 33.539 ;
     RECT  18.864 33.349 23.418 33.539 ;
     RECT  36.504 33.269 38.79 33.539 ;
     RECT  40.32 33.053 40.554 33.539 ;
     RECT  41.544 33.053 41.814 33.539 ;
     RECT  44.46 33.307 44.478 33.539 ;
     RECT  45.54 33.293 46.962 33.539 ;
     RECT  42.768 32.459 43.737 33.547 ;
     RECT  45.54 33.539 46.854 33.547 ;
     RECT  36.504 33.539 36.63 33.575 ;
     RECT  16.455 32.459 16.83 33.583 ;
     RECT  17.82 33.539 17.838 33.583 ;
     RECT  5.655 33.269 6.174 33.611 ;
     RECT  8.604 33.511 8.622 33.611 ;
     RECT  16.455 33.583 17.838 33.629 ;
     RECT  37.548 33.539 38.79 33.643 ;
     RECT  0.036 33.313 3.51 33.691 ;
     RECT  14.256 33.421 14.886 33.781 ;
     RECT  30.78 33.005 32.937 33.781 ;
     RECT  48.132 33.389 51.102 33.787 ;
     RECT  51.912 33.043 55.89 33.787 ;
     RECT  0.036 33.691 4.122 33.809 ;
     RECT  48.132 33.787 55.89 33.817 ;
     RECT  18.864 33.539 23.13 33.845 ;
     RECT  26.244 32.495 26.514 33.845 ;
     RECT  58.14 33.485 61.11 33.845 ;
     RECT  14.256 33.781 14.922 33.853 ;
     RECT  48.132 33.817 56.142 33.853 ;
     RECT  57.024 33.485 57.33 33.853 ;
     RECT  3.816 33.809 4.122 33.881 ;
     RECT  30.78 33.781 33.282 33.881 ;
     RECT  58.572 33.845 61.11 33.881 ;
     RECT  66.06 33.259 72.738 33.881 ;
     RECT  27.255 33.421 28.062 33.889 ;
     RECT  42.084 33.547 43.737 33.889 ;
     RECT  13.752 33.853 14.922 33.917 ;
     RECT  34.272 33.511 35.37 33.961 ;
     RECT  58.68 33.881 61.11 33.961 ;
     RECT  58.68 33.961 61.218 33.989 ;
     RECT  63.468 33.149 63.558 34.027 ;
     RECT  3.96 33.881 4.122 34.051 ;
     RECT  13.752 33.917 14.85 34.051 ;
     RECT  16.455 33.629 17.37 34.051 ;
     RECT  37.548 33.643 39.186 34.051 ;
     RECT  9.54 33.421 11.574 34.079 ;
     RECT  13.68 34.051 14.85 34.079 ;
     RECT  19.656 33.845 23.13 34.079 ;
     RECT  40.32 33.539 40.482 34.079 ;
     RECT  48.132 33.853 57.33 34.079 ;
     RECT  58.716 33.989 61.218 34.079 ;
     RECT  21.24 34.079 23.13 34.109 ;
     RECT  65.055 33.071 65.337 34.123 ;
     RECT  66.06 33.881 67.266 34.123 ;
     RECT  12.348 33.889 12.366 34.151 ;
     RECT  62.172 33.149 62.73 34.171 ;
     RECT  63.468 34.027 63.918 34.171 ;
     RECT  14.472 34.079 14.85 34.187 ;
     RECT  18.828 34.051 18.846 34.187 ;
     RECT  19.656 34.079 20.358 34.187 ;
     RECT  45.036 33.547 46.854 34.187 ;
     RECT  9.54 34.079 11.394 34.195 ;
     RECT  26.496 33.845 26.514 34.195 ;
     RECT  27.255 33.889 28.278 34.195 ;
     RECT  9.324 34.195 11.394 34.205 ;
     RECT  19.656 34.187 19.674 34.205 ;
     RECT  58.716 34.079 60.858 34.205 ;
     RECT  62.172 34.171 63.918 34.205 ;
     RECT  9.324 34.205 11.337 34.223 ;
     RECT  21.24 34.109 22.842 34.223 ;
     RECT  53.568 34.079 57.33 34.223 ;
     RECT  24.516 33.101 25.11 34.259 ;
     RECT  3.96 34.051 4.194 34.267 ;
     RECT  3.96 34.267 4.662 34.301 ;
     RECT  42.084 33.889 43.938 34.321 ;
     RECT  45.036 34.187 46.782 34.321 ;
     RECT  9.324 34.223 10.278 34.349 ;
     RECT  34.2 33.961 35.37 34.349 ;
     RECT  48.132 34.079 52.47 34.349 ;
     RECT  40.428 34.079 40.482 34.357 ;
     RECT  26.496 34.195 28.278 34.385 ;
     RECT  42.084 34.321 46.782 34.397 ;
     RECT  53.568 34.223 54.846 34.397 ;
     RECT  4.392 34.301 4.662 34.429 ;
     RECT  4.392 34.429 4.698 34.465 ;
     RECT  40.428 34.357 40.518 34.465 ;
     RECT  9.324 34.349 9.342 34.493 ;
     RECT  6.84 34.465 6.858 34.501 ;
     RECT  26.604 34.385 28.278 34.501 ;
     RECT  29.772 33.889 29.79 34.501 ;
     RECT  36.504 33.575 36.522 34.501 ;
     RECT  37.548 34.051 39.546 34.501 ;
     RECT  55.872 34.223 57.33 34.501 ;
     RECT  30.78 33.881 32.937 34.529 ;
     RECT  37.476 34.501 39.546 34.529 ;
     RECT  42.084 34.397 43.938 34.529 ;
     RECT  6.84 34.501 6.93 34.619 ;
     RECT  25.092 34.259 25.11 34.619 ;
     RECT  55.872 34.501 57.582 34.619 ;
     RECT  10.26 34.349 10.278 34.655 ;
     RECT  30.78 34.529 31.338 34.655 ;
     RECT  40.428 34.465 40.554 34.663 ;
     RECT  62.46 34.205 63.918 34.663 ;
     RECT  65.055 34.123 67.266 34.663 ;
     RECT  59.544 34.205 60.858 34.685 ;
     RECT  4.392 34.465 4.77 34.691 ;
     RECT  6.84 34.619 6.858 34.691 ;
     RECT  14.472 34.187 14.49 34.691 ;
     RECT  34.2 34.349 35.01 34.691 ;
     RECT  58.716 34.205 58.734 34.691 ;
     RECT  59.655 34.685 60.858 34.691 ;
     RECT  0.036 33.809 3.006 34.763 ;
     RECT  30.78 34.655 30.906 34.763 ;
     RECT  48.132 34.349 52.038 34.771 ;
     RECT  4.392 34.691 4.662 34.781 ;
     RECT  36.252 34.501 36.522 34.781 ;
     RECT  56.124 34.619 57.582 34.781 ;
     RECT  59.655 34.691 60.822 34.799 ;
     RECT  4.572 34.781 4.662 34.889 ;
     RECT  13.68 34.079 13.698 34.889 ;
     RECT  30.78 34.763 30.798 34.889 ;
     RECT  47.664 34.771 52.038 34.889 ;
     RECT  57.564 34.781 57.582 34.925 ;
     RECT  59.655 34.799 60.678 34.925 ;
     RECT  21.855 34.223 22.842 34.933 ;
     RECT  40.428 34.663 40.626 34.969 ;
     RECT  45.036 34.397 46.782 34.987 ;
     RECT  53.676 34.397 54.846 34.987 ;
     RECT  62.46 34.663 67.266 34.987 ;
     RECT  45.036 34.987 47.466 35.033 ;
     RECT  21.855 34.933 23.382 35.041 ;
     RECT  34.2 34.691 34.218 35.041 ;
     RECT  39.06 34.529 39.546 35.041 ;
     RECT  40.428 34.969 41.202 35.041 ;
     RECT  62.1 34.987 67.266 35.069 ;
     RECT  34.128 35.041 34.218 35.117 ;
     RECT  58.644 35.041 58.662 35.117 ;
     RECT  53.676 34.987 55.134 35.131 ;
     RECT  21.855 35.041 23.958 35.159 ;
     RECT  26.604 34.501 29.79 35.159 ;
     RECT  45.036 35.033 47.358 35.159 ;
     RECT  21.855 35.159 23.778 35.165 ;
     RECT  14.976 35.041 14.994 35.213 ;
     RECT  52.884 35.167 52.902 35.213 ;
     RECT  48.24 34.889 52.038 35.227 ;
     RECT  28.98 35.159 29.79 35.311 ;
     RECT  37.476 34.529 38.337 35.311 ;
     RECT  21.855 35.165 23.706 35.339 ;
     RECT  24.732 35.203 24.75 35.339 ;
     RECT  48.24 35.227 52.182 35.339 ;
     RECT  62.46 35.069 67.266 35.339 ;
     RECT  63.54 35.339 67.266 35.401 ;
     RECT  15.768 34.051 17.37 35.429 ;
     RECT  28.98 35.311 29.862 35.429 ;
     RECT  36.36 34.781 36.522 35.429 ;
     RECT  45.612 35.159 47.358 35.429 ;
     RECT  57.888 35.311 57.906 35.453 ;
     RECT  0.036 34.763 2.862 35.465 ;
     RECT  35.352 35.203 35.37 35.473 ;
     RECT  37.404 35.311 38.337 35.473 ;
     RECT  39.06 35.041 41.238 35.473 ;
     RECT  1.368 35.465 2.862 35.501 ;
     RECT  43.056 34.529 43.938 35.563 ;
     RECT  15.804 35.429 17.37 35.573 ;
     RECT  48.24 35.339 51.858 35.645 ;
     RECT  58.392 35.581 58.626 35.645 ;
     RECT  43.056 35.563 44.19 35.671 ;
     RECT  58.608 35.645 58.626 35.693 ;
     RECT  1.368 35.501 2.07 35.699 ;
     RECT  14.868 35.581 14.886 35.699 ;
     RECT  32.184 34.529 32.937 35.699 ;
     RECT  45.648 35.429 47.358 35.699 ;
     RECT  48.564 35.645 51.858 35.699 ;
     RECT  53.676 35.131 55.314 35.699 ;
     RECT  68.184 33.881 72.738 35.699 ;
     RECT  1.368 35.699 1.998 35.735 ;
     RECT  45.9 35.699 47.358 35.735 ;
     RECT  63.54 35.401 67.446 35.735 ;
     RECT  37.404 35.473 41.238 35.741 ;
     RECT  62.46 35.339 62.73 35.741 ;
     RECT  34.776 35.473 35.37 35.771 ;
     RECT  34.92 35.771 35.37 35.803 ;
     RECT  36.36 35.429 36.414 35.803 ;
     RECT  32.655 35.699 32.937 35.815 ;
     RECT  1.476 35.735 1.998 35.843 ;
     RECT  30.78 35.707 30.798 35.843 ;
     RECT  54.036 35.699 55.314 35.851 ;
     RECT  65.055 35.735 67.446 35.851 ;
     RECT  68.184 35.699 72.702 35.851 ;
     RECT  29.016 35.429 29.862 35.879 ;
     RECT  34.92 35.803 36.414 35.879 ;
     RECT  46.764 35.735 46.782 35.879 ;
     RECT  50.04 35.699 51.858 35.885 ;
     RECT  11.016 34.223 11.337 35.941 ;
     RECT  16.455 35.573 17.37 35.941 ;
     RECT  26.604 35.159 28.098 35.941 ;
     RECT  50.04 35.885 51.75 35.969 ;
     RECT  54.036 35.851 55.386 35.969 ;
     RECT  56.124 34.781 56.538 35.969 ;
     RECT  50.184 35.969 51.75 35.981 ;
     RECT  54.255 35.969 55.386 35.981 ;
     RECT  63.54 35.735 64.314 35.981 ;
     RECT  21.855 35.339 23.382 36.077 ;
     RECT  26.604 35.941 28.134 36.077 ;
     RECT  48.564 35.699 49.137 36.077 ;
     RECT  16.455 35.941 18.054 36.085 ;
     RECT  29.124 35.879 29.862 36.085 ;
     RECT  16.455 36.085 18.198 36.113 ;
     RECT  34.92 35.879 35.91 36.113 ;
     RECT  41.04 35.741 41.238 36.121 ;
     RECT  42.084 34.529 42.21 36.121 ;
     RECT  11.016 35.941 11.394 36.125 ;
     RECT  29.124 36.085 29.898 36.125 ;
     RECT  41.04 36.121 42.21 36.173 ;
     RECT  17.964 36.113 18.198 36.239 ;
     RECT  21.855 36.077 22.842 36.239 ;
     RECT  30.852 36.121 30.942 36.239 ;
     RECT  37.404 35.741 39.87 36.239 ;
     RECT  50.184 35.981 50.238 36.239 ;
     RECT  65.055 35.851 72.702 36.239 ;
     RECT  48.78 36.077 49.137 36.269 ;
     RECT  17.964 36.239 17.982 36.275 ;
     RECT  50.22 36.239 50.238 36.311 ;
     RECT  51.048 35.981 51.75 36.317 ;
     RECT  42.084 36.173 42.21 36.379 ;
     RECT  43.056 35.671 44.694 36.379 ;
     RECT  59.655 34.925 60.498 36.391 ;
     RECT  39.348 36.239 39.87 36.419 ;
     RECT  52.992 36.331 53.01 36.419 ;
     RECT  45.9 35.735 45.918 36.461 ;
     RECT  57.312 36.391 57.582 36.475 ;
     RECT  11.016 36.125 11.337 36.481 ;
     RECT  42.084 36.379 44.694 36.481 ;
     RECT  55.296 35.981 55.386 36.481 ;
     RECT  56.124 35.969 56.43 36.481 ;
     RECT  57.312 36.475 57.906 36.481 ;
     RECT  62.46 35.741 62.478 36.481 ;
     RECT  34.92 36.113 35.37 36.509 ;
     RECT  39.348 36.419 39.366 36.509 ;
     RECT  51.048 36.317 51.174 36.509 ;
     RECT  55.296 36.481 56.43 36.509 ;
     RECT  63.54 35.981 64.134 36.509 ;
     RECT  10.98 36.481 11.337 36.523 ;
     RECT  2.844 35.501 2.862 36.545 ;
     RECT  40.14 36.517 40.158 36.557 ;
     RECT  42.084 36.481 44.982 36.557 ;
     RECT  55.296 36.509 55.638 36.557 ;
     RECT  30.852 36.239 30.87 36.589 ;
     RECT  1.512 35.843 1.998 36.661 ;
     RECT  30.78 36.589 30.87 36.689 ;
     RECT  34.92 36.509 35.226 36.689 ;
     RECT  42.084 36.557 44.514 36.701 ;
     RECT  66.456 36.239 72.702 36.701 ;
     RECT  32.655 35.815 33.102 36.751 ;
     RECT  34.92 36.689 35.154 36.779 ;
     RECT  57.168 36.481 57.906 36.779 ;
     RECT  63.936 36.509 64.134 36.779 ;
     RECT  42.12 36.701 44.514 36.797 ;
     RECT  56.412 36.509 56.43 36.811 ;
     RECT  57.168 36.779 57.87 36.811 ;
     RECT  0.036 35.465 0.537 36.815 ;
     RECT  34.92 36.779 34.938 36.815 ;
     RECT  55.296 36.557 55.314 36.815 ;
     RECT  41.04 36.173 41.238 36.851 ;
     RECT  56.412 36.811 57.87 36.851 ;
     RECT  37.404 36.239 38.337 36.931 ;
     RECT  62.28 36.481 62.478 36.931 ;
     RECT  65.055 36.239 65.574 36.931 ;
     RECT  66.708 36.701 72.702 36.931 ;
     RECT  26.604 36.077 28.062 36.959 ;
     RECT  42.192 36.797 44.514 36.959 ;
     RECT  46.116 36.859 46.206 36.959 ;
     RECT  46.116 36.959 46.134 36.989 ;
     RECT  30.852 36.689 30.87 37.003 ;
     RECT  1.512 36.661 2.502 37.049 ;
     RECT  10.8 36.523 11.337 37.049 ;
     RECT  29.124 36.125 29.862 37.049 ;
     RECT  30.852 37.003 31.086 37.049 ;
     RECT  34.776 36.931 34.794 37.049 ;
     RECT  54.255 35.981 54.537 37.051 ;
     RECT  59.655 36.391 61.002 37.051 ;
     RECT  1.512 37.049 1.53 37.085 ;
     RECT  51.156 36.509 51.174 37.085 ;
     RECT  2.484 37.049 2.502 37.193 ;
     RECT  31.932 36.751 33.102 37.229 ;
     RECT  54.255 37.051 54.738 37.229 ;
     RECT  37.044 36.931 38.337 37.319 ;
     RECT  40.5 37.165 40.698 37.319 ;
     RECT  56.412 36.851 56.43 37.319 ;
     RECT  58.716 37.051 61.002 37.319 ;
     RECT  66.708 36.931 72.738 37.319 ;
     RECT  57.168 36.851 57.87 37.355 ;
     RECT  62.28 36.931 62.73 37.363 ;
     RECT  58.716 37.319 58.734 37.373 ;
     RECT  62.28 37.363 62.766 37.399 ;
     RECT  29.664 37.049 29.862 37.471 ;
     RECT  38.055 37.319 38.337 37.471 ;
     RECT  43.056 36.959 44.514 37.471 ;
     RECT  26.604 36.959 27.666 37.499 ;
     RECT  42.192 36.959 42.21 37.499 ;
     RECT  62.28 37.399 62.838 37.499 ;
     RECT  29.664 37.471 30.042 37.517 ;
     RECT  38.055 37.471 38.43 37.517 ;
     RECT  43.056 37.471 44.73 37.517 ;
     RECT  20.592 36.391 20.61 37.579 ;
     RECT  20.592 37.579 20.826 37.589 ;
     RECT  41.436 37.471 41.454 37.589 ;
     RECT  43.056 37.517 44.154 37.589 ;
     RECT  64.98 36.931 65.574 37.589 ;
     RECT  67.572 37.319 72.738 37.589 ;
     RECT  57.852 37.355 57.87 37.613 ;
     RECT  20.808 37.589 20.826 37.625 ;
     RECT  39.492 37.579 39.51 37.625 ;
     RECT  43.056 37.589 43.737 37.625 ;
     RECT  59.655 37.319 61.002 37.627 ;
     RECT  62.28 37.499 62.73 37.661 ;
     RECT  12.564 37.021 12.582 37.859 ;
     RECT  29.664 37.517 29.682 37.859 ;
     RECT  37.044 37.319 37.062 37.859 ;
     RECT  45.972 37.597 45.99 37.859 ;
     RECT  56.988 37.741 57.114 37.859 ;
     RECT  59.655 37.627 61.542 37.859 ;
     RECT  70.092 37.589 72.738 37.859 ;
     RECT  59.655 37.859 60.282 37.895 ;
     RECT  56.988 37.859 57.006 37.904 ;
     RECT  67.572 37.589 69.138 37.931 ;
     RECT  59.655 37.895 60.174 37.949 ;
     RECT  30.636 37.963 30.654 38.003 ;
     RECT  12.744 38.005 12.762 38.045 ;
     RECT  46.44 38.005 46.458 38.045 ;
     RECT  31.932 37.229 32.937 38.129 ;
     RECT  67.572 37.931 69.03 38.129 ;
     RECT  32.4 38.129 32.937 38.141 ;
     RECT  70.128 37.859 72.738 38.399 ;
     RECT  64.98 37.589 65.337 38.551 ;
     RECT  66.708 37.319 66.726 38.579 ;
     RECT  64.98 38.551 65.862 38.632 ;
     RECT  26.604 37.499 27.537 38.669 ;
     RECT  64.98 38.632 66.294 38.669 ;
     RECT  64.98 38.669 66.078 38.717 ;
     RECT  64.98 38.717 65.43 38.741 ;
     RECT  63.936 36.779 63.954 38.813 ;
     RECT  70.164 38.399 72.738 39.047 ;
     RECT  68.652 38.129 69.03 39.055 ;
     RECT  68.652 39.055 69.102 39.091 ;
     RECT  62.712 37.661 62.73 39.163 ;
     RECT  62.712 39.163 63.414 39.209 ;
     RECT  67.572 38.129 67.59 39.281 ;
     RECT  70.2 39.047 72.738 39.281 ;
     RECT  65.055 38.741 65.43 39.293 ;
     RECT  70.2 39.281 72.702 39.395 ;
     RECT  70.2 39.395 72.666 39.773 ;
     RECT  70.2 39.773 72.63 39.821 ;
     RECT  0.255 36.815 0.537 39.977 ;
     RECT  5.655 33.611 5.937 39.977 ;
     RECT  11.055 37.049 11.337 39.977 ;
     RECT  16.455 36.113 16.737 39.977 ;
     RECT  21.855 36.239 22.137 39.977 ;
     RECT  27.255 38.669 27.537 39.977 ;
     RECT  32.655 38.141 32.937 39.977 ;
     RECT  38.055 37.517 38.337 39.977 ;
     RECT  43.455 37.625 43.737 39.977 ;
     RECT  48.855 36.269 49.137 39.977 ;
     RECT  54.255 37.229 54.537 39.977 ;
     RECT  59.655 37.949 59.937 39.977 ;
     RECT  65.055 39.293 65.337 39.977 ;
     RECT  70.455 39.821 71.118 39.977 ;
     RECT  68.652 39.091 69.21 40.019 ;
     RECT  70.647 39.977 71.118 40.061 ;
     RECT  70.647 40.061 71.046 40.163 ;
     RECT  71.892 39.821 72.63 40.205 ;
     RECT  0.447 39.977 0.537 40.247 ;
     RECT  5.847 39.977 5.937 40.247 ;
     RECT  11.247 39.977 11.337 40.247 ;
     RECT  16.647 39.977 16.737 40.247 ;
     RECT  22.047 39.977 22.137 40.247 ;
     RECT  27.447 39.977 27.537 40.247 ;
     RECT  32.847 39.977 32.937 40.247 ;
     RECT  38.247 39.977 38.337 40.247 ;
     RECT  43.647 39.977 43.737 40.247 ;
     RECT  49.047 39.977 49.137 40.247 ;
     RECT  54.447 39.977 54.537 40.247 ;
     RECT  59.847 39.977 59.937 40.247 ;
     RECT  65.247 39.977 65.337 40.247 ;
     RECT  70.647 40.163 70.737 40.247 ;
     RECT  71.892 40.205 72.45 40.253 ;
     RECT  71.892 40.253 71.91 40.301 ;
     RECT  69.192 40.019 69.21 40.541 ;
    LAYER M4 ;
     RECT  0.025 8.592 0.037 19.416 ;
     RECT  0.025 20.496 0.037 32.808 ;
     RECT  0.037 8.592 0.061 32.808 ;
     RECT  0.061 8.592 0.085 33.048 ;
     RECT  0.085 8.592 0.156 33.096 ;
     RECT  0.156 8.16 0.248 33.096 ;
     RECT  0.248 0.528 0.352 39.972 ;
     RECT  0.352 0.798 0.44 39.972 ;
     RECT  0.44 0.798 0.544 40.242 ;
     RECT  0.544 8.16 0.659 33.144 ;
     RECT  0.659 8.208 0.947 33.144 ;
     RECT  0.947 8.256 0.965 33.144 ;
     RECT  0.965 8.448 1.577 33.144 ;
     RECT  1.577 8.496 2.405 33.144 ;
     RECT  2.405 8.976 2.867 33.144 ;
     RECT  2.867 15.888 3.449 33.144 ;
     RECT  0.544 34.224 3.949 34.248 ;
     RECT  2.867 8.976 3.973 14.76 ;
     RECT  3.449 15.888 3.973 33.048 ;
     RECT  3.949 34.224 4.381 34.296 ;
     RECT  2.545 35.472 4.381 35.496 ;
     RECT  3.973 8.976 5.648 33.048 ;
     RECT  4.381 34.224 5.648 35.496 ;
     RECT  5.648 0.528 5.752 39.972 ;
     RECT  5.752 0.798 5.84 39.972 ;
     RECT  5.84 0.798 5.944 40.242 ;
     RECT  5.944 8.976 6.329 33.096 ;
     RECT  6.329 8.976 9.961 33.048 ;
     RECT  5.944 34.224 9.961 34.248 ;
     RECT  9.961 8.976 11.048 34.248 ;
     RECT  5.944 35.472 11.048 35.496 ;
     RECT  10.748 36.528 11.048 36.552 ;
     RECT  11.048 0.528 11.152 39.972 ;
     RECT  11.152 0.798 11.24 39.972 ;
     RECT  11.24 0.798 11.344 40.242 ;
     RECT  11.344 34.176 11.405 34.2 ;
     RECT  11.344 35.472 11.459 36.12 ;
     RECT  11.344 8.976 12.589 32.952 ;
     RECT  12.716 38.016 12.803 38.04 ;
     RECT  12.589 8.976 13.853 33.048 ;
     RECT  13.853 9.216 14.429 33.048 ;
     RECT  14.429 9.84 14.645 33.048 ;
     RECT  11.459 35.472 14.965 35.496 ;
     RECT  14.965 35.184 15.395 35.496 ;
     RECT  15.395 35.472 15.729 35.496 ;
     RECT  15.973 9.456 16.448 9.48 ;
     RECT  14.645 10.608 16.448 33.048 ;
     RECT  15.729 35.472 16.448 35.544 ;
     RECT  16.448 0.528 16.552 39.972 ;
     RECT  16.552 0.798 16.64 39.972 ;
     RECT  16.64 0.798 16.744 40.242 ;
     RECT  16.744 9.12 16.921 33.048 ;
     RECT  16.921 10.608 17.123 33.048 ;
     RECT  17.123 30.912 17.809 33.048 ;
     RECT  17.809 30.912 17.893 33.624 ;
     RECT  16.744 35.472 17.948 35.496 ;
     RECT  17.948 35.472 18.035 36.264 ;
     RECT  18.035 35.472 18.083 35.976 ;
     RECT  17.123 10.608 18.277 29.928 ;
     RECT  18.277 10.32 18.515 29.928 ;
     RECT  18.515 10.32 18.533 15.288 ;
     RECT  18.515 16.32 18.673 29.928 ;
     RECT  17.893 30.912 18.673 33.048 ;
     RECT  16.921 9.12 18.716 9.144 ;
     RECT  18.716 9.12 18.803 9.24 ;
     RECT  18.673 16.32 18.929 33.048 ;
     RECT  18.803 9.12 19.001 9.144 ;
     RECT  18.929 30.912 19.177 33.048 ;
     RECT  18.533 10.608 19.433 15.288 ;
     RECT  19.433 10.608 19.577 13.992 ;
     RECT  19.177 30.912 19.645 33.624 ;
     RECT  19.433 14.976 19.789 15.288 ;
     RECT  18.929 16.32 19.789 29.928 ;
     RECT  19.789 14.976 20.081 29.928 ;
     RECT  19.577 10.608 20.243 13.704 ;
     RECT  19.645 30.912 20.243 34.2 ;
     RECT  20.081 29.088 20.257 29.928 ;
     RECT  20.243 30.912 20.257 33.048 ;
     RECT  20.257 29.088 20.531 33.048 ;
     RECT  20.533 9.12 20.732 9.144 ;
     RECT  20.243 10.608 20.732 12.072 ;
     RECT  20.732 9.12 20.819 12.072 ;
     RECT  20.243 13.056 21.121 13.704 ;
     RECT  20.081 14.976 21.121 27.768 ;
     RECT  20.531 29.088 21.157 29.928 ;
     RECT  20.819 10.608 21.229 12.072 ;
     RECT  21.121 13.056 21.229 27.768 ;
     RECT  20.819 9.12 21.637 9.144 ;
     RECT  21.637 8.544 21.848 9.144 ;
     RECT  21.229 10.608 21.848 27.768 ;
     RECT  21.157 28.992 21.848 29.928 ;
     RECT  20.531 30.912 21.848 33.048 ;
     RECT  20.243 34.128 21.848 34.2 ;
     RECT  18.083 35.472 21.848 35.496 ;
     RECT  20.797 37.584 21.848 37.608 ;
     RECT  21.848 0.528 21.952 39.972 ;
     RECT  21.952 0.798 22.04 39.972 ;
     RECT  22.04 0.798 22.144 40.242 ;
     RECT  22.144 9.168 22.285 27.96 ;
     RECT  22.144 29.088 22.444 34.2 ;
     RECT  22.444 29.568 22.789 34.2 ;
     RECT  22.285 9.168 22.889 27.768 ;
     RECT  22.889 10.608 22.925 27.768 ;
     RECT  22.789 29.616 22.925 34.2 ;
     RECT  22.889 9.168 22.933 9.192 ;
     RECT  22.925 30.912 23.708 34.2 ;
     RECT  22.144 35.472 23.708 35.496 ;
     RECT  23.708 30.912 23.795 35.496 ;
     RECT  22.925 29.616 23.893 29.928 ;
     RECT  22.925 10.608 23.929 27.72 ;
     RECT  23.893 29.04 24.005 29.928 ;
     RECT  23.929 10.512 24.013 27.72 ;
     RECT  24.013 10.608 24.469 27.72 ;
     RECT  24.005 29.616 25.405 29.928 ;
     RECT  23.795 30.912 25.405 34.2 ;
     RECT  24.469 10.608 26.773 28.488 ;
     RECT  25.405 29.616 26.773 34.2 ;
     RECT  23.795 35.472 26.773 35.496 ;
     RECT  26.773 10.56 26.876 28.488 ;
     RECT  26.773 29.616 26.876 35.496 ;
     RECT  26.876 10.56 27.248 35.496 ;
     RECT  27.248 0.528 27.352 39.972 ;
     RECT  27.352 0.798 27.44 39.972 ;
     RECT  27.44 0.798 27.544 40.242 ;
     RECT  27.544 10.608 27.965 35.496 ;
     RECT  27.965 10.608 28.073 34.2 ;
     RECT  27.965 35.328 29.045 35.496 ;
     RECT  29.329 37.008 29.651 37.032 ;
     RECT  29.045 35.472 29.852 35.496 ;
     RECT  29.852 35.472 29.939 36.12 ;
     RECT  29.996 37.488 30.083 37.512 ;
     RECT  28.073 10.608 30.323 29.928 ;
     RECT  30.323 11.136 30.449 29.928 ;
     RECT  30.625 37.968 30.755 37.992 ;
     RECT  30.449 11.184 30.805 29.928 ;
     RECT  28.073 30.912 30.805 34.2 ;
     RECT  30.805 11.184 30.851 34.2 ;
     RECT  30.851 12.768 30.953 34.2 ;
     RECT  31.057 37.008 31.331 37.032 ;
     RECT  30.851 11.184 31.909 11.784 ;
     RECT  30.953 13.008 32.101 34.2 ;
     RECT  31.909 10.752 32.648 11.784 ;
     RECT  32.101 12.768 32.648 34.2 ;
     RECT  29.939 35.472 32.648 35.496 ;
     RECT  32.389 38.112 32.648 38.136 ;
     RECT  32.648 0.528 32.752 39.972 ;
     RECT  32.752 0.798 32.84 39.972 ;
     RECT  32.84 0.798 32.944 40.242 ;
     RECT  32.944 13.056 33.113 29.928 ;
     RECT  32.944 30.912 34.076 34.2 ;
     RECT  32.944 35.472 34.076 35.496 ;
     RECT  33.113 14.736 34.297 29.928 ;
     RECT  34.076 30.912 34.297 35.496 ;
     RECT  34.865 36.48 34.949 36.504 ;
     RECT  34.297 14.736 35.021 35.496 ;
     RECT  35.021 35.472 35.881 35.496 ;
     RECT  35.021 14.736 35.885 34.2 ;
     RECT  33.113 13.056 35.9 13.656 ;
     RECT  35.9 12.816 35.987 13.656 ;
     RECT  35.885 30.912 36.241 34.2 ;
     RECT  35.881 35.472 36.241 35.832 ;
     RECT  36.241 30.912 36.467 35.832 ;
     RECT  32.944 11.184 36.62 11.784 ;
     RECT  36.62 11.184 36.707 11.832 ;
     RECT  35.885 14.736 37.045 29.928 ;
     RECT  36.467 30.912 37.045 34.2 ;
     RECT  36.467 35.472 37.532 35.832 ;
     RECT  37.141 37.056 37.532 37.08 ;
     RECT  37.045 14.736 37.909 34.2 ;
     RECT  36.707 11.184 38.048 11.784 ;
     RECT  35.987 13.056 38.048 13.656 ;
     RECT  37.909 14.736 38.048 34.488 ;
     RECT  37.532 35.472 38.048 37.08 ;
     RECT  38.048 0.528 38.152 39.972 ;
     RECT  38.152 0.798 38.24 39.972 ;
     RECT  38.24 0.798 38.344 40.242 ;
     RECT  38.344 37.488 38.485 38.184 ;
     RECT  38.485 38.16 38.675 38.184 ;
     RECT  38.344 14.736 38.819 34.488 ;
     RECT  38.344 13.056 39.329 13.656 ;
     RECT  39.329 12.816 39.349 13.656 ;
     RECT  38.819 14.736 39.349 34.2 ;
     RECT  39.349 12.816 39.413 34.2 ;
     RECT  38.344 35.472 39.644 35.496 ;
     RECT  39.481 37.584 39.779 37.608 ;
     RECT  39.644 35.472 39.829 36.072 ;
     RECT  39.829 35.472 40.129 36.408 ;
     RECT  39.413 13.056 40.405 34.2 ;
     RECT  40.129 35.472 40.405 36.552 ;
     RECT  40.405 13.056 40.451 36.552 ;
     RECT  40.46 37.248 40.547 37.272 ;
     RECT  40.451 13.056 40.637 35.88 ;
     RECT  40.637 14.736 41.42 35.88 ;
     RECT  41.42 14.736 42.044 36.168 ;
     RECT  42.044 14.736 42.109 36.696 ;
     RECT  42.109 14.736 42.179 36.792 ;
     RECT  42.179 35.424 42.193 36.792 ;
     RECT  40.637 13.056 42.325 13.656 ;
     RECT  42.179 14.736 42.325 34.392 ;
     RECT  42.325 13.056 42.412 34.392 ;
     RECT  42.412 13.056 42.668 13.656 ;
     RECT  38.344 11.184 43.448 11.784 ;
     RECT  42.668 13.008 43.448 13.656 ;
     RECT  42.412 14.64 43.448 34.392 ;
     RECT  42.193 35.424 43.448 36.456 ;
     RECT  43.004 37.584 43.448 37.608 ;
     RECT  43.448 0.528 43.552 39.972 ;
     RECT  43.552 0.798 43.64 39.972 ;
     RECT  43.64 0.798 43.744 40.242 ;
     RECT  43.744 12.912 43.885 37.512 ;
     RECT  43.885 12.912 44.243 36.312 ;
     RECT  44.243 12.912 44.597 35.496 ;
     RECT  43.885 37.488 44.771 37.512 ;
     RECT  44.924 36.528 45.011 36.552 ;
     RECT  44.597 13.056 45.245 35.496 ;
     RECT  45.245 14.736 45.889 35.496 ;
     RECT  45.889 14.736 46.076 36.456 ;
     RECT  46.076 14.736 46.163 36.984 ;
     RECT  46.163 14.736 46.355 36.456 ;
     RECT  46.412 38.016 46.499 38.04 ;
     RECT  45.245 13.056 46.573 13.656 ;
     RECT  46.355 14.736 46.573 35.64 ;
     RECT  47.317 9.696 47.513 9.72 ;
     RECT  46.573 13.056 47.549 35.64 ;
     RECT  47.549 14.736 48.469 35.64 ;
     RECT  48.469 14.736 48.709 36.072 ;
     RECT  43.744 11.184 48.848 11.784 ;
     RECT  47.549 13.056 48.848 13.656 ;
     RECT  48.709 14.736 48.848 36.264 ;
     RECT  48.848 0.528 48.952 39.972 ;
     RECT  48.952 0.798 49.04 39.972 ;
     RECT  49.04 0.798 49.144 40.242 ;
     RECT  49.144 14.736 50.821 35.88 ;
     RECT  50.821 14.736 51.145 36.504 ;
     RECT  51.145 14.736 51.349 37.08 ;
     RECT  49.144 13.056 51.877 13.656 ;
     RECT  51.349 14.736 51.877 37.896 ;
     RECT  51.877 13.056 52.913 37.896 ;
     RECT  49.144 11.184 53.029 11.784 ;
     RECT  53.029 10.416 53.129 11.784 ;
     RECT  53.129 11.184 53.893 11.784 ;
     RECT  53.893 11.184 54.133 11.832 ;
     RECT  52.913 13.056 54.133 13.656 ;
     RECT  54.133 11.184 54.248 13.752 ;
     RECT  52.913 14.736 54.248 37.896 ;
     RECT  54.248 0.528 54.352 39.972 ;
     RECT  54.352 0.798 54.44 39.972 ;
     RECT  54.44 0.798 54.544 40.242 ;
     RECT  54.544 13.056 57.013 13.656 ;
     RECT  54.544 14.736 57.013 37.896 ;
     RECT  57.013 13.056 57.017 37.896 ;
     RECT  57.017 13.056 57.097 37.608 ;
     RECT  54.544 11.184 59.648 11.784 ;
     RECT  57.097 13.056 59.648 13.656 ;
     RECT  57.097 14.736 59.648 37.608 ;
     RECT  59.648 0.528 59.752 39.972 ;
     RECT  59.752 0.798 59.84 39.972 ;
     RECT  59.84 0.798 59.944 40.242 ;
     RECT  59.944 14.736 61.532 38.184 ;
     RECT  59.944 13.056 62.149 13.656 ;
     RECT  61.532 14.688 62.149 38.184 ;
     RECT  62.149 13.056 62.525 38.184 ;
     RECT  63.385 39.168 63.685 39.192 ;
     RECT  63.685 39.168 63.827 39.288 ;
     RECT  62.525 13.056 63.829 13.656 ;
     RECT  62.525 14.736 63.829 38.184 ;
     RECT  63.829 13.056 64.037 38.184 ;
     RECT  59.944 11.184 65.048 11.784 ;
     RECT  64.037 13.056 65.048 13.656 ;
     RECT  64.037 14.736 65.048 38.184 ;
     RECT  63.827 39.264 65.048 39.288 ;
     RECT  65.048 0.528 65.152 39.972 ;
     RECT  65.152 0.798 65.24 39.972 ;
     RECT  65.24 0.798 65.344 40.242 ;
     RECT  65.344 14.736 65.441 39.288 ;
     RECT  65.441 14.736 65.507 39.192 ;
     RECT  65.507 14.736 68.821 29.112 ;
     RECT  65.507 30.096 68.821 39.192 ;
     RECT  68.821 14.736 69.109 39.192 ;
     RECT  69.109 14.736 70.069 39.24 ;
     RECT  69.181 40.512 70.069 40.536 ;
     RECT  65.344 11.184 70.448 11.784 ;
     RECT  65.344 13.056 70.448 13.656 ;
     RECT  70.069 14.736 70.448 40.536 ;
     RECT  70.448 0.528 70.552 40.536 ;
     RECT  70.552 0.798 70.744 40.536 ;
     RECT  70.744 11.184 70.985 11.784 ;
     RECT  70.744 13.056 71.411 40.536 ;
     RECT  71.411 13.056 71.453 13.08 ;
     RECT  71.411 14.208 71.489 40.536 ;
     RECT  70.985 11.184 71.597 11.736 ;
     RECT  71.597 11.184 71.885 11.208 ;
     RECT  71.489 14.736 71.891 40.536 ;
     RECT  71.891 15.408 72.821 40.536 ;
     RECT  72.821 15.744 72.828 40.536 ;
     RECT  72.828 40.32 72.851 40.536 ;
     RECT  72.851 40.32 72.947 40.344 ;
    LAYER M5 ;
     RECT  0.24 0.517 0.36 0.787 ;
     RECT  5.64 0.517 5.76 0.787 ;
     RECT  11.04 0.517 11.16 0.787 ;
     RECT  16.44 0.517 16.56 0.787 ;
     RECT  21.84 0.517 21.96 0.787 ;
     RECT  27.24 0.517 27.36 0.787 ;
     RECT  32.64 0.517 32.76 0.787 ;
     RECT  38.04 0.517 38.16 0.787 ;
     RECT  43.44 0.517 43.56 0.787 ;
     RECT  48.84 0.517 48.96 0.787 ;
     RECT  54.24 0.517 54.36 0.787 ;
     RECT  59.64 0.517 59.76 0.787 ;
     RECT  65.04 0.517 65.16 0.787 ;
     RECT  70.44 0.517 70.56 0.787 ;
     RECT  0.24 0.787 0.552 8.149 ;
     RECT  21.84 0.787 22.152 8.181 ;
     RECT  0.24 8.149 0.648 8.197 ;
     RECT  0.24 8.197 0.936 8.437 ;
     RECT  0.24 8.437 1.32 8.629 ;
     RECT  21.648 8.181 22.152 8.757 ;
     RECT  16.44 0.787 16.752 8.821 ;
     RECT  16.44 8.821 16.872 8.949 ;
     RECT  21.12 8.757 22.152 9.013 ;
     RECT  16.44 8.949 17.112 9.071 ;
     RECT  20.544 9.013 22.152 9.119 ;
     RECT  16.44 9.071 17.688 9.155 ;
     RECT  18.816 8.885 18.84 9.155 ;
     RECT  20.544 9.119 22.92 9.155 ;
     RECT  21.84 9.155 22.92 9.203 ;
     RECT  14.304 9.205 14.328 9.289 ;
     RECT  18.768 9.205 18.792 9.289 ;
     RECT  16.44 9.155 16.872 9.445 ;
     RECT  0.144 8.629 1.32 9.493 ;
     RECT  15.984 9.445 16.872 9.529 ;
     RECT  0.144 9.493 1.368 9.589 ;
     RECT  20.784 9.155 20.808 9.707 ;
     RECT  16.44 9.529 16.872 9.731 ;
     RECT  21.84 9.203 22.824 9.731 ;
     RECT  47.328 9.205 47.352 9.731 ;
     RECT  5.64 0.787 5.952 10.003 ;
     RECT  5.64 10.003 6.936 10.091 ;
     RECT  0.144 9.589 1.416 10.229 ;
     RECT  14.256 9.781 14.28 10.271 ;
     RECT  0.144 10.229 1.704 10.293 ;
     RECT  0.048 10.293 1.704 10.355 ;
     RECT  13.872 10.271 14.28 10.355 ;
     RECT  18.288 10.271 18.312 10.355 ;
     RECT  21.84 9.731 22.248 10.355 ;
     RECT  0.048 10.355 1.512 10.475 ;
     RECT  53.04 10.405 53.064 10.489 ;
     RECT  27.24 0.787 27.552 10.549 ;
     RECT  32.64 0.787 32.952 10.741 ;
     RECT  0.048 10.475 1.32 10.787 ;
     RECT  31.92 10.741 32.952 10.825 ;
     RECT  25.68 10.613 25.704 10.837 ;
     RECT  26.784 10.549 27.552 10.837 ;
     RECT  29.088 10.741 29.112 10.859 ;
     RECT  19.968 10.421 19.992 10.883 ;
     RECT  25.68 10.837 27.552 10.883 ;
     RECT  23.952 10.463 23.976 10.893 ;
     RECT  16.44 9.731 16.752 10.933 ;
     RECT  25.776 10.883 27.552 10.933 ;
     RECT  11.04 0.787 11.352 10.997 ;
     RECT  25.776 10.933 27.96 11.017 ;
     RECT  14.832 10.997 14.856 11.061 ;
     RECT  21.84 10.355 22.152 11.061 ;
     RECT  38.04 0.787 38.352 11.061 ;
     RECT  30.288 10.597 30.312 11.125 ;
     RECT  34.8 11.061 34.824 11.189 ;
     RECT  21.744 11.061 22.152 11.221 ;
     RECT  13.104 10.933 13.848 11.283 ;
     RECT  21.648 11.221 22.152 11.307 ;
     RECT  16.44 10.933 16.872 11.365 ;
     RECT  12.912 11.283 13.848 11.371 ;
     RECT  34.8 11.189 34.92 11.371 ;
     RECT  47.472 11.317 47.496 11.401 ;
     RECT  27.12 11.017 27.96 11.411 ;
     RECT  19.392 11.189 19.416 11.413 ;
     RECT  19.152 11.413 19.416 11.423 ;
     RECT  5.64 10.091 5.952 11.445 ;
     RECT  18.864 11.423 19.416 11.459 ;
     RECT  27.24 11.411 27.96 11.459 ;
     RECT  30.24 11.125 30.312 11.459 ;
     RECT  31.344 11.375 31.368 11.459 ;
     RECT  37.632 11.061 38.352 11.459 ;
     RECT  21.84 11.307 22.152 11.475 ;
     RECT  0.144 10.787 1.32 11.499 ;
     RECT  8.352 11.413 8.376 11.499 ;
     RECT  18.864 11.459 19.176 11.507 ;
     RECT  0.144 11.499 1.176 11.563 ;
     RECT  21.84 11.475 22.824 11.563 ;
     RECT  32.496 10.825 32.952 11.603 ;
     RECT  4.896 11.445 5.952 11.605 ;
     RECT  2.928 11.445 2.952 11.627 ;
     RECT  10.848 10.997 11.352 11.637 ;
     RECT  54.24 0.787 54.552 11.637 ;
     RECT  4.368 11.605 5.952 11.651 ;
     RECT  34.224 11.567 34.776 11.651 ;
     RECT  4.368 11.651 4.584 11.691 ;
     RECT  19.152 11.507 19.176 11.691 ;
     RECT  24.528 11.605 24.552 11.691 ;
     RECT  34.752 11.651 34.776 11.691 ;
     RECT  4.56 11.691 4.584 11.725 ;
     RECT  2.784 11.637 2.808 11.747 ;
     RECT  16.44 11.365 17.304 11.797 ;
     RECT  36.672 11.637 36.696 11.843 ;
     RECT  53.904 11.637 54.552 11.843 ;
     RECT  20.544 11.388 20.568 11.939 ;
     RECT  25.776 11.017 25.8 11.939 ;
     RECT  2.208 11.893 2.232 12.083 ;
     RECT  10.848 11.637 11.688 12.149 ;
     RECT  13.776 11.371 13.848 12.149 ;
     RECT  14.832 11.061 14.952 12.149 ;
     RECT  10.272 12.149 12.6 12.323 ;
     RECT  10.944 12.323 12.6 12.371 ;
     RECT  30.816 12.133 30.84 12.517 ;
     RECT  13.776 12.149 14.952 12.563 ;
     RECT  30.336 12.517 30.84 12.719 ;
     RECT  32.64 11.603 32.952 12.719 ;
     RECT  27.24 11.459 27.552 12.725 ;
     RECT  19.968 12.725 20.184 12.767 ;
     RECT  39.36 12.767 39.384 12.789 ;
     RECT  32.448 12.719 32.952 12.803 ;
     RECT  13.776 12.563 14.856 12.805 ;
     RECT  21.84 11.563 22.776 12.819 ;
     RECT  39.36 12.789 39.48 12.851 ;
     RECT  16.44 11.797 17.688 12.853 ;
     RECT  43.44 0.787 43.752 12.853 ;
     RECT  35.952 12.789 35.976 12.877 ;
     RECT  16.44 12.853 18.264 12.901 ;
     RECT  21.84 12.819 23.4 12.907 ;
     RECT  30.336 12.719 30.888 12.907 ;
     RECT  15.984 12.901 18.264 12.947 ;
     RECT  43.44 12.853 44.472 12.947 ;
     RECT  24.864 11.941 24.984 12.959 ;
     RECT  43.44 12.947 43.944 12.959 ;
     RECT  27.24 12.725 28.248 12.995 ;
     RECT  19.296 12.767 20.184 12.997 ;
     RECT  29.712 12.949 29.736 12.997 ;
     RECT  0.144 11.563 1.08 13.005 ;
     RECT  34.8 12.789 34.824 13.035 ;
     RECT  39.456 12.851 39.48 13.035 ;
     RECT  24.864 12.959 25.656 13.043 ;
     RECT  42.72 12.959 43.944 13.043 ;
     RECT  7.92 12.981 7.944 13.091 ;
     RECT  29.088 12.997 29.736 13.091 ;
     RECT  18.816 12.997 20.232 13.099 ;
     RECT  21.84 12.907 22.92 13.099 ;
     RECT  29.088 13.091 29.64 13.099 ;
     RECT  29.616 13.099 29.64 13.129 ;
     RECT  15.984 12.947 17.736 13.139 ;
     RECT  18.816 13.099 19.992 13.235 ;
     RECT  10.944 12.371 11.736 13.301 ;
     RECT  70.44 0.787 70.752 13.381 ;
     RECT  2.16 13.429 2.184 13.477 ;
     RECT  2.16 13.477 2.28 13.513 ;
     RECT  10.848 13.301 11.736 13.547 ;
     RECT  18.912 13.235 19.992 13.547 ;
     RECT  54.144 11.843 54.552 13.557 ;
     RECT  12.72 12.805 14.856 13.621 ;
     RECT  15.984 13.139 17.688 13.621 ;
     RECT  53.232 13.557 54.552 13.645 ;
     RECT  3.984 13.333 4.008 13.675 ;
     RECT  12.72 13.621 17.688 13.675 ;
     RECT  31.248 12.997 31.272 13.675 ;
     RECT  14.112 13.675 17.688 13.705 ;
     RECT  12.72 13.675 13.128 13.715 ;
     RECT  18.912 13.547 19.896 13.715 ;
     RECT  24.864 13.043 25.464 13.715 ;
     RECT  14.112 13.705 14.904 13.763 ;
     RECT  54.144 13.645 54.552 13.763 ;
     RECT  0.24 13.005 1.08 13.765 ;
     RECT  11.04 13.547 11.736 13.803 ;
     RECT  21.84 13.099 22.68 13.813 ;
     RECT  18.912 13.715 19.56 13.867 ;
     RECT  0.24 13.765 1.176 13.878 ;
     RECT  27.24 12.995 27.552 13.971 ;
     RECT  14.448 13.763 14.904 13.995 ;
     RECT  0.24 13.878 1.128 14.035 ;
     RECT  27.24 13.971 28.488 14.069 ;
     RECT  32.64 12.803 32.952 14.069 ;
     RECT  18.912 13.867 19.368 14.099 ;
     RECT  25.44 13.715 25.464 14.099 ;
     RECT  63.84 14.005 63.864 14.099 ;
     RECT  14.448 13.995 14.808 14.243 ;
     RECT  14.448 14.243 14.472 14.251 ;
     RECT  26.88 14.069 28.488 14.251 ;
     RECT  11.04 13.803 11.448 14.291 ;
     RECT  45.024 14.255 45.048 14.339 ;
     RECT  46.608 14.255 46.632 14.339 ;
     RECT  21.696 13.813 22.68 14.379 ;
     RECT  16.128 13.705 17.688 14.387 ;
     RECT  47.328 14.389 47.352 14.473 ;
     RECT  4.512 14.261 4.536 14.483 ;
     RECT  39.888 14.485 39.912 14.495 ;
     RECT  43.44 13.043 43.944 14.495 ;
     RECT  2.256 13.513 2.28 14.517 ;
     RECT  0.144 14.035 1.128 14.531 ;
     RECT  52.464 14.447 52.488 14.531 ;
     RECT  31.92 14.069 32.952 14.571 ;
     RECT  39.36 14.495 39.912 14.571 ;
     RECT  42.336 13.477 42.36 14.571 ;
     RECT  39.36 14.571 39.384 14.579 ;
     RECT  43.44 14.495 43.992 14.579 ;
     RECT  21.696 14.379 22.152 14.629 ;
     RECT  62.16 14.581 62.184 14.665 ;
     RECT  70.44 13.381 71.4 14.725 ;
     RECT  57.024 14.303 57.048 14.739 ;
     RECT  61.584 14.677 61.608 14.763 ;
     RECT  27.24 14.251 28.488 14.773 ;
     RECT  56.112 14.739 57.048 14.827 ;
     RECT  16.128 14.387 17.16 14.831 ;
     RECT  12.528 13.941 12.552 14.837 ;
     RECT  0.144 14.531 1.08 14.867 ;
     RECT  51.888 14.533 51.912 14.869 ;
     RECT  5.64 11.651 5.952 14.879 ;
     RECT  38.04 11.459 38.352 14.879 ;
     RECT  9.12 14.837 9.24 14.901 ;
     RECT  18.864 14.831 18.888 14.915 ;
     RECT  9.12 14.901 9.576 14.963 ;
     RECT  37.104 14.879 38.568 14.963 ;
     RECT  51.312 14.869 51.912 14.963 ;
     RECT  2.256 14.517 2.472 14.965 ;
     RECT  9.216 14.963 9.576 14.965 ;
     RECT  11.04 14.291 11.352 14.965 ;
     RECT  9.216 14.965 9.624 15.019 ;
     RECT  12.528 14.837 13.464 15.019 ;
     RECT  59.64 0.787 59.952 15.061 ;
     RECT  65.04 0.787 65.352 15.061 ;
     RECT  9.552 15.019 9.624 15.071 ;
     RECT  24.528 14.837 24.552 15.107 ;
     RECT  9.552 15.071 9.672 15.147 ;
     RECT  23.376 14.831 23.4 15.147 ;
     RECT  34.848 14.965 34.872 15.147 ;
     RECT  37.2 14.963 38.568 15.147 ;
     RECT  64.8 15.061 65.352 15.147 ;
     RECT  0.144 14.867 0.984 15.155 ;
     RECT  57.024 14.827 57.048 15.251 ;
     RECT  10.944 14.965 11.352 15.349 ;
     RECT  21.456 14.629 22.152 15.397 ;
     RECT  5.64 14.879 6.84 15.413 ;
     RECT  10.704 15.349 11.352 15.413 ;
     RECT  12.528 15.019 12.552 15.413 ;
     RECT  27.24 14.773 28.536 15.443 ;
     RECT  37.2 15.147 38.352 15.443 ;
     RECT  15.984 14.831 17.16 15.477 ;
     RECT  10.704 15.413 12.552 15.491 ;
     RECT  70.44 14.725 71.88 15.493 ;
     RECT  3.984 15.093 4.008 15.539 ;
     RECT  50.208 15.413 50.232 15.599 ;
     RECT  15.408 15.477 17.16 15.625 ;
     RECT  9.6 15.147 9.672 15.637 ;
     RECT  10.704 15.491 12.024 15.637 ;
     RECT  13.632 15.541 14.28 15.637 ;
     RECT  15.408 15.625 15.432 15.637 ;
     RECT  70.44 15.493 72.552 15.637 ;
     RECT  18.912 15.413 18.936 15.659 ;
     RECT  27.24 15.443 28.488 15.659 ;
     RECT  48.84 0.787 49.152 15.699 ;
     RECT  50.16 15.599 50.232 15.699 ;
     RECT  48.84 15.699 50.232 15.787 ;
     RECT  34.128 15.829 34.152 15.915 ;
     RECT  70.44 15.637 72.696 15.971 ;
     RECT  20.592 15.397 22.152 15.973 ;
     RECT  2.256 14.965 2.856 15.989 ;
     RECT  54.24 13.763 54.552 15.989 ;
     RECT  13.632 15.637 15.432 16.019 ;
     RECT  27.24 15.659 27.912 16.019 ;
     RECT  50.208 15.787 50.232 16.019 ;
     RECT  51.312 14.963 51.336 16.019 ;
     RECT  31.344 15.349 31.368 16.031 ;
     RECT  43.44 14.579 43.752 16.031 ;
     RECT  46.752 15.989 46.776 16.031 ;
     RECT  27.24 16.019 27.552 16.053 ;
     RECT  31.344 16.031 31.416 16.053 ;
     RECT  43.44 16.031 44.52 16.053 ;
     RECT  45.792 16.031 47.4 16.053 ;
     RECT  65.04 15.147 65.352 16.053 ;
     RECT  70.44 15.971 72.552 16.067 ;
     RECT  16.44 15.625 17.16 16.069 ;
     RECT  18.48 16.021 18.504 16.069 ;
     RECT  42.768 16.053 44.52 16.115 ;
     RECT  13.632 16.019 14.856 16.117 ;
     RECT  26.784 16.053 27.552 16.117 ;
     RECT  59.184 15.061 59.952 16.117 ;
     RECT  0.24 15.155 0.984 16.147 ;
     RECT  54.144 15.989 54.552 16.175 ;
     RECT  26.064 16.117 27.552 16.211 ;
     RECT  53.568 16.175 54.552 16.213 ;
     RECT  2.256 15.989 3.96 16.223 ;
     RECT  38.04 15.443 38.352 16.223 ;
     RECT  53.568 16.213 55.32 16.259 ;
     RECT  45.792 16.053 47.496 16.299 ;
     RECT  54.144 16.259 55.32 16.299 ;
     RECT  56.88 15.989 56.904 16.333 ;
     RECT  59.184 16.117 60.072 16.333 ;
     RECT  0.144 16.147 0.984 16.339 ;
     RECT  16.44 16.069 18.504 16.355 ;
     RECT  38.04 16.223 38.472 16.373 ;
     RECT  5.64 15.413 6.888 16.427 ;
     RECT  51.888 16.357 51.912 16.441 ;
     RECT  16.44 16.355 18.408 16.491 ;
     RECT  31.344 16.053 31.512 16.491 ;
     RECT  20.544 15.973 22.152 16.499 ;
     RECT  45.792 16.299 46.872 16.499 ;
     RECT  18.192 16.491 18.408 16.547 ;
     RECT  32.64 14.571 32.952 16.565 ;
     RECT  18.192 16.547 18.312 16.585 ;
     RECT  9.6 15.637 12.024 16.595 ;
     RECT  2.208 16.223 3.96 16.691 ;
     RECT  32.208 16.565 33.144 16.691 ;
     RECT  54.144 16.299 54.552 16.691 ;
     RECT  38.04 16.373 38.808 16.693 ;
     RECT  32.64 16.691 33.144 16.739 ;
     RECT  10.176 16.595 12.024 16.757 ;
     RECT  13.104 16.117 14.856 16.757 ;
     RECT  62.16 16.693 62.184 16.787 ;
     RECT  45.552 16.693 45.576 16.789 ;
     RECT  59.64 16.333 60.072 16.789 ;
     RECT  34.752 16.629 34.872 16.875 ;
     RECT  45.024 16.789 45.576 16.875 ;
     RECT  59.64 16.789 60.456 16.875 ;
     RECT  18.192 16.585 18.216 16.883 ;
     RECT  10.176 16.757 14.856 16.931 ;
     RECT  20.544 16.499 20.568 16.979 ;
     RECT  38.04 16.693 38.856 17.003 ;
     RECT  45.552 16.875 45.576 17.003 ;
     RECT  26.544 16.211 27.552 17.013 ;
     RECT  34.752 16.875 34.824 17.013 ;
     RECT  42.768 16.115 43.848 17.013 ;
     RECT  38.04 17.003 38.808 17.029 ;
     RECT  30.864 16.693 30.888 17.067 ;
     RECT  32.64 16.739 33.096 17.067 ;
     RECT  34.224 17.013 34.824 17.075 ;
     RECT  46.848 16.499 46.872 17.101 ;
     RECT  24.528 17.013 24.552 17.123 ;
     RECT  42.384 17.013 43.848 17.123 ;
     RECT  57.024 16.949 57.048 17.123 ;
     RECT  0.144 16.339 1.032 17.125 ;
     RECT  2.208 16.691 3.432 17.125 ;
     RECT  36.768 17.029 38.808 17.131 ;
     RECT  10.176 16.931 13.704 17.171 ;
     RECT  43.344 17.123 43.848 17.171 ;
     RECT  37.056 17.131 38.808 17.219 ;
     RECT  0.144 17.125 3.432 17.315 ;
     RECT  70.44 16.067 72.36 17.365 ;
     RECT  65.04 16.053 65.592 17.461 ;
     RECT  48.84 15.787 49.152 17.605 ;
     RECT  70.44 17.365 72.408 17.605 ;
     RECT  26.544 17.013 28.248 17.619 ;
     RECT  54.24 16.691 54.552 17.619 ;
     RECT  10.944 17.171 13.704 17.643 ;
     RECT  65.04 17.461 66.168 17.643 ;
     RECT  13.008 17.643 13.704 17.651 ;
     RECT  25.872 17.619 28.248 17.651 ;
     RECT  5.64 16.427 5.952 17.653 ;
     RECT  14.832 16.931 14.856 17.653 ;
     RECT  25.872 17.651 27.552 17.653 ;
     RECT  47.184 17.605 47.208 17.653 ;
     RECT  54.24 17.619 55.128 17.653 ;
     RECT  47.184 17.653 47.784 17.707 ;
     RECT  54 17.653 55.128 17.707 ;
     RECT  28.992 17.653 29.112 17.737 ;
     RECT  14.832 17.653 14.952 17.747 ;
     RECT  48.84 17.605 49.704 17.747 ;
     RECT  51.984 17.589 52.008 17.747 ;
     RECT  56.448 17.653 56.472 17.747 ;
     RECT  9.648 17.557 9.672 17.893 ;
     RECT  25.776 17.653 27.552 17.893 ;
     RECT  29.088 17.737 29.112 17.939 ;
     RECT  13.056 17.651 13.704 17.989 ;
     RECT  16.44 16.491 17.112 17.989 ;
     RECT  25.68 17.893 27.552 18.035 ;
     RECT  5.64 17.653 6.312 18.037 ;
     RECT  20.496 17.077 20.52 18.085 ;
     RECT  47.712 17.707 47.784 18.085 ;
     RECT  48.84 17.747 49.152 18.085 ;
     RECT  10.944 17.643 11.976 18.165 ;
     RECT  14.928 17.747 14.952 18.165 ;
     RECT  0.24 17.315 3.432 18.181 ;
     RECT  9.072 17.893 9.672 18.181 ;
     RECT  58.224 18.085 58.248 18.181 ;
     RECT  16.44 17.989 17.832 18.219 ;
     RECT  25.68 18.035 25.8 18.219 ;
     RECT  54 17.707 54.936 18.219 ;
     RECT  57.024 18.085 57.048 18.219 ;
     RECT  13.056 17.989 13.8 18.227 ;
     RECT  58.128 18.181 58.248 18.227 ;
     RECT  5.64 18.037 7.128 18.229 ;
     RECT  21.84 16.499 22.152 18.229 ;
     RECT  24 17.509 24.024 18.229 ;
     RECT  32.64 17.067 32.952 18.229 ;
     RECT  34.224 17.075 34.248 18.229 ;
     RECT  43.44 17.171 43.752 18.229 ;
     RECT  10.8 18.165 11.976 18.275 ;
     RECT  14.928 18.165 15.048 18.275 ;
     RECT  20.496 18.085 20.568 18.275 ;
     RECT  8.784 18.181 9.672 18.283 ;
     RECT  13.056 18.227 13.704 18.283 ;
     RECT  16.44 18.219 17.736 18.323 ;
     RECT  32.64 18.229 34.248 18.323 ;
     RECT  43.44 18.229 44.712 18.323 ;
     RECT  0.24 18.181 3.768 18.335 ;
     RECT  40.944 18.259 40.968 18.347 ;
     RECT  54 18.219 54.552 18.357 ;
     RECT  0.24 18.335 3.96 18.373 ;
     RECT  53.856 18.357 54.552 18.373 ;
     RECT  30.24 18.229 30.264 18.467 ;
     RECT  38.04 17.219 38.808 18.485 ;
     RECT  5.64 18.229 7.464 18.515 ;
     RECT  21.84 18.229 24.024 18.539 ;
     RECT  0.144 18.373 3.96 18.549 ;
     RECT  13.056 18.283 13.656 18.603 ;
     RECT  62.736 18.527 62.76 18.611 ;
     RECT  70.44 17.605 72.456 18.659 ;
     RECT  51.888 18.181 51.912 18.709 ;
     RECT  0.144 18.549 4.008 18.731 ;
     RECT  5.64 18.515 6.888 18.731 ;
     RECT  8.88 18.283 9.672 18.731 ;
     RECT  35.376 18.661 35.544 18.741 ;
     RECT  35.376 18.741 36.456 18.757 ;
     RECT  37.632 18.485 38.808 18.757 ;
     RECT  43.44 18.323 43.752 18.757 ;
     RECT  0.144 18.731 3.48 18.803 ;
     RECT  62.208 18.719 62.232 18.803 ;
     RECT  34.368 18.421 34.392 18.805 ;
     RECT  35.376 18.757 38.808 18.805 ;
     RECT  47.712 18.085 49.152 18.805 ;
     RECT  50.304 18.421 50.328 18.805 ;
     RECT  47.712 18.805 50.328 18.851 ;
     RECT  51.312 18.709 51.912 18.851 ;
     RECT  34.368 18.805 38.808 18.859 ;
     RECT  59.64 16.875 59.952 18.863 ;
     RECT  18.816 18.757 18.84 18.864 ;
     RECT  48.672 18.851 50.328 18.864 ;
     RECT  23.904 18.539 24.024 18.899 ;
     RECT  32.64 18.323 33.048 18.899 ;
     RECT  59.28 18.863 59.952 18.947 ;
     RECT  13.104 18.603 13.656 18.987 ;
     RECT  13.152 18.987 13.656 18.995 ;
     RECT  48.672 18.864 49.56 18.995 ;
     RECT  58.128 18.227 58.152 18.995 ;
     RECT  48.672 18.995 49.512 19.021 ;
     RECT  63.456 18.933 63.48 19.021 ;
     RECT  9.072 18.731 9.192 19.043 ;
     RECT  32.64 18.899 32.952 19.045 ;
     RECT  65.04 17.643 65.352 19.045 ;
     RECT  53.568 18.373 54.552 19.081 ;
     RECT  31.968 19.045 32.952 19.129 ;
     RECT  64.416 19.045 65.352 19.129 ;
     RECT  42.192 18.997 42.216 19.189 ;
     RECT  43.344 18.757 43.752 19.189 ;
     RECT  42.192 19.189 43.752 19.235 ;
     RECT  40.464 18.911 40.488 19.237 ;
     RECT  34.8 18.859 38.808 19.243 ;
     RECT  54.144 19.081 54.552 19.253 ;
     RECT  23.904 18.899 23.928 19.273 ;
     RECT  13.152 18.995 13.176 19.283 ;
     RECT  20.544 18.275 20.568 19.379 ;
     RECT  29.472 18.565 29.64 19.379 ;
     RECT  16.44 18.323 16.752 19.381 ;
     RECT  21.84 18.539 22.824 19.381 ;
     RECT  39.888 19.237 40.488 19.381 ;
     RECT  42.72 19.235 43.752 19.381 ;
     RECT  51.312 18.851 51.336 19.427 ;
     RECT  54.144 19.253 55.32 19.427 ;
     RECT  27.24 18.035 27.552 19.445 ;
     RECT  42.72 19.381 43.848 19.445 ;
     RECT  45.024 19.317 45.048 19.445 ;
     RECT  66.72 19.381 66.744 19.475 ;
     RECT  29.472 19.379 29.496 19.477 ;
     RECT  21.168 19.381 22.824 19.509 ;
     RECT  35.952 19.243 38.808 19.525 ;
     RECT  39.888 19.381 40.872 19.525 ;
     RECT  47.328 19.445 47.352 19.533 ;
     RECT  54.144 19.427 54.552 19.563 ;
     RECT  57.6 19.445 57.624 19.571 ;
     RECT  26.736 19.445 27.552 19.603 ;
     RECT  28.56 19.477 29.496 19.603 ;
     RECT  21.168 19.509 23.832 19.619 ;
     RECT  64.848 19.129 65.352 19.619 ;
     RECT  70.44 18.659 70.752 19.621 ;
     RECT  71.808 18.659 72.456 19.621 ;
     RECT  35.952 19.525 40.872 19.627 ;
     RECT  21.84 19.619 23.832 19.667 ;
     RECT  26.736 19.603 29.496 19.667 ;
     RECT  14.928 18.275 14.952 19.669 ;
     RECT  65.04 19.619 65.352 19.669 ;
     RECT  21.84 19.667 22.824 19.691 ;
     RECT  34.8 19.243 34.968 19.755 ;
     RECT  48.84 19.021 49.512 19.755 ;
     RECT  65.04 19.669 65.592 19.755 ;
     RECT  42.72 19.445 45.048 19.763 ;
     RECT  59.64 18.947 59.952 19.765 ;
     RECT  70.44 19.621 72.456 19.765 ;
     RECT  62.16 19.637 62.184 19.829 ;
     RECT  59.64 19.765 60.072 19.849 ;
     RECT  26.736 19.667 29.112 19.871 ;
     RECT  35.952 19.627 40.008 19.883 ;
     RECT  42.72 19.763 43.752 19.883 ;
     RECT  0.144 18.803 2.856 19.893 ;
     RECT  40.992 19.813 41.112 19.897 ;
     RECT  6.96 19.637 7.128 19.907 ;
     RECT  11.04 18.275 11.976 19.909 ;
     RECT  23.808 19.667 23.832 19.947 ;
     RECT  34.8 19.755 34.824 19.947 ;
     RECT  35.952 19.883 39.384 19.947 ;
     RECT  9.072 19.043 9.096 19.955 ;
     RECT  41.088 19.897 41.112 19.955 ;
     RECT  62.16 19.829 62.424 19.957 ;
     RECT  61.536 19.957 62.424 20.003 ;
     RECT  70.44 19.765 72.504 20.015 ;
     RECT  0.048 19.893 2.856 20.021 ;
     RECT  45.024 19.763 45.048 20.051 ;
     RECT  61.536 20.003 61.608 20.051 ;
     RECT  0.048 20.021 2.952 20.053 ;
     RECT  14.928 19.669 15 20.063 ;
     RECT  16.44 19.381 16.872 20.085 ;
     RECT  70.44 20.015 72.696 20.099 ;
     RECT  14.208 20.063 15 20.149 ;
     RECT  18.864 19.189 18.888 20.149 ;
     RECT  18.864 20.149 18.936 20.197 ;
     RECT  48.84 19.755 49.152 20.207 ;
     RECT  56.448 20.149 56.472 20.243 ;
     RECT  18.672 20.197 18.936 20.331 ;
     RECT  35.952 19.947 38.664 20.331 ;
     RECT  13.68 20.149 15 20.339 ;
     RECT  26.688 19.871 29.112 20.339 ;
     RECT  34.224 20.149 34.248 20.339 ;
     RECT  0.048 20.053 3 20.371 ;
     RECT  35.952 20.331 36.024 20.389 ;
     RECT  14.112 20.339 15 20.395 ;
     RECT  26.688 20.339 28.584 20.447 ;
     RECT  35.904 20.389 36.024 20.459 ;
     RECT  37.152 20.331 38.664 20.459 ;
     RECT  19.968 19.909 19.992 20.469 ;
     RECT  46.272 20.005 46.296 20.469 ;
     RECT  35.904 20.459 35.928 20.473 ;
     RECT  37.152 20.459 38.472 20.523 ;
     RECT  26.208 20.447 28.584 20.531 ;
     RECT  70.44 20.099 72.504 20.531 ;
     RECT  46.176 20.469 46.296 20.579 ;
     RECT  51.888 20.021 51.912 20.579 ;
     RECT  16.44 20.085 17.688 20.581 ;
     RECT  18.672 20.331 18.792 20.581 ;
     RECT  26.784 20.531 28.584 20.587 ;
     RECT  0.048 20.371 3.144 20.597 ;
     RECT  19.968 20.469 20.568 20.627 ;
     RECT  54.24 19.563 54.552 20.629 ;
     RECT  0.048 20.597 3.432 20.651 ;
     RECT  9.696 20.341 9.72 20.675 ;
     RECT  65.04 19.755 65.496 20.675 ;
     RECT  16.44 20.581 18.792 20.715 ;
     RECT  54.144 20.629 54.552 20.715 ;
     RECT  0.144 20.651 3.432 20.723 ;
     RECT  48.48 20.207 49.152 20.771 ;
     RECT  47.328 20.533 47.352 20.789 ;
     RECT  50.736 20.725 50.76 20.789 ;
     RECT  37.152 20.523 38.352 20.819 ;
     RECT  32.64 19.129 32.952 20.853 ;
     RECT  58.128 20.783 58.152 20.867 ;
     RECT  45.168 20.789 45.192 20.877 ;
     RECT  14.976 20.395 15 20.907 ;
     RECT  27.12 20.587 28.584 20.907 ;
     RECT  63.84 20.821 63.864 20.907 ;
     RECT  21.84 19.691 22.152 20.965 ;
     RECT  43.44 19.883 43.752 20.965 ;
     RECT  59.64 19.849 59.952 20.965 ;
     RECT  7.536 20.725 7.56 21.013 ;
     RECT  7.536 21.013 8.52 21.035 ;
     RECT  18.192 20.715 18.792 21.049 ;
     RECT  40.416 21.061 40.44 21.075 ;
     RECT  61.584 20.051 61.608 21.075 ;
     RECT  31.824 20.853 32.952 21.109 ;
     RECT  58.656 20.965 59.952 21.109 ;
     RECT  25.104 20.437 25.128 21.155 ;
     RECT  55.728 20.485 55.752 21.155 ;
     RECT  63.264 20.965 63.672 21.163 ;
     RECT  54.24 20.715 54.552 21.173 ;
     RECT  31.344 21.109 32.952 21.193 ;
     RECT  31.824 21.193 32.952 21.203 ;
     RECT  5.64 18.731 5.952 21.205 ;
     RECT  58.656 21.109 60.216 21.215 ;
     RECT  61.584 21.075 61.944 21.215 ;
     RECT  5.136 21.205 5.952 21.237 ;
     RECT  10.8 19.909 11.976 21.237 ;
     RECT  31.872 21.203 32.952 21.301 ;
     RECT  58.656 21.215 61.944 21.301 ;
     RECT  54.24 21.173 54.888 21.347 ;
     RECT  43.44 20.965 43.944 21.349 ;
     RECT  48.84 20.771 49.152 21.349 ;
     RECT  21.84 20.965 22.248 21.365 ;
     RECT  23.76 21.109 23.832 21.365 ;
     RECT  27.12 20.907 28.536 21.395 ;
     RECT  58.656 21.301 62.184 21.395 ;
     RECT  25.344 21.331 25.464 21.419 ;
     RECT  48.84 21.349 49.272 21.433 ;
     RECT  31.872 21.301 33.24 21.443 ;
     RECT  27.12 21.395 27.672 21.453 ;
     RECT  3.936 21.301 3.96 21.459 ;
     RECT  5.136 21.237 6.984 21.459 ;
     RECT  46.752 20.789 47.352 21.483 ;
     RECT  10.08 21.237 11.976 21.539 ;
     RECT  3.936 21.459 6.984 21.547 ;
     RECT  30.816 21.365 30.84 21.547 ;
     RECT  58.656 21.395 61.608 21.547 ;
     RECT  5.136 21.547 6.984 21.577 ;
     RECT  5.136 21.577 6.072 21.587 ;
     RECT  25.44 21.419 25.464 21.587 ;
     RECT  47.328 21.483 47.352 21.587 ;
     RECT  10.32 21.539 11.976 21.611 ;
     RECT  18.336 21.049 18.792 21.621 ;
     RECT  21.84 21.365 23.832 21.635 ;
     RECT  38.04 20.819 38.352 21.637 ;
     RECT  50.736 20.789 51.384 21.637 ;
     RECT  0.144 20.723 2.616 21.675 ;
     RECT  10.848 21.611 11.976 21.675 ;
     RECT  23.376 21.635 23.832 21.675 ;
     RECT  32.64 21.443 33.24 21.675 ;
     RECT  59.64 21.547 61.608 21.683 ;
     RECT  70.44 20.531 71.832 21.683 ;
     RECT  40.416 21.075 40.776 21.685 ;
     RECT  18.336 21.621 19.368 21.709 ;
     RECT  8.496 21.035 8.52 21.731 ;
     RECT  38.04 21.637 38.808 21.739 ;
     RECT  57.6 21.551 57.624 21.749 ;
     RECT  40.416 21.685 41.064 21.769 ;
     RECT  0.24 21.675 2.616 21.803 ;
     RECT  40.416 21.769 40.44 21.803 ;
     RECT  71.808 21.683 71.832 21.829 ;
     RECT  53.04 20.917 53.064 21.843 ;
     RECT  0.24 21.803 0.792 21.867 ;
     RECT  55.872 21.791 55.896 21.875 ;
     RECT  57.024 21.749 57.624 21.875 ;
     RECT  2.16 21.803 2.616 21.931 ;
     RECT  18.336 21.709 18.936 21.931 ;
     RECT  20.544 20.627 20.568 21.931 ;
     RECT  13.68 21.637 14.856 21.971 ;
     RECT  11.04 21.675 11.976 21.973 ;
     RECT  69.12 21.733 69.144 21.973 ;
     RECT  0.24 21.867 0.696 21.995 ;
     RECT  2.352 21.931 2.616 21.995 ;
     RECT  34.224 21.637 34.248 21.995 ;
     RECT  8.544 21.813 8.568 22.019 ;
     RECT  32.64 21.675 33.048 22.019 ;
     RECT  69.024 21.973 69.144 22.019 ;
     RECT  18.336 21.931 18.84 22.067 ;
     RECT  63.648 21.163 63.672 22.069 ;
     RECT  65.04 20.675 65.352 22.069 ;
     RECT  71.808 21.829 71.928 22.069 ;
     RECT  18.816 22.067 18.84 22.123 ;
     RECT  21.84 21.635 22.296 22.123 ;
     RECT  57.408 21.875 57.624 22.127 ;
     RECT  63.648 22.069 65.352 22.163 ;
     RECT  43.44 21.349 44.472 22.165 ;
     RECT  65.04 22.163 65.352 22.197 ;
     RECT  14.832 21.971 14.856 22.211 ;
     RECT  57.408 22.127 58.584 22.211 ;
     RECT  69.024 22.019 69.048 22.211 ;
     RECT  43.44 22.165 45.048 22.251 ;
     RECT  50.64 21.637 51.384 22.251 ;
     RECT  57.408 22.211 57.432 22.251 ;
     RECT  59.64 21.683 60.072 22.251 ;
     RECT  61.296 21.683 61.32 22.251 ;
     RECT  63.648 22.163 63.672 22.251 ;
     RECT  52.8 21.843 53.064 22.261 ;
     RECT  11.04 21.973 12.552 22.307 ;
     RECT  51.216 22.251 51.384 22.355 ;
     RECT  65.04 22.197 65.448 22.367 ;
     RECT  16.44 20.715 16.752 22.389 ;
     RECT  35.328 22.319 35.352 22.403 ;
     RECT  27.24 21.453 27.672 22.419 ;
     RECT  65.04 22.367 66.168 22.451 ;
     RECT  13.632 22.165 13.656 22.453 ;
     RECT  23.904 22.197 23.928 22.453 ;
     RECT  43.44 22.251 44.424 22.453 ;
     RECT  65.04 22.451 65.448 22.499 ;
     RECT  2.88 22.165 3.672 22.507 ;
     RECT  26.352 22.419 28.392 22.507 ;
     RECT  13.104 22.453 13.656 22.537 ;
     RECT  36.528 22.453 36.552 22.537 ;
     RECT  71.808 22.069 72.36 22.549 ;
     RECT  51.216 22.355 51.24 22.643 ;
     RECT  58.56 22.211 58.584 22.643 ;
     RECT  0.24 21.995 0.648 22.693 ;
     RECT  42.768 22.453 44.424 22.787 ;
     RECT  11.04 22.307 11.976 22.835 ;
     RECT  15.984 22.389 16.752 22.835 ;
     RECT  43.44 22.787 44.424 22.835 ;
     RECT  52.464 22.261 53.064 22.837 ;
     RECT  41.616 21.941 41.64 22.943 ;
     RECT  0.144 22.693 0.648 22.965 ;
     RECT  3.648 22.507 3.672 23.019 ;
     RECT  52.368 22.837 53.064 23.019 ;
     RECT  47.808 22.943 47.832 23.027 ;
     RECT  11.04 22.835 11.88 23.029 ;
     RECT  41.616 22.943 42.408 23.029 ;
     RECT  61.44 22.965 61.464 23.029 ;
     RECT  23.904 22.453 24.024 23.075 ;
     RECT  10.272 23.029 11.88 23.083 ;
     RECT  35.568 22.837 35.592 23.083 ;
     RECT  41.472 23.029 42.408 23.113 ;
     RECT  61.44 23.029 62.664 23.123 ;
     RECT  41.616 23.113 42.408 23.171 ;
     RECT  52.464 23.019 53.064 23.171 ;
     RECT  71.808 22.549 72.456 23.219 ;
     RECT  62.64 23.123 62.664 23.267 ;
     RECT  68.976 23.077 69 23.267 ;
     RECT  61.44 23.123 61.464 23.315 ;
     RECT  38.04 21.739 38.352 23.317 ;
     RECT  59.64 22.251 59.952 23.317 ;
     RECT  41.616 23.171 41.64 23.363 ;
     RECT  5.64 21.587 6.072 23.509 ;
     RECT  40.32 23.317 40.344 23.509 ;
     RECT  14.832 23.269 14.856 23.541 ;
     RECT  10.272 23.083 11.352 23.595 ;
     RECT  40.32 23.509 40.44 23.595 ;
     RECT  14.832 23.541 15.432 23.651 ;
     RECT  5.64 23.509 6.888 23.653 ;
     RECT  30.816 23.605 30.84 23.653 ;
     RECT  13.632 22.537 13.656 23.663 ;
     RECT  14.832 23.651 14.952 23.663 ;
     RECT  32.64 22.019 32.952 23.663 ;
     RECT  0.144 22.965 0.696 23.669 ;
     RECT  21.84 22.123 22.152 23.669 ;
     RECT  26.208 23.605 26.232 23.669 ;
     RECT  5.64 23.653 6.984 23.699 ;
     RECT  26.16 23.669 26.232 23.699 ;
     RECT  0.144 23.669 0.792 23.701 ;
     RECT  37.92 23.317 38.352 23.711 ;
     RECT  54.24 21.347 54.552 23.711 ;
     RECT  32.64 23.663 33.192 23.747 ;
     RECT  30.816 23.653 30.888 23.763 ;
     RECT  0.048 23.701 0.792 23.795 ;
     RECT  24 23.075 24.024 23.795 ;
     RECT  37.92 23.711 38.808 23.795 ;
     RECT  53.568 23.711 54.552 23.795 ;
     RECT  48.84 21.433 49.152 23.827 ;
     RECT  56.736 23.701 56.76 23.845 ;
     RECT  3.408 23.541 3.432 23.851 ;
     RECT  18.24 23.797 18.264 23.881 ;
     RECT  44.976 23.797 45 23.881 ;
     RECT  6.96 23.699 6.984 23.891 ;
     RECT  13.632 23.663 14.952 23.891 ;
     RECT  30.816 23.763 31.56 23.903 ;
     RECT  0.048 23.795 0.648 23.915 ;
     RECT  48.84 23.827 49.944 23.915 ;
     RECT  19.968 23.845 19.992 23.929 ;
     RECT  56.736 23.845 57 23.929 ;
     RECT  30.192 23.903 31.56 23.939 ;
     RECT  43.44 22.835 43.896 23.941 ;
     RECT  2.544 23.903 2.712 23.987 ;
     RECT  30.192 23.939 30.216 23.987 ;
     RECT  59.52 23.317 59.952 23.989 ;
     RECT  13.632 23.891 14.616 24.083 ;
     RECT  46.08 23.317 46.104 24.083 ;
     RECT  59.52 23.989 60.456 24.083 ;
     RECT  2.688 23.987 2.712 24.107 ;
     RECT  26.16 23.699 26.184 24.131 ;
     RECT  24.48 24.085 24.504 24.171 ;
     RECT  54.144 23.795 54.552 24.171 ;
     RECT  37.92 23.795 38.76 24.211 ;
     RECT  21.84 23.669 22.824 24.229 ;
     RECT  21.648 24.229 22.824 24.277 ;
     RECT  31.296 23.939 31.56 24.277 ;
     RECT  32.64 23.747 32.952 24.277 ;
     RECT  35.328 24.229 35.352 24.277 ;
     RECT  52.464 23.171 52.488 24.277 ;
     RECT  37.392 24.211 38.76 24.299 ;
     RECT  40.224 24.211 40.248 24.299 ;
     RECT  43.104 23.941 43.896 24.309 ;
     RECT  21.648 24.277 22.92 24.313 ;
     RECT  35.328 24.277 36.216 24.313 ;
     RECT  72.384 23.219 72.456 24.323 ;
     RECT  21.84 24.313 22.92 24.363 ;
     RECT  31.296 24.277 32.952 24.363 ;
     RECT  51.84 24.277 52.488 24.363 ;
     RECT  43.104 24.309 44.472 24.371 ;
     RECT  48.84 23.915 49.152 24.373 ;
     RECT  13.632 24.083 13.848 24.403 ;
     RECT  12.816 24.403 13.848 24.427 ;
     RECT  36.192 24.313 36.216 24.427 ;
     RECT  12.816 24.427 13.128 24.491 ;
     RECT  31.296 24.363 31.32 24.505 ;
     RECT  43.44 24.371 44.472 24.505 ;
     RECT  70.44 21.683 70.752 24.613 ;
     RECT  50.736 24.517 50.76 24.659 ;
     RECT  38.04 24.299 38.76 24.697 ;
     RECT  70.44 24.613 70.968 24.709 ;
     RECT  65.04 22.499 65.352 24.815 ;
     RECT  54.24 24.171 54.552 24.863 ;
     RECT  0.144 23.915 0.648 24.885 ;
     RECT  54.24 24.863 54.648 24.885 ;
     RECT  65.04 24.815 65.592 24.899 ;
     RECT  72.432 24.323 72.456 24.899 ;
     RECT  32.544 24.363 32.952 24.909 ;
     RECT  55.968 24.373 56.616 24.939 ;
     RECT  70.44 24.709 71.064 24.947 ;
     RECT  28.608 24.901 28.632 25.003 ;
     RECT  46.512 24.901 46.536 25.003 ;
     RECT  62.976 24.915 63 25.003 ;
     RECT  25.632 24.949 25.752 25.033 ;
     RECT  18.384 24.979 18.408 25.067 ;
     RECT  27.24 22.507 27.552 25.077 ;
     RECT  59.64 24.083 59.952 25.077 ;
     RECT  0.144 24.885 0.696 25.091 ;
     RECT  19.92 25.007 19.944 25.091 ;
     RECT  25.728 25.033 25.752 25.091 ;
     RECT  15.408 25.055 15.432 25.139 ;
     RECT  23.808 25.055 23.832 25.139 ;
     RECT  13.104 24.491 13.128 25.225 ;
     RECT  59.64 25.077 60.072 25.333 ;
     RECT  62.688 25.299 62.712 25.387 ;
     RECT  70.44 24.947 70.872 25.619 ;
     RECT  21.84 24.363 22.152 25.683 ;
     RECT  8.496 25.631 8.52 25.715 ;
     RECT  58.32 24.373 58.344 25.715 ;
     RECT  65.04 24.899 65.352 25.717 ;
     RECT  47.856 24.373 49.152 25.781 ;
     RECT  67.248 24.949 67.272 25.781 ;
     RECT  64.368 25.717 65.352 25.801 ;
     RECT  52.464 24.363 52.488 25.823 ;
     RECT  50.88 25.717 50.904 25.845 ;
     RECT  47.808 25.781 49.152 25.861 ;
     RECT  50.16 25.845 50.904 25.861 ;
     RECT  52.224 25.823 52.488 25.907 ;
     RECT  28.992 25.845 29.016 25.909 ;
     RECT  68.976 24.661 69 25.957 ;
     RECT  70.44 25.619 70.752 25.957 ;
     RECT  0.144 25.091 0.648 25.963 ;
     RECT  46.896 25.861 50.904 25.963 ;
     RECT  52.368 25.907 52.488 25.963 ;
     RECT  28.992 25.909 29.688 25.993 ;
     RECT  28.992 25.993 29.016 26.003 ;
     RECT  52.416 25.963 52.488 26.005 ;
     RECT  68.976 25.957 70.752 26.041 ;
     RECT  52.416 26.005 52.536 26.147 ;
     RECT  27.12 25.077 27.552 26.149 ;
     RECT  23.376 25.717 23.4 26.159 ;
     RECT  52.416 26.147 52.44 26.185 ;
     RECT  26.112 26.131 26.136 26.197 ;
     RECT  27.12 26.149 27.768 26.197 ;
     RECT  21.312 25.683 22.152 26.219 ;
     RECT  26.112 26.197 27.768 26.219 ;
     RECT  26.784 26.219 27.768 26.233 ;
     RECT  30.288 26.149 30.312 26.233 ;
     RECT  23.328 26.159 23.4 26.243 ;
     RECT  47.856 25.963 50.904 26.243 ;
     RECT  67.248 25.781 67.848 26.243 ;
     RECT  64.944 25.801 65.352 26.283 ;
     RECT  5.64 23.699 5.952 26.293 ;
     RECT  48.84 26.243 50.904 26.341 ;
     RECT  38.04 24.697 38.352 26.357 ;
     RECT  23.904 26.293 23.928 26.377 ;
     RECT  26.784 26.233 27.552 26.387 ;
     RECT  63.84 26.293 63.864 26.387 ;
     RECT  14.352 26.293 14.376 26.389 ;
     RECT  32.64 24.909 32.952 26.437 ;
     RECT  54.24 24.885 54.792 26.437 ;
     RECT  57.6 26.399 57.624 26.437 ;
     RECT  13.104 26.389 13.128 26.475 ;
     RECT  18.672 26.341 18.696 26.483 ;
     RECT  38.04 26.357 39.048 26.483 ;
     RECT  57.024 26.437 57.624 26.483 ;
     RECT  65.04 26.283 65.352 26.485 ;
     RECT  53.664 26.437 54.792 26.515 ;
     RECT  40.848 26.357 40.872 26.531 ;
     RECT  48.84 26.341 51.096 26.531 ;
     RECT  11.04 23.595 11.352 26.533 ;
     RECT  34.176 26.341 34.2 26.533 ;
     RECT  53.664 26.515 55.704 26.533 ;
     RECT  16.44 22.835 16.752 26.549 ;
     RECT  2.88 26.293 2.904 26.581 ;
     RECT  10.944 26.533 11.352 26.591 ;
     RECT  14.352 26.389 15.192 26.603 ;
     RECT  19.728 26.165 19.752 26.603 ;
     RECT  53.568 26.533 55.704 26.603 ;
     RECT  57.024 26.483 57.048 26.603 ;
     RECT  10.944 26.591 11.448 26.613 ;
     RECT  40.416 26.533 40.44 26.617 ;
     RECT  53.568 26.603 54.792 26.617 ;
     RECT  2.256 26.581 2.904 26.627 ;
     RECT  5.64 26.293 6.888 26.627 ;
     RECT  14.352 26.603 14.376 26.627 ;
     RECT  68.976 26.041 69 26.627 ;
     RECT  33.984 26.533 34.2 26.675 ;
     RECT  32.448 26.437 32.952 26.677 ;
     RECT  33.984 26.675 34.008 26.677 ;
     RECT  32.448 26.677 34.008 26.707 ;
     RECT  5.64 26.627 6.072 26.723 ;
     RECT  38.04 26.483 38.808 26.725 ;
     RECT  37.728 26.725 38.808 26.771 ;
     RECT  59.64 25.333 60.456 26.771 ;
     RECT  62.736 26.677 62.76 26.771 ;
     RECT  31.584 26.707 34.008 26.795 ;
     RECT  36.672 26.707 36.696 26.795 ;
     RECT  67.488 26.243 67.848 26.795 ;
     RECT  43.44 24.505 43.752 26.805 ;
     RECT  35.328 26.101 35.352 26.825 ;
     RECT  48.84 26.531 50.232 26.867 ;
     RECT  54.24 26.617 54.792 26.867 ;
     RECT  67.824 26.795 67.848 26.869 ;
     RECT  50.208 26.867 50.232 26.923 ;
     RECT  67.824 26.869 68.424 26.963 ;
     RECT  0.24 25.963 0.648 26.965 ;
     RECT  37.728 26.771 38.568 26.987 ;
     RECT  0.144 26.965 0.648 26.997 ;
     RECT  51.216 26.725 51.24 27.061 ;
     RECT  2.256 26.627 2.28 27.107 ;
     RECT  20.544 27.061 20.568 27.145 ;
     RECT  43.44 26.805 43.944 27.145 ;
     RECT  51.216 27.061 51.336 27.145 ;
     RECT  16.44 26.549 17.64 27.203 ;
     RECT  25.632 27.167 25.656 27.251 ;
     RECT  52.992 27.167 53.016 27.251 ;
     RECT  65.04 26.485 66.168 27.253 ;
     RECT  21.84 26.219 22.152 27.283 ;
     RECT  27.12 26.387 27.552 27.307 ;
     RECT  59.64 26.771 59.952 27.317 ;
     RECT  56.448 27.301 56.472 27.385 ;
     RECT  24.144 27.349 24.168 27.435 ;
     RECT  21.84 27.283 22.392 27.445 ;
     RECT  70.44 26.041 70.752 27.445 ;
     RECT  70.128 27.445 70.752 27.503 ;
     RECT  65.04 27.253 66.216 27.509 ;
     RECT  45.504 27.061 45.528 27.551 ;
     RECT  10.848 26.613 11.448 27.573 ;
     RECT  65.04 27.509 66.792 27.573 ;
     RECT  38.04 26.987 38.568 27.587 ;
     RECT  69.552 27.503 70.752 27.587 ;
     RECT  62.784 26.927 62.808 27.627 ;
     RECT  45.504 27.551 45.576 27.635 ;
     RECT  10.128 27.573 11.736 27.661 ;
     RECT  21.84 27.445 22.824 27.683 ;
     RECT  39.888 27.637 40.008 27.721 ;
     RECT  64.56 27.573 66.792 27.765 ;
     RECT  25.056 27.695 25.08 27.779 ;
     RECT  67.824 26.963 68.232 27.779 ;
     RECT  10.128 27.661 11.352 27.795 ;
     RECT  63.84 27.765 66.792 27.819 ;
     RECT  36.432 27.743 36.456 27.827 ;
     RECT  12.72 27.781 12.744 27.829 ;
     RECT  54.24 26.867 54.552 27.829 ;
     RECT  0.144 26.997 0.696 27.875 ;
     RECT  58.656 27.317 59.952 27.877 ;
     RECT  8.976 27.781 9 27.883 ;
     RECT  56.16 27.781 56.184 27.883 ;
     RECT  48.84 26.867 49.152 27.925 ;
     RECT  12.72 27.829 13.08 27.971 ;
     RECT  21.84 27.683 22.248 27.971 ;
     RECT  57.744 27.877 59.952 27.971 ;
     RECT  63.84 27.819 66.216 27.971 ;
     RECT  68.208 27.779 68.232 27.971 ;
     RECT  45.504 27.635 45.528 28.019 ;
     RECT  0.144 27.875 0.648 28.115 ;
     RECT  10.08 27.795 11.352 28.115 ;
     RECT  47.088 27.509 47.256 28.115 ;
     RECT  70.44 27.587 70.752 28.149 ;
     RECT  72.384 26.581 72.408 28.149 ;
     RECT  52.032 28.213 52.056 28.261 ;
     RECT  16.44 27.203 16.752 28.405 ;
     RECT  27.24 27.307 27.552 28.405 ;
     RECT  51.888 28.261 52.056 28.405 ;
     RECT  26.64 28.405 27.552 28.453 ;
     RECT  48.84 27.925 49.32 28.453 ;
     RECT  50.304 27.685 50.712 28.453 ;
     RECT  59.52 27.971 59.952 28.453 ;
     RECT  61.776 27.829 61.8 28.453 ;
     RECT  12.72 27.971 12.984 28.459 ;
     RECT  56.016 28.165 56.04 28.459 ;
     RECT  57.744 27.971 57.768 28.459 ;
     RECT  68.4 28.261 69.096 28.459 ;
     RECT  9.648 28.405 9.672 28.489 ;
     RECT  16.224 28.405 16.752 28.499 ;
     RECT  34.848 28.405 34.872 28.501 ;
     RECT  31.872 26.795 33.624 28.547 ;
     RECT  63.84 27.971 63.864 28.547 ;
     RECT  34.8 28.501 34.872 28.643 ;
     RECT  38.04 27.587 38.352 28.693 ;
     RECT  39.888 27.721 39.912 28.693 ;
     RECT  54.096 27.829 54.552 28.837 ;
     RECT  48.84 28.453 50.712 28.885 ;
     RECT  51.792 28.405 52.056 28.885 ;
     RECT  38.04 28.693 39.912 28.933 ;
     RECT  43.44 27.145 43.752 28.947 ;
     RECT  20.016 28.453 20.04 28.981 ;
     RECT  21.84 27.971 22.152 28.981 ;
     RECT  26.208 28.453 27.552 28.981 ;
     RECT  65.04 27.971 66.216 28.981 ;
     RECT  42.192 28.981 42.216 29.029 ;
     RECT  43.344 28.947 43.752 29.029 ;
     RECT  70.44 28.149 70.872 29.029 ;
     RECT  12.96 28.459 12.984 29.035 ;
     RECT  14.208 28.933 14.232 29.035 ;
     RECT  19.296 28.981 20.04 29.035 ;
     RECT  59.52 28.453 60.072 29.045 ;
     RECT  61.776 28.453 61.896 29.045 ;
     RECT  16.32 28.499 16.752 29.065 ;
     RECT  19.296 29.035 19.32 29.065 ;
     RECT  21.648 28.981 22.152 29.065 ;
     RECT  21.84 29.065 22.152 29.077 ;
     RECT  68.832 28.459 69.096 29.077 ;
     RECT  70.44 29.029 71.016 29.077 ;
     RECT  53.376 28.837 54.552 29.099 ;
     RECT  64.944 28.981 66.216 29.099 ;
     RECT  34.848 28.643 34.872 29.109 ;
     RECT  46.848 28.501 46.872 29.109 ;
     RECT  48.84 28.885 52.056 29.109 ;
     RECT  64.944 29.099 65.736 29.113 ;
     RECT  2.112 28.741 2.136 29.123 ;
     RECT  0.24 28.115 0.648 29.139 ;
     RECT  20.496 29.077 20.52 29.163 ;
     RECT  23.904 29.029 23.928 29.163 ;
     RECT  29.664 29.029 29.688 29.163 ;
     RECT  31.92 28.547 33.576 29.171 ;
     RECT  38.04 28.933 40.44 29.171 ;
     RECT  0.144 29.139 0.648 29.173 ;
     RECT  48.84 29.109 52.248 29.197 ;
     RECT  16.44 29.065 16.752 29.221 ;
     RECT  10.848 28.115 11.352 29.227 ;
     RECT  59.52 29.045 61.896 29.237 ;
     RECT  18.72 29.173 18.744 29.257 ;
     RECT  68.832 29.077 71.016 29.267 ;
     RECT  59.52 29.237 62.808 29.291 ;
     RECT  68.976 29.267 71.016 29.315 ;
     RECT  62.784 29.291 62.808 29.363 ;
     RECT  29.808 29.301 29.976 29.365 ;
     RECT  0.144 29.173 0.744 29.411 ;
     RECT  10.944 29.227 11.352 29.419 ;
     RECT  72.384 28.149 72.552 29.419 ;
     RECT  46.752 29.109 46.872 29.429 ;
     RECT  11.04 29.419 11.352 29.461 ;
     RECT  8.496 29.423 8.52 29.507 ;
     RECT  11.04 29.461 11.976 29.547 ;
     RECT  26.208 28.981 28.632 29.547 ;
     RECT  29.808 29.365 30.888 29.547 ;
     RECT  48.84 29.197 52.104 29.547 ;
     RECT  69.12 29.315 71.016 29.547 ;
     RECT  34.848 29.109 36.168 29.555 ;
     RECT  21.84 29.077 22.392 29.557 ;
     RECT  32.64 29.171 33.576 29.557 ;
     RECT  53.568 29.099 54.552 29.557 ;
     RECT  59.52 29.291 61.128 29.557 ;
     RECT  32.64 29.557 33.624 29.641 ;
     RECT  27.24 29.547 28.632 29.675 ;
     RECT  56.448 29.221 56.52 29.715 ;
     RECT  42.192 29.029 43.752 29.747 ;
     RECT  63.264 29.663 63.288 29.747 ;
     RECT  59.28 29.557 61.128 29.749 ;
     RECT  53.568 29.557 55.272 29.803 ;
     RECT  56.448 29.715 57.192 29.803 ;
     RECT  0.144 29.411 0.696 29.813 ;
     RECT  48.84 29.547 50.76 29.867 ;
     RECT  64.944 29.113 65.496 29.867 ;
     RECT  69.552 29.547 71.016 29.877 ;
     RECT  25.68 29.749 26.184 29.881 ;
     RECT  32.64 29.641 33.048 29.881 ;
     RECT  58.608 29.749 61.128 29.931 ;
     RECT  25.68 29.881 25.752 29.989 ;
     RECT  65.04 29.867 65.496 29.995 ;
     RECT  58.608 29.931 61.032 30.035 ;
     RECT  15.072 29.971 15.096 30.059 ;
     RECT  25.632 29.989 25.752 30.073 ;
     RECT  16.44 29.221 17.112 30.133 ;
     RECT  34.848 29.555 35.592 30.133 ;
     RECT  13.632 30.005 13.656 30.179 ;
     RECT  48.84 29.867 50.184 30.179 ;
     RECT  59.28 30.035 60.168 30.179 ;
     RECT  38.04 29.171 39.336 30.181 ;
     RECT  25.728 30.073 25.752 30.187 ;
     RECT  46.752 29.429 47.112 30.197 ;
     RECT  52.08 29.547 52.104 30.197 ;
     RECT  53.568 29.803 54.84 30.197 ;
     RECT  14.64 30.133 14.664 30.217 ;
     RECT  16.08 30.133 17.112 30.217 ;
     RECT  34.752 30.133 35.592 30.217 ;
     RECT  35.568 30.217 35.592 30.275 ;
     RECT  37.584 30.181 39.336 30.275 ;
     RECT  0.096 29.813 0.696 30.277 ;
     RECT  9.072 30.239 9.096 30.323 ;
     RECT  52.08 30.197 54.84 30.323 ;
     RECT  59.328 30.179 60.168 30.323 ;
     RECT  46.704 30.197 47.592 30.379 ;
     RECT  66.768 29.877 66.792 30.389 ;
     RECT  20.496 30.325 20.52 30.409 ;
     RECT  44.832 30.325 44.856 30.453 ;
     RECT  32.64 29.881 32.952 30.469 ;
     RECT  56.448 29.803 56.472 30.507 ;
     RECT  52.08 30.323 52.296 30.517 ;
     RECT  42.72 29.747 43.752 30.547 ;
     RECT  44.832 30.453 45.144 30.547 ;
     RECT  51.888 30.517 52.296 30.563 ;
     RECT  31.872 30.469 32.952 30.571 ;
     RECT  46.704 30.379 46.776 30.611 ;
     RECT  48.84 30.179 49.512 30.613 ;
     RECT  11.04 29.547 11.352 30.623 ;
     RECT  39.6 30.547 39.624 30.635 ;
     RECT  72.384 29.419 72.504 30.645 ;
     RECT  37.584 30.275 38.568 30.649 ;
     RECT  66.72 30.389 66.792 30.699 ;
     RECT  51.888 30.563 52.008 30.707 ;
     RECT  42.72 30.547 45.144 30.709 ;
     RECT  46.704 30.611 46.728 30.709 ;
     RECT  42.72 30.709 46.728 30.763 ;
     RECT  37.584 30.649 38.352 30.773 ;
     RECT  69.552 29.877 71.352 30.773 ;
     RECT  51.984 30.707 52.008 30.793 ;
     RECT  27.24 29.675 27.912 30.803 ;
     RECT  67.248 30.805 67.272 30.837 ;
     RECT  69.12 30.773 71.352 30.837 ;
     RECT  72.384 30.645 72.552 30.837 ;
     RECT  16.44 30.217 17.112 30.891 ;
     RECT  18.768 30.133 18.792 30.891 ;
     RECT  21.84 29.557 22.776 30.891 ;
     RECT  67.248 30.837 67.368 30.891 ;
     RECT  37.056 30.773 38.352 30.899 ;
     RECT  10.944 30.623 11.352 30.901 ;
     RECT  69.12 30.837 72.552 30.901 ;
     RECT  67.344 30.891 67.368 30.925 ;
     RECT  10.608 30.901 11.352 30.995 ;
     RECT  58.128 30.373 58.248 30.995 ;
     RECT  65.04 29.995 65.352 31.007 ;
     RECT  19.92 30.959 19.944 31.043 ;
     RECT  55.92 30.959 56.328 31.043 ;
     RECT  64.944 31.007 65.352 31.091 ;
     RECT  0.048 30.277 0.696 31.093 ;
     RECT  0.048 31.093 0.744 31.141 ;
     RECT  16.44 30.891 16.872 31.147 ;
     RECT  42.72 30.763 44.328 31.157 ;
     RECT  68.544 30.901 72.552 31.157 ;
     RECT  10.944 30.995 11.352 31.189 ;
     RECT  21.84 30.891 22.392 31.199 ;
     RECT  24.912 31.093 24.936 31.221 ;
     RECT  53.424 30.323 54.84 31.235 ;
     RECT  68.544 31.157 72.6 31.237 ;
     RECT  0.048 31.141 0.792 31.275 ;
     RECT  53.616 31.235 54.84 31.275 ;
     RECT  2.256 31.141 2.28 31.283 ;
     RECT  21.024 31.199 22.392 31.283 ;
     RECT  29.568 30.997 29.592 31.285 ;
     RECT  21.6 31.283 22.392 31.309 ;
     RECT  23.856 31.221 25.512 31.309 ;
     RECT  59.52 30.323 60.168 31.333 ;
     RECT  68.4 31.237 72.6 31.339 ;
     RECT  47.904 30.613 49.512 31.343 ;
     RECT  50.832 31.333 50.856 31.343 ;
     RECT  12.912 31.285 12.936 31.369 ;
     RECT  18.192 31.285 18.216 31.369 ;
     RECT  23.856 31.309 23.88 31.379 ;
     RECT  27.24 30.803 27.552 31.381 ;
     RECT  10.944 31.189 11.832 31.417 ;
     RECT  59.52 31.333 61.032 31.417 ;
     RECT  34.32 31.221 34.344 31.427 ;
     RECT  47.904 31.343 50.856 31.427 ;
     RECT  36.672 31.349 36.696 31.477 ;
     RECT  65.04 31.091 65.352 31.477 ;
     RECT  45.744 30.763 45.768 31.523 ;
     RECT  36.576 31.477 36.696 31.531 ;
     RECT  56.304 31.043 56.328 31.571 ;
     RECT  57.6 31.535 57.624 31.619 ;
     RECT  42.192 31.157 44.328 31.669 ;
     RECT  29.568 31.285 29.736 31.717 ;
     RECT  30.864 29.547 30.888 31.717 ;
     RECT  5.64 26.723 5.952 31.727 ;
     RECT  36.576 31.531 36.648 31.727 ;
     RECT  38.04 30.899 38.352 31.765 ;
     RECT  54.24 31.275 54.84 31.765 ;
     RECT  36.48 31.727 36.648 31.811 ;
     RECT  32.016 30.571 32.952 31.813 ;
     RECT  50.736 31.427 50.856 31.813 ;
     RECT  5.64 31.727 6.84 31.827 ;
     RECT  8.352 31.733 8.376 31.827 ;
     RECT  47.904 31.427 49.464 31.827 ;
     RECT  29.568 31.717 30.888 31.851 ;
     RECT  41.568 31.669 44.328 31.861 ;
     RECT  5.64 31.827 9.288 31.907 ;
     RECT  56.448 31.733 56.616 31.914 ;
     RECT  5.64 31.907 7.8 31.915 ;
     RECT  32.016 31.813 33.144 31.915 ;
     RECT  47.328 31.827 49.464 31.915 ;
     RECT  59.52 31.417 60.072 31.915 ;
     RECT  62.736 31.733 62.76 31.915 ;
     RECT  68.976 31.339 72.6 31.915 ;
     RECT  16.44 31.147 16.752 31.925 ;
     RECT  29.568 31.851 29.736 31.925 ;
     RECT  32.016 31.915 32.952 31.925 ;
     RECT  25.008 31.309 25.032 31.945 ;
     RECT  50.736 31.813 51.288 31.979 ;
     RECT  70.176 31.915 72.6 31.979 ;
     RECT  20.016 31.919 20.04 32.003 ;
     RECT  11.04 31.417 11.832 32.013 ;
     RECT  36.528 31.811 36.648 32.171 ;
     RECT  21.6 31.309 22.152 32.205 ;
     RECT  19.968 32.149 19.992 32.235 ;
     RECT  30.864 31.851 30.888 32.235 ;
     RECT  54.24 31.765 55.32 32.245 ;
     RECT  11.04 32.013 11.448 32.291 ;
     RECT  26.208 31.381 27.552 32.299 ;
     RECT  50.736 31.979 50.856 32.299 ;
     RECT  5.64 31.915 6.888 32.339 ;
     RECT  48.096 31.915 49.464 32.339 ;
     RECT  9.12 31.907 9.288 32.341 ;
     RECT  15.84 31.925 16.752 32.387 ;
     RECT  18.768 32.181 18.792 32.387 ;
     RECT  38.04 31.765 38.808 32.403 ;
     RECT  9.12 32.341 9.336 32.427 ;
     RECT  70.272 31.979 72.6 32.427 ;
     RECT  11.04 32.291 11.352 32.437 ;
     RECT  38.04 32.403 38.904 32.437 ;
     RECT  13.632 32.309 13.656 32.483 ;
     RECT  34.848 32.053 34.872 32.485 ;
     RECT  41.04 31.861 44.328 32.491 ;
     RECT  53.568 32.245 55.32 32.491 ;
     RECT  68.976 31.915 69.192 32.501 ;
     RECT  26.208 32.299 26.232 32.521 ;
     RECT  53.568 32.491 54.744 32.531 ;
     RECT  59.64 31.915 60.072 32.531 ;
     RECT  38.04 32.437 39.864 32.533 ;
     RECT  33.936 32.485 34.968 32.569 ;
     RECT  0.048 31.275 0.744 32.629 ;
     RECT  52.464 32.629 52.92 32.677 ;
     RECT  42.192 32.491 44.328 32.687 ;
     RECT  65.04 31.477 65.592 32.725 ;
     RECT  9.12 32.427 9.144 32.747 ;
     RECT  58.128 32.485 58.152 32.747 ;
     RECT  66.816 32.629 66.84 32.757 ;
     RECT  5.64 32.339 6.84 32.761 ;
     RECT  51.936 32.677 52.92 32.761 ;
     RECT  45.6 32.501 45.72 32.771 ;
     RECT  64.176 32.725 65.592 32.811 ;
     RECT  66.72 32.757 66.84 32.811 ;
     RECT  29.232 31.925 29.736 32.819 ;
     RECT  52.656 32.761 52.92 32.819 ;
     RECT  45.696 32.771 45.72 32.821 ;
     RECT  2.88 32.725 2.904 32.867 ;
     RECT  56.448 31.914 57.048 32.869 ;
     RECT  31.92 31.925 32.952 32.875 ;
     RECT  34.032 32.569 34.968 32.875 ;
     RECT  38.04 32.533 39.912 32.875 ;
     RECT  32.448 32.875 32.952 32.915 ;
     RECT  34.032 32.875 34.056 32.915 ;
     RECT  45.696 32.821 46.152 32.917 ;
     RECT  5.64 32.761 6.312 32.927 ;
     RECT  36.624 32.171 36.648 32.963 ;
     RECT  4.992 32.927 6.312 32.965 ;
     RECT  27.24 32.299 27.552 32.965 ;
     RECT  45.696 32.917 46.2 32.965 ;
     RECT  59.64 32.531 59.952 32.965 ;
     RECT  32.64 32.915 32.952 32.979 ;
     RECT  0.048 32.629 0.792 33.003 ;
     RECT  68.4 32.501 69.192 33.011 ;
     RECT  13.152 32.917 13.176 33.013 ;
     RECT  13.056 33.013 13.176 33.059 ;
     RECT  42.192 32.687 44.472 33.059 ;
     RECT  0.096 33.003 0.792 33.067 ;
     RECT  4.896 32.965 6.312 33.067 ;
     RECT  27.24 32.965 27.768 33.067 ;
     RECT  32.64 32.979 33.048 33.067 ;
     RECT  62.784 32.757 62.808 33.067 ;
     RECT  66.72 32.811 66.744 33.067 ;
     RECT  68.4 33.011 69.096 33.067 ;
     RECT  48.096 32.339 49.368 33.077 ;
     RECT  70.44 32.427 72.6 33.077 ;
     RECT  13.056 33.059 13.08 33.097 ;
     RECT  41.04 32.491 41.064 33.097 ;
     RECT  0.096 33.067 0.696 33.107 ;
     RECT  5.64 33.067 6.312 33.107 ;
     RECT  55.872 32.869 57.048 33.107 ;
     RECT  68.4 33.067 69.048 33.107 ;
     RECT  43.44 33.059 44.472 33.109 ;
     RECT  45.696 32.965 46.776 33.119 ;
     RECT  47.856 33.077 49.368 33.119 ;
     RECT  30.144 32.965 30.168 33.131 ;
     RECT  55.872 33.107 56.472 33.131 ;
     RECT  23.664 33.119 23.688 33.203 ;
     RECT  69.024 33.107 69.048 33.203 ;
     RECT  70.44 33.077 72.648 33.205 ;
     RECT  36.288 33.141 36.312 33.251 ;
     RECT  43.44 33.109 44.568 33.323 ;
     RECT  45.696 33.119 49.368 33.323 ;
     RECT  43.44 33.323 44.472 33.347 ;
     RECT  31.344 33.077 31.368 33.539 ;
     RECT  52.656 32.819 52.68 33.539 ;
     RECT  70.44 33.205 72.696 33.587 ;
     RECT  47.856 33.323 49.368 33.637 ;
     RECT  10.128 32.437 11.352 33.683 ;
     RECT  38.04 32.875 39.864 33.683 ;
     RECT  42.192 33.059 42.216 33.683 ;
     RECT  54.144 32.531 54.744 33.731 ;
     RECT  47.856 33.637 49.656 33.781 ;
     RECT  56.448 33.131 56.472 33.827 ;
     RECT  45.696 33.323 46.728 33.839 ;
     RECT  54.144 33.731 54.648 33.839 ;
     RECT  39.84 33.683 39.864 33.875 ;
     RECT  47.856 33.781 50.184 33.875 ;
     RECT  59.52 32.965 59.952 33.877 ;
     RECT  65.04 32.811 65.352 33.877 ;
     RECT  17.856 33.589 17.88 33.899 ;
     RECT  19.2 33.589 19.224 33.899 ;
     RECT  20.208 33.781 20.232 33.899 ;
     RECT  54.048 33.839 54.648 33.923 ;
     RECT  58.8 33.877 59.952 33.973 ;
     RECT  62.304 33.845 62.328 34.165 ;
     RECT  0.24 33.107 0.696 34.259 ;
     RECT  51.264 34.165 51.288 34.357 ;
     RECT  62.208 34.165 62.328 34.357 ;
     RECT  10.848 33.683 11.352 34.411 ;
     RECT  23.136 34.069 23.16 34.411 ;
     RECT  63.84 34.323 63.864 34.411 ;
     RECT  38.04 33.683 38.808 34.415 ;
     RECT  66.768 34.357 66.936 34.421 ;
     RECT  50.784 34.357 51.912 34.451 ;
     RECT  57.552 33.445 57.576 34.451 ;
     RECT  70.44 33.587 72.648 34.453 ;
     RECT  37.92 34.415 38.808 34.499 ;
     RECT  27.24 33.067 27.552 34.501 ;
     RECT  66.72 34.421 66.936 34.549 ;
     RECT  55.728 34.165 55.896 34.667 ;
     RECT  62.208 34.357 62.76 34.667 ;
     RECT  50.832 34.451 51.912 34.681 ;
     RECT  50.832 34.681 51.864 34.731 ;
     RECT  66.72 34.549 67.032 34.731 ;
     RECT  36.432 34.707 36.456 34.795 ;
     RECT  66.72 34.731 66.936 34.795 ;
     RECT  5.64 33.107 5.952 34.799 ;
     RECT  26.784 34.501 27.552 34.805 ;
     RECT  51.264 34.731 51.864 34.835 ;
     RECT  41.04 34.357 41.064 34.847 ;
     RECT  4.896 34.799 5.952 34.883 ;
     RECT  40.464 34.847 41.064 34.93 ;
     RECT  45.6 33.839 46.728 34.933 ;
     RECT  42.144 34.869 42.168 34.957 ;
     RECT  45.552 34.933 46.728 34.981 ;
     RECT  48.288 33.875 49.56 34.981 ;
     RECT  54.24 33.923 54.648 34.981 ;
     RECT  55.728 34.667 55.752 34.981 ;
     RECT  26.784 34.805 27.72 34.997 ;
     RECT  45.552 34.981 49.56 35.017 ;
     RECT  40.416 34.93 41.064 35.027 ;
     RECT  46.128 35.017 49.56 35.065 ;
     RECT  54.24 34.981 55.752 35.065 ;
     RECT  65.04 33.877 65.592 35.075 ;
     RECT  48.288 35.065 49.56 35.077 ;
     RECT  58.704 33.973 59.952 35.077 ;
     RECT  40.464 35.027 41.064 35.123 ;
     RECT  40.992 35.123 41.064 35.125 ;
     RECT  43.44 33.347 43.752 35.125 ;
     RECT  23.76 35.091 23.784 35.179 ;
     RECT  26.784 34.997 27.816 35.179 ;
     RECT  34.128 35.077 34.152 35.179 ;
     RECT  66.72 34.795 66.84 35.179 ;
     RECT  43.44 35.125 44.424 35.209 ;
     RECT  27.24 35.179 27.816 35.243 ;
     RECT  48.288 35.077 49.656 35.243 ;
     RECT  15.36 35.173 15.384 35.257 ;
     RECT  55.728 35.065 55.752 35.267 ;
     RECT  38.04 34.499 38.808 35.317 ;
     RECT  70.128 34.453 72.648 35.317 ;
     RECT  61.584 35.253 61.608 35.363 ;
     RECT  63.792 35.253 63.816 35.363 ;
     RECT  70.128 35.317 72.696 35.375 ;
     RECT  43.44 35.209 44.232 35.413 ;
     RECT  16.44 32.387 16.752 35.475 ;
     RECT  27.24 35.243 27.768 35.499 ;
     RECT  70.032 35.375 72.696 35.555 ;
     RECT  46.128 35.065 47.304 35.593 ;
     RECT  58.656 35.077 59.952 35.605 ;
     RECT  15.744 35.475 16.752 35.627 ;
     RECT  42.864 35.413 44.232 35.627 ;
     RECT  48.432 35.243 49.656 35.691 ;
     RECT  40.992 35.125 41.736 35.785 ;
     RECT  58.128 35.605 59.952 35.795 ;
     RECT  38.04 35.317 38.904 35.797 ;
     RECT  46.32 35.593 47.304 35.819 ;
     RECT  59.64 35.795 59.952 35.829 ;
     RECT  48.48 35.691 49.656 35.845 ;
     RECT  51.264 34.835 51.288 35.845 ;
     RECT  58.128 35.795 58.632 35.883 ;
     RECT  56.976 34.741 57 35.923 ;
     RECT  48.48 35.845 50.136 35.941 ;
     RECT  51.264 35.845 51.864 35.941 ;
     RECT  48.48 35.941 51.864 35.947 ;
     RECT  56.976 35.923 57.048 35.957 ;
     RECT  56.352 35.957 57.048 36.011 ;
     RECT  37.392 35.797 38.904 36.021 ;
     RECT  63.84 35.941 63.864 36.025 ;
     RECT  59.64 35.829 60.168 36.037 ;
     RECT  11.04 34.411 11.352 36.051 ;
     RECT  50.832 35.947 51.864 36.075 ;
     RECT  48.48 35.947 49.152 36.083 ;
     RECT  56.352 36.011 56.376 36.083 ;
     RECT  59.64 36.037 61.032 36.083 ;
     RECT  18.048 35.941 18.072 36.085 ;
     RECT  37.392 36.021 39.72 36.109 ;
     RECT  11.04 36.051 11.448 36.139 ;
     RECT  29.904 36.051 29.928 36.139 ;
     RECT  41.472 35.785 41.736 36.203 ;
     RECT  18.048 36.085 18.792 36.213 ;
     RECT  18 36.213 18.792 36.267 ;
     RECT  42.864 35.627 43.992 36.277 ;
     RECT  18 36.267 18.072 36.301 ;
     RECT  48.72 36.083 49.152 36.331 ;
     RECT  42.096 36.277 43.992 36.361 ;
     RECT  66.72 36.149 66.744 36.373 ;
     RECT  18.048 36.301 18.072 36.395 ;
     RECT  37.392 36.109 38.808 36.459 ;
     RECT  39.84 36.373 39.864 36.459 ;
     RECT  46.32 35.819 46.872 36.459 ;
     RECT  50.832 36.075 51.336 36.459 ;
     RECT  66.72 36.373 67.128 36.459 ;
     RECT  11.04 36.139 11.352 36.469 ;
     RECT  34.896 36.085 34.92 36.515 ;
     RECT  50.832 36.459 50.856 36.553 ;
     RECT  10.8 36.469 11.352 36.563 ;
     RECT  46.32 36.459 46.344 36.597 ;
     RECT  54.24 35.065 54.552 36.661 ;
     RECT  61.008 36.083 61.032 36.661 ;
     RECT  66.672 36.661 66.696 36.745 ;
     RECT  70.032 35.555 72.6 36.853 ;
     RECT  69.936 36.853 72.6 36.937 ;
     RECT  46.272 36.597 46.344 36.949 ;
     RECT  42.096 36.361 43.848 37.035 ;
     RECT  46.128 36.949 46.344 37.035 ;
     RECT  54.24 36.661 54.744 37.035 ;
     RECT  61.008 36.661 61.08 37.035 ;
     RECT  31.296 36.959 31.32 37.043 ;
     RECT  68.016 36.661 68.04 37.043 ;
     RECT  40.416 36.517 40.44 37.045 ;
     RECT  58.128 35.883 58.152 37.045 ;
     RECT  59.64 36.083 59.952 37.045 ;
     RECT  37.392 36.459 38.352 37.091 ;
     RECT  46.32 37.035 46.344 37.099 ;
     RECT  55.872 37.045 55.896 37.139 ;
     RECT  44.976 36.517 45 37.163 ;
     RECT  58.128 37.045 59.952 37.187 ;
     RECT  42.096 37.035 43.752 37.227 ;
     RECT  40.416 37.045 40.68 37.291 ;
     RECT  29.616 36.997 29.64 37.477 ;
     RECT  38.04 37.091 38.352 37.477 ;
     RECT  21.84 32.205 22.152 37.535 ;
     RECT  29.616 37.477 30.072 37.547 ;
     RECT  30.048 37.547 30.072 37.611 ;
     RECT  44.736 37.477 44.76 37.611 ;
     RECT  21.024 37.535 22.152 37.619 ;
     RECT  39.744 37.535 39.768 37.619 ;
     RECT  58.704 37.187 59.952 37.621 ;
     RECT  43.056 37.227 43.752 37.645 ;
     RECT  58.704 37.621 60.456 37.675 ;
     RECT  69.168 37.109 69.192 37.685 ;
     RECT  70.44 36.937 72.6 37.803 ;
     RECT  69.072 37.685 69.192 37.813 ;
     RECT  51.36 37.621 51.384 37.907 ;
     RECT  30.72 37.919 30.744 38.003 ;
     RECT  12.768 37.971 12.792 38.059 ;
     RECT  32.64 33.067 32.952 38.101 ;
     RECT  70.44 37.803 72.504 38.123 ;
     RECT  68.976 37.813 69.192 38.133 ;
     RECT  70.44 38.123 71.736 38.133 ;
     RECT  38.04 37.477 38.472 38.149 ;
     RECT  32.448 38.101 32.952 38.187 ;
     RECT  59.64 37.675 60.456 38.195 ;
     RECT  65.04 35.075 65.352 38.197 ;
     RECT  38.04 38.149 38.664 38.315 ;
     RECT  68.976 38.133 71.736 38.387 ;
     RECT  46.464 38.005 46.488 38.507 ;
     RECT  70.128 38.387 71.736 38.571 ;
     RECT  65.04 38.197 66.168 38.629 ;
     RECT  67.152 38.197 67.176 38.629 ;
     RECT  65.04 38.629 67.176 38.713 ;
     RECT  67.152 38.713 67.176 38.723 ;
     RECT  68.976 38.387 69.144 38.819 ;
     RECT  70.44 38.571 71.736 38.819 ;
     RECT  70.44 38.819 71.016 38.915 ;
     RECT  65.04 38.713 65.88 39.211 ;
     RECT  63.696 39.157 63.816 39.241 ;
     RECT  69.12 38.819 69.144 39.275 ;
     RECT  63.696 39.241 63.72 39.299 ;
     RECT  70.44 38.915 70.92 39.685 ;
     RECT  70.08 39.685 70.92 39.787 ;
     RECT  70.176 39.787 70.92 39.865 ;
     RECT  70.44 39.865 70.92 39.979 ;
     RECT  0.24 34.259 0.552 39.983 ;
     RECT  5.64 34.883 5.952 39.983 ;
     RECT  11.04 36.563 11.352 39.983 ;
     RECT  16.44 35.627 16.752 39.983 ;
     RECT  21.84 37.619 22.152 39.983 ;
     RECT  27.24 35.499 27.552 39.983 ;
     RECT  32.64 38.187 32.952 39.983 ;
     RECT  38.04 38.315 38.352 39.983 ;
     RECT  43.44 37.645 43.752 39.983 ;
     RECT  48.84 36.331 49.152 39.983 ;
     RECT  54.24 37.035 54.552 39.983 ;
     RECT  59.64 38.195 59.952 39.983 ;
     RECT  65.04 39.211 65.352 39.983 ;
     RECT  70.44 39.979 70.752 39.983 ;
     RECT  0.432 39.983 0.552 40.253 ;
     RECT  5.832 39.983 5.952 40.253 ;
     RECT  11.232 39.983 11.352 40.253 ;
     RECT  16.632 39.983 16.752 40.253 ;
     RECT  22.032 39.983 22.152 40.253 ;
     RECT  27.432 39.983 27.552 40.253 ;
     RECT  32.832 39.983 32.952 40.253 ;
     RECT  38.232 39.983 38.352 40.253 ;
     RECT  43.632 39.983 43.752 40.253 ;
     RECT  49.032 39.983 49.152 40.253 ;
     RECT  54.432 39.983 54.552 40.253 ;
     RECT  59.832 39.983 59.952 40.253 ;
     RECT  65.232 39.983 65.352 40.253 ;
     RECT  70.632 39.983 70.752 40.253 ;
     RECT  72.912 40.117 72.936 40.355 ;
     RECT  72.816 40.357 72.84 40.547 ;
    LAYER M6 ;
     RECT  0 22.596 0.037 23.46 ;
     RECT  0 33.396 0.037 34.26 ;
     RECT  0 27.996 0.085 28.86 ;
     RECT  0.053 30.592 0.085 30.624 ;
     RECT  0.037 10.304 0.133 10.336 ;
     RECT  0 11.796 0.133 12.66 ;
     RECT  0 17.196 0.133 18.06 ;
     RECT  0.037 19.904 0.133 20.64 ;
     RECT  0.037 22.596 0.133 23.904 ;
     RECT  0.085 27.996 0.133 30.624 ;
     RECT  0.037 32.576 0.133 34.26 ;
     RECT  0 6.396 0.613 7.26 ;
     RECT  0.133 8.896 0.613 34.26 ;
     RECT  0.613 6.396 0.659 34.26 ;
     RECT  0.659 27.008 0.707 29.728 ;
     RECT  0.707 27.996 0.755 29.216 ;
     RECT  0.659 31.104 0.755 31.264 ;
     RECT  0.755 31.232 0.803 31.264 ;
     RECT  0.659 6.396 3.637 25.184 ;
     RECT  0.659 32.704 4.885 34.26 ;
     RECT  4.885 32.704 4.971 34.848 ;
     RECT  4.971 32.704 6.805 34.26 ;
     RECT  6.805 31.744 7.797 34.26 ;
     RECT  0.755 27.996 8.485 28.86 ;
     RECT  8.485 27.996 8.949 29.472 ;
     RECT  7.797 31.744 8.949 34.656 ;
     RECT  8.949 27.84 9.061 29.472 ;
     RECT  8.949 31.552 9.061 34.656 ;
     RECT  9.061 27.84 9.269 34.656 ;
     RECT  9.269 27.84 10.117 35.296 ;
     RECT  10.117 27.584 10.789 35.296 ;
     RECT  3.637 6.396 10.837 25.952 ;
     RECT  10.789 27.584 10.837 36.512 ;
     RECT  10.837 6.396 11.115 36.512 ;
     RECT  0 38.796 11.317 39.66 ;
     RECT  11.115 6.396 11.459 36.128 ;
     RECT  11.459 6.396 11.747 35.616 ;
     RECT  11.317 38.528 12.757 39.66 ;
     RECT  12.757 38.016 12.789 39.66 ;
     RECT  12.789 38.016 12.843 39.776 ;
     RECT  11.747 27.84 13.045 35.616 ;
     RECT  13.045 27.84 13.114 35.68 ;
     RECT  11.747 6.396 15.157 26.464 ;
     RECT  13.114 27.996 15.349 35.68 ;
     RECT  15.157 6.396 15.443 26.592 ;
     RECT  15.443 25.92 16.837 26.592 ;
     RECT  15.349 27.996 16.837 36.128 ;
     RECT  16.837 25.92 17.989 36.128 ;
     RECT  17.989 25.92 18.018 36.256 ;
     RECT  12.843 38.528 18.037 39.776 ;
     RECT  18.018 25.92 18.091 36.384 ;
     RECT  15.443 6.396 18.229 23.968 ;
     RECT  18.091 25.92 18.229 36.256 ;
     RECT  18.229 6.396 18.419 36.256 ;
     RECT  18.419 6.396 19.909 24.288 ;
     RECT  18.419 25.92 19.909 36.256 ;
     RECT  18.037 38.528 21.013 39.84 ;
     RECT  21.013 37.568 21.099 39.84 ;
     RECT  19.909 6.396 21.683 36.256 ;
     RECT  21.683 9.152 22.931 36.256 ;
     RECT  22.931 9.216 29.605 36.256 ;
     RECT  21.099 38.528 29.605 39.84 ;
     RECT  29.605 9.216 35.957 39.84 ;
     RECT  35.957 9.216 39.531 40.16 ;
     RECT  39.531 9.216 47.363 10.464 ;
     RECT  47.363 10.432 47.461 10.464 ;
     RECT  39.531 11.796 47.461 40.16 ;
     RECT  47.461 10.432 47.531 40.16 ;
     RECT  47.531 10.432 53.075 10.464 ;
     RECT  47.531 11.796 53.493 40.16 ;
     RECT  53.493 11.648 53.939 40.16 ;
     RECT  53.939 11.796 54.179 40.16 ;
     RECT  54.179 14.016 57.059 40.16 ;
     RECT  57.059 14.016 61.557 14.624 ;
     RECT  61.557 14.016 61.63 14.752 ;
     RECT  61.63 14.016 62.195 14.624 ;
     RECT  62.195 14.016 63.875 14.048 ;
     RECT  57.059 16.064 63.875 40.16 ;
     RECT  63.875 22.08 64.451 40.16 ;
     RECT  63.875 16.064 64.789 20.64 ;
     RECT  64.789 15.104 64.875 20.64 ;
     RECT  64.451 22.208 65.459 40.16 ;
     RECT  64.875 19.392 65.507 20.64 ;
     RECT  64.875 16.064 65.603 18.06 ;
     RECT  65.507 19.392 65.603 19.744 ;
     RECT  65.459 22.4 66.179 40.16 ;
     RECT  65.603 19.392 66.755 19.424 ;
     RECT  66.179 22.596 67.283 40.16 ;
     RECT  67.283 25.792 67.859 40.16 ;
     RECT  67.283 22.596 68.267 23.904 ;
     RECT  67.859 25.92 69.011 40.16 ;
     RECT  69.011 25.984 69.163 40.16 ;
     RECT  69.163 27.328 69.291 40.16 ;
     RECT  69.163 25.984 69.587 26.016 ;
     RECT  69.291 27.456 70.163 40.16 ;
     RECT  0 0.996 70.56 1.86 ;
     RECT  21.683 6.396 70.56 7.26 ;
     RECT  54.179 11.796 70.56 12.66 ;
     RECT  65.603 17.196 70.56 18.06 ;
     RECT  68.267 22.596 70.56 23.46 ;
     RECT  70.163 27.996 70.56 40.16 ;
     RECT  70.56 1.572 71.344 1.86 ;
     RECT  70.56 6.972 71.344 7.26 ;
     RECT  70.56 12.372 71.344 12.66 ;
     RECT  70.56 17.772 71.344 18.06 ;
     RECT  70.56 23.172 71.344 23.46 ;
     RECT  70.56 28.16 71.344 40.16 ;
     RECT  71.344 28.16 71.467 38.432 ;
     RECT  71.467 28.16 71.747 38.24 ;
     RECT  71.747 28.16 72.515 38.112 ;
     RECT  72.515 28.16 72.563 37.792 ;
     RECT  72.563 31.168 72.611 37.792 ;
     RECT  72.611 31.424 72.619 31.776 ;
     RECT  72.611 33.088 72.659 35.36 ;
     RECT  72.619 31.744 72.683 31.776 ;
     RECT  71.989 20.032 72.707 20.064 ;
     RECT  72.659 33.216 72.707 35.36 ;
     RECT  72.707 34.112 72.747 35.36 ;
     RECT  71.344 40.128 72.947 40.16 ;
    LAYER M7 ;
     RECT  13.696 8.373 13.728 8.437 ;
     RECT  13.696 8.437 13.856 8.501 ;
     RECT  13.696 8.501 14.304 9.259 ;
     RECT  0.856 0.531 1.144 9.269 ;
     RECT  17.056 0.531 17.344 9.333 ;
     RECT  22.456 0.531 22.744 9.525 ;
     RECT  21.696 9.525 22.744 9.653 ;
     RECT  6.256 0.531 6.544 10.037 ;
     RECT  17.056 9.333 18.272 10.101 ;
     RECT  16.576 10.101 18.272 10.165 ;
     RECT  11.656 0.531 11.944 10.229 ;
     RECT  13.696 9.259 14.176 10.229 ;
     RECT  16.576 10.165 18.848 10.347 ;
     RECT  20.8 9.653 22.744 10.475 ;
     RECT  0.512 9.269 1.144 10.603 ;
     RECT  27.856 0.531 28.144 10.805 ;
     RECT  16.576 10.347 17.344 10.987 ;
     RECT  38.656 0.531 38.944 11.189 ;
     RECT  31.36 10.741 31.392 11.435 ;
     RECT  6.256 10.037 6.944 11.445 ;
     RECT  18.816 10.347 18.848 11.445 ;
     RECT  6.256 11.445 7.968 11.499 ;
     RECT  18.816 11.445 19.424 11.499 ;
     RECT  11.656 10.229 14.176 11.637 ;
     RECT  0.704 10.603 1.144 11.691 ;
     RECT  25.792 11.637 25.824 12.149 ;
     RECT  38.656 11.189 39.52 12.149 ;
     RECT  11.52 11.637 14.176 12.203 ;
     RECT  17.056 10.987 17.344 12.213 ;
     RECT  36.672 11.637 36.704 12.213 ;
     RECT  38.208 12.149 39.52 12.213 ;
     RECT  27.856 10.805 29.088 12.779 ;
     RECT  36.672 12.213 39.52 12.843 ;
     RECT  33.256 0.531 33.544 12.853 ;
     RECT  37.056 12.843 39.52 12.907 ;
     RECT  17.056 12.213 17.504 12.917 ;
     RECT  21.696 10.475 22.744 12.981 ;
     RECT  33.088 12.853 33.544 12.981 ;
     RECT  42.176 12.917 42.208 12.981 ;
     RECT  44.056 0.531 44.344 12.981 ;
     RECT  7.936 11.499 7.968 13.035 ;
     RECT  47.488 11.317 47.52 13.045 ;
     RECT  4.672 11.637 4.704 13.109 ;
     RECT  33.088 12.981 34.272 13.109 ;
     RECT  4.544 13.109 4.704 13.163 ;
     RECT  0.856 11.691 1.144 13.237 ;
     RECT  14.144 12.203 14.176 13.291 ;
     RECT  47.488 13.045 47.648 13.301 ;
     RECT  17.056 12.917 17.632 13.365 ;
     RECT  30.336 12.853 30.368 13.493 ;
     RECT  32.192 13.109 34.272 13.493 ;
     RECT  53.504 11.637 53.536 13.611 ;
     RECT  16.576 13.365 17.632 13.685 ;
     RECT  19.392 11.499 19.424 13.739 ;
     RECT  45.824 12.725 45.856 13.877 ;
     RECT  47.36 13.301 47.648 13.877 ;
     RECT  21.696 12.981 23.392 14.005 ;
     RECT  11.52 12.203 12.768 14.059 ;
     RECT  16 13.685 17.632 14.133 ;
     RECT  18.944 14.069 18.976 14.133 ;
     RECT  42.176 12.981 44.344 14.133 ;
     RECT  45.824 13.877 47.648 14.133 ;
     RECT  30.336 13.493 34.272 14.197 ;
     RECT  0.512 13.237 1.144 14.315 ;
     RECT  16 14.133 18.976 14.379 ;
     RECT  4.544 13.163 4.576 14.443 ;
     RECT  21.184 14.005 23.392 14.453 ;
     RECT  24.96 12.149 25.824 14.453 ;
     RECT  21.184 14.453 25.824 14.507 ;
     RECT  30.336 14.197 35.04 14.635 ;
     RECT  21.184 14.507 24.544 14.709 ;
     RECT  60.256 0.531 60.544 14.709 ;
     RECT  54.856 0.531 55.144 14.773 ;
     RECT  16 14.379 18.848 14.891 ;
     RECT  20.544 14.709 24.544 14.891 ;
     RECT  37.056 12.907 38.944 14.955 ;
     RECT  42.176 14.133 47.648 14.955 ;
     RECT  14.464 14.197 14.496 14.965 ;
     RECT  65.656 0.531 65.944 15.093 ;
     RECT  9.536 14.965 9.568 15.147 ;
     RECT  11.52 14.059 11.944 15.157 ;
     RECT  13.312 14.965 14.496 15.211 ;
     RECT  37.184 14.955 38.944 15.275 ;
     RECT  10.944 15.157 11.944 15.285 ;
     RECT  42.368 14.955 47.648 15.285 ;
     RECT  52.416 14.901 52.448 15.541 ;
     RECT  27.856 12.779 28.512 15.659 ;
     RECT  10.304 15.285 11.944 16.043 ;
     RECT  51.968 15.541 52.448 16.043 ;
     RECT  54.856 14.773 56.16 16.043 ;
     RECT  42.368 15.285 48.16 16.107 ;
     RECT  26.048 14.581 26.08 16.171 ;
     RECT  20.544 14.891 22.744 16.363 ;
     RECT  0.856 14.315 1.144 16.373 ;
     RECT  2.496 14.517 2.528 16.373 ;
     RECT  10.944 16.043 11.944 16.427 ;
     RECT  13.312 15.211 13.344 16.427 ;
     RECT  46.848 16.107 48.16 16.427 ;
     RECT  31.104 14.635 35.04 16.491 ;
     RECT  49.456 0.531 49.744 16.501 ;
     RECT  51.968 16.043 52 16.501 ;
     RECT  8.576 15.605 8.608 16.619 ;
     RECT  31.104 16.491 34.848 16.619 ;
     RECT  60.256 14.709 61.6 16.747 ;
     RECT  47.296 16.427 48.16 16.757 ;
     RECT  49.456 16.501 52 16.757 ;
     RECT  11.52 16.427 11.944 16.821 ;
     RECT  31.104 16.619 31.968 16.821 ;
     RECT  54.856 16.043 55.264 16.821 ;
     RECT  16.576 14.891 18.208 16.875 ;
     RECT  30.208 16.821 31.968 16.875 ;
     RECT  6.256 11.499 6.544 16.885 ;
     RECT  0.856 16.373 2.528 17.013 ;
     RECT  24.512 14.891 24.544 17.067 ;
     RECT  27.856 15.659 28.384 17.067 ;
     RECT  33.256 16.619 34.4 17.067 ;
     RECT  42.368 16.107 45.472 17.067 ;
     RECT  38.208 15.275 38.944 17.077 ;
     RECT  27.856 17.067 28.256 17.131 ;
     RECT  47.296 16.757 52 17.643 ;
     RECT  43.52 17.067 45.472 17.707 ;
     RECT  53.888 16.821 55.264 17.707 ;
     RECT  11.52 16.821 13.28 18.165 ;
     RECT  17.056 16.875 17.696 18.165 ;
     RECT  0.856 17.013 2.848 18.229 ;
     RECT  10.944 18.165 13.28 18.229 ;
     RECT  6.256 16.885 7.456 18.283 ;
     RECT  16.576 18.165 17.696 18.283 ;
     RECT  30.208 16.875 30.24 18.283 ;
     RECT  43.52 17.707 45.344 18.283 ;
     RECT  53.888 17.707 55.144 18.411 ;
     RECT  22.456 16.363 22.744 18.485 ;
     RECT  31.936 16.875 31.968 18.805 ;
     RECT  33.256 17.067 33.696 18.805 ;
     RECT  10.944 18.229 13.728 18.859 ;
     RECT  62.4 18.741 62.432 18.933 ;
     RECT  62.144 18.933 62.432 18.987 ;
     RECT  31.936 18.805 33.696 19.115 ;
     RECT  20.544 16.363 21.152 19.179 ;
     RECT  27.856 17.131 28.144 19.189 ;
     RECT  22.456 18.485 23.136 19.317 ;
     RECT  47.296 17.643 51.552 19.317 ;
     RECT  33.256 19.115 33.696 19.381 ;
     RECT  16.576 18.283 17.344 19.435 ;
     RECT  21.056 19.179 21.152 19.435 ;
     RECT  43.776 18.283 45.344 19.435 ;
     RECT  27.856 19.189 29.088 19.445 ;
     RECT  33.256 19.381 34.848 19.445 ;
     RECT  64.832 15.093 65.944 19.499 ;
     RECT  54.144 18.411 55.144 19.563 ;
     RECT  40.768 18.293 40.8 19.573 ;
     RECT  47.232 19.317 51.552 19.573 ;
     RECT  42.304 19.189 42.336 19.829 ;
     RECT  8.768 18.229 8.8 19.893 ;
     RECT  15.104 19.189 15.136 19.893 ;
     RECT  22.456 19.317 23.392 19.893 ;
     RECT  26.624 19.445 29.088 20.011 ;
     RECT  37.44 17.077 38.944 20.011 ;
     RECT  42.304 19.829 42.592 20.011 ;
     RECT  62.144 18.987 62.176 20.011 ;
     RECT  37.632 20.011 38.944 20.075 ;
     RECT  42.304 20.011 42.336 20.149 ;
     RECT  8.768 19.893 9.12 20.277 ;
     RECT  10.944 18.859 11.944 20.277 ;
     RECT  18.816 19.125 18.976 20.277 ;
     RECT  13.696 18.859 13.728 20.341 ;
     RECT  15.104 19.893 15.2 20.341 ;
     RECT  26.624 20.011 28.144 20.341 ;
     RECT  47.232 19.573 51.872 20.469 ;
     RECT  26.24 20.341 28.144 20.587 ;
     RECT  44.056 19.435 45.344 20.651 ;
     RECT  40.512 19.573 40.8 20.661 ;
     RECT  42.176 20.149 42.336 20.661 ;
     RECT  44.056 20.651 45.216 20.843 ;
     RECT  31.936 19.115 31.968 20.907 ;
     RECT  0.856 18.229 3.808 20.917 ;
     RECT  6.256 18.283 7.136 20.981 ;
     RECT  8.768 20.277 11.944 20.981 ;
     RECT  0.576 20.917 3.808 21.045 ;
     RECT  21.056 19.435 21.088 21.109 ;
     RECT  22.456 19.893 23.712 21.109 ;
     RECT  26.624 20.587 28.144 21.163 ;
     RECT  47.232 20.469 52.512 21.163 ;
     RECT  0.512 21.045 3.808 21.173 ;
     RECT  0.448 21.173 3.808 21.301 ;
     RECT  21.056 21.109 23.84 21.365 ;
     RECT  47.296 21.163 52.512 21.365 ;
     RECT  27.136 21.163 28.144 21.419 ;
     RECT  40.512 20.661 42.336 21.419 ;
     RECT  6.256 20.981 11.944 21.493 ;
     RECT  60.256 16.747 60.544 21.493 ;
     RECT  33.256 19.445 36 21.547 ;
     RECT  17.056 19.435 17.344 21.557 ;
     RECT  18.688 20.277 18.976 21.557 ;
     RECT  40.512 21.419 42.208 21.611 ;
     RECT  17.056 21.557 18.976 21.621 ;
     RECT  33.256 21.547 33.544 21.621 ;
     RECT  13.696 20.341 15.2 21.739 ;
     RECT  38.528 20.075 38.944 21.739 ;
     RECT  6.016 21.493 11.944 21.867 ;
     RECT  6.016 21.867 10.336 21.931 ;
     RECT  21.056 21.365 24.032 21.995 ;
     RECT  13.696 21.739 14.176 22.059 ;
     RECT  47.296 21.365 52.832 22.059 ;
     RECT  17.056 21.621 19.36 22.069 ;
     RECT  9.088 21.931 10.336 22.187 ;
     RECT  21.056 21.995 21.088 22.251 ;
     RECT  0.448 21.301 4 22.379 ;
     RECT  40.512 21.611 41.632 22.379 ;
     RECT  49.456 22.059 52.832 22.379 ;
     RECT  15.936 22.069 19.36 22.443 ;
     RECT  27.856 21.419 28.144 22.453 ;
     RECT  35.456 21.547 36 22.453 ;
     RECT  6.016 21.931 7.584 22.507 ;
     RECT  22.456 21.995 24.032 22.507 ;
     RECT  47.296 22.059 47.84 22.507 ;
     RECT  49.456 22.379 51.936 22.507 ;
     RECT  44.056 20.843 44.512 23.019 ;
     RECT  47.808 22.507 47.84 23.019 ;
     RECT  51.904 22.507 51.936 23.019 ;
     RECT  10.112 22.187 10.336 23.083 ;
     RECT  14.144 22.059 14.176 23.083 ;
     RECT  35.456 22.453 36.512 23.083 ;
     RECT  41.6 22.379 41.632 23.083 ;
     RECT  59.648 21.493 60.544 23.541 ;
     RECT  35.968 23.083 36.512 23.595 ;
     RECT  33.152 21.621 33.544 23.669 ;
     RECT  10.176 23.083 10.336 23.723 ;
     RECT  15.936 22.443 17.344 23.723 ;
     RECT  0.448 22.379 3.68 23.733 ;
     RECT  62.656 23.029 62.688 23.733 ;
     RECT  32.512 23.669 33.544 23.797 ;
     RECT  57.024 23.541 57.056 23.797 ;
     RECT  49.456 22.507 49.744 23.861 ;
     RECT  57.024 23.797 57.632 23.861 ;
     RECT  0.192 23.733 3.68 23.915 ;
     RECT  38.656 21.739 38.944 23.925 ;
     RECT  0.856 23.915 3.68 23.979 ;
     RECT  26.368 22.453 26.4 23.979 ;
     RECT  14.592 23.541 14.624 24.043 ;
     RECT  18.688 22.443 19.36 24.043 ;
     RECT  0.856 23.979 2.208 24.107 ;
     RECT  49.456 23.861 49.952 24.117 ;
     RECT  54.856 19.563 55.144 24.181 ;
     RECT  17.056 23.723 17.344 24.245 ;
     RECT  38.656 23.925 39.392 24.245 ;
     RECT  44.056 23.019 44.344 24.309 ;
     RECT  0.856 24.107 1.568 24.363 ;
     RECT  49.456 24.117 50.912 24.373 ;
     RECT  11.656 21.867 11.944 24.437 ;
     RECT  13.824 24.373 13.856 24.437 ;
     RECT  46.976 24.309 47.008 24.437 ;
     RECT  31.552 23.797 33.544 24.875 ;
     RECT  46.848 24.437 47.008 24.949 ;
     RECT  46.528 24.949 47.008 25.013 ;
     RECT  59.52 23.541 60.544 25.131 ;
     RECT  0.856 24.363 1.376 25.195 ;
     RECT  49.456 24.373 51.36 25.525 ;
     RECT  62.656 23.733 62.816 25.525 ;
     RECT  64.128 24.117 64.16 25.525 ;
     RECT  65.656 19.499 65.944 25.589 ;
     RECT  59.84 25.131 60.544 25.653 ;
     RECT  62.656 25.525 64.16 25.653 ;
     RECT  10.176 23.723 10.208 25.707 ;
     RECT  27.856 22.453 28.384 25.899 ;
     RECT  49.344 25.525 51.36 25.909 ;
     RECT  3.648 23.979 3.68 25.963 ;
     RECT  38.656 24.245 40.48 25.973 ;
     RECT  56.768 23.861 57.632 26.027 ;
     RECT  59.84 25.653 64.16 26.101 ;
     RECT  65.656 25.589 66.08 26.101 ;
     RECT  22.456 22.507 23.84 26.165 ;
     RECT  27.856 25.899 28.144 26.165 ;
     RECT  31.552 24.875 31.584 26.165 ;
     RECT  46.528 25.013 47.2 26.165 ;
     RECT  49.344 25.909 52.256 26.283 ;
     RECT  57.024 26.027 57.632 26.283 ;
     RECT  38.528 25.973 40.48 26.411 ;
     RECT  54.72 24.181 55.144 26.411 ;
     RECT  11.656 24.437 13.856 26.421 ;
     RECT  11.072 26.421 13.856 26.475 ;
     RECT  59.84 26.101 66.08 26.539 ;
     RECT  57.6 26.283 57.632 26.603 ;
     RECT  30.272 26.165 31.584 26.731 ;
     RECT  68.224 23.861 68.256 26.741 ;
     RECT  17.056 24.245 18.272 27.115 ;
     RECT  38.528 26.411 39.52 27.115 ;
     RECT  67.52 26.741 68.256 27.189 ;
     RECT  27.712 26.165 28.144 27.253 ;
     RECT  35.968 23.595 36.256 27.307 ;
     RECT  22.456 26.165 24.16 27.317 ;
     RECT  67.52 27.189 69.152 27.317 ;
     RECT  22.336 27.317 24.16 27.371 ;
     RECT  59.968 26.539 66.08 27.381 ;
     RECT  24.128 27.371 24.16 27.435 ;
     RECT  67.52 27.317 69.28 27.499 ;
     RECT  38.528 27.115 39.392 27.563 ;
     RECT  46.528 26.165 47.264 27.563 ;
     RECT  68.224 27.499 69.28 27.573 ;
     RECT  59.968 27.381 66.208 27.627 ;
     RECT  49.456 26.283 52.256 27.755 ;
     RECT  11.072 26.475 13.088 27.829 ;
     RECT  33.256 24.875 33.544 27.829 ;
     RECT  54.856 26.411 55.144 27.829 ;
     RECT  46.528 27.563 47.2 27.883 ;
     RECT  59.968 27.627 65.944 27.883 ;
     RECT  68.224 27.573 69.536 27.883 ;
     RECT  68.928 27.883 69.536 28.277 ;
     RECT  71.056 0.531 71.344 28.277 ;
     RECT  59.968 27.883 60.96 28.459 ;
     RECT  68.928 28.277 71.344 28.459 ;
     RECT  8.96 27.829 13.088 28.981 ;
     RECT  17.056 27.115 17.344 28.981 ;
     RECT  30.272 26.731 30.304 29.035 ;
     RECT  69.12 28.459 69.664 29.035 ;
     RECT  8.96 28.981 14.24 29.045 ;
     RECT  49.456 27.755 52.128 29.045 ;
     RECT  54.08 27.829 56.16 29.045 ;
     RECT  22.336 27.371 22.744 29.163 ;
     RECT  35.968 27.307 36.128 29.163 ;
     RECT  62.976 27.883 63.584 29.291 ;
     RECT  69.248 29.035 69.664 29.291 ;
     RECT  38.656 27.563 39.392 29.301 ;
     RECT  49.456 29.045 56.16 29.365 ;
     RECT  57.6 28.405 57.632 29.365 ;
     RECT  43.904 24.309 44.344 29.429 ;
     RECT  46.528 27.883 46.88 29.557 ;
     RECT  60.032 28.459 60.96 29.557 ;
     RECT  32.512 27.829 33.544 29.621 ;
     RECT  38.656 29.301 39.52 29.621 ;
     RECT  27.136 27.253 28.144 29.739 ;
     RECT  8.96 29.045 14.368 29.803 ;
     RECT  63.552 29.291 63.584 29.803 ;
     RECT  57.6 29.365 58.208 29.813 ;
     RECT  60.032 29.557 61.024 29.813 ;
     RECT  65.408 27.883 65.944 29.877 ;
     RECT  69.632 29.291 69.664 30.005 ;
     RECT  71.056 28.459 71.344 30.005 ;
     RECT  38.656 29.621 39.648 30.123 ;
     RECT  11.072 29.803 14.368 30.133 ;
     RECT  16.512 28.981 17.344 30.133 ;
     RECT  19.328 28.981 20.064 30.133 ;
     RECT  57.6 29.813 61.024 30.187 ;
     RECT  42.88 29.429 44.344 30.197 ;
     RECT  46.528 29.557 47.008 30.197 ;
     RECT  46.4 30.197 47.008 30.251 ;
     RECT  49.344 29.365 56.16 30.261 ;
     RECT  57.6 30.187 57.76 30.261 ;
     RECT  32.512 29.621 34.336 30.325 ;
     RECT  46.4 30.251 46.624 30.443 ;
     RECT  29.824 29.493 29.856 30.507 ;
     RECT  46.592 30.443 46.624 30.507 ;
     RECT  49.152 30.261 57.76 30.507 ;
     RECT  32.064 30.325 34.336 30.517 ;
     RECT  0.856 25.195 1.144 30.581 ;
     RECT  42.752 30.197 44.344 30.581 ;
     RECT  38.656 30.123 39.52 30.635 ;
     RECT  42.752 30.581 45.024 30.709 ;
     RECT  11.072 30.133 14.688 30.763 ;
     RECT  49.152 30.507 53.408 30.773 ;
     RECT  49.088 30.773 53.408 30.827 ;
     RECT  69.632 30.005 71.344 30.827 ;
     RECT  49.088 30.827 52.128 30.901 ;
     RECT  69.824 30.827 71.344 30.965 ;
     RECT  26.176 29.813 26.208 31.083 ;
     RECT  49.024 30.901 52.128 31.147 ;
     RECT  65.088 29.877 65.944 31.147 ;
     RECT  18.752 30.133 20.064 31.221 ;
     RECT  22.456 29.163 22.744 31.221 ;
     RECT  49.024 31.147 51.936 31.275 ;
     RECT  68.096 30.581 68.128 31.285 ;
     RECT  11.072 30.763 12.96 31.403 ;
     RECT  49.152 31.275 51.936 31.403 ;
     RECT  59.264 30.187 61.024 31.403 ;
     RECT  69.824 30.965 71.84 31.413 ;
     RECT  18.752 31.221 22.744 31.467 ;
     RECT  49.456 31.403 51.936 31.467 ;
     RECT  8.96 29.803 8.992 31.595 ;
     RECT  54.856 30.507 57.76 31.595 ;
     RECT  19.328 31.467 22.744 31.659 ;
     RECT  31.872 30.517 34.336 31.669 ;
     RECT  65.536 31.147 65.944 31.723 ;
     RECT  69.824 31.413 72.608 31.733 ;
     RECT  59.84 31.403 61.024 31.787 ;
     RECT  69.824 31.733 72.672 31.851 ;
     RECT  6.256 22.507 6.544 31.861 ;
     RECT  31.488 31.669 34.336 31.925 ;
     RECT  35.968 29.163 36 31.925 ;
     RECT  54.856 31.595 56.992 31.925 ;
     RECT  20.032 31.659 22.744 31.979 ;
     RECT  24.896 31.221 25.568 32.043 ;
     RECT  54.272 31.925 56.992 32.117 ;
     RECT  21.056 31.979 22.744 32.171 ;
     RECT  54.08 32.117 56.992 32.363 ;
     RECT  9.28 31.861 9.312 32.373 ;
     RECT  68.096 31.285 68.448 32.373 ;
     RECT  16.064 30.133 17.344 32.427 ;
     RECT  42.176 30.709 45.024 32.437 ;
     RECT  59.84 31.787 60.544 32.491 ;
     RECT  30.016 31.797 30.048 32.555 ;
     RECT  41.408 32.437 45.024 32.555 ;
     RECT  31.488 31.925 36 32.619 ;
     RECT  14.656 30.763 14.688 32.683 ;
     RECT  25.024 32.043 25.568 32.747 ;
     RECT  51.136 31.467 51.936 32.747 ;
     RECT  41.408 32.555 44.448 32.875 ;
     RECT  47.36 31.861 47.392 33.003 ;
     RECT  11.136 31.403 12.96 33.013 ;
     RECT  41.408 32.875 42.208 33.013 ;
     RECT  0.064 30.581 1.144 33.067 ;
     RECT  33.024 32.619 36 33.067 ;
     RECT  31.488 32.619 31.52 33.131 ;
     RECT  44.056 32.875 44.448 33.131 ;
     RECT  22.456 32.171 22.744 33.141 ;
     RECT  35.968 33.067 36 33.141 ;
     RECT  38.656 30.635 39.2 33.195 ;
     RECT  41.024 33.013 42.208 33.195 ;
     RECT  49.456 31.467 49.744 33.269 ;
     RECT  51.136 32.747 51.168 33.269 ;
     RECT  16.896 32.427 17.344 33.323 ;
     RECT  54.08 32.363 55.904 33.323 ;
     RECT  49.456 33.269 51.168 33.835 ;
     RECT  17.056 33.323 17.344 33.845 ;
     RECT  21.056 32.171 21.088 33.845 ;
     RECT  54.08 33.323 55.144 33.845 ;
     RECT  60.096 32.491 60.544 33.845 ;
     RECT  67.968 32.373 68.448 33.845 ;
     RECT  19.2 33.845 21.088 33.899 ;
     RECT  70.144 31.851 72.672 34.101 ;
     RECT  11.136 33.013 13.088 34.357 ;
     RECT  38.656 33.195 38.944 34.421 ;
     RECT  35.968 33.141 36.32 34.475 ;
     RECT  41.024 33.195 41.44 34.475 ;
     RECT  25.024 32.747 25.056 34.539 ;
     RECT  53.568 33.845 55.144 34.539 ;
     RECT  9.28 32.373 9.376 34.603 ;
     RECT  54.336 34.539 55.144 34.613 ;
     RECT  6.256 31.861 7.84 34.667 ;
     RECT  67.84 33.845 68.448 34.667 ;
     RECT  54.336 34.613 56.352 34.677 ;
     RECT  33.024 33.067 33.544 34.731 ;
     RECT  54.336 34.677 56.416 34.731 ;
     RECT  60.096 33.845 61.6 34.731 ;
     RECT  4.928 32.949 4.96 34.859 ;
     RECT  19.2 33.899 20.256 34.987 ;
     RECT  19.2 34.987 19.232 35.115 ;
     RECT  17.056 33.845 17.888 35.125 ;
     RECT  33.256 34.731 33.544 35.125 ;
     RECT  44.056 33.131 44.344 35.125 ;
     RECT  49.456 33.835 49.744 35.125 ;
     RECT  51.264 34.357 51.296 35.125 ;
     RECT  9.28 34.603 9.312 35.307 ;
     RECT  27.52 29.739 28.144 35.371 ;
     RECT  70.144 34.101 72.736 35.371 ;
     RECT  38.528 34.421 38.944 35.435 ;
     RECT  22.456 33.141 23.712 35.499 ;
     RECT  11.072 34.357 13.088 35.691 ;
     RECT  60.096 34.731 60.544 35.883 ;
     RECT  49.456 35.125 51.296 35.893 ;
     RECT  70.144 35.371 72.544 35.947 ;
     RECT  54.856 34.731 56.416 35.957 ;
     RECT  22.456 35.499 23.2 36.011 ;
     RECT  54.856 35.957 57.056 36.011 ;
     RECT  41.024 34.475 41.376 36.021 ;
     RECT  15.36 35.189 15.392 36.139 ;
     RECT  29.888 33.077 29.92 36.139 ;
     RECT  40.512 36.021 41.376 36.149 ;
     RECT  48.768 35.893 51.296 36.149 ;
     RECT  44.056 35.125 44.448 36.213 ;
     RECT  63.872 34.677 63.904 36.267 ;
     RECT  38.656 35.435 38.944 36.405 ;
     RECT  40.512 36.149 41.504 36.405 ;
     RECT  65.656 31.723 65.944 36.405 ;
     RECT  67.84 34.667 68.384 36.405 ;
     RECT  33.256 35.125 34.208 36.459 ;
     RECT  11.072 35.691 11.944 36.523 ;
     RECT  48.768 36.149 51.36 36.523 ;
     RECT  65.656 36.405 68.384 36.533 ;
     RECT  46.592 35.125 46.624 36.651 ;
     RECT  65.536 36.533 68.384 36.715 ;
     RECT  60.256 35.883 60.544 36.789 ;
     RECT  43.84 36.213 44.448 36.981 ;
     RECT  57.024 36.011 57.056 37.099 ;
     RECT  58.688 35.829 58.72 37.099 ;
     RECT  38.656 36.405 41.504 37.227 ;
     RECT  70.144 35.947 71.968 37.301 ;
     RECT  69.056 37.301 71.968 37.483 ;
     RECT  38.656 37.227 39.776 37.557 ;
     RECT  43.712 36.981 44.448 37.557 ;
     RECT  51.136 36.523 51.36 37.675 ;
     RECT  46.144 36.981 46.176 37.739 ;
     RECT  41.472 37.227 41.504 37.803 ;
     RECT  48.768 36.523 49.744 37.867 ;
     RECT  58.816 37.365 58.848 37.867 ;
     RECT  60.256 36.789 61.024 37.867 ;
     RECT  70.144 37.483 71.968 37.931 ;
     RECT  11.328 36.523 11.944 38.005 ;
     RECT  65.536 36.715 67.168 38.123 ;
     RECT  51.136 37.675 51.168 38.251 ;
     RECT  65.656 38.123 67.168 38.251 ;
     RECT  70.144 37.931 71.712 38.251 ;
     RECT  30.08 37.557 30.112 38.379 ;
     RECT  70.656 38.251 71.456 38.379 ;
     RECT  71.056 38.379 71.456 38.443 ;
     RECT  11.328 38.005 12.832 38.571 ;
     RECT  43.072 37.557 44.768 38.635 ;
     RECT  21.056 37.557 21.088 39.211 ;
     RECT  65.656 38.251 66.08 39.211 ;
     RECT  38.464 37.557 39.776 39.275 ;
     RECT  11.656 38.571 12.832 39.787 ;
     RECT  17.056 35.125 18.08 39.851 ;
     RECT  38.656 39.275 39.776 39.915 ;
     RECT  43.072 38.635 44.344 39.979 ;
     RECT  35.968 34.475 36 40.171 ;
     RECT  0.856 33.067 1.144 40.239 ;
     RECT  6.256 34.667 6.544 40.239 ;
     RECT  11.656 39.787 11.944 40.239 ;
     RECT  17.056 39.851 17.344 40.239 ;
     RECT  22.456 36.011 22.744 40.239 ;
     RECT  27.856 35.371 28.144 40.239 ;
     RECT  33.256 36.459 33.544 40.239 ;
     RECT  38.656 39.915 38.944 40.239 ;
     RECT  44.056 39.979 44.344 40.239 ;
     RECT  49.456 37.867 49.744 40.239 ;
     RECT  54.856 36.011 55.144 40.239 ;
     RECT  60.256 37.867 60.544 40.239 ;
     RECT  65.656 39.211 65.944 40.239 ;
     RECT  71.056 38.443 71.344 40.239 ;
  END
END hfd_stn_r31
END LIBRARY
